VERSION 5.8 ;
BUSBITCHARS "[]" ;
DIVIDERCHAR "/" ;
UNITS
    DATABASE MICRONS 1000 ;
END UNITS

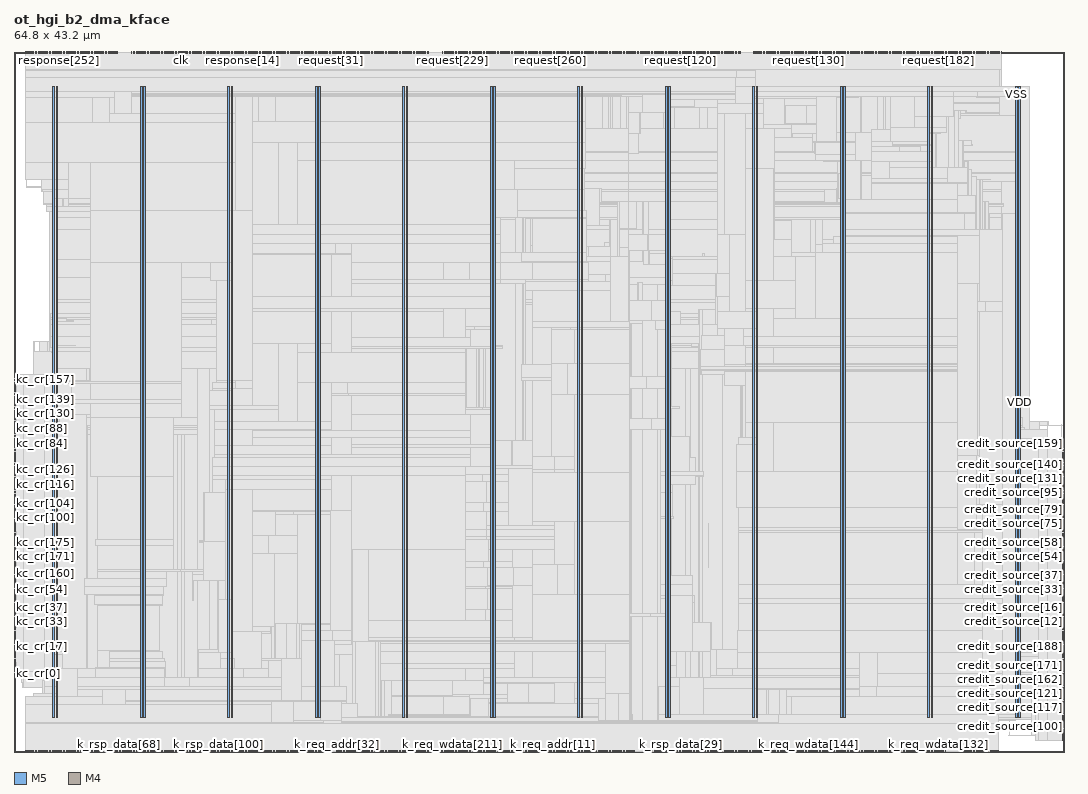
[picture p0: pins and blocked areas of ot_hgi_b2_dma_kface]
MACRO ot_hgi_b2_dma_kface
  FOREIGN ot_hgi_b2_dma_kface 0 0 ;
  CLASS BLOCK ;
  SIZE 64.8 BY 43.2 ;
  PIN clk
    DIRECTION INPUT ;
    USE SIGNAL ;
    PORT
      LAYER M5 ;
        RECT  10.32 43.116 10.344 43.2 ;
    END
  END clk
  PIN credit_source[0]
    DIRECTION INPUT ;
    USE SIGNAL ;
    PORT
      LAYER M4 ;
        RECT  64.716 6.864 64.8 6.888 ;
    END
  END credit_source[0]
  PIN credit_source[100]
    DIRECTION INPUT ;
    USE SIGNAL ;
    PORT
      LAYER M4 ;
        RECT  64.716 1.104 64.8 1.128 ;
    END
  END credit_source[100]
  PIN credit_source[101]
    DIRECTION INPUT ;
    USE SIGNAL ;
    PORT
      LAYER M4 ;
        RECT  64.716 1.2 64.8 1.224 ;
    END
  END credit_source[101]
  PIN credit_source[102]
    DIRECTION INPUT ;
    USE SIGNAL ;
    PORT
      LAYER M4 ;
        RECT  64.716 1.296 64.8 1.32 ;
    END
  END credit_source[102]
  PIN credit_source[103]
    DIRECTION INPUT ;
    USE SIGNAL ;
    PORT
      LAYER M4 ;
        RECT  64.716 1.392 64.8 1.416 ;
    END
  END credit_source[103]
  PIN credit_source[104]
    DIRECTION INPUT ;
    USE SIGNAL ;
    PORT
      LAYER M4 ;
        RECT  64.716 1.488 64.8 1.512 ;
    END
  END credit_source[104]
  PIN credit_source[105]
    DIRECTION INPUT ;
    USE SIGNAL ;
    PORT
      LAYER M4 ;
        RECT  64.716 1.584 64.8 1.608 ;
    END
  END credit_source[105]
  PIN credit_source[106]
    DIRECTION INPUT ;
    USE SIGNAL ;
    PORT
      LAYER M4 ;
        RECT  64.716 1.68 64.8 1.704 ;
    END
  END credit_source[106]
  PIN credit_source[107]
    DIRECTION INPUT ;
    USE SIGNAL ;
    PORT
      LAYER M4 ;
        RECT  64.716 1.776 64.8 1.8 ;
    END
  END credit_source[107]
  PIN credit_source[108]
    DIRECTION INPUT ;
    USE SIGNAL ;
    PORT
      LAYER M4 ;
        RECT  64.716 1.872 64.8 1.896 ;
    END
  END credit_source[108]
  PIN credit_source[109]
    DIRECTION INPUT ;
    USE SIGNAL ;
    PORT
      LAYER M4 ;
        RECT  64.716 1.968 64.8 1.992 ;
    END
  END credit_source[109]
  PIN credit_source[10]
    DIRECTION INPUT ;
    USE SIGNAL ;
    PORT
      LAYER M4 ;
        RECT  64.716 7.824 64.8 7.848 ;
    END
  END credit_source[10]
  PIN credit_source[110]
    DIRECTION INPUT ;
    USE SIGNAL ;
    PORT
      LAYER M4 ;
        RECT  64.716 2.064 64.8 2.088 ;
    END
  END credit_source[110]
  PIN credit_source[111]
    DIRECTION INPUT ;
    USE SIGNAL ;
    PORT
      LAYER M4 ;
        RECT  64.716 2.16 64.8 2.184 ;
    END
  END credit_source[111]
  PIN credit_source[112]
    DIRECTION INPUT ;
    USE SIGNAL ;
    PORT
      LAYER M4 ;
        RECT  64.716 2.256 64.8 2.28 ;
    END
  END credit_source[112]
  PIN credit_source[113]
    DIRECTION INPUT ;
    USE SIGNAL ;
    PORT
      LAYER M4 ;
        RECT  64.716 2.352 64.8 2.376 ;
    END
  END credit_source[113]
  PIN credit_source[114]
    DIRECTION INPUT ;
    USE SIGNAL ;
    PORT
      LAYER M4 ;
        RECT  64.716 2.448 64.8 2.472 ;
    END
  END credit_source[114]
  PIN credit_source[115]
    DIRECTION INPUT ;
    USE SIGNAL ;
    PORT
      LAYER M4 ;
        RECT  64.716 2.544 64.8 2.568 ;
    END
  END credit_source[115]
  PIN credit_source[116]
    DIRECTION INPUT ;
    USE SIGNAL ;
    PORT
      LAYER M4 ;
        RECT  64.716 2.64 64.8 2.664 ;
    END
  END credit_source[116]
  PIN credit_source[117]
    DIRECTION INPUT ;
    USE SIGNAL ;
    PORT
      LAYER M4 ;
        RECT  64.716 2.736 64.8 2.76 ;
    END
  END credit_source[117]
  PIN credit_source[118]
    DIRECTION INPUT ;
    USE SIGNAL ;
    PORT
      LAYER M4 ;
        RECT  64.716 2.832 64.8 2.856 ;
    END
  END credit_source[118]
  PIN credit_source[119]
    DIRECTION INPUT ;
    USE SIGNAL ;
    PORT
      LAYER M4 ;
        RECT  64.716 2.928 64.8 2.952 ;
    END
  END credit_source[119]
  PIN credit_source[11]
    DIRECTION INPUT ;
    USE SIGNAL ;
    PORT
      LAYER M4 ;
        RECT  64.716 7.92 64.8 7.944 ;
    END
  END credit_source[11]
  PIN credit_source[120]
    DIRECTION INPUT ;
    USE SIGNAL ;
    PORT
      LAYER M4 ;
        RECT  64.716 3.024 64.8 3.048 ;
    END
  END credit_source[120]
  PIN credit_source[121]
    DIRECTION INPUT ;
    USE SIGNAL ;
    PORT
      LAYER M4 ;
        RECT  64.716 3.12 64.8 3.144 ;
    END
  END credit_source[121]
  PIN credit_source[122]
    DIRECTION INPUT ;
    USE SIGNAL ;
    PORT
      LAYER M4 ;
        RECT  64.716 3.216 64.8 3.24 ;
    END
  END credit_source[122]
  PIN credit_source[123]
    DIRECTION INPUT ;
    USE SIGNAL ;
    PORT
      LAYER M4 ;
        RECT  64.716 3.312 64.8 3.336 ;
    END
  END credit_source[123]
  PIN credit_source[124]
    DIRECTION INPUT ;
    USE SIGNAL ;
    PORT
      LAYER M4 ;
        RECT  64.716 3.408 64.8 3.432 ;
    END
  END credit_source[124]
  PIN credit_source[125]
    DIRECTION INPUT ;
    USE SIGNAL ;
    PORT
      LAYER M4 ;
        RECT  64.716 3.504 64.8 3.528 ;
    END
  END credit_source[125]
  PIN credit_source[126]
    DIRECTION INPUT ;
    USE SIGNAL ;
    PORT
      LAYER M4 ;
        RECT  64.716 3.6 64.8 3.624 ;
    END
  END credit_source[126]
  PIN credit_source[127]
    DIRECTION INPUT ;
    USE SIGNAL ;
    PORT
      LAYER M4 ;
        RECT  64.716 3.696 64.8 3.72 ;
    END
  END credit_source[127]
  PIN credit_source[128]
    DIRECTION INPUT ;
    USE SIGNAL ;
    PORT
      LAYER M4 ;
        RECT  64.716 16.08 64.8 16.104 ;
    END
  END credit_source[128]
  PIN credit_source[129]
    DIRECTION INPUT ;
    USE SIGNAL ;
    PORT
      LAYER M4 ;
        RECT  64.716 16.176 64.8 16.2 ;
    END
  END credit_source[129]
  PIN credit_source[12]
    DIRECTION INPUT ;
    USE SIGNAL ;
    PORT
      LAYER M4 ;
        RECT  64.716 8.016 64.8 8.04 ;
    END
  END credit_source[12]
  PIN credit_source[130]
    DIRECTION INPUT ;
    USE SIGNAL ;
    PORT
      LAYER M4 ;
        RECT  64.716 16.272 64.8 16.296 ;
    END
  END credit_source[130]
  PIN credit_source[131]
    DIRECTION INPUT ;
    USE SIGNAL ;
    PORT
      LAYER M4 ;
        RECT  64.716 16.368 64.8 16.392 ;
    END
  END credit_source[131]
  PIN credit_source[132]
    DIRECTION INPUT ;
    USE SIGNAL ;
    PORT
      LAYER M4 ;
        RECT  64.716 16.464 64.8 16.488 ;
    END
  END credit_source[132]
  PIN credit_source[133]
    DIRECTION INPUT ;
    USE SIGNAL ;
    PORT
      LAYER M4 ;
        RECT  64.716 16.56 64.8 16.584 ;
    END
  END credit_source[133]
  PIN credit_source[134]
    DIRECTION INPUT ;
    USE SIGNAL ;
    PORT
      LAYER M4 ;
        RECT  64.716 16.656 64.8 16.68 ;
    END
  END credit_source[134]
  PIN credit_source[135]
    DIRECTION INPUT ;
    USE SIGNAL ;
    PORT
      LAYER M4 ;
        RECT  64.716 16.752 64.8 16.776 ;
    END
  END credit_source[135]
  PIN credit_source[136]
    DIRECTION INPUT ;
    USE SIGNAL ;
    PORT
      LAYER M4 ;
        RECT  64.716 16.848 64.8 16.872 ;
    END
  END credit_source[136]
  PIN credit_source[137]
    DIRECTION INPUT ;
    USE SIGNAL ;
    PORT
      LAYER M4 ;
        RECT  64.716 16.944 64.8 16.968 ;
    END
  END credit_source[137]
  PIN credit_source[138]
    DIRECTION INPUT ;
    USE SIGNAL ;
    PORT
      LAYER M4 ;
        RECT  64.716 17.04 64.8 17.064 ;
    END
  END credit_source[138]
  PIN credit_source[139]
    DIRECTION INPUT ;
    USE SIGNAL ;
    PORT
      LAYER M4 ;
        RECT  64.716 17.136 64.8 17.16 ;
    END
  END credit_source[139]
  PIN credit_source[13]
    DIRECTION INPUT ;
    USE SIGNAL ;
    PORT
      LAYER M4 ;
        RECT  64.716 8.112 64.8 8.136 ;
    END
  END credit_source[13]
  PIN credit_source[140]
    DIRECTION INPUT ;
    USE SIGNAL ;
    PORT
      LAYER M4 ;
        RECT  64.716 17.232 64.8 17.256 ;
    END
  END credit_source[140]
  PIN credit_source[141]
    DIRECTION INPUT ;
    USE SIGNAL ;
    PORT
      LAYER M4 ;
        RECT  64.716 17.328 64.8 17.352 ;
    END
  END credit_source[141]
  PIN credit_source[142]
    DIRECTION INPUT ;
    USE SIGNAL ;
    PORT
      LAYER M4 ;
        RECT  64.716 17.424 64.8 17.448 ;
    END
  END credit_source[142]
  PIN credit_source[143]
    DIRECTION INPUT ;
    USE SIGNAL ;
    PORT
      LAYER M4 ;
        RECT  64.716 17.52 64.8 17.544 ;
    END
  END credit_source[143]
  PIN credit_source[144]
    DIRECTION INPUT ;
    USE SIGNAL ;
    PORT
      LAYER M4 ;
        RECT  64.716 17.616 64.8 17.64 ;
    END
  END credit_source[144]
  PIN credit_source[145]
    DIRECTION INPUT ;
    USE SIGNAL ;
    PORT
      LAYER M4 ;
        RECT  64.716 17.712 64.8 17.736 ;
    END
  END credit_source[145]
  PIN credit_source[146]
    DIRECTION INPUT ;
    USE SIGNAL ;
    PORT
      LAYER M4 ;
        RECT  64.716 17.808 64.8 17.832 ;
    END
  END credit_source[146]
  PIN credit_source[147]
    DIRECTION INPUT ;
    USE SIGNAL ;
    PORT
      LAYER M4 ;
        RECT  64.716 17.904 64.8 17.928 ;
    END
  END credit_source[147]
  PIN credit_source[148]
    DIRECTION INPUT ;
    USE SIGNAL ;
    PORT
      LAYER M4 ;
        RECT  64.716 18 64.8 18.024 ;
    END
  END credit_source[148]
  PIN credit_source[149]
    DIRECTION INPUT ;
    USE SIGNAL ;
    PORT
      LAYER M4 ;
        RECT  64.716 18.096 64.8 18.12 ;
    END
  END credit_source[149]
  PIN credit_source[14]
    DIRECTION INPUT ;
    USE SIGNAL ;
    PORT
      LAYER M4 ;
        RECT  64.716 8.208 64.8 8.232 ;
    END
  END credit_source[14]
  PIN credit_source[150]
    DIRECTION INPUT ;
    USE SIGNAL ;
    PORT
      LAYER M4 ;
        RECT  64.716 18.192 64.8 18.216 ;
    END
  END credit_source[150]
  PIN credit_source[151]
    DIRECTION INPUT ;
    USE SIGNAL ;
    PORT
      LAYER M4 ;
        RECT  64.716 18.288 64.8 18.312 ;
    END
  END credit_source[151]
  PIN credit_source[152]
    DIRECTION INPUT ;
    USE SIGNAL ;
    PORT
      LAYER M4 ;
        RECT  64.716 18.384 64.8 18.408 ;
    END
  END credit_source[152]
  PIN credit_source[153]
    DIRECTION INPUT ;
    USE SIGNAL ;
    PORT
      LAYER M4 ;
        RECT  64.716 18.48 64.8 18.504 ;
    END
  END credit_source[153]
  PIN credit_source[154]
    DIRECTION INPUT ;
    USE SIGNAL ;
    PORT
      LAYER M4 ;
        RECT  64.716 18.576 64.8 18.6 ;
    END
  END credit_source[154]
  PIN credit_source[155]
    DIRECTION INPUT ;
    USE SIGNAL ;
    PORT
      LAYER M4 ;
        RECT  64.716 18.672 64.8 18.696 ;
    END
  END credit_source[155]
  PIN credit_source[156]
    DIRECTION INPUT ;
    USE SIGNAL ;
    PORT
      LAYER M4 ;
        RECT  64.716 18.768 64.8 18.792 ;
    END
  END credit_source[156]
  PIN credit_source[157]
    DIRECTION INPUT ;
    USE SIGNAL ;
    PORT
      LAYER M4 ;
        RECT  64.716 18.864 64.8 18.888 ;
    END
  END credit_source[157]
  PIN credit_source[158]
    DIRECTION INPUT ;
    USE SIGNAL ;
    PORT
      LAYER M4 ;
        RECT  64.716 18.96 64.8 18.984 ;
    END
  END credit_source[158]
  PIN credit_source[159]
    DIRECTION INPUT ;
    USE SIGNAL ;
    PORT
      LAYER M4 ;
        RECT  64.716 19.056 64.8 19.08 ;
    END
  END credit_source[159]
  PIN credit_source[15]
    DIRECTION INPUT ;
    USE SIGNAL ;
    PORT
      LAYER M4 ;
        RECT  64.716 8.304 64.8 8.328 ;
    END
  END credit_source[15]
  PIN credit_source[160]
    DIRECTION INPUT ;
    USE SIGNAL ;
    PORT
      LAYER M4 ;
        RECT  64.716 3.792 64.8 3.816 ;
    END
  END credit_source[160]
  PIN credit_source[161]
    DIRECTION INPUT ;
    USE SIGNAL ;
    PORT
      LAYER M4 ;
        RECT  64.716 3.888 64.8 3.912 ;
    END
  END credit_source[161]
  PIN credit_source[162]
    DIRECTION INPUT ;
    USE SIGNAL ;
    PORT
      LAYER M4 ;
        RECT  64.716 3.984 64.8 4.008 ;
    END
  END credit_source[162]
  PIN credit_source[163]
    DIRECTION INPUT ;
    USE SIGNAL ;
    PORT
      LAYER M4 ;
        RECT  64.716 4.08 64.8 4.104 ;
    END
  END credit_source[163]
  PIN credit_source[164]
    DIRECTION INPUT ;
    USE SIGNAL ;
    PORT
      LAYER M4 ;
        RECT  64.716 4.176 64.8 4.2 ;
    END
  END credit_source[164]
  PIN credit_source[165]
    DIRECTION INPUT ;
    USE SIGNAL ;
    PORT
      LAYER M4 ;
        RECT  64.716 4.272 64.8 4.296 ;
    END
  END credit_source[165]
  PIN credit_source[166]
    DIRECTION INPUT ;
    USE SIGNAL ;
    PORT
      LAYER M4 ;
        RECT  64.716 4.368 64.8 4.392 ;
    END
  END credit_source[166]
  PIN credit_source[167]
    DIRECTION INPUT ;
    USE SIGNAL ;
    PORT
      LAYER M4 ;
        RECT  64.716 4.464 64.8 4.488 ;
    END
  END credit_source[167]
  PIN credit_source[168]
    DIRECTION INPUT ;
    USE SIGNAL ;
    PORT
      LAYER M4 ;
        RECT  64.716 4.56 64.8 4.584 ;
    END
  END credit_source[168]
  PIN credit_source[169]
    DIRECTION INPUT ;
    USE SIGNAL ;
    PORT
      LAYER M4 ;
        RECT  64.716 4.656 64.8 4.68 ;
    END
  END credit_source[169]
  PIN credit_source[16]
    DIRECTION INPUT ;
    USE SIGNAL ;
    PORT
      LAYER M4 ;
        RECT  64.716 8.4 64.8 8.424 ;
    END
  END credit_source[16]
  PIN credit_source[170]
    DIRECTION INPUT ;
    USE SIGNAL ;
    PORT
      LAYER M4 ;
        RECT  64.716 4.752 64.8 4.776 ;
    END
  END credit_source[170]
  PIN credit_source[171]
    DIRECTION INPUT ;
    USE SIGNAL ;
    PORT
      LAYER M4 ;
        RECT  64.716 4.848 64.8 4.872 ;
    END
  END credit_source[171]
  PIN credit_source[172]
    DIRECTION INPUT ;
    USE SIGNAL ;
    PORT
      LAYER M4 ;
        RECT  64.716 4.944 64.8 4.968 ;
    END
  END credit_source[172]
  PIN credit_source[173]
    DIRECTION INPUT ;
    USE SIGNAL ;
    PORT
      LAYER M4 ;
        RECT  64.716 5.04 64.8 5.064 ;
    END
  END credit_source[173]
  PIN credit_source[174]
    DIRECTION INPUT ;
    USE SIGNAL ;
    PORT
      LAYER M4 ;
        RECT  64.716 5.136 64.8 5.16 ;
    END
  END credit_source[174]
  PIN credit_source[175]
    DIRECTION INPUT ;
    USE SIGNAL ;
    PORT
      LAYER M4 ;
        RECT  64.716 5.232 64.8 5.256 ;
    END
  END credit_source[175]
  PIN credit_source[176]
    DIRECTION INPUT ;
    USE SIGNAL ;
    PORT
      LAYER M4 ;
        RECT  64.716 5.328 64.8 5.352 ;
    END
  END credit_source[176]
  PIN credit_source[177]
    DIRECTION INPUT ;
    USE SIGNAL ;
    PORT
      LAYER M4 ;
        RECT  64.716 5.424 64.8 5.448 ;
    END
  END credit_source[177]
  PIN credit_source[178]
    DIRECTION INPUT ;
    USE SIGNAL ;
    PORT
      LAYER M4 ;
        RECT  64.716 5.52 64.8 5.544 ;
    END
  END credit_source[178]
  PIN credit_source[179]
    DIRECTION INPUT ;
    USE SIGNAL ;
    PORT
      LAYER M4 ;
        RECT  64.716 5.616 64.8 5.64 ;
    END
  END credit_source[179]
  PIN credit_source[17]
    DIRECTION INPUT ;
    USE SIGNAL ;
    PORT
      LAYER M4 ;
        RECT  64.716 8.496 64.8 8.52 ;
    END
  END credit_source[17]
  PIN credit_source[180]
    DIRECTION INPUT ;
    USE SIGNAL ;
    PORT
      LAYER M4 ;
        RECT  64.716 5.712 64.8 5.736 ;
    END
  END credit_source[180]
  PIN credit_source[181]
    DIRECTION INPUT ;
    USE SIGNAL ;
    PORT
      LAYER M4 ;
        RECT  64.716 5.808 64.8 5.832 ;
    END
  END credit_source[181]
  PIN credit_source[182]
    DIRECTION INPUT ;
    USE SIGNAL ;
    PORT
      LAYER M4 ;
        RECT  64.716 5.904 64.8 5.928 ;
    END
  END credit_source[182]
  PIN credit_source[183]
    DIRECTION INPUT ;
    USE SIGNAL ;
    PORT
      LAYER M4 ;
        RECT  64.716 6 64.8 6.024 ;
    END
  END credit_source[183]
  PIN credit_source[184]
    DIRECTION INPUT ;
    USE SIGNAL ;
    PORT
      LAYER M4 ;
        RECT  64.716 6.096 64.8 6.12 ;
    END
  END credit_source[184]
  PIN credit_source[185]
    DIRECTION INPUT ;
    USE SIGNAL ;
    PORT
      LAYER M4 ;
        RECT  64.716 6.192 64.8 6.216 ;
    END
  END credit_source[185]
  PIN credit_source[186]
    DIRECTION INPUT ;
    USE SIGNAL ;
    PORT
      LAYER M4 ;
        RECT  64.716 6.288 64.8 6.312 ;
    END
  END credit_source[186]
  PIN credit_source[187]
    DIRECTION INPUT ;
    USE SIGNAL ;
    PORT
      LAYER M4 ;
        RECT  64.716 6.384 64.8 6.408 ;
    END
  END credit_source[187]
  PIN credit_source[188]
    DIRECTION INPUT ;
    USE SIGNAL ;
    PORT
      LAYER M4 ;
        RECT  64.716 6.48 64.8 6.504 ;
    END
  END credit_source[188]
  PIN credit_source[189]
    DIRECTION INPUT ;
    USE SIGNAL ;
    PORT
      LAYER M4 ;
        RECT  64.716 6.576 64.8 6.6 ;
    END
  END credit_source[189]
  PIN credit_source[18]
    DIRECTION INPUT ;
    USE SIGNAL ;
    PORT
      LAYER M4 ;
        RECT  64.716 8.592 64.8 8.616 ;
    END
  END credit_source[18]
  PIN credit_source[190]
    DIRECTION INPUT ;
    USE SIGNAL ;
    PORT
      LAYER M4 ;
        RECT  64.716 6.672 64.8 6.696 ;
    END
  END credit_source[190]
  PIN credit_source[191]
    DIRECTION INPUT ;
    USE SIGNAL ;
    PORT
      LAYER M4 ;
        RECT  64.716 6.768 64.8 6.792 ;
    END
  END credit_source[191]
  PIN credit_source[19]
    DIRECTION INPUT ;
    USE SIGNAL ;
    PORT
      LAYER M4 ;
        RECT  64.716 8.688 64.8 8.712 ;
    END
  END credit_source[19]
  PIN credit_source[1]
    DIRECTION INPUT ;
    USE SIGNAL ;
    PORT
      LAYER M4 ;
        RECT  64.716 6.96 64.8 6.984 ;
    END
  END credit_source[1]
  PIN credit_source[20]
    DIRECTION INPUT ;
    USE SIGNAL ;
    PORT
      LAYER M4 ;
        RECT  64.716 8.784 64.8 8.808 ;
    END
  END credit_source[20]
  PIN credit_source[21]
    DIRECTION INPUT ;
    USE SIGNAL ;
    PORT
      LAYER M4 ;
        RECT  64.716 8.88 64.8 8.904 ;
    END
  END credit_source[21]
  PIN credit_source[22]
    DIRECTION INPUT ;
    USE SIGNAL ;
    PORT
      LAYER M4 ;
        RECT  64.716 8.976 64.8 9 ;
    END
  END credit_source[22]
  PIN credit_source[23]
    DIRECTION INPUT ;
    USE SIGNAL ;
    PORT
      LAYER M4 ;
        RECT  64.716 9.072 64.8 9.096 ;
    END
  END credit_source[23]
  PIN credit_source[24]
    DIRECTION INPUT ;
    USE SIGNAL ;
    PORT
      LAYER M4 ;
        RECT  64.716 9.168 64.8 9.192 ;
    END
  END credit_source[24]
  PIN credit_source[25]
    DIRECTION INPUT ;
    USE SIGNAL ;
    PORT
      LAYER M4 ;
        RECT  64.716 9.264 64.8 9.288 ;
    END
  END credit_source[25]
  PIN credit_source[26]
    DIRECTION INPUT ;
    USE SIGNAL ;
    PORT
      LAYER M4 ;
        RECT  64.716 9.36 64.8 9.384 ;
    END
  END credit_source[26]
  PIN credit_source[27]
    DIRECTION INPUT ;
    USE SIGNAL ;
    PORT
      LAYER M4 ;
        RECT  64.716 9.456 64.8 9.48 ;
    END
  END credit_source[27]
  PIN credit_source[28]
    DIRECTION INPUT ;
    USE SIGNAL ;
    PORT
      LAYER M4 ;
        RECT  64.716 9.552 64.8 9.576 ;
    END
  END credit_source[28]
  PIN credit_source[29]
    DIRECTION INPUT ;
    USE SIGNAL ;
    PORT
      LAYER M4 ;
        RECT  64.716 9.648 64.8 9.672 ;
    END
  END credit_source[29]
  PIN credit_source[2]
    DIRECTION INPUT ;
    USE SIGNAL ;
    PORT
      LAYER M4 ;
        RECT  64.716 7.056 64.8 7.08 ;
    END
  END credit_source[2]
  PIN credit_source[30]
    DIRECTION INPUT ;
    USE SIGNAL ;
    PORT
      LAYER M4 ;
        RECT  64.716 9.744 64.8 9.768 ;
    END
  END credit_source[30]
  PIN credit_source[31]
    DIRECTION INPUT ;
    USE SIGNAL ;
    PORT
      LAYER M4 ;
        RECT  64.716 9.84 64.8 9.864 ;
    END
  END credit_source[31]
  PIN credit_source[32]
    DIRECTION INPUT ;
    USE SIGNAL ;
    PORT
      LAYER M4 ;
        RECT  64.716 9.936 64.8 9.96 ;
    END
  END credit_source[32]
  PIN credit_source[33]
    DIRECTION INPUT ;
    USE SIGNAL ;
    PORT
      LAYER M4 ;
        RECT  64.716 10.032 64.8 10.056 ;
    END
  END credit_source[33]
  PIN credit_source[34]
    DIRECTION INPUT ;
    USE SIGNAL ;
    PORT
      LAYER M4 ;
        RECT  64.716 10.128 64.8 10.152 ;
    END
  END credit_source[34]
  PIN credit_source[35]
    DIRECTION INPUT ;
    USE SIGNAL ;
    PORT
      LAYER M4 ;
        RECT  64.716 10.224 64.8 10.248 ;
    END
  END credit_source[35]
  PIN credit_source[36]
    DIRECTION INPUT ;
    USE SIGNAL ;
    PORT
      LAYER M4 ;
        RECT  64.716 10.32 64.8 10.344 ;
    END
  END credit_source[36]
  PIN credit_source[37]
    DIRECTION INPUT ;
    USE SIGNAL ;
    PORT
      LAYER M4 ;
        RECT  64.716 10.416 64.8 10.44 ;
    END
  END credit_source[37]
  PIN credit_source[38]
    DIRECTION INPUT ;
    USE SIGNAL ;
    PORT
      LAYER M4 ;
        RECT  64.716 10.512 64.8 10.536 ;
    END
  END credit_source[38]
  PIN credit_source[39]
    DIRECTION INPUT ;
    USE SIGNAL ;
    PORT
      LAYER M4 ;
        RECT  64.716 10.608 64.8 10.632 ;
    END
  END credit_source[39]
  PIN credit_source[3]
    DIRECTION INPUT ;
    USE SIGNAL ;
    PORT
      LAYER M4 ;
        RECT  64.716 7.152 64.8 7.176 ;
    END
  END credit_source[3]
  PIN credit_source[40]
    DIRECTION INPUT ;
    USE SIGNAL ;
    PORT
      LAYER M4 ;
        RECT  64.716 10.704 64.8 10.728 ;
    END
  END credit_source[40]
  PIN credit_source[41]
    DIRECTION INPUT ;
    USE SIGNAL ;
    PORT
      LAYER M4 ;
        RECT  64.716 10.8 64.8 10.824 ;
    END
  END credit_source[41]
  PIN credit_source[42]
    DIRECTION INPUT ;
    USE SIGNAL ;
    PORT
      LAYER M4 ;
        RECT  64.716 10.896 64.8 10.92 ;
    END
  END credit_source[42]
  PIN credit_source[43]
    DIRECTION INPUT ;
    USE SIGNAL ;
    PORT
      LAYER M4 ;
        RECT  64.716 10.992 64.8 11.016 ;
    END
  END credit_source[43]
  PIN credit_source[44]
    DIRECTION INPUT ;
    USE SIGNAL ;
    PORT
      LAYER M4 ;
        RECT  64.716 11.088 64.8 11.112 ;
    END
  END credit_source[44]
  PIN credit_source[45]
    DIRECTION INPUT ;
    USE SIGNAL ;
    PORT
      LAYER M4 ;
        RECT  64.716 11.184 64.8 11.208 ;
    END
  END credit_source[45]
  PIN credit_source[46]
    DIRECTION INPUT ;
    USE SIGNAL ;
    PORT
      LAYER M4 ;
        RECT  64.716 11.28 64.8 11.304 ;
    END
  END credit_source[46]
  PIN credit_source[47]
    DIRECTION INPUT ;
    USE SIGNAL ;
    PORT
      LAYER M4 ;
        RECT  64.716 11.376 64.8 11.4 ;
    END
  END credit_source[47]
  PIN credit_source[48]
    DIRECTION INPUT ;
    USE SIGNAL ;
    PORT
      LAYER M4 ;
        RECT  64.716 11.472 64.8 11.496 ;
    END
  END credit_source[48]
  PIN credit_source[49]
    DIRECTION INPUT ;
    USE SIGNAL ;
    PORT
      LAYER M4 ;
        RECT  64.716 11.568 64.8 11.592 ;
    END
  END credit_source[49]
  PIN credit_source[4]
    DIRECTION INPUT ;
    USE SIGNAL ;
    PORT
      LAYER M4 ;
        RECT  64.716 7.248 64.8 7.272 ;
    END
  END credit_source[4]
  PIN credit_source[50]
    DIRECTION INPUT ;
    USE SIGNAL ;
    PORT
      LAYER M4 ;
        RECT  64.716 11.664 64.8 11.688 ;
    END
  END credit_source[50]
  PIN credit_source[51]
    DIRECTION INPUT ;
    USE SIGNAL ;
    PORT
      LAYER M4 ;
        RECT  64.716 11.76 64.8 11.784 ;
    END
  END credit_source[51]
  PIN credit_source[52]
    DIRECTION INPUT ;
    USE SIGNAL ;
    PORT
      LAYER M4 ;
        RECT  64.716 11.856 64.8 11.88 ;
    END
  END credit_source[52]
  PIN credit_source[53]
    DIRECTION INPUT ;
    USE SIGNAL ;
    PORT
      LAYER M4 ;
        RECT  64.716 11.952 64.8 11.976 ;
    END
  END credit_source[53]
  PIN credit_source[54]
    DIRECTION INPUT ;
    USE SIGNAL ;
    PORT
      LAYER M4 ;
        RECT  64.716 12.048 64.8 12.072 ;
    END
  END credit_source[54]
  PIN credit_source[55]
    DIRECTION INPUT ;
    USE SIGNAL ;
    PORT
      LAYER M4 ;
        RECT  64.716 12.144 64.8 12.168 ;
    END
  END credit_source[55]
  PIN credit_source[56]
    DIRECTION INPUT ;
    USE SIGNAL ;
    PORT
      LAYER M4 ;
        RECT  64.716 12.24 64.8 12.264 ;
    END
  END credit_source[56]
  PIN credit_source[57]
    DIRECTION INPUT ;
    USE SIGNAL ;
    PORT
      LAYER M4 ;
        RECT  64.716 12.336 64.8 12.36 ;
    END
  END credit_source[57]
  PIN credit_source[58]
    DIRECTION INPUT ;
    USE SIGNAL ;
    PORT
      LAYER M4 ;
        RECT  64.716 12.432 64.8 12.456 ;
    END
  END credit_source[58]
  PIN credit_source[59]
    DIRECTION INPUT ;
    USE SIGNAL ;
    PORT
      LAYER M4 ;
        RECT  64.716 12.528 64.8 12.552 ;
    END
  END credit_source[59]
  PIN credit_source[5]
    DIRECTION INPUT ;
    USE SIGNAL ;
    PORT
      LAYER M4 ;
        RECT  64.716 7.344 64.8 7.368 ;
    END
  END credit_source[5]
  PIN credit_source[60]
    DIRECTION INPUT ;
    USE SIGNAL ;
    PORT
      LAYER M4 ;
        RECT  64.716 12.624 64.8 12.648 ;
    END
  END credit_source[60]
  PIN credit_source[61]
    DIRECTION INPUT ;
    USE SIGNAL ;
    PORT
      LAYER M4 ;
        RECT  64.716 12.72 64.8 12.744 ;
    END
  END credit_source[61]
  PIN credit_source[62]
    DIRECTION INPUT ;
    USE SIGNAL ;
    PORT
      LAYER M4 ;
        RECT  64.716 12.816 64.8 12.84 ;
    END
  END credit_source[62]
  PIN credit_source[63]
    DIRECTION INPUT ;
    USE SIGNAL ;
    PORT
      LAYER M4 ;
        RECT  64.716 12.912 64.8 12.936 ;
    END
  END credit_source[63]
  PIN credit_source[64]
    DIRECTION INPUT ;
    USE SIGNAL ;
    PORT
      LAYER M4 ;
        RECT  64.716 13.008 64.8 13.032 ;
    END
  END credit_source[64]
  PIN credit_source[65]
    DIRECTION INPUT ;
    USE SIGNAL ;
    PORT
      LAYER M4 ;
        RECT  64.716 13.104 64.8 13.128 ;
    END
  END credit_source[65]
  PIN credit_source[66]
    DIRECTION INPUT ;
    USE SIGNAL ;
    PORT
      LAYER M4 ;
        RECT  64.716 13.2 64.8 13.224 ;
    END
  END credit_source[66]
  PIN credit_source[67]
    DIRECTION INPUT ;
    USE SIGNAL ;
    PORT
      LAYER M4 ;
        RECT  64.716 13.296 64.8 13.32 ;
    END
  END credit_source[67]
  PIN credit_source[68]
    DIRECTION INPUT ;
    USE SIGNAL ;
    PORT
      LAYER M4 ;
        RECT  64.716 13.392 64.8 13.416 ;
    END
  END credit_source[68]
  PIN credit_source[69]
    DIRECTION INPUT ;
    USE SIGNAL ;
    PORT
      LAYER M4 ;
        RECT  64.716 13.488 64.8 13.512 ;
    END
  END credit_source[69]
  PIN credit_source[6]
    DIRECTION INPUT ;
    USE SIGNAL ;
    PORT
      LAYER M4 ;
        RECT  64.716 7.44 64.8 7.464 ;
    END
  END credit_source[6]
  PIN credit_source[70]
    DIRECTION INPUT ;
    USE SIGNAL ;
    PORT
      LAYER M4 ;
        RECT  64.716 13.584 64.8 13.608 ;
    END
  END credit_source[70]
  PIN credit_source[71]
    DIRECTION INPUT ;
    USE SIGNAL ;
    PORT
      LAYER M4 ;
        RECT  64.716 13.68 64.8 13.704 ;
    END
  END credit_source[71]
  PIN credit_source[72]
    DIRECTION INPUT ;
    USE SIGNAL ;
    PORT
      LAYER M4 ;
        RECT  64.716 13.776 64.8 13.8 ;
    END
  END credit_source[72]
  PIN credit_source[73]
    DIRECTION INPUT ;
    USE SIGNAL ;
    PORT
      LAYER M4 ;
        RECT  64.716 13.872 64.8 13.896 ;
    END
  END credit_source[73]
  PIN credit_source[74]
    DIRECTION INPUT ;
    USE SIGNAL ;
    PORT
      LAYER M4 ;
        RECT  64.716 13.968 64.8 13.992 ;
    END
  END credit_source[74]
  PIN credit_source[75]
    DIRECTION INPUT ;
    USE SIGNAL ;
    PORT
      LAYER M4 ;
        RECT  64.716 14.064 64.8 14.088 ;
    END
  END credit_source[75]
  PIN credit_source[76]
    DIRECTION INPUT ;
    USE SIGNAL ;
    PORT
      LAYER M4 ;
        RECT  64.716 14.16 64.8 14.184 ;
    END
  END credit_source[76]
  PIN credit_source[77]
    DIRECTION INPUT ;
    USE SIGNAL ;
    PORT
      LAYER M4 ;
        RECT  64.716 14.256 64.8 14.28 ;
    END
  END credit_source[77]
  PIN credit_source[78]
    DIRECTION INPUT ;
    USE SIGNAL ;
    PORT
      LAYER M4 ;
        RECT  64.716 14.352 64.8 14.376 ;
    END
  END credit_source[78]
  PIN credit_source[79]
    DIRECTION INPUT ;
    USE SIGNAL ;
    PORT
      LAYER M4 ;
        RECT  64.716 14.448 64.8 14.472 ;
    END
  END credit_source[79]
  PIN credit_source[7]
    DIRECTION INPUT ;
    USE SIGNAL ;
    PORT
      LAYER M4 ;
        RECT  64.716 7.536 64.8 7.56 ;
    END
  END credit_source[7]
  PIN credit_source[80]
    DIRECTION INPUT ;
    USE SIGNAL ;
    PORT
      LAYER M4 ;
        RECT  64.716 14.544 64.8 14.568 ;
    END
  END credit_source[80]
  PIN credit_source[81]
    DIRECTION INPUT ;
    USE SIGNAL ;
    PORT
      LAYER M4 ;
        RECT  64.716 14.64 64.8 14.664 ;
    END
  END credit_source[81]
  PIN credit_source[82]
    DIRECTION INPUT ;
    USE SIGNAL ;
    PORT
      LAYER M4 ;
        RECT  64.716 14.736 64.8 14.76 ;
    END
  END credit_source[82]
  PIN credit_source[83]
    DIRECTION INPUT ;
    USE SIGNAL ;
    PORT
      LAYER M4 ;
        RECT  64.716 14.832 64.8 14.856 ;
    END
  END credit_source[83]
  PIN credit_source[84]
    DIRECTION INPUT ;
    USE SIGNAL ;
    PORT
      LAYER M4 ;
        RECT  64.716 14.928 64.8 14.952 ;
    END
  END credit_source[84]
  PIN credit_source[85]
    DIRECTION INPUT ;
    USE SIGNAL ;
    PORT
      LAYER M4 ;
        RECT  64.716 15.024 64.8 15.048 ;
    END
  END credit_source[85]
  PIN credit_source[86]
    DIRECTION INPUT ;
    USE SIGNAL ;
    PORT
      LAYER M4 ;
        RECT  64.716 15.12 64.8 15.144 ;
    END
  END credit_source[86]
  PIN credit_source[87]
    DIRECTION INPUT ;
    USE SIGNAL ;
    PORT
      LAYER M4 ;
        RECT  64.716 15.216 64.8 15.24 ;
    END
  END credit_source[87]
  PIN credit_source[88]
    DIRECTION INPUT ;
    USE SIGNAL ;
    PORT
      LAYER M4 ;
        RECT  64.716 15.312 64.8 15.336 ;
    END
  END credit_source[88]
  PIN credit_source[89]
    DIRECTION INPUT ;
    USE SIGNAL ;
    PORT
      LAYER M4 ;
        RECT  64.716 15.408 64.8 15.432 ;
    END
  END credit_source[89]
  PIN credit_source[8]
    DIRECTION INPUT ;
    USE SIGNAL ;
    PORT
      LAYER M4 ;
        RECT  64.716 7.632 64.8 7.656 ;
    END
  END credit_source[8]
  PIN credit_source[90]
    DIRECTION INPUT ;
    USE SIGNAL ;
    PORT
      LAYER M4 ;
        RECT  64.716 15.504 64.8 15.528 ;
    END
  END credit_source[90]
  PIN credit_source[91]
    DIRECTION INPUT ;
    USE SIGNAL ;
    PORT
      LAYER M4 ;
        RECT  64.716 15.6 64.8 15.624 ;
    END
  END credit_source[91]
  PIN credit_source[92]
    DIRECTION INPUT ;
    USE SIGNAL ;
    PORT
      LAYER M4 ;
        RECT  64.716 15.696 64.8 15.72 ;
    END
  END credit_source[92]
  PIN credit_source[93]
    DIRECTION INPUT ;
    USE SIGNAL ;
    PORT
      LAYER M4 ;
        RECT  64.716 15.792 64.8 15.816 ;
    END
  END credit_source[93]
  PIN credit_source[94]
    DIRECTION INPUT ;
    USE SIGNAL ;
    PORT
      LAYER M4 ;
        RECT  64.716 15.888 64.8 15.912 ;
    END
  END credit_source[94]
  PIN credit_source[95]
    DIRECTION INPUT ;
    USE SIGNAL ;
    PORT
      LAYER M4 ;
        RECT  64.716 15.984 64.8 16.008 ;
    END
  END credit_source[95]
  PIN credit_source[96]
    DIRECTION INPUT ;
    USE SIGNAL ;
    PORT
      LAYER M4 ;
        RECT  64.716 0.72 64.8 0.744 ;
    END
  END credit_source[96]
  PIN credit_source[97]
    DIRECTION INPUT ;
    USE SIGNAL ;
    PORT
      LAYER M4 ;
        RECT  64.716 0.816 64.8 0.84 ;
    END
  END credit_source[97]
  PIN credit_source[98]
    DIRECTION INPUT ;
    USE SIGNAL ;
    PORT
      LAYER M4 ;
        RECT  64.716 0.912 64.8 0.936 ;
    END
  END credit_source[98]
  PIN credit_source[99]
    DIRECTION INPUT ;
    USE SIGNAL ;
    PORT
      LAYER M4 ;
        RECT  64.716 1.008 64.8 1.032 ;
    END
  END credit_source[99]
  PIN credit_source[9]
    DIRECTION INPUT ;
    USE SIGNAL ;
    PORT
      LAYER M4 ;
        RECT  64.716 7.728 64.8 7.752 ;
    END
  END credit_source[9]
  PIN k_req_addr[0]
    DIRECTION OUTPUT ;
    USE SIGNAL ;
    PORT
      LAYER M5 ;
        RECT  32.208 0 32.232 0.084 ;
    END
  END k_req_addr[0]
  PIN k_req_addr[10]
    DIRECTION OUTPUT ;
    USE SIGNAL ;
    PORT
      LAYER M5 ;
        RECT  33.168 0 33.192 0.084 ;
    END
  END k_req_addr[10]
  PIN k_req_addr[11]
    DIRECTION OUTPUT ;
    USE SIGNAL ;
    PORT
      LAYER M5 ;
        RECT  33.264 0 33.288 0.084 ;
    END
  END k_req_addr[11]
  PIN k_req_addr[12]
    DIRECTION OUTPUT ;
    USE SIGNAL ;
    PORT
      LAYER M5 ;
        RECT  33.36 0 33.384 0.084 ;
    END
  END k_req_addr[12]
  PIN k_req_addr[13]
    DIRECTION OUTPUT ;
    USE SIGNAL ;
    PORT
      LAYER M5 ;
        RECT  33.456 0 33.48 0.084 ;
    END
  END k_req_addr[13]
  PIN k_req_addr[14]
    DIRECTION OUTPUT ;
    USE SIGNAL ;
    PORT
      LAYER M5 ;
        RECT  33.552 0 33.576 0.084 ;
    END
  END k_req_addr[14]
  PIN k_req_addr[15]
    DIRECTION OUTPUT ;
    USE SIGNAL ;
    PORT
      LAYER M5 ;
        RECT  33.648 0 33.672 0.084 ;
    END
  END k_req_addr[15]
  PIN k_req_addr[16]
    DIRECTION OUTPUT ;
    USE SIGNAL ;
    PORT
      LAYER M5 ;
        RECT  33.744 0 33.768 0.084 ;
    END
  END k_req_addr[16]
  PIN k_req_addr[17]
    DIRECTION OUTPUT ;
    USE SIGNAL ;
    PORT
      LAYER M5 ;
        RECT  33.84 0 33.864 0.084 ;
    END
  END k_req_addr[17]
  PIN k_req_addr[18]
    DIRECTION OUTPUT ;
    USE SIGNAL ;
    PORT
      LAYER M5 ;
        RECT  33.936 0 33.96 0.084 ;
    END
  END k_req_addr[18]
  PIN k_req_addr[19]
    DIRECTION OUTPUT ;
    USE SIGNAL ;
    PORT
      LAYER M5 ;
        RECT  34.032 0 34.056 0.084 ;
    END
  END k_req_addr[19]
  PIN k_req_addr[1]
    DIRECTION OUTPUT ;
    USE SIGNAL ;
    PORT
      LAYER M5 ;
        RECT  32.304 0 32.328 0.084 ;
    END
  END k_req_addr[1]
  PIN k_req_addr[20]
    DIRECTION OUTPUT ;
    USE SIGNAL ;
    PORT
      LAYER M5 ;
        RECT  34.128 0 34.152 0.084 ;
    END
  END k_req_addr[20]
  PIN k_req_addr[21]
    DIRECTION OUTPUT ;
    USE SIGNAL ;
    PORT
      LAYER M5 ;
        RECT  34.224 0 34.248 0.084 ;
    END
  END k_req_addr[21]
  PIN k_req_addr[22]
    DIRECTION OUTPUT ;
    USE SIGNAL ;
    PORT
      LAYER M5 ;
        RECT  34.32 0 34.344 0.084 ;
    END
  END k_req_addr[22]
  PIN k_req_addr[23]
    DIRECTION OUTPUT ;
    USE SIGNAL ;
    PORT
      LAYER M5 ;
        RECT  34.416 0 34.44 0.084 ;
    END
  END k_req_addr[23]
  PIN k_req_addr[24]
    DIRECTION OUTPUT ;
    USE SIGNAL ;
    PORT
      LAYER M5 ;
        RECT  34.512 0 34.536 0.084 ;
    END
  END k_req_addr[24]
  PIN k_req_addr[25]
    DIRECTION OUTPUT ;
    USE SIGNAL ;
    PORT
      LAYER M5 ;
        RECT  34.608 0 34.632 0.084 ;
    END
  END k_req_addr[25]
  PIN k_req_addr[26]
    DIRECTION OUTPUT ;
    USE SIGNAL ;
    PORT
      LAYER M5 ;
        RECT  34.704 0 34.728 0.084 ;
    END
  END k_req_addr[26]
  PIN k_req_addr[27]
    DIRECTION OUTPUT ;
    USE SIGNAL ;
    PORT
      LAYER M5 ;
        RECT  34.8 0 34.824 0.084 ;
    END
  END k_req_addr[27]
  PIN k_req_addr[28]
    DIRECTION OUTPUT ;
    USE SIGNAL ;
    PORT
      LAYER M5 ;
        RECT  34.896 0 34.92 0.084 ;
    END
  END k_req_addr[28]
  PIN k_req_addr[29]
    DIRECTION OUTPUT ;
    USE SIGNAL ;
    PORT
      LAYER M5 ;
        RECT  34.992 0 35.016 0.084 ;
    END
  END k_req_addr[29]
  PIN k_req_addr[2]
    DIRECTION OUTPUT ;
    USE SIGNAL ;
    PORT
      LAYER M5 ;
        RECT  32.4 0 32.424 0.084 ;
    END
  END k_req_addr[2]
  PIN k_req_addr[30]
    DIRECTION OUTPUT ;
    USE SIGNAL ;
    PORT
      LAYER M5 ;
        RECT  35.088 0 35.112 0.084 ;
    END
  END k_req_addr[30]
  PIN k_req_addr[31]
    DIRECTION OUTPUT ;
    USE SIGNAL ;
    PORT
      LAYER M5 ;
        RECT  35.184 0 35.208 0.084 ;
    END
  END k_req_addr[31]
  PIN k_req_addr[32]
    DIRECTION OUTPUT ;
    USE SIGNAL ;
    PORT
      LAYER M5 ;
        RECT  19.92 0 19.944 0.084 ;
    END
  END k_req_addr[32]
  PIN k_req_addr[33]
    DIRECTION OUTPUT ;
    USE SIGNAL ;
    PORT
      LAYER M5 ;
        RECT  20.016 0 20.04 0.084 ;
    END
  END k_req_addr[33]
  PIN k_req_addr[34]
    DIRECTION OUTPUT ;
    USE SIGNAL ;
    PORT
      LAYER M5 ;
        RECT  20.112 0 20.136 0.084 ;
    END
  END k_req_addr[34]
  PIN k_req_addr[35]
    DIRECTION OUTPUT ;
    USE SIGNAL ;
    PORT
      LAYER M5 ;
        RECT  20.208 0 20.232 0.084 ;
    END
  END k_req_addr[35]
  PIN k_req_addr[36]
    DIRECTION OUTPUT ;
    USE SIGNAL ;
    PORT
      LAYER M5 ;
        RECT  20.304 0 20.328 0.084 ;
    END
  END k_req_addr[36]
  PIN k_req_addr[3]
    DIRECTION OUTPUT ;
    USE SIGNAL ;
    PORT
      LAYER M5 ;
        RECT  32.496 0 32.52 0.084 ;
    END
  END k_req_addr[3]
  PIN k_req_addr[4]
    DIRECTION OUTPUT ;
    USE SIGNAL ;
    PORT
      LAYER M5 ;
        RECT  32.592 0 32.616 0.084 ;
    END
  END k_req_addr[4]
  PIN k_req_addr[5]
    DIRECTION OUTPUT ;
    USE SIGNAL ;
    PORT
      LAYER M5 ;
        RECT  32.688 0 32.712 0.084 ;
    END
  END k_req_addr[5]
  PIN k_req_addr[6]
    DIRECTION OUTPUT ;
    USE SIGNAL ;
    PORT
      LAYER M5 ;
        RECT  32.784 0 32.808 0.084 ;
    END
  END k_req_addr[6]
  PIN k_req_addr[7]
    DIRECTION OUTPUT ;
    USE SIGNAL ;
    PORT
      LAYER M5 ;
        RECT  32.88 0 32.904 0.084 ;
    END
  END k_req_addr[7]
  PIN k_req_addr[8]
    DIRECTION OUTPUT ;
    USE SIGNAL ;
    PORT
      LAYER M5 ;
        RECT  32.976 0 33 0.084 ;
    END
  END k_req_addr[8]
  PIN k_req_addr[9]
    DIRECTION OUTPUT ;
    USE SIGNAL ;
    PORT
      LAYER M5 ;
        RECT  33.072 0 33.096 0.084 ;
    END
  END k_req_addr[9]
  PIN k_req_rdy
    DIRECTION INPUT ;
    USE SIGNAL ;
    PORT
      LAYER M5 ;
        RECT  20.4 0 20.424 0.084 ;
    END
  END k_req_rdy
  PIN k_req_tag[0]
    DIRECTION OUTPUT ;
    USE SIGNAL ;
    PORT
      LAYER M5 ;
        RECT  20.496 0 20.52 0.084 ;
    END
  END k_req_tag[0]
  PIN k_req_tag[10]
    DIRECTION OUTPUT ;
    USE SIGNAL ;
    PORT
      LAYER M5 ;
        RECT  21.456 0 21.48 0.084 ;
    END
  END k_req_tag[10]
  PIN k_req_tag[11]
    DIRECTION OUTPUT ;
    USE SIGNAL ;
    PORT
      LAYER M5 ;
        RECT  21.552 0 21.576 0.084 ;
    END
  END k_req_tag[11]
  PIN k_req_tag[12]
    DIRECTION OUTPUT ;
    USE SIGNAL ;
    PORT
      LAYER M5 ;
        RECT  21.648 0 21.672 0.084 ;
    END
  END k_req_tag[12]
  PIN k_req_tag[13]
    DIRECTION OUTPUT ;
    USE SIGNAL ;
    PORT
      LAYER M5 ;
        RECT  21.744 0 21.768 0.084 ;
    END
  END k_req_tag[13]
  PIN k_req_tag[14]
    DIRECTION OUTPUT ;
    USE SIGNAL ;
    PORT
      LAYER M5 ;
        RECT  21.84 0 21.864 0.084 ;
    END
  END k_req_tag[14]
  PIN k_req_tag[15]
    DIRECTION OUTPUT ;
    USE SIGNAL ;
    PORT
      LAYER M5 ;
        RECT  21.936 0 21.96 0.084 ;
    END
  END k_req_tag[15]
  PIN k_req_tag[1]
    DIRECTION OUTPUT ;
    USE SIGNAL ;
    PORT
      LAYER M5 ;
        RECT  20.592 0 20.616 0.084 ;
    END
  END k_req_tag[1]
  PIN k_req_tag[2]
    DIRECTION OUTPUT ;
    USE SIGNAL ;
    PORT
      LAYER M5 ;
        RECT  20.688 0 20.712 0.084 ;
    END
  END k_req_tag[2]
  PIN k_req_tag[3]
    DIRECTION OUTPUT ;
    USE SIGNAL ;
    PORT
      LAYER M5 ;
        RECT  20.784 0 20.808 0.084 ;
    END
  END k_req_tag[3]
  PIN k_req_tag[4]
    DIRECTION OUTPUT ;
    USE SIGNAL ;
    PORT
      LAYER M5 ;
        RECT  20.88 0 20.904 0.084 ;
    END
  END k_req_tag[4]
  PIN k_req_tag[5]
    DIRECTION OUTPUT ;
    USE SIGNAL ;
    PORT
      LAYER M5 ;
        RECT  20.976 0 21 0.084 ;
    END
  END k_req_tag[5]
  PIN k_req_tag[6]
    DIRECTION OUTPUT ;
    USE SIGNAL ;
    PORT
      LAYER M5 ;
        RECT  21.072 0 21.096 0.084 ;
    END
  END k_req_tag[6]
  PIN k_req_tag[7]
    DIRECTION OUTPUT ;
    USE SIGNAL ;
    PORT
      LAYER M5 ;
        RECT  21.168 0 21.192 0.084 ;
    END
  END k_req_tag[7]
  PIN k_req_tag[8]
    DIRECTION OUTPUT ;
    USE SIGNAL ;
    PORT
      LAYER M5 ;
        RECT  21.264 0 21.288 0.084 ;
    END
  END k_req_tag[8]
  PIN k_req_tag[9]
    DIRECTION OUTPUT ;
    USE SIGNAL ;
    PORT
      LAYER M5 ;
        RECT  21.36 0 21.384 0.084 ;
    END
  END k_req_tag[9]
  PIN k_req_v
    DIRECTION OUTPUT ;
    USE SIGNAL ;
    PORT
      LAYER M5 ;
        RECT  22.032 0 22.056 0.084 ;
    END
  END k_req_v
  PIN k_req_wdata[0]
    DIRECTION OUTPUT ;
    USE SIGNAL ;
    PORT
      LAYER M5 ;
        RECT  22.128 0 22.152 0.084 ;
    END
  END k_req_wdata[0]
  PIN k_req_wdata[100]
    DIRECTION OUTPUT ;
    USE SIGNAL ;
    PORT
      LAYER M5 ;
        RECT  54 0 54.024 0.084 ;
    END
  END k_req_wdata[100]
  PIN k_req_wdata[101]
    DIRECTION OUTPUT ;
    USE SIGNAL ;
    PORT
      LAYER M5 ;
        RECT  54.096 0 54.12 0.084 ;
    END
  END k_req_wdata[101]
  PIN k_req_wdata[102]
    DIRECTION OUTPUT ;
    USE SIGNAL ;
    PORT
      LAYER M5 ;
        RECT  54.192 0 54.216 0.084 ;
    END
  END k_req_wdata[102]
  PIN k_req_wdata[103]
    DIRECTION OUTPUT ;
    USE SIGNAL ;
    PORT
      LAYER M5 ;
        RECT  54.288 0 54.312 0.084 ;
    END
  END k_req_wdata[103]
  PIN k_req_wdata[104]
    DIRECTION OUTPUT ;
    USE SIGNAL ;
    PORT
      LAYER M5 ;
        RECT  54.384 0 54.408 0.084 ;
    END
  END k_req_wdata[104]
  PIN k_req_wdata[105]
    DIRECTION OUTPUT ;
    USE SIGNAL ;
    PORT
      LAYER M5 ;
        RECT  54.48 0 54.504 0.084 ;
    END
  END k_req_wdata[105]
  PIN k_req_wdata[106]
    DIRECTION OUTPUT ;
    USE SIGNAL ;
    PORT
      LAYER M5 ;
        RECT  54.576 0 54.6 0.084 ;
    END
  END k_req_wdata[106]
  PIN k_req_wdata[107]
    DIRECTION OUTPUT ;
    USE SIGNAL ;
    PORT
      LAYER M5 ;
        RECT  54.672 0 54.696 0.084 ;
    END
  END k_req_wdata[107]
  PIN k_req_wdata[108]
    DIRECTION OUTPUT ;
    USE SIGNAL ;
    PORT
      LAYER M5 ;
        RECT  54.768 0 54.792 0.084 ;
    END
  END k_req_wdata[108]
  PIN k_req_wdata[109]
    DIRECTION OUTPUT ;
    USE SIGNAL ;
    PORT
      LAYER M5 ;
        RECT  54.864 0 54.888 0.084 ;
    END
  END k_req_wdata[109]
  PIN k_req_wdata[10]
    DIRECTION OUTPUT ;
    USE SIGNAL ;
    PORT
      LAYER M5 ;
        RECT  23.088 0 23.112 0.084 ;
    END
  END k_req_wdata[10]
  PIN k_req_wdata[110]
    DIRECTION OUTPUT ;
    USE SIGNAL ;
    PORT
      LAYER M5 ;
        RECT  54.96 0 54.984 0.084 ;
    END
  END k_req_wdata[110]
  PIN k_req_wdata[111]
    DIRECTION OUTPUT ;
    USE SIGNAL ;
    PORT
      LAYER M5 ;
        RECT  55.056 0 55.08 0.084 ;
    END
  END k_req_wdata[111]
  PIN k_req_wdata[112]
    DIRECTION OUTPUT ;
    USE SIGNAL ;
    PORT
      LAYER M5 ;
        RECT  55.152 0 55.176 0.084 ;
    END
  END k_req_wdata[112]
  PIN k_req_wdata[113]
    DIRECTION OUTPUT ;
    USE SIGNAL ;
    PORT
      LAYER M5 ;
        RECT  55.248 0 55.272 0.084 ;
    END
  END k_req_wdata[113]
  PIN k_req_wdata[114]
    DIRECTION OUTPUT ;
    USE SIGNAL ;
    PORT
      LAYER M5 ;
        RECT  55.344 0 55.368 0.084 ;
    END
  END k_req_wdata[114]
  PIN k_req_wdata[115]
    DIRECTION OUTPUT ;
    USE SIGNAL ;
    PORT
      LAYER M5 ;
        RECT  55.44 0 55.464 0.084 ;
    END
  END k_req_wdata[115]
  PIN k_req_wdata[116]
    DIRECTION OUTPUT ;
    USE SIGNAL ;
    PORT
      LAYER M5 ;
        RECT  55.536 0 55.56 0.084 ;
    END
  END k_req_wdata[116]
  PIN k_req_wdata[117]
    DIRECTION OUTPUT ;
    USE SIGNAL ;
    PORT
      LAYER M5 ;
        RECT  55.632 0 55.656 0.084 ;
    END
  END k_req_wdata[117]
  PIN k_req_wdata[118]
    DIRECTION OUTPUT ;
    USE SIGNAL ;
    PORT
      LAYER M5 ;
        RECT  55.728 0 55.752 0.084 ;
    END
  END k_req_wdata[118]
  PIN k_req_wdata[119]
    DIRECTION OUTPUT ;
    USE SIGNAL ;
    PORT
      LAYER M5 ;
        RECT  55.824 0 55.848 0.084 ;
    END
  END k_req_wdata[119]
  PIN k_req_wdata[11]
    DIRECTION OUTPUT ;
    USE SIGNAL ;
    PORT
      LAYER M5 ;
        RECT  23.184 0 23.208 0.084 ;
    END
  END k_req_wdata[11]
  PIN k_req_wdata[120]
    DIRECTION OUTPUT ;
    USE SIGNAL ;
    PORT
      LAYER M5 ;
        RECT  55.92 0 55.944 0.084 ;
    END
  END k_req_wdata[120]
  PIN k_req_wdata[121]
    DIRECTION OUTPUT ;
    USE SIGNAL ;
    PORT
      LAYER M5 ;
        RECT  56.016 0 56.04 0.084 ;
    END
  END k_req_wdata[121]
  PIN k_req_wdata[122]
    DIRECTION OUTPUT ;
    USE SIGNAL ;
    PORT
      LAYER M5 ;
        RECT  56.112 0 56.136 0.084 ;
    END
  END k_req_wdata[122]
  PIN k_req_wdata[123]
    DIRECTION OUTPUT ;
    USE SIGNAL ;
    PORT
      LAYER M5 ;
        RECT  56.208 0 56.232 0.084 ;
    END
  END k_req_wdata[123]
  PIN k_req_wdata[124]
    DIRECTION OUTPUT ;
    USE SIGNAL ;
    PORT
      LAYER M5 ;
        RECT  56.304 0 56.328 0.084 ;
    END
  END k_req_wdata[124]
  PIN k_req_wdata[125]
    DIRECTION OUTPUT ;
    USE SIGNAL ;
    PORT
      LAYER M5 ;
        RECT  56.4 0 56.424 0.084 ;
    END
  END k_req_wdata[125]
  PIN k_req_wdata[126]
    DIRECTION OUTPUT ;
    USE SIGNAL ;
    PORT
      LAYER M5 ;
        RECT  56.496 0 56.52 0.084 ;
    END
  END k_req_wdata[126]
  PIN k_req_wdata[127]
    DIRECTION OUTPUT ;
    USE SIGNAL ;
    PORT
      LAYER M5 ;
        RECT  56.592 0 56.616 0.084 ;
    END
  END k_req_wdata[127]
  PIN k_req_wdata[128]
    DIRECTION OUTPUT ;
    USE SIGNAL ;
    PORT
      LAYER M5 ;
        RECT  56.688 0 56.712 0.084 ;
    END
  END k_req_wdata[128]
  PIN k_req_wdata[129]
    DIRECTION OUTPUT ;
    USE SIGNAL ;
    PORT
      LAYER M5 ;
        RECT  56.784 0 56.808 0.084 ;
    END
  END k_req_wdata[129]
  PIN k_req_wdata[12]
    DIRECTION OUTPUT ;
    USE SIGNAL ;
    PORT
      LAYER M5 ;
        RECT  23.28 0 23.304 0.084 ;
    END
  END k_req_wdata[12]
  PIN k_req_wdata[130]
    DIRECTION OUTPUT ;
    USE SIGNAL ;
    PORT
      LAYER M5 ;
        RECT  56.88 0 56.904 0.084 ;
    END
  END k_req_wdata[130]
  PIN k_req_wdata[131]
    DIRECTION OUTPUT ;
    USE SIGNAL ;
    PORT
      LAYER M5 ;
        RECT  56.976 0 57 0.084 ;
    END
  END k_req_wdata[131]
  PIN k_req_wdata[132]
    DIRECTION OUTPUT ;
    USE SIGNAL ;
    PORT
      LAYER M5 ;
        RECT  57.072 0 57.096 0.084 ;
    END
  END k_req_wdata[132]
  PIN k_req_wdata[133]
    DIRECTION OUTPUT ;
    USE SIGNAL ;
    PORT
      LAYER M5 ;
        RECT  57.168 0 57.192 0.084 ;
    END
  END k_req_wdata[133]
  PIN k_req_wdata[134]
    DIRECTION OUTPUT ;
    USE SIGNAL ;
    PORT
      LAYER M5 ;
        RECT  57.264 0 57.288 0.084 ;
    END
  END k_req_wdata[134]
  PIN k_req_wdata[135]
    DIRECTION OUTPUT ;
    USE SIGNAL ;
    PORT
      LAYER M5 ;
        RECT  57.36 0 57.384 0.084 ;
    END
  END k_req_wdata[135]
  PIN k_req_wdata[136]
    DIRECTION OUTPUT ;
    USE SIGNAL ;
    PORT
      LAYER M5 ;
        RECT  57.456 0 57.48 0.084 ;
    END
  END k_req_wdata[136]
  PIN k_req_wdata[137]
    DIRECTION OUTPUT ;
    USE SIGNAL ;
    PORT
      LAYER M5 ;
        RECT  48.336 0 48.36 0.084 ;
    END
  END k_req_wdata[137]
  PIN k_req_wdata[138]
    DIRECTION OUTPUT ;
    USE SIGNAL ;
    PORT
      LAYER M5 ;
        RECT  48.432 0 48.456 0.084 ;
    END
  END k_req_wdata[138]
  PIN k_req_wdata[139]
    DIRECTION OUTPUT ;
    USE SIGNAL ;
    PORT
      LAYER M5 ;
        RECT  48.528 0 48.552 0.084 ;
    END
  END k_req_wdata[139]
  PIN k_req_wdata[13]
    DIRECTION OUTPUT ;
    USE SIGNAL ;
    PORT
      LAYER M5 ;
        RECT  23.376 0 23.4 0.084 ;
    END
  END k_req_wdata[13]
  PIN k_req_wdata[140]
    DIRECTION OUTPUT ;
    USE SIGNAL ;
    PORT
      LAYER M5 ;
        RECT  48.624 0 48.648 0.084 ;
    END
  END k_req_wdata[140]
  PIN k_req_wdata[141]
    DIRECTION OUTPUT ;
    USE SIGNAL ;
    PORT
      LAYER M5 ;
        RECT  48.72 0 48.744 0.084 ;
    END
  END k_req_wdata[141]
  PIN k_req_wdata[142]
    DIRECTION OUTPUT ;
    USE SIGNAL ;
    PORT
      LAYER M5 ;
        RECT  48.816 0 48.84 0.084 ;
    END
  END k_req_wdata[142]
  PIN k_req_wdata[143]
    DIRECTION OUTPUT ;
    USE SIGNAL ;
    PORT
      LAYER M5 ;
        RECT  48.912 0 48.936 0.084 ;
    END
  END k_req_wdata[143]
  PIN k_req_wdata[144]
    DIRECTION OUTPUT ;
    USE SIGNAL ;
    PORT
      LAYER M5 ;
        RECT  49.008 0 49.032 0.084 ;
    END
  END k_req_wdata[144]
  PIN k_req_wdata[145]
    DIRECTION OUTPUT ;
    USE SIGNAL ;
    PORT
      LAYER M5 ;
        RECT  49.104 0 49.128 0.084 ;
    END
  END k_req_wdata[145]
  PIN k_req_wdata[146]
    DIRECTION OUTPUT ;
    USE SIGNAL ;
    PORT
      LAYER M5 ;
        RECT  49.2 0 49.224 0.084 ;
    END
  END k_req_wdata[146]
  PIN k_req_wdata[147]
    DIRECTION OUTPUT ;
    USE SIGNAL ;
    PORT
      LAYER M5 ;
        RECT  49.296 0 49.32 0.084 ;
    END
  END k_req_wdata[147]
  PIN k_req_wdata[148]
    DIRECTION OUTPUT ;
    USE SIGNAL ;
    PORT
      LAYER M5 ;
        RECT  49.392 0 49.416 0.084 ;
    END
  END k_req_wdata[148]
  PIN k_req_wdata[149]
    DIRECTION OUTPUT ;
    USE SIGNAL ;
    PORT
      LAYER M5 ;
        RECT  49.488 0 49.512 0.084 ;
    END
  END k_req_wdata[149]
  PIN k_req_wdata[14]
    DIRECTION OUTPUT ;
    USE SIGNAL ;
    PORT
      LAYER M5 ;
        RECT  23.472 0 23.496 0.084 ;
    END
  END k_req_wdata[14]
  PIN k_req_wdata[150]
    DIRECTION OUTPUT ;
    USE SIGNAL ;
    PORT
      LAYER M5 ;
        RECT  49.584 0 49.608 0.084 ;
    END
  END k_req_wdata[150]
  PIN k_req_wdata[151]
    DIRECTION OUTPUT ;
    USE SIGNAL ;
    PORT
      LAYER M5 ;
        RECT  49.68 0 49.704 0.084 ;
    END
  END k_req_wdata[151]
  PIN k_req_wdata[152]
    DIRECTION OUTPUT ;
    USE SIGNAL ;
    PORT
      LAYER M5 ;
        RECT  49.776 0 49.8 0.084 ;
    END
  END k_req_wdata[152]
  PIN k_req_wdata[153]
    DIRECTION OUTPUT ;
    USE SIGNAL ;
    PORT
      LAYER M5 ;
        RECT  49.872 0 49.896 0.084 ;
    END
  END k_req_wdata[153]
  PIN k_req_wdata[154]
    DIRECTION OUTPUT ;
    USE SIGNAL ;
    PORT
      LAYER M5 ;
        RECT  49.968 0 49.992 0.084 ;
    END
  END k_req_wdata[154]
  PIN k_req_wdata[155]
    DIRECTION OUTPUT ;
    USE SIGNAL ;
    PORT
      LAYER M5 ;
        RECT  50.064 0 50.088 0.084 ;
    END
  END k_req_wdata[155]
  PIN k_req_wdata[156]
    DIRECTION OUTPUT ;
    USE SIGNAL ;
    PORT
      LAYER M5 ;
        RECT  50.16 0 50.184 0.084 ;
    END
  END k_req_wdata[156]
  PIN k_req_wdata[157]
    DIRECTION OUTPUT ;
    USE SIGNAL ;
    PORT
      LAYER M5 ;
        RECT  50.256 0 50.28 0.084 ;
    END
  END k_req_wdata[157]
  PIN k_req_wdata[158]
    DIRECTION OUTPUT ;
    USE SIGNAL ;
    PORT
      LAYER M5 ;
        RECT  50.352 0 50.376 0.084 ;
    END
  END k_req_wdata[158]
  PIN k_req_wdata[159]
    DIRECTION OUTPUT ;
    USE SIGNAL ;
    PORT
      LAYER M5 ;
        RECT  50.448 0 50.472 0.084 ;
    END
  END k_req_wdata[159]
  PIN k_req_wdata[15]
    DIRECTION OUTPUT ;
    USE SIGNAL ;
    PORT
      LAYER M5 ;
        RECT  23.568 0 23.592 0.084 ;
    END
  END k_req_wdata[15]
  PIN k_req_wdata[160]
    DIRECTION OUTPUT ;
    USE SIGNAL ;
    PORT
      LAYER M5 ;
        RECT  50.544 0 50.568 0.084 ;
    END
  END k_req_wdata[160]
  PIN k_req_wdata[161]
    DIRECTION OUTPUT ;
    USE SIGNAL ;
    PORT
      LAYER M5 ;
        RECT  50.64 0 50.664 0.084 ;
    END
  END k_req_wdata[161]
  PIN k_req_wdata[162]
    DIRECTION OUTPUT ;
    USE SIGNAL ;
    PORT
      LAYER M5 ;
        RECT  50.736 0 50.76 0.084 ;
    END
  END k_req_wdata[162]
  PIN k_req_wdata[163]
    DIRECTION OUTPUT ;
    USE SIGNAL ;
    PORT
      LAYER M5 ;
        RECT  50.832 0 50.856 0.084 ;
    END
  END k_req_wdata[163]
  PIN k_req_wdata[164]
    DIRECTION OUTPUT ;
    USE SIGNAL ;
    PORT
      LAYER M5 ;
        RECT  50.928 0 50.952 0.084 ;
    END
  END k_req_wdata[164]
  PIN k_req_wdata[165]
    DIRECTION OUTPUT ;
    USE SIGNAL ;
    PORT
      LAYER M5 ;
        RECT  51.024 0 51.048 0.084 ;
    END
  END k_req_wdata[165]
  PIN k_req_wdata[166]
    DIRECTION OUTPUT ;
    USE SIGNAL ;
    PORT
      LAYER M5 ;
        RECT  51.12 0 51.144 0.084 ;
    END
  END k_req_wdata[166]
  PIN k_req_wdata[167]
    DIRECTION OUTPUT ;
    USE SIGNAL ;
    PORT
      LAYER M5 ;
        RECT  51.216 0 51.24 0.084 ;
    END
  END k_req_wdata[167]
  PIN k_req_wdata[168]
    DIRECTION OUTPUT ;
    USE SIGNAL ;
    PORT
      LAYER M5 ;
        RECT  51.312 0 51.336 0.084 ;
    END
  END k_req_wdata[168]
  PIN k_req_wdata[169]
    DIRECTION OUTPUT ;
    USE SIGNAL ;
    PORT
      LAYER M5 ;
        RECT  29.136 0 29.16 0.084 ;
    END
  END k_req_wdata[169]
  PIN k_req_wdata[16]
    DIRECTION OUTPUT ;
    USE SIGNAL ;
    PORT
      LAYER M5 ;
        RECT  23.664 0 23.688 0.084 ;
    END
  END k_req_wdata[16]
  PIN k_req_wdata[170]
    DIRECTION OUTPUT ;
    USE SIGNAL ;
    PORT
      LAYER M5 ;
        RECT  29.232 0 29.256 0.084 ;
    END
  END k_req_wdata[170]
  PIN k_req_wdata[171]
    DIRECTION OUTPUT ;
    USE SIGNAL ;
    PORT
      LAYER M5 ;
        RECT  29.328 0 29.352 0.084 ;
    END
  END k_req_wdata[171]
  PIN k_req_wdata[172]
    DIRECTION OUTPUT ;
    USE SIGNAL ;
    PORT
      LAYER M5 ;
        RECT  29.424 0 29.448 0.084 ;
    END
  END k_req_wdata[172]
  PIN k_req_wdata[173]
    DIRECTION OUTPUT ;
    USE SIGNAL ;
    PORT
      LAYER M5 ;
        RECT  29.52 0 29.544 0.084 ;
    END
  END k_req_wdata[173]
  PIN k_req_wdata[174]
    DIRECTION OUTPUT ;
    USE SIGNAL ;
    PORT
      LAYER M5 ;
        RECT  29.616 0 29.64 0.084 ;
    END
  END k_req_wdata[174]
  PIN k_req_wdata[175]
    DIRECTION OUTPUT ;
    USE SIGNAL ;
    PORT
      LAYER M5 ;
        RECT  29.712 0 29.736 0.084 ;
    END
  END k_req_wdata[175]
  PIN k_req_wdata[176]
    DIRECTION OUTPUT ;
    USE SIGNAL ;
    PORT
      LAYER M5 ;
        RECT  29.808 0 29.832 0.084 ;
    END
  END k_req_wdata[176]
  PIN k_req_wdata[177]
    DIRECTION OUTPUT ;
    USE SIGNAL ;
    PORT
      LAYER M5 ;
        RECT  29.904 0 29.928 0.084 ;
    END
  END k_req_wdata[177]
  PIN k_req_wdata[178]
    DIRECTION OUTPUT ;
    USE SIGNAL ;
    PORT
      LAYER M5 ;
        RECT  30 0 30.024 0.084 ;
    END
  END k_req_wdata[178]
  PIN k_req_wdata[179]
    DIRECTION OUTPUT ;
    USE SIGNAL ;
    PORT
      LAYER M5 ;
        RECT  30.096 0 30.12 0.084 ;
    END
  END k_req_wdata[179]
  PIN k_req_wdata[17]
    DIRECTION OUTPUT ;
    USE SIGNAL ;
    PORT
      LAYER M5 ;
        RECT  23.76 0 23.784 0.084 ;
    END
  END k_req_wdata[17]
  PIN k_req_wdata[180]
    DIRECTION OUTPUT ;
    USE SIGNAL ;
    PORT
      LAYER M5 ;
        RECT  30.192 0 30.216 0.084 ;
    END
  END k_req_wdata[180]
  PIN k_req_wdata[181]
    DIRECTION OUTPUT ;
    USE SIGNAL ;
    PORT
      LAYER M5 ;
        RECT  30.288 0 30.312 0.084 ;
    END
  END k_req_wdata[181]
  PIN k_req_wdata[182]
    DIRECTION OUTPUT ;
    USE SIGNAL ;
    PORT
      LAYER M5 ;
        RECT  30.384 0 30.408 0.084 ;
    END
  END k_req_wdata[182]
  PIN k_req_wdata[183]
    DIRECTION OUTPUT ;
    USE SIGNAL ;
    PORT
      LAYER M5 ;
        RECT  30.48 0 30.504 0.084 ;
    END
  END k_req_wdata[183]
  PIN k_req_wdata[184]
    DIRECTION OUTPUT ;
    USE SIGNAL ;
    PORT
      LAYER M5 ;
        RECT  30.576 0 30.6 0.084 ;
    END
  END k_req_wdata[184]
  PIN k_req_wdata[185]
    DIRECTION OUTPUT ;
    USE SIGNAL ;
    PORT
      LAYER M5 ;
        RECT  30.672 0 30.696 0.084 ;
    END
  END k_req_wdata[185]
  PIN k_req_wdata[186]
    DIRECTION OUTPUT ;
    USE SIGNAL ;
    PORT
      LAYER M5 ;
        RECT  30.768 0 30.792 0.084 ;
    END
  END k_req_wdata[186]
  PIN k_req_wdata[187]
    DIRECTION OUTPUT ;
    USE SIGNAL ;
    PORT
      LAYER M5 ;
        RECT  30.864 0 30.888 0.084 ;
    END
  END k_req_wdata[187]
  PIN k_req_wdata[188]
    DIRECTION OUTPUT ;
    USE SIGNAL ;
    PORT
      LAYER M5 ;
        RECT  30.96 0 30.984 0.084 ;
    END
  END k_req_wdata[188]
  PIN k_req_wdata[189]
    DIRECTION OUTPUT ;
    USE SIGNAL ;
    PORT
      LAYER M5 ;
        RECT  31.056 0 31.08 0.084 ;
    END
  END k_req_wdata[189]
  PIN k_req_wdata[18]
    DIRECTION OUTPUT ;
    USE SIGNAL ;
    PORT
      LAYER M5 ;
        RECT  23.856 0 23.88 0.084 ;
    END
  END k_req_wdata[18]
  PIN k_req_wdata[190]
    DIRECTION OUTPUT ;
    USE SIGNAL ;
    PORT
      LAYER M5 ;
        RECT  31.152 0 31.176 0.084 ;
    END
  END k_req_wdata[190]
  PIN k_req_wdata[191]
    DIRECTION OUTPUT ;
    USE SIGNAL ;
    PORT
      LAYER M5 ;
        RECT  31.248 0 31.272 0.084 ;
    END
  END k_req_wdata[191]
  PIN k_req_wdata[192]
    DIRECTION OUTPUT ;
    USE SIGNAL ;
    PORT
      LAYER M5 ;
        RECT  31.344 0 31.368 0.084 ;
    END
  END k_req_wdata[192]
  PIN k_req_wdata[193]
    DIRECTION OUTPUT ;
    USE SIGNAL ;
    PORT
      LAYER M5 ;
        RECT  31.44 0 31.464 0.084 ;
    END
  END k_req_wdata[193]
  PIN k_req_wdata[194]
    DIRECTION OUTPUT ;
    USE SIGNAL ;
    PORT
      LAYER M5 ;
        RECT  31.536 0 31.56 0.084 ;
    END
  END k_req_wdata[194]
  PIN k_req_wdata[195]
    DIRECTION OUTPUT ;
    USE SIGNAL ;
    PORT
      LAYER M5 ;
        RECT  31.632 0 31.656 0.084 ;
    END
  END k_req_wdata[195]
  PIN k_req_wdata[196]
    DIRECTION OUTPUT ;
    USE SIGNAL ;
    PORT
      LAYER M5 ;
        RECT  31.728 0 31.752 0.084 ;
    END
  END k_req_wdata[196]
  PIN k_req_wdata[197]
    DIRECTION OUTPUT ;
    USE SIGNAL ;
    PORT
      LAYER M5 ;
        RECT  31.824 0 31.848 0.084 ;
    END
  END k_req_wdata[197]
  PIN k_req_wdata[198]
    DIRECTION OUTPUT ;
    USE SIGNAL ;
    PORT
      LAYER M5 ;
        RECT  31.92 0 31.944 0.084 ;
    END
  END k_req_wdata[198]
  PIN k_req_wdata[199]
    DIRECTION OUTPUT ;
    USE SIGNAL ;
    PORT
      LAYER M5 ;
        RECT  32.016 0 32.04 0.084 ;
    END
  END k_req_wdata[199]
  PIN k_req_wdata[19]
    DIRECTION OUTPUT ;
    USE SIGNAL ;
    PORT
      LAYER M5 ;
        RECT  23.952 0 23.976 0.084 ;
    END
  END k_req_wdata[19]
  PIN k_req_wdata[1]
    DIRECTION OUTPUT ;
    USE SIGNAL ;
    PORT
      LAYER M5 ;
        RECT  22.224 0 22.248 0.084 ;
    END
  END k_req_wdata[1]
  PIN k_req_wdata[200]
    DIRECTION OUTPUT ;
    USE SIGNAL ;
    PORT
      LAYER M5 ;
        RECT  32.112 0 32.136 0.084 ;
    END
  END k_req_wdata[200]
  PIN k_req_wdata[201]
    DIRECTION OUTPUT ;
    USE SIGNAL ;
    PORT
      LAYER M5 ;
        RECT  26.064 0 26.088 0.084 ;
    END
  END k_req_wdata[201]
  PIN k_req_wdata[202]
    DIRECTION OUTPUT ;
    USE SIGNAL ;
    PORT
      LAYER M5 ;
        RECT  26.16 0 26.184 0.084 ;
    END
  END k_req_wdata[202]
  PIN k_req_wdata[203]
    DIRECTION OUTPUT ;
    USE SIGNAL ;
    PORT
      LAYER M5 ;
        RECT  26.256 0 26.28 0.084 ;
    END
  END k_req_wdata[203]
  PIN k_req_wdata[204]
    DIRECTION OUTPUT ;
    USE SIGNAL ;
    PORT
      LAYER M5 ;
        RECT  26.352 0 26.376 0.084 ;
    END
  END k_req_wdata[204]
  PIN k_req_wdata[205]
    DIRECTION OUTPUT ;
    USE SIGNAL ;
    PORT
      LAYER M5 ;
        RECT  26.448 0 26.472 0.084 ;
    END
  END k_req_wdata[205]
  PIN k_req_wdata[206]
    DIRECTION OUTPUT ;
    USE SIGNAL ;
    PORT
      LAYER M5 ;
        RECT  26.544 0 26.568 0.084 ;
    END
  END k_req_wdata[206]
  PIN k_req_wdata[207]
    DIRECTION OUTPUT ;
    USE SIGNAL ;
    PORT
      LAYER M5 ;
        RECT  26.64 0 26.664 0.084 ;
    END
  END k_req_wdata[207]
  PIN k_req_wdata[208]
    DIRECTION OUTPUT ;
    USE SIGNAL ;
    PORT
      LAYER M5 ;
        RECT  26.736 0 26.76 0.084 ;
    END
  END k_req_wdata[208]
  PIN k_req_wdata[209]
    DIRECTION OUTPUT ;
    USE SIGNAL ;
    PORT
      LAYER M5 ;
        RECT  26.832 0 26.856 0.084 ;
    END
  END k_req_wdata[209]
  PIN k_req_wdata[20]
    DIRECTION OUTPUT ;
    USE SIGNAL ;
    PORT
      LAYER M5 ;
        RECT  24.048 0 24.072 0.084 ;
    END
  END k_req_wdata[20]
  PIN k_req_wdata[210]
    DIRECTION OUTPUT ;
    USE SIGNAL ;
    PORT
      LAYER M5 ;
        RECT  26.928 0 26.952 0.084 ;
    END
  END k_req_wdata[210]
  PIN k_req_wdata[211]
    DIRECTION OUTPUT ;
    USE SIGNAL ;
    PORT
      LAYER M5 ;
        RECT  27.024 0 27.048 0.084 ;
    END
  END k_req_wdata[211]
  PIN k_req_wdata[212]
    DIRECTION OUTPUT ;
    USE SIGNAL ;
    PORT
      LAYER M5 ;
        RECT  27.12 0 27.144 0.084 ;
    END
  END k_req_wdata[212]
  PIN k_req_wdata[213]
    DIRECTION OUTPUT ;
    USE SIGNAL ;
    PORT
      LAYER M5 ;
        RECT  27.216 0 27.24 0.084 ;
    END
  END k_req_wdata[213]
  PIN k_req_wdata[214]
    DIRECTION OUTPUT ;
    USE SIGNAL ;
    PORT
      LAYER M5 ;
        RECT  27.312 0 27.336 0.084 ;
    END
  END k_req_wdata[214]
  PIN k_req_wdata[215]
    DIRECTION OUTPUT ;
    USE SIGNAL ;
    PORT
      LAYER M5 ;
        RECT  27.408 0 27.432 0.084 ;
    END
  END k_req_wdata[215]
  PIN k_req_wdata[216]
    DIRECTION OUTPUT ;
    USE SIGNAL ;
    PORT
      LAYER M5 ;
        RECT  27.504 0 27.528 0.084 ;
    END
  END k_req_wdata[216]
  PIN k_req_wdata[217]
    DIRECTION OUTPUT ;
    USE SIGNAL ;
    PORT
      LAYER M5 ;
        RECT  27.6 0 27.624 0.084 ;
    END
  END k_req_wdata[217]
  PIN k_req_wdata[218]
    DIRECTION OUTPUT ;
    USE SIGNAL ;
    PORT
      LAYER M5 ;
        RECT  27.696 0 27.72 0.084 ;
    END
  END k_req_wdata[218]
  PIN k_req_wdata[219]
    DIRECTION OUTPUT ;
    USE SIGNAL ;
    PORT
      LAYER M5 ;
        RECT  27.792 0 27.816 0.084 ;
    END
  END k_req_wdata[219]
  PIN k_req_wdata[21]
    DIRECTION OUTPUT ;
    USE SIGNAL ;
    PORT
      LAYER M5 ;
        RECT  24.144 0 24.168 0.084 ;
    END
  END k_req_wdata[21]
  PIN k_req_wdata[220]
    DIRECTION OUTPUT ;
    USE SIGNAL ;
    PORT
      LAYER M5 ;
        RECT  27.888 0 27.912 0.084 ;
    END
  END k_req_wdata[220]
  PIN k_req_wdata[221]
    DIRECTION OUTPUT ;
    USE SIGNAL ;
    PORT
      LAYER M5 ;
        RECT  27.984 0 28.008 0.084 ;
    END
  END k_req_wdata[221]
  PIN k_req_wdata[222]
    DIRECTION OUTPUT ;
    USE SIGNAL ;
    PORT
      LAYER M5 ;
        RECT  28.08 0 28.104 0.084 ;
    END
  END k_req_wdata[222]
  PIN k_req_wdata[223]
    DIRECTION OUTPUT ;
    USE SIGNAL ;
    PORT
      LAYER M5 ;
        RECT  28.176 0 28.2 0.084 ;
    END
  END k_req_wdata[223]
  PIN k_req_wdata[224]
    DIRECTION OUTPUT ;
    USE SIGNAL ;
    PORT
      LAYER M5 ;
        RECT  28.272 0 28.296 0.084 ;
    END
  END k_req_wdata[224]
  PIN k_req_wdata[225]
    DIRECTION OUTPUT ;
    USE SIGNAL ;
    PORT
      LAYER M5 ;
        RECT  28.368 0 28.392 0.084 ;
    END
  END k_req_wdata[225]
  PIN k_req_wdata[226]
    DIRECTION OUTPUT ;
    USE SIGNAL ;
    PORT
      LAYER M5 ;
        RECT  28.464 0 28.488 0.084 ;
    END
  END k_req_wdata[226]
  PIN k_req_wdata[227]
    DIRECTION OUTPUT ;
    USE SIGNAL ;
    PORT
      LAYER M5 ;
        RECT  28.56 0 28.584 0.084 ;
    END
  END k_req_wdata[227]
  PIN k_req_wdata[228]
    DIRECTION OUTPUT ;
    USE SIGNAL ;
    PORT
      LAYER M5 ;
        RECT  28.656 0 28.68 0.084 ;
    END
  END k_req_wdata[228]
  PIN k_req_wdata[229]
    DIRECTION OUTPUT ;
    USE SIGNAL ;
    PORT
      LAYER M5 ;
        RECT  28.752 0 28.776 0.084 ;
    END
  END k_req_wdata[229]
  PIN k_req_wdata[22]
    DIRECTION OUTPUT ;
    USE SIGNAL ;
    PORT
      LAYER M5 ;
        RECT  24.24 0 24.264 0.084 ;
    END
  END k_req_wdata[22]
  PIN k_req_wdata[230]
    DIRECTION OUTPUT ;
    USE SIGNAL ;
    PORT
      LAYER M5 ;
        RECT  28.848 0 28.872 0.084 ;
    END
  END k_req_wdata[230]
  PIN k_req_wdata[231]
    DIRECTION OUTPUT ;
    USE SIGNAL ;
    PORT
      LAYER M5 ;
        RECT  28.944 0 28.968 0.084 ;
    END
  END k_req_wdata[231]
  PIN k_req_wdata[232]
    DIRECTION OUTPUT ;
    USE SIGNAL ;
    PORT
      LAYER M5 ;
        RECT  29.04 0 29.064 0.084 ;
    END
  END k_req_wdata[232]
  PIN k_req_wdata[233]
    DIRECTION OUTPUT ;
    USE SIGNAL ;
    PORT
      LAYER M5 ;
        RECT  35.28 0 35.304 0.084 ;
    END
  END k_req_wdata[233]
  PIN k_req_wdata[234]
    DIRECTION OUTPUT ;
    USE SIGNAL ;
    PORT
      LAYER M5 ;
        RECT  35.376 0 35.4 0.084 ;
    END
  END k_req_wdata[234]
  PIN k_req_wdata[235]
    DIRECTION OUTPUT ;
    USE SIGNAL ;
    PORT
      LAYER M5 ;
        RECT  35.472 0 35.496 0.084 ;
    END
  END k_req_wdata[235]
  PIN k_req_wdata[236]
    DIRECTION OUTPUT ;
    USE SIGNAL ;
    PORT
      LAYER M5 ;
        RECT  35.568 0 35.592 0.084 ;
    END
  END k_req_wdata[236]
  PIN k_req_wdata[237]
    DIRECTION OUTPUT ;
    USE SIGNAL ;
    PORT
      LAYER M5 ;
        RECT  35.664 0 35.688 0.084 ;
    END
  END k_req_wdata[237]
  PIN k_req_wdata[238]
    DIRECTION OUTPUT ;
    USE SIGNAL ;
    PORT
      LAYER M5 ;
        RECT  35.76 0 35.784 0.084 ;
    END
  END k_req_wdata[238]
  PIN k_req_wdata[239]
    DIRECTION OUTPUT ;
    USE SIGNAL ;
    PORT
      LAYER M5 ;
        RECT  35.856 0 35.88 0.084 ;
    END
  END k_req_wdata[239]
  PIN k_req_wdata[23]
    DIRECTION OUTPUT ;
    USE SIGNAL ;
    PORT
      LAYER M5 ;
        RECT  24.336 0 24.36 0.084 ;
    END
  END k_req_wdata[23]
  PIN k_req_wdata[240]
    DIRECTION OUTPUT ;
    USE SIGNAL ;
    PORT
      LAYER M5 ;
        RECT  35.952 0 35.976 0.084 ;
    END
  END k_req_wdata[240]
  PIN k_req_wdata[241]
    DIRECTION OUTPUT ;
    USE SIGNAL ;
    PORT
      LAYER M5 ;
        RECT  36.048 0 36.072 0.084 ;
    END
  END k_req_wdata[241]
  PIN k_req_wdata[242]
    DIRECTION OUTPUT ;
    USE SIGNAL ;
    PORT
      LAYER M5 ;
        RECT  36.144 0 36.168 0.084 ;
    END
  END k_req_wdata[242]
  PIN k_req_wdata[243]
    DIRECTION OUTPUT ;
    USE SIGNAL ;
    PORT
      LAYER M5 ;
        RECT  36.24 0 36.264 0.084 ;
    END
  END k_req_wdata[243]
  PIN k_req_wdata[244]
    DIRECTION OUTPUT ;
    USE SIGNAL ;
    PORT
      LAYER M5 ;
        RECT  36.336 0 36.36 0.084 ;
    END
  END k_req_wdata[244]
  PIN k_req_wdata[245]
    DIRECTION OUTPUT ;
    USE SIGNAL ;
    PORT
      LAYER M5 ;
        RECT  36.432 0 36.456 0.084 ;
    END
  END k_req_wdata[245]
  PIN k_req_wdata[246]
    DIRECTION OUTPUT ;
    USE SIGNAL ;
    PORT
      LAYER M5 ;
        RECT  36.528 0 36.552 0.084 ;
    END
  END k_req_wdata[246]
  PIN k_req_wdata[247]
    DIRECTION OUTPUT ;
    USE SIGNAL ;
    PORT
      LAYER M5 ;
        RECT  36.624 0 36.648 0.084 ;
    END
  END k_req_wdata[247]
  PIN k_req_wdata[248]
    DIRECTION OUTPUT ;
    USE SIGNAL ;
    PORT
      LAYER M5 ;
        RECT  36.72 0 36.744 0.084 ;
    END
  END k_req_wdata[248]
  PIN k_req_wdata[249]
    DIRECTION OUTPUT ;
    USE SIGNAL ;
    PORT
      LAYER M5 ;
        RECT  36.816 0 36.84 0.084 ;
    END
  END k_req_wdata[249]
  PIN k_req_wdata[24]
    DIRECTION OUTPUT ;
    USE SIGNAL ;
    PORT
      LAYER M5 ;
        RECT  24.432 0 24.456 0.084 ;
    END
  END k_req_wdata[24]
  PIN k_req_wdata[250]
    DIRECTION OUTPUT ;
    USE SIGNAL ;
    PORT
      LAYER M5 ;
        RECT  36.912 0 36.936 0.084 ;
    END
  END k_req_wdata[250]
  PIN k_req_wdata[251]
    DIRECTION OUTPUT ;
    USE SIGNAL ;
    PORT
      LAYER M5 ;
        RECT  37.008 0 37.032 0.084 ;
    END
  END k_req_wdata[251]
  PIN k_req_wdata[252]
    DIRECTION OUTPUT ;
    USE SIGNAL ;
    PORT
      LAYER M5 ;
        RECT  37.104 0 37.128 0.084 ;
    END
  END k_req_wdata[252]
  PIN k_req_wdata[253]
    DIRECTION OUTPUT ;
    USE SIGNAL ;
    PORT
      LAYER M5 ;
        RECT  37.2 0 37.224 0.084 ;
    END
  END k_req_wdata[253]
  PIN k_req_wdata[254]
    DIRECTION OUTPUT ;
    USE SIGNAL ;
    PORT
      LAYER M5 ;
        RECT  37.296 0 37.32 0.084 ;
    END
  END k_req_wdata[254]
  PIN k_req_wdata[255]
    DIRECTION OUTPUT ;
    USE SIGNAL ;
    PORT
      LAYER M5 ;
        RECT  37.392 0 37.416 0.084 ;
    END
  END k_req_wdata[255]
  PIN k_req_wdata[25]
    DIRECTION OUTPUT ;
    USE SIGNAL ;
    PORT
      LAYER M5 ;
        RECT  24.528 0 24.552 0.084 ;
    END
  END k_req_wdata[25]
  PIN k_req_wdata[26]
    DIRECTION OUTPUT ;
    USE SIGNAL ;
    PORT
      LAYER M5 ;
        RECT  24.624 0 24.648 0.084 ;
    END
  END k_req_wdata[26]
  PIN k_req_wdata[27]
    DIRECTION OUTPUT ;
    USE SIGNAL ;
    PORT
      LAYER M5 ;
        RECT  24.72 0 24.744 0.084 ;
    END
  END k_req_wdata[27]
  PIN k_req_wdata[28]
    DIRECTION OUTPUT ;
    USE SIGNAL ;
    PORT
      LAYER M5 ;
        RECT  24.816 0 24.84 0.084 ;
    END
  END k_req_wdata[28]
  PIN k_req_wdata[29]
    DIRECTION OUTPUT ;
    USE SIGNAL ;
    PORT
      LAYER M5 ;
        RECT  24.912 0 24.936 0.084 ;
    END
  END k_req_wdata[29]
  PIN k_req_wdata[2]
    DIRECTION OUTPUT ;
    USE SIGNAL ;
    PORT
      LAYER M5 ;
        RECT  22.32 0 22.344 0.084 ;
    END
  END k_req_wdata[2]
  PIN k_req_wdata[30]
    DIRECTION OUTPUT ;
    USE SIGNAL ;
    PORT
      LAYER M5 ;
        RECT  25.008 0 25.032 0.084 ;
    END
  END k_req_wdata[30]
  PIN k_req_wdata[31]
    DIRECTION OUTPUT ;
    USE SIGNAL ;
    PORT
      LAYER M5 ;
        RECT  25.104 0 25.128 0.084 ;
    END
  END k_req_wdata[31]
  PIN k_req_wdata[32]
    DIRECTION OUTPUT ;
    USE SIGNAL ;
    PORT
      LAYER M5 ;
        RECT  25.2 0 25.224 0.084 ;
    END
  END k_req_wdata[32]
  PIN k_req_wdata[33]
    DIRECTION OUTPUT ;
    USE SIGNAL ;
    PORT
      LAYER M5 ;
        RECT  25.296 0 25.32 0.084 ;
    END
  END k_req_wdata[33]
  PIN k_req_wdata[34]
    DIRECTION OUTPUT ;
    USE SIGNAL ;
    PORT
      LAYER M5 ;
        RECT  25.392 0 25.416 0.084 ;
    END
  END k_req_wdata[34]
  PIN k_req_wdata[35]
    DIRECTION OUTPUT ;
    USE SIGNAL ;
    PORT
      LAYER M5 ;
        RECT  25.488 0 25.512 0.084 ;
    END
  END k_req_wdata[35]
  PIN k_req_wdata[36]
    DIRECTION OUTPUT ;
    USE SIGNAL ;
    PORT
      LAYER M5 ;
        RECT  25.584 0 25.608 0.084 ;
    END
  END k_req_wdata[36]
  PIN k_req_wdata[37]
    DIRECTION OUTPUT ;
    USE SIGNAL ;
    PORT
      LAYER M5 ;
        RECT  25.68 0 25.704 0.084 ;
    END
  END k_req_wdata[37]
  PIN k_req_wdata[38]
    DIRECTION OUTPUT ;
    USE SIGNAL ;
    PORT
      LAYER M5 ;
        RECT  25.776 0 25.8 0.084 ;
    END
  END k_req_wdata[38]
  PIN k_req_wdata[39]
    DIRECTION OUTPUT ;
    USE SIGNAL ;
    PORT
      LAYER M5 ;
        RECT  25.872 0 25.896 0.084 ;
    END
  END k_req_wdata[39]
  PIN k_req_wdata[3]
    DIRECTION OUTPUT ;
    USE SIGNAL ;
    PORT
      LAYER M5 ;
        RECT  22.416 0 22.44 0.084 ;
    END
  END k_req_wdata[3]
  PIN k_req_wdata[40]
    DIRECTION OUTPUT ;
    USE SIGNAL ;
    PORT
      LAYER M5 ;
        RECT  25.968 0 25.992 0.084 ;
    END
  END k_req_wdata[40]
  PIN k_req_wdata[41]
    DIRECTION OUTPUT ;
    USE SIGNAL ;
    PORT
      LAYER M5 ;
        RECT  45.264 0 45.288 0.084 ;
    END
  END k_req_wdata[41]
  PIN k_req_wdata[42]
    DIRECTION OUTPUT ;
    USE SIGNAL ;
    PORT
      LAYER M5 ;
        RECT  45.36 0 45.384 0.084 ;
    END
  END k_req_wdata[42]
  PIN k_req_wdata[43]
    DIRECTION OUTPUT ;
    USE SIGNAL ;
    PORT
      LAYER M5 ;
        RECT  45.456 0 45.48 0.084 ;
    END
  END k_req_wdata[43]
  PIN k_req_wdata[44]
    DIRECTION OUTPUT ;
    USE SIGNAL ;
    PORT
      LAYER M5 ;
        RECT  45.552 0 45.576 0.084 ;
    END
  END k_req_wdata[44]
  PIN k_req_wdata[45]
    DIRECTION OUTPUT ;
    USE SIGNAL ;
    PORT
      LAYER M5 ;
        RECT  45.648 0 45.672 0.084 ;
    END
  END k_req_wdata[45]
  PIN k_req_wdata[46]
    DIRECTION OUTPUT ;
    USE SIGNAL ;
    PORT
      LAYER M5 ;
        RECT  45.744 0 45.768 0.084 ;
    END
  END k_req_wdata[46]
  PIN k_req_wdata[47]
    DIRECTION OUTPUT ;
    USE SIGNAL ;
    PORT
      LAYER M5 ;
        RECT  45.84 0 45.864 0.084 ;
    END
  END k_req_wdata[47]
  PIN k_req_wdata[48]
    DIRECTION OUTPUT ;
    USE SIGNAL ;
    PORT
      LAYER M5 ;
        RECT  45.936 0 45.96 0.084 ;
    END
  END k_req_wdata[48]
  PIN k_req_wdata[49]
    DIRECTION OUTPUT ;
    USE SIGNAL ;
    PORT
      LAYER M5 ;
        RECT  46.032 0 46.056 0.084 ;
    END
  END k_req_wdata[49]
  PIN k_req_wdata[4]
    DIRECTION OUTPUT ;
    USE SIGNAL ;
    PORT
      LAYER M5 ;
        RECT  22.512 0 22.536 0.084 ;
    END
  END k_req_wdata[4]
  PIN k_req_wdata[50]
    DIRECTION OUTPUT ;
    USE SIGNAL ;
    PORT
      LAYER M5 ;
        RECT  46.128 0 46.152 0.084 ;
    END
  END k_req_wdata[50]
  PIN k_req_wdata[51]
    DIRECTION OUTPUT ;
    USE SIGNAL ;
    PORT
      LAYER M5 ;
        RECT  46.224 0 46.248 0.084 ;
    END
  END k_req_wdata[51]
  PIN k_req_wdata[52]
    DIRECTION OUTPUT ;
    USE SIGNAL ;
    PORT
      LAYER M5 ;
        RECT  46.32 0 46.344 0.084 ;
    END
  END k_req_wdata[52]
  PIN k_req_wdata[53]
    DIRECTION OUTPUT ;
    USE SIGNAL ;
    PORT
      LAYER M5 ;
        RECT  46.416 0 46.44 0.084 ;
    END
  END k_req_wdata[53]
  PIN k_req_wdata[54]
    DIRECTION OUTPUT ;
    USE SIGNAL ;
    PORT
      LAYER M5 ;
        RECT  46.512 0 46.536 0.084 ;
    END
  END k_req_wdata[54]
  PIN k_req_wdata[55]
    DIRECTION OUTPUT ;
    USE SIGNAL ;
    PORT
      LAYER M5 ;
        RECT  46.608 0 46.632 0.084 ;
    END
  END k_req_wdata[55]
  PIN k_req_wdata[56]
    DIRECTION OUTPUT ;
    USE SIGNAL ;
    PORT
      LAYER M5 ;
        RECT  46.704 0 46.728 0.084 ;
    END
  END k_req_wdata[56]
  PIN k_req_wdata[57]
    DIRECTION OUTPUT ;
    USE SIGNAL ;
    PORT
      LAYER M5 ;
        RECT  46.8 0 46.824 0.084 ;
    END
  END k_req_wdata[57]
  PIN k_req_wdata[58]
    DIRECTION OUTPUT ;
    USE SIGNAL ;
    PORT
      LAYER M5 ;
        RECT  46.896 0 46.92 0.084 ;
    END
  END k_req_wdata[58]
  PIN k_req_wdata[59]
    DIRECTION OUTPUT ;
    USE SIGNAL ;
    PORT
      LAYER M5 ;
        RECT  46.992 0 47.016 0.084 ;
    END
  END k_req_wdata[59]
  PIN k_req_wdata[5]
    DIRECTION OUTPUT ;
    USE SIGNAL ;
    PORT
      LAYER M5 ;
        RECT  22.608 0 22.632 0.084 ;
    END
  END k_req_wdata[5]
  PIN k_req_wdata[60]
    DIRECTION OUTPUT ;
    USE SIGNAL ;
    PORT
      LAYER M5 ;
        RECT  47.088 0 47.112 0.084 ;
    END
  END k_req_wdata[60]
  PIN k_req_wdata[61]
    DIRECTION OUTPUT ;
    USE SIGNAL ;
    PORT
      LAYER M5 ;
        RECT  47.184 0 47.208 0.084 ;
    END
  END k_req_wdata[61]
  PIN k_req_wdata[62]
    DIRECTION OUTPUT ;
    USE SIGNAL ;
    PORT
      LAYER M5 ;
        RECT  47.28 0 47.304 0.084 ;
    END
  END k_req_wdata[62]
  PIN k_req_wdata[63]
    DIRECTION OUTPUT ;
    USE SIGNAL ;
    PORT
      LAYER M5 ;
        RECT  47.376 0 47.4 0.084 ;
    END
  END k_req_wdata[63]
  PIN k_req_wdata[64]
    DIRECTION OUTPUT ;
    USE SIGNAL ;
    PORT
      LAYER M5 ;
        RECT  47.472 0 47.496 0.084 ;
    END
  END k_req_wdata[64]
  PIN k_req_wdata[65]
    DIRECTION OUTPUT ;
    USE SIGNAL ;
    PORT
      LAYER M5 ;
        RECT  47.568 0 47.592 0.084 ;
    END
  END k_req_wdata[65]
  PIN k_req_wdata[66]
    DIRECTION OUTPUT ;
    USE SIGNAL ;
    PORT
      LAYER M5 ;
        RECT  47.664 0 47.688 0.084 ;
    END
  END k_req_wdata[66]
  PIN k_req_wdata[67]
    DIRECTION OUTPUT ;
    USE SIGNAL ;
    PORT
      LAYER M5 ;
        RECT  47.76 0 47.784 0.084 ;
    END
  END k_req_wdata[67]
  PIN k_req_wdata[68]
    DIRECTION OUTPUT ;
    USE SIGNAL ;
    PORT
      LAYER M5 ;
        RECT  47.856 0 47.88 0.084 ;
    END
  END k_req_wdata[68]
  PIN k_req_wdata[69]
    DIRECTION OUTPUT ;
    USE SIGNAL ;
    PORT
      LAYER M5 ;
        RECT  47.952 0 47.976 0.084 ;
    END
  END k_req_wdata[69]
  PIN k_req_wdata[6]
    DIRECTION OUTPUT ;
    USE SIGNAL ;
    PORT
      LAYER M5 ;
        RECT  22.704 0 22.728 0.084 ;
    END
  END k_req_wdata[6]
  PIN k_req_wdata[70]
    DIRECTION OUTPUT ;
    USE SIGNAL ;
    PORT
      LAYER M5 ;
        RECT  48.048 0 48.072 0.084 ;
    END
  END k_req_wdata[70]
  PIN k_req_wdata[71]
    DIRECTION OUTPUT ;
    USE SIGNAL ;
    PORT
      LAYER M5 ;
        RECT  48.144 0 48.168 0.084 ;
    END
  END k_req_wdata[71]
  PIN k_req_wdata[72]
    DIRECTION OUTPUT ;
    USE SIGNAL ;
    PORT
      LAYER M5 ;
        RECT  48.24 0 48.264 0.084 ;
    END
  END k_req_wdata[72]
  PIN k_req_wdata[73]
    DIRECTION OUTPUT ;
    USE SIGNAL ;
    PORT
      LAYER M5 ;
        RECT  51.408 0 51.432 0.084 ;
    END
  END k_req_wdata[73]
  PIN k_req_wdata[74]
    DIRECTION OUTPUT ;
    USE SIGNAL ;
    PORT
      LAYER M5 ;
        RECT  51.504 0 51.528 0.084 ;
    END
  END k_req_wdata[74]
  PIN k_req_wdata[75]
    DIRECTION OUTPUT ;
    USE SIGNAL ;
    PORT
      LAYER M5 ;
        RECT  51.6 0 51.624 0.084 ;
    END
  END k_req_wdata[75]
  PIN k_req_wdata[76]
    DIRECTION OUTPUT ;
    USE SIGNAL ;
    PORT
      LAYER M5 ;
        RECT  51.696 0 51.72 0.084 ;
    END
  END k_req_wdata[76]
  PIN k_req_wdata[77]
    DIRECTION OUTPUT ;
    USE SIGNAL ;
    PORT
      LAYER M5 ;
        RECT  51.792 0 51.816 0.084 ;
    END
  END k_req_wdata[77]
  PIN k_req_wdata[78]
    DIRECTION OUTPUT ;
    USE SIGNAL ;
    PORT
      LAYER M5 ;
        RECT  51.888 0 51.912 0.084 ;
    END
  END k_req_wdata[78]
  PIN k_req_wdata[79]
    DIRECTION OUTPUT ;
    USE SIGNAL ;
    PORT
      LAYER M5 ;
        RECT  51.984 0 52.008 0.084 ;
    END
  END k_req_wdata[79]
  PIN k_req_wdata[7]
    DIRECTION OUTPUT ;
    USE SIGNAL ;
    PORT
      LAYER M5 ;
        RECT  22.8 0 22.824 0.084 ;
    END
  END k_req_wdata[7]
  PIN k_req_wdata[80]
    DIRECTION OUTPUT ;
    USE SIGNAL ;
    PORT
      LAYER M5 ;
        RECT  52.08 0 52.104 0.084 ;
    END
  END k_req_wdata[80]
  PIN k_req_wdata[81]
    DIRECTION OUTPUT ;
    USE SIGNAL ;
    PORT
      LAYER M5 ;
        RECT  52.176 0 52.2 0.084 ;
    END
  END k_req_wdata[81]
  PIN k_req_wdata[82]
    DIRECTION OUTPUT ;
    USE SIGNAL ;
    PORT
      LAYER M5 ;
        RECT  52.272 0 52.296 0.084 ;
    END
  END k_req_wdata[82]
  PIN k_req_wdata[83]
    DIRECTION OUTPUT ;
    USE SIGNAL ;
    PORT
      LAYER M5 ;
        RECT  52.368 0 52.392 0.084 ;
    END
  END k_req_wdata[83]
  PIN k_req_wdata[84]
    DIRECTION OUTPUT ;
    USE SIGNAL ;
    PORT
      LAYER M5 ;
        RECT  52.464 0 52.488 0.084 ;
    END
  END k_req_wdata[84]
  PIN k_req_wdata[85]
    DIRECTION OUTPUT ;
    USE SIGNAL ;
    PORT
      LAYER M5 ;
        RECT  52.56 0 52.584 0.084 ;
    END
  END k_req_wdata[85]
  PIN k_req_wdata[86]
    DIRECTION OUTPUT ;
    USE SIGNAL ;
    PORT
      LAYER M5 ;
        RECT  52.656 0 52.68 0.084 ;
    END
  END k_req_wdata[86]
  PIN k_req_wdata[87]
    DIRECTION OUTPUT ;
    USE SIGNAL ;
    PORT
      LAYER M5 ;
        RECT  52.752 0 52.776 0.084 ;
    END
  END k_req_wdata[87]
  PIN k_req_wdata[88]
    DIRECTION OUTPUT ;
    USE SIGNAL ;
    PORT
      LAYER M5 ;
        RECT  52.848 0 52.872 0.084 ;
    END
  END k_req_wdata[88]
  PIN k_req_wdata[89]
    DIRECTION OUTPUT ;
    USE SIGNAL ;
    PORT
      LAYER M5 ;
        RECT  52.944 0 52.968 0.084 ;
    END
  END k_req_wdata[89]
  PIN k_req_wdata[8]
    DIRECTION OUTPUT ;
    USE SIGNAL ;
    PORT
      LAYER M5 ;
        RECT  22.896 0 22.92 0.084 ;
    END
  END k_req_wdata[8]
  PIN k_req_wdata[90]
    DIRECTION OUTPUT ;
    USE SIGNAL ;
    PORT
      LAYER M5 ;
        RECT  53.04 0 53.064 0.084 ;
    END
  END k_req_wdata[90]
  PIN k_req_wdata[91]
    DIRECTION OUTPUT ;
    USE SIGNAL ;
    PORT
      LAYER M5 ;
        RECT  53.136 0 53.16 0.084 ;
    END
  END k_req_wdata[91]
  PIN k_req_wdata[92]
    DIRECTION OUTPUT ;
    USE SIGNAL ;
    PORT
      LAYER M5 ;
        RECT  53.232 0 53.256 0.084 ;
    END
  END k_req_wdata[92]
  PIN k_req_wdata[93]
    DIRECTION OUTPUT ;
    USE SIGNAL ;
    PORT
      LAYER M5 ;
        RECT  53.328 0 53.352 0.084 ;
    END
  END k_req_wdata[93]
  PIN k_req_wdata[94]
    DIRECTION OUTPUT ;
    USE SIGNAL ;
    PORT
      LAYER M5 ;
        RECT  53.424 0 53.448 0.084 ;
    END
  END k_req_wdata[94]
  PIN k_req_wdata[95]
    DIRECTION OUTPUT ;
    USE SIGNAL ;
    PORT
      LAYER M5 ;
        RECT  53.52 0 53.544 0.084 ;
    END
  END k_req_wdata[95]
  PIN k_req_wdata[96]
    DIRECTION OUTPUT ;
    USE SIGNAL ;
    PORT
      LAYER M5 ;
        RECT  53.616 0 53.64 0.084 ;
    END
  END k_req_wdata[96]
  PIN k_req_wdata[97]
    DIRECTION OUTPUT ;
    USE SIGNAL ;
    PORT
      LAYER M5 ;
        RECT  53.712 0 53.736 0.084 ;
    END
  END k_req_wdata[97]
  PIN k_req_wdata[98]
    DIRECTION OUTPUT ;
    USE SIGNAL ;
    PORT
      LAYER M5 ;
        RECT  53.808 0 53.832 0.084 ;
    END
  END k_req_wdata[98]
  PIN k_req_wdata[99]
    DIRECTION OUTPUT ;
    USE SIGNAL ;
    PORT
      LAYER M5 ;
        RECT  53.904 0 53.928 0.084 ;
    END
  END k_req_wdata[99]
  PIN k_req_wdata[9]
    DIRECTION OUTPUT ;
    USE SIGNAL ;
    PORT
      LAYER M5 ;
        RECT  22.992 0 23.016 0.084 ;
    END
  END k_req_wdata[9]
  PIN k_req_we
    DIRECTION OUTPUT ;
    USE SIGNAL ;
    PORT
      LAYER M5 ;
        RECT  37.488 0 37.512 0.084 ;
    END
  END k_req_we
  PIN k_req_wstrb[0]
    DIRECTION OUTPUT ;
    USE SIGNAL ;
    PORT
      LAYER M5 ;
        RECT  37.584 0 37.608 0.084 ;
    END
  END k_req_wstrb[0]
  PIN k_req_wstrb[10]
    DIRECTION OUTPUT ;
    USE SIGNAL ;
    PORT
      LAYER M5 ;
        RECT  16.272 0 16.296 0.084 ;
    END
  END k_req_wstrb[10]
  PIN k_req_wstrb[11]
    DIRECTION OUTPUT ;
    USE SIGNAL ;
    PORT
      LAYER M5 ;
        RECT  16.368 0 16.392 0.084 ;
    END
  END k_req_wstrb[11]
  PIN k_req_wstrb[12]
    DIRECTION OUTPUT ;
    USE SIGNAL ;
    PORT
      LAYER M5 ;
        RECT  16.464 0 16.488 0.084 ;
    END
  END k_req_wstrb[12]
  PIN k_req_wstrb[13]
    DIRECTION OUTPUT ;
    USE SIGNAL ;
    PORT
      LAYER M5 ;
        RECT  16.56 0 16.584 0.084 ;
    END
  END k_req_wstrb[13]
  PIN k_req_wstrb[14]
    DIRECTION OUTPUT ;
    USE SIGNAL ;
    PORT
      LAYER M5 ;
        RECT  16.656 0 16.68 0.084 ;
    END
  END k_req_wstrb[14]
  PIN k_req_wstrb[15]
    DIRECTION OUTPUT ;
    USE SIGNAL ;
    PORT
      LAYER M5 ;
        RECT  16.752 0 16.776 0.084 ;
    END
  END k_req_wstrb[15]
  PIN k_req_wstrb[16]
    DIRECTION OUTPUT ;
    USE SIGNAL ;
    PORT
      LAYER M5 ;
        RECT  16.848 0 16.872 0.084 ;
    END
  END k_req_wstrb[16]
  PIN k_req_wstrb[17]
    DIRECTION OUTPUT ;
    USE SIGNAL ;
    PORT
      LAYER M5 ;
        RECT  16.944 0 16.968 0.084 ;
    END
  END k_req_wstrb[17]
  PIN k_req_wstrb[18]
    DIRECTION OUTPUT ;
    USE SIGNAL ;
    PORT
      LAYER M5 ;
        RECT  17.04 0 17.064 0.084 ;
    END
  END k_req_wstrb[18]
  PIN k_req_wstrb[19]
    DIRECTION OUTPUT ;
    USE SIGNAL ;
    PORT
      LAYER M5 ;
        RECT  17.136 0 17.16 0.084 ;
    END
  END k_req_wstrb[19]
  PIN k_req_wstrb[1]
    DIRECTION OUTPUT ;
    USE SIGNAL ;
    PORT
      LAYER M5 ;
        RECT  37.68 0 37.704 0.084 ;
    END
  END k_req_wstrb[1]
  PIN k_req_wstrb[20]
    DIRECTION OUTPUT ;
    USE SIGNAL ;
    PORT
      LAYER M5 ;
        RECT  17.232 0 17.256 0.084 ;
    END
  END k_req_wstrb[20]
  PIN k_req_wstrb[21]
    DIRECTION OUTPUT ;
    USE SIGNAL ;
    PORT
      LAYER M5 ;
        RECT  17.328 0 17.352 0.084 ;
    END
  END k_req_wstrb[21]
  PIN k_req_wstrb[22]
    DIRECTION OUTPUT ;
    USE SIGNAL ;
    PORT
      LAYER M5 ;
        RECT  17.424 0 17.448 0.084 ;
    END
  END k_req_wstrb[22]
  PIN k_req_wstrb[23]
    DIRECTION OUTPUT ;
    USE SIGNAL ;
    PORT
      LAYER M5 ;
        RECT  17.52 0 17.544 0.084 ;
    END
  END k_req_wstrb[23]
  PIN k_req_wstrb[24]
    DIRECTION OUTPUT ;
    USE SIGNAL ;
    PORT
      LAYER M5 ;
        RECT  17.616 0 17.64 0.084 ;
    END
  END k_req_wstrb[24]
  PIN k_req_wstrb[25]
    DIRECTION OUTPUT ;
    USE SIGNAL ;
    PORT
      LAYER M5 ;
        RECT  17.712 0 17.736 0.084 ;
    END
  END k_req_wstrb[25]
  PIN k_req_wstrb[26]
    DIRECTION OUTPUT ;
    USE SIGNAL ;
    PORT
      LAYER M5 ;
        RECT  17.808 0 17.832 0.084 ;
    END
  END k_req_wstrb[26]
  PIN k_req_wstrb[27]
    DIRECTION OUTPUT ;
    USE SIGNAL ;
    PORT
      LAYER M5 ;
        RECT  17.904 0 17.928 0.084 ;
    END
  END k_req_wstrb[27]
  PIN k_req_wstrb[28]
    DIRECTION OUTPUT ;
    USE SIGNAL ;
    PORT
      LAYER M5 ;
        RECT  18 0 18.024 0.084 ;
    END
  END k_req_wstrb[28]
  PIN k_req_wstrb[29]
    DIRECTION OUTPUT ;
    USE SIGNAL ;
    PORT
      LAYER M5 ;
        RECT  18.096 0 18.12 0.084 ;
    END
  END k_req_wstrb[29]
  PIN k_req_wstrb[2]
    DIRECTION OUTPUT ;
    USE SIGNAL ;
    PORT
      LAYER M5 ;
        RECT  37.776 0 37.8 0.084 ;
    END
  END k_req_wstrb[2]
  PIN k_req_wstrb[30]
    DIRECTION OUTPUT ;
    USE SIGNAL ;
    PORT
      LAYER M5 ;
        RECT  18.192 0 18.216 0.084 ;
    END
  END k_req_wstrb[30]
  PIN k_req_wstrb[31]
    DIRECTION OUTPUT ;
    USE SIGNAL ;
    PORT
      LAYER M5 ;
        RECT  18.288 0 18.312 0.084 ;
    END
  END k_req_wstrb[31]
  PIN k_req_wstrb[3]
    DIRECTION OUTPUT ;
    USE SIGNAL ;
    PORT
      LAYER M5 ;
        RECT  37.872 0 37.896 0.084 ;
    END
  END k_req_wstrb[3]
  PIN k_req_wstrb[4]
    DIRECTION OUTPUT ;
    USE SIGNAL ;
    PORT
      LAYER M5 ;
        RECT  37.968 0 37.992 0.084 ;
    END
  END k_req_wstrb[4]
  PIN k_req_wstrb[5]
    DIRECTION OUTPUT ;
    USE SIGNAL ;
    PORT
      LAYER M5 ;
        RECT  38.064 0 38.088 0.084 ;
    END
  END k_req_wstrb[5]
  PIN k_req_wstrb[6]
    DIRECTION OUTPUT ;
    USE SIGNAL ;
    PORT
      LAYER M5 ;
        RECT  38.16 0 38.184 0.084 ;
    END
  END k_req_wstrb[6]
  PIN k_req_wstrb[7]
    DIRECTION OUTPUT ;
    USE SIGNAL ;
    PORT
      LAYER M5 ;
        RECT  38.256 0 38.28 0.084 ;
    END
  END k_req_wstrb[7]
  PIN k_req_wstrb[8]
    DIRECTION OUTPUT ;
    USE SIGNAL ;
    PORT
      LAYER M5 ;
        RECT  16.08 0 16.104 0.084 ;
    END
  END k_req_wstrb[8]
  PIN k_req_wstrb[9]
    DIRECTION OUTPUT ;
    USE SIGNAL ;
    PORT
      LAYER M5 ;
        RECT  16.176 0 16.2 0.084 ;
    END
  END k_req_wstrb[9]
  PIN k_rsp_data[0]
    DIRECTION INPUT ;
    USE SIGNAL ;
    PORT
      LAYER M5 ;
        RECT  18.384 0 18.408 0.084 ;
    END
  END k_rsp_data[0]
  PIN k_rsp_data[100]
    DIRECTION INPUT ;
    USE SIGNAL ;
    PORT
      LAYER M5 ;
        RECT  12.624 0 12.648 0.084 ;
    END
  END k_rsp_data[100]
  PIN k_rsp_data[101]
    DIRECTION INPUT ;
    USE SIGNAL ;
    PORT
      LAYER M5 ;
        RECT  12.72 0 12.744 0.084 ;
    END
  END k_rsp_data[101]
  PIN k_rsp_data[102]
    DIRECTION INPUT ;
    USE SIGNAL ;
    PORT
      LAYER M5 ;
        RECT  12.816 0 12.84 0.084 ;
    END
  END k_rsp_data[102]
  PIN k_rsp_data[103]
    DIRECTION INPUT ;
    USE SIGNAL ;
    PORT
      LAYER M5 ;
        RECT  12.912 0 12.936 0.084 ;
    END
  END k_rsp_data[103]
  PIN k_rsp_data[104]
    DIRECTION INPUT ;
    USE SIGNAL ;
    PORT
      LAYER M5 ;
        RECT  0.72 0 0.744 0.084 ;
    END
  END k_rsp_data[104]
  PIN k_rsp_data[105]
    DIRECTION INPUT ;
    USE SIGNAL ;
    PORT
      LAYER M5 ;
        RECT  0.816 0 0.84 0.084 ;
    END
  END k_rsp_data[105]
  PIN k_rsp_data[106]
    DIRECTION INPUT ;
    USE SIGNAL ;
    PORT
      LAYER M5 ;
        RECT  0.912 0 0.936 0.084 ;
    END
  END k_rsp_data[106]
  PIN k_rsp_data[107]
    DIRECTION INPUT ;
    USE SIGNAL ;
    PORT
      LAYER M5 ;
        RECT  1.008 0 1.032 0.084 ;
    END
  END k_rsp_data[107]
  PIN k_rsp_data[108]
    DIRECTION INPUT ;
    USE SIGNAL ;
    PORT
      LAYER M5 ;
        RECT  1.104 0 1.128 0.084 ;
    END
  END k_rsp_data[108]
  PIN k_rsp_data[109]
    DIRECTION INPUT ;
    USE SIGNAL ;
    PORT
      LAYER M5 ;
        RECT  1.2 0 1.224 0.084 ;
    END
  END k_rsp_data[109]
  PIN k_rsp_data[10]
    DIRECTION INPUT ;
    USE SIGNAL ;
    PORT
      LAYER M5 ;
        RECT  39.312 0 39.336 0.084 ;
    END
  END k_rsp_data[10]
  PIN k_rsp_data[110]
    DIRECTION INPUT ;
    USE SIGNAL ;
    PORT
      LAYER M5 ;
        RECT  1.296 0 1.32 0.084 ;
    END
  END k_rsp_data[110]
  PIN k_rsp_data[111]
    DIRECTION INPUT ;
    USE SIGNAL ;
    PORT
      LAYER M5 ;
        RECT  1.392 0 1.416 0.084 ;
    END
  END k_rsp_data[111]
  PIN k_rsp_data[112]
    DIRECTION INPUT ;
    USE SIGNAL ;
    PORT
      LAYER M5 ;
        RECT  1.488 0 1.512 0.084 ;
    END
  END k_rsp_data[112]
  PIN k_rsp_data[113]
    DIRECTION INPUT ;
    USE SIGNAL ;
    PORT
      LAYER M5 ;
        RECT  1.584 0 1.608 0.084 ;
    END
  END k_rsp_data[113]
  PIN k_rsp_data[114]
    DIRECTION INPUT ;
    USE SIGNAL ;
    PORT
      LAYER M5 ;
        RECT  1.68 0 1.704 0.084 ;
    END
  END k_rsp_data[114]
  PIN k_rsp_data[115]
    DIRECTION INPUT ;
    USE SIGNAL ;
    PORT
      LAYER M5 ;
        RECT  1.776 0 1.8 0.084 ;
    END
  END k_rsp_data[115]
  PIN k_rsp_data[116]
    DIRECTION INPUT ;
    USE SIGNAL ;
    PORT
      LAYER M5 ;
        RECT  1.872 0 1.896 0.084 ;
    END
  END k_rsp_data[116]
  PIN k_rsp_data[117]
    DIRECTION INPUT ;
    USE SIGNAL ;
    PORT
      LAYER M5 ;
        RECT  1.968 0 1.992 0.084 ;
    END
  END k_rsp_data[117]
  PIN k_rsp_data[118]
    DIRECTION INPUT ;
    USE SIGNAL ;
    PORT
      LAYER M5 ;
        RECT  2.064 0 2.088 0.084 ;
    END
  END k_rsp_data[118]
  PIN k_rsp_data[119]
    DIRECTION INPUT ;
    USE SIGNAL ;
    PORT
      LAYER M5 ;
        RECT  2.16 0 2.184 0.084 ;
    END
  END k_rsp_data[119]
  PIN k_rsp_data[11]
    DIRECTION INPUT ;
    USE SIGNAL ;
    PORT
      LAYER M5 ;
        RECT  39.408 0 39.432 0.084 ;
    END
  END k_rsp_data[11]
  PIN k_rsp_data[120]
    DIRECTION INPUT ;
    USE SIGNAL ;
    PORT
      LAYER M5 ;
        RECT  2.256 0 2.28 0.084 ;
    END
  END k_rsp_data[120]
  PIN k_rsp_data[121]
    DIRECTION INPUT ;
    USE SIGNAL ;
    PORT
      LAYER M5 ;
        RECT  2.352 0 2.376 0.084 ;
    END
  END k_rsp_data[121]
  PIN k_rsp_data[122]
    DIRECTION INPUT ;
    USE SIGNAL ;
    PORT
      LAYER M5 ;
        RECT  2.448 0 2.472 0.084 ;
    END
  END k_rsp_data[122]
  PIN k_rsp_data[123]
    DIRECTION INPUT ;
    USE SIGNAL ;
    PORT
      LAYER M5 ;
        RECT  2.544 0 2.568 0.084 ;
    END
  END k_rsp_data[123]
  PIN k_rsp_data[124]
    DIRECTION INPUT ;
    USE SIGNAL ;
    PORT
      LAYER M5 ;
        RECT  2.64 0 2.664 0.084 ;
    END
  END k_rsp_data[124]
  PIN k_rsp_data[125]
    DIRECTION INPUT ;
    USE SIGNAL ;
    PORT
      LAYER M5 ;
        RECT  2.736 0 2.76 0.084 ;
    END
  END k_rsp_data[125]
  PIN k_rsp_data[126]
    DIRECTION INPUT ;
    USE SIGNAL ;
    PORT
      LAYER M5 ;
        RECT  2.832 0 2.856 0.084 ;
    END
  END k_rsp_data[126]
  PIN k_rsp_data[127]
    DIRECTION INPUT ;
    USE SIGNAL ;
    PORT
      LAYER M5 ;
        RECT  2.928 0 2.952 0.084 ;
    END
  END k_rsp_data[127]
  PIN k_rsp_data[128]
    DIRECTION INPUT ;
    USE SIGNAL ;
    PORT
      LAYER M5 ;
        RECT  3.024 0 3.048 0.084 ;
    END
  END k_rsp_data[128]
  PIN k_rsp_data[129]
    DIRECTION INPUT ;
    USE SIGNAL ;
    PORT
      LAYER M5 ;
        RECT  3.12 0 3.144 0.084 ;
    END
  END k_rsp_data[129]
  PIN k_rsp_data[12]
    DIRECTION INPUT ;
    USE SIGNAL ;
    PORT
      LAYER M5 ;
        RECT  39.504 0 39.528 0.084 ;
    END
  END k_rsp_data[12]
  PIN k_rsp_data[130]
    DIRECTION INPUT ;
    USE SIGNAL ;
    PORT
      LAYER M5 ;
        RECT  3.216 0 3.24 0.084 ;
    END
  END k_rsp_data[130]
  PIN k_rsp_data[131]
    DIRECTION INPUT ;
    USE SIGNAL ;
    PORT
      LAYER M5 ;
        RECT  3.312 0 3.336 0.084 ;
    END
  END k_rsp_data[131]
  PIN k_rsp_data[132]
    DIRECTION INPUT ;
    USE SIGNAL ;
    PORT
      LAYER M5 ;
        RECT  3.408 0 3.432 0.084 ;
    END
  END k_rsp_data[132]
  PIN k_rsp_data[133]
    DIRECTION INPUT ;
    USE SIGNAL ;
    PORT
      LAYER M5 ;
        RECT  3.504 0 3.528 0.084 ;
    END
  END k_rsp_data[133]
  PIN k_rsp_data[134]
    DIRECTION INPUT ;
    USE SIGNAL ;
    PORT
      LAYER M5 ;
        RECT  3.6 0 3.624 0.084 ;
    END
  END k_rsp_data[134]
  PIN k_rsp_data[135]
    DIRECTION INPUT ;
    USE SIGNAL ;
    PORT
      LAYER M5 ;
        RECT  3.696 0 3.72 0.084 ;
    END
  END k_rsp_data[135]
  PIN k_rsp_data[136]
    DIRECTION INPUT ;
    USE SIGNAL ;
    PORT
      LAYER M5 ;
        RECT  13.008 0 13.032 0.084 ;
    END
  END k_rsp_data[136]
  PIN k_rsp_data[137]
    DIRECTION INPUT ;
    USE SIGNAL ;
    PORT
      LAYER M5 ;
        RECT  13.104 0 13.128 0.084 ;
    END
  END k_rsp_data[137]
  PIN k_rsp_data[138]
    DIRECTION INPUT ;
    USE SIGNAL ;
    PORT
      LAYER M5 ;
        RECT  13.2 0 13.224 0.084 ;
    END
  END k_rsp_data[138]
  PIN k_rsp_data[139]
    DIRECTION INPUT ;
    USE SIGNAL ;
    PORT
      LAYER M5 ;
        RECT  13.296 0 13.32 0.084 ;
    END
  END k_rsp_data[139]
  PIN k_rsp_data[13]
    DIRECTION INPUT ;
    USE SIGNAL ;
    PORT
      LAYER M5 ;
        RECT  39.6 0 39.624 0.084 ;
    END
  END k_rsp_data[13]
  PIN k_rsp_data[140]
    DIRECTION INPUT ;
    USE SIGNAL ;
    PORT
      LAYER M5 ;
        RECT  13.392 0 13.416 0.084 ;
    END
  END k_rsp_data[140]
  PIN k_rsp_data[141]
    DIRECTION INPUT ;
    USE SIGNAL ;
    PORT
      LAYER M5 ;
        RECT  13.488 0 13.512 0.084 ;
    END
  END k_rsp_data[141]
  PIN k_rsp_data[142]
    DIRECTION INPUT ;
    USE SIGNAL ;
    PORT
      LAYER M5 ;
        RECT  13.584 0 13.608 0.084 ;
    END
  END k_rsp_data[142]
  PIN k_rsp_data[143]
    DIRECTION INPUT ;
    USE SIGNAL ;
    PORT
      LAYER M5 ;
        RECT  13.68 0 13.704 0.084 ;
    END
  END k_rsp_data[143]
  PIN k_rsp_data[144]
    DIRECTION INPUT ;
    USE SIGNAL ;
    PORT
      LAYER M5 ;
        RECT  13.776 0 13.8 0.084 ;
    END
  END k_rsp_data[144]
  PIN k_rsp_data[145]
    DIRECTION INPUT ;
    USE SIGNAL ;
    PORT
      LAYER M5 ;
        RECT  13.872 0 13.896 0.084 ;
    END
  END k_rsp_data[145]
  PIN k_rsp_data[146]
    DIRECTION INPUT ;
    USE SIGNAL ;
    PORT
      LAYER M5 ;
        RECT  13.968 0 13.992 0.084 ;
    END
  END k_rsp_data[146]
  PIN k_rsp_data[147]
    DIRECTION INPUT ;
    USE SIGNAL ;
    PORT
      LAYER M5 ;
        RECT  14.064 0 14.088 0.084 ;
    END
  END k_rsp_data[147]
  PIN k_rsp_data[148]
    DIRECTION INPUT ;
    USE SIGNAL ;
    PORT
      LAYER M5 ;
        RECT  14.16 0 14.184 0.084 ;
    END
  END k_rsp_data[148]
  PIN k_rsp_data[149]
    DIRECTION INPUT ;
    USE SIGNAL ;
    PORT
      LAYER M5 ;
        RECT  14.256 0 14.28 0.084 ;
    END
  END k_rsp_data[149]
  PIN k_rsp_data[14]
    DIRECTION INPUT ;
    USE SIGNAL ;
    PORT
      LAYER M5 ;
        RECT  39.696 0 39.72 0.084 ;
    END
  END k_rsp_data[14]
  PIN k_rsp_data[150]
    DIRECTION INPUT ;
    USE SIGNAL ;
    PORT
      LAYER M5 ;
        RECT  14.352 0 14.376 0.084 ;
    END
  END k_rsp_data[150]
  PIN k_rsp_data[151]
    DIRECTION INPUT ;
    USE SIGNAL ;
    PORT
      LAYER M5 ;
        RECT  14.448 0 14.472 0.084 ;
    END
  END k_rsp_data[151]
  PIN k_rsp_data[152]
    DIRECTION INPUT ;
    USE SIGNAL ;
    PORT
      LAYER M5 ;
        RECT  14.544 0 14.568 0.084 ;
    END
  END k_rsp_data[152]
  PIN k_rsp_data[153]
    DIRECTION INPUT ;
    USE SIGNAL ;
    PORT
      LAYER M5 ;
        RECT  14.64 0 14.664 0.084 ;
    END
  END k_rsp_data[153]
  PIN k_rsp_data[154]
    DIRECTION INPUT ;
    USE SIGNAL ;
    PORT
      LAYER M5 ;
        RECT  14.736 0 14.76 0.084 ;
    END
  END k_rsp_data[154]
  PIN k_rsp_data[155]
    DIRECTION INPUT ;
    USE SIGNAL ;
    PORT
      LAYER M5 ;
        RECT  14.832 0 14.856 0.084 ;
    END
  END k_rsp_data[155]
  PIN k_rsp_data[156]
    DIRECTION INPUT ;
    USE SIGNAL ;
    PORT
      LAYER M5 ;
        RECT  14.928 0 14.952 0.084 ;
    END
  END k_rsp_data[156]
  PIN k_rsp_data[157]
    DIRECTION INPUT ;
    USE SIGNAL ;
    PORT
      LAYER M5 ;
        RECT  15.024 0 15.048 0.084 ;
    END
  END k_rsp_data[157]
  PIN k_rsp_data[158]
    DIRECTION INPUT ;
    USE SIGNAL ;
    PORT
      LAYER M5 ;
        RECT  15.12 0 15.144 0.084 ;
    END
  END k_rsp_data[158]
  PIN k_rsp_data[159]
    DIRECTION INPUT ;
    USE SIGNAL ;
    PORT
      LAYER M5 ;
        RECT  15.216 0 15.24 0.084 ;
    END
  END k_rsp_data[159]
  PIN k_rsp_data[15]
    DIRECTION INPUT ;
    USE SIGNAL ;
    PORT
      LAYER M5 ;
        RECT  39.792 0 39.816 0.084 ;
    END
  END k_rsp_data[15]
  PIN k_rsp_data[160]
    DIRECTION INPUT ;
    USE SIGNAL ;
    PORT
      LAYER M5 ;
        RECT  15.312 0 15.336 0.084 ;
    END
  END k_rsp_data[160]
  PIN k_rsp_data[161]
    DIRECTION INPUT ;
    USE SIGNAL ;
    PORT
      LAYER M5 ;
        RECT  15.408 0 15.432 0.084 ;
    END
  END k_rsp_data[161]
  PIN k_rsp_data[162]
    DIRECTION INPUT ;
    USE SIGNAL ;
    PORT
      LAYER M5 ;
        RECT  15.504 0 15.528 0.084 ;
    END
  END k_rsp_data[162]
  PIN k_rsp_data[163]
    DIRECTION INPUT ;
    USE SIGNAL ;
    PORT
      LAYER M5 ;
        RECT  15.6 0 15.624 0.084 ;
    END
  END k_rsp_data[163]
  PIN k_rsp_data[164]
    DIRECTION INPUT ;
    USE SIGNAL ;
    PORT
      LAYER M5 ;
        RECT  15.696 0 15.72 0.084 ;
    END
  END k_rsp_data[164]
  PIN k_rsp_data[165]
    DIRECTION INPUT ;
    USE SIGNAL ;
    PORT
      LAYER M5 ;
        RECT  15.792 0 15.816 0.084 ;
    END
  END k_rsp_data[165]
  PIN k_rsp_data[166]
    DIRECTION INPUT ;
    USE SIGNAL ;
    PORT
      LAYER M5 ;
        RECT  15.888 0 15.912 0.084 ;
    END
  END k_rsp_data[166]
  PIN k_rsp_data[167]
    DIRECTION INPUT ;
    USE SIGNAL ;
    PORT
      LAYER M5 ;
        RECT  15.984 0 16.008 0.084 ;
    END
  END k_rsp_data[167]
  PIN k_rsp_data[168]
    DIRECTION INPUT ;
    USE SIGNAL ;
    PORT
      LAYER M5 ;
        RECT  42.192 0 42.216 0.084 ;
    END
  END k_rsp_data[168]
  PIN k_rsp_data[169]
    DIRECTION INPUT ;
    USE SIGNAL ;
    PORT
      LAYER M5 ;
        RECT  42.288 0 42.312 0.084 ;
    END
  END k_rsp_data[169]
  PIN k_rsp_data[16]
    DIRECTION INPUT ;
    USE SIGNAL ;
    PORT
      LAYER M5 ;
        RECT  39.888 0 39.912 0.084 ;
    END
  END k_rsp_data[16]
  PIN k_rsp_data[170]
    DIRECTION INPUT ;
    USE SIGNAL ;
    PORT
      LAYER M5 ;
        RECT  42.384 0 42.408 0.084 ;
    END
  END k_rsp_data[170]
  PIN k_rsp_data[171]
    DIRECTION INPUT ;
    USE SIGNAL ;
    PORT
      LAYER M5 ;
        RECT  42.48 0 42.504 0.084 ;
    END
  END k_rsp_data[171]
  PIN k_rsp_data[172]
    DIRECTION INPUT ;
    USE SIGNAL ;
    PORT
      LAYER M5 ;
        RECT  42.576 0 42.6 0.084 ;
    END
  END k_rsp_data[172]
  PIN k_rsp_data[173]
    DIRECTION INPUT ;
    USE SIGNAL ;
    PORT
      LAYER M5 ;
        RECT  42.672 0 42.696 0.084 ;
    END
  END k_rsp_data[173]
  PIN k_rsp_data[174]
    DIRECTION INPUT ;
    USE SIGNAL ;
    PORT
      LAYER M5 ;
        RECT  42.768 0 42.792 0.084 ;
    END
  END k_rsp_data[174]
  PIN k_rsp_data[175]
    DIRECTION INPUT ;
    USE SIGNAL ;
    PORT
      LAYER M5 ;
        RECT  42.864 0 42.888 0.084 ;
    END
  END k_rsp_data[175]
  PIN k_rsp_data[176]
    DIRECTION INPUT ;
    USE SIGNAL ;
    PORT
      LAYER M5 ;
        RECT  42.96 0 42.984 0.084 ;
    END
  END k_rsp_data[176]
  PIN k_rsp_data[177]
    DIRECTION INPUT ;
    USE SIGNAL ;
    PORT
      LAYER M5 ;
        RECT  43.056 0 43.08 0.084 ;
    END
  END k_rsp_data[177]
  PIN k_rsp_data[178]
    DIRECTION INPUT ;
    USE SIGNAL ;
    PORT
      LAYER M5 ;
        RECT  43.152 0 43.176 0.084 ;
    END
  END k_rsp_data[178]
  PIN k_rsp_data[179]
    DIRECTION INPUT ;
    USE SIGNAL ;
    PORT
      LAYER M5 ;
        RECT  43.248 0 43.272 0.084 ;
    END
  END k_rsp_data[179]
  PIN k_rsp_data[17]
    DIRECTION INPUT ;
    USE SIGNAL ;
    PORT
      LAYER M5 ;
        RECT  39.984 0 40.008 0.084 ;
    END
  END k_rsp_data[17]
  PIN k_rsp_data[180]
    DIRECTION INPUT ;
    USE SIGNAL ;
    PORT
      LAYER M5 ;
        RECT  43.344 0 43.368 0.084 ;
    END
  END k_rsp_data[180]
  PIN k_rsp_data[181]
    DIRECTION INPUT ;
    USE SIGNAL ;
    PORT
      LAYER M5 ;
        RECT  43.44 0 43.464 0.084 ;
    END
  END k_rsp_data[181]
  PIN k_rsp_data[182]
    DIRECTION INPUT ;
    USE SIGNAL ;
    PORT
      LAYER M5 ;
        RECT  43.536 0 43.56 0.084 ;
    END
  END k_rsp_data[182]
  PIN k_rsp_data[183]
    DIRECTION INPUT ;
    USE SIGNAL ;
    PORT
      LAYER M5 ;
        RECT  43.632 0 43.656 0.084 ;
    END
  END k_rsp_data[183]
  PIN k_rsp_data[184]
    DIRECTION INPUT ;
    USE SIGNAL ;
    PORT
      LAYER M5 ;
        RECT  43.728 0 43.752 0.084 ;
    END
  END k_rsp_data[184]
  PIN k_rsp_data[185]
    DIRECTION INPUT ;
    USE SIGNAL ;
    PORT
      LAYER M5 ;
        RECT  43.824 0 43.848 0.084 ;
    END
  END k_rsp_data[185]
  PIN k_rsp_data[186]
    DIRECTION INPUT ;
    USE SIGNAL ;
    PORT
      LAYER M5 ;
        RECT  43.92 0 43.944 0.084 ;
    END
  END k_rsp_data[186]
  PIN k_rsp_data[187]
    DIRECTION INPUT ;
    USE SIGNAL ;
    PORT
      LAYER M5 ;
        RECT  44.016 0 44.04 0.084 ;
    END
  END k_rsp_data[187]
  PIN k_rsp_data[188]
    DIRECTION INPUT ;
    USE SIGNAL ;
    PORT
      LAYER M5 ;
        RECT  44.112 0 44.136 0.084 ;
    END
  END k_rsp_data[188]
  PIN k_rsp_data[189]
    DIRECTION INPUT ;
    USE SIGNAL ;
    PORT
      LAYER M5 ;
        RECT  44.208 0 44.232 0.084 ;
    END
  END k_rsp_data[189]
  PIN k_rsp_data[18]
    DIRECTION INPUT ;
    USE SIGNAL ;
    PORT
      LAYER M5 ;
        RECT  40.08 0 40.104 0.084 ;
    END
  END k_rsp_data[18]
  PIN k_rsp_data[190]
    DIRECTION INPUT ;
    USE SIGNAL ;
    PORT
      LAYER M5 ;
        RECT  44.304 0 44.328 0.084 ;
    END
  END k_rsp_data[190]
  PIN k_rsp_data[191]
    DIRECTION INPUT ;
    USE SIGNAL ;
    PORT
      LAYER M5 ;
        RECT  44.4 0 44.424 0.084 ;
    END
  END k_rsp_data[191]
  PIN k_rsp_data[192]
    DIRECTION INPUT ;
    USE SIGNAL ;
    PORT
      LAYER M5 ;
        RECT  44.496 0 44.52 0.084 ;
    END
  END k_rsp_data[192]
  PIN k_rsp_data[193]
    DIRECTION INPUT ;
    USE SIGNAL ;
    PORT
      LAYER M5 ;
        RECT  44.592 0 44.616 0.084 ;
    END
  END k_rsp_data[193]
  PIN k_rsp_data[194]
    DIRECTION INPUT ;
    USE SIGNAL ;
    PORT
      LAYER M5 ;
        RECT  44.688 0 44.712 0.084 ;
    END
  END k_rsp_data[194]
  PIN k_rsp_data[195]
    DIRECTION INPUT ;
    USE SIGNAL ;
    PORT
      LAYER M5 ;
        RECT  44.784 0 44.808 0.084 ;
    END
  END k_rsp_data[195]
  PIN k_rsp_data[196]
    DIRECTION INPUT ;
    USE SIGNAL ;
    PORT
      LAYER M5 ;
        RECT  44.88 0 44.904 0.084 ;
    END
  END k_rsp_data[196]
  PIN k_rsp_data[197]
    DIRECTION INPUT ;
    USE SIGNAL ;
    PORT
      LAYER M5 ;
        RECT  44.976 0 45 0.084 ;
    END
  END k_rsp_data[197]
  PIN k_rsp_data[198]
    DIRECTION INPUT ;
    USE SIGNAL ;
    PORT
      LAYER M5 ;
        RECT  45.072 0 45.096 0.084 ;
    END
  END k_rsp_data[198]
  PIN k_rsp_data[199]
    DIRECTION INPUT ;
    USE SIGNAL ;
    PORT
      LAYER M5 ;
        RECT  45.168 0 45.192 0.084 ;
    END
  END k_rsp_data[199]
  PIN k_rsp_data[19]
    DIRECTION INPUT ;
    USE SIGNAL ;
    PORT
      LAYER M5 ;
        RECT  40.176 0 40.2 0.084 ;
    END
  END k_rsp_data[19]
  PIN k_rsp_data[1]
    DIRECTION INPUT ;
    USE SIGNAL ;
    PORT
      LAYER M5 ;
        RECT  18.48 0 18.504 0.084 ;
    END
  END k_rsp_data[1]
  PIN k_rsp_data[200]
    DIRECTION INPUT ;
    USE SIGNAL ;
    PORT
      LAYER M5 ;
        RECT  6.864 0 6.888 0.084 ;
    END
  END k_rsp_data[200]
  PIN k_rsp_data[201]
    DIRECTION INPUT ;
    USE SIGNAL ;
    PORT
      LAYER M5 ;
        RECT  6.96 0 6.984 0.084 ;
    END
  END k_rsp_data[201]
  PIN k_rsp_data[202]
    DIRECTION INPUT ;
    USE SIGNAL ;
    PORT
      LAYER M5 ;
        RECT  7.056 0 7.08 0.084 ;
    END
  END k_rsp_data[202]
  PIN k_rsp_data[203]
    DIRECTION INPUT ;
    USE SIGNAL ;
    PORT
      LAYER M5 ;
        RECT  7.152 0 7.176 0.084 ;
    END
  END k_rsp_data[203]
  PIN k_rsp_data[204]
    DIRECTION INPUT ;
    USE SIGNAL ;
    PORT
      LAYER M5 ;
        RECT  7.248 0 7.272 0.084 ;
    END
  END k_rsp_data[204]
  PIN k_rsp_data[205]
    DIRECTION INPUT ;
    USE SIGNAL ;
    PORT
      LAYER M5 ;
        RECT  7.344 0 7.368 0.084 ;
    END
  END k_rsp_data[205]
  PIN k_rsp_data[206]
    DIRECTION INPUT ;
    USE SIGNAL ;
    PORT
      LAYER M5 ;
        RECT  7.44 0 7.464 0.084 ;
    END
  END k_rsp_data[206]
  PIN k_rsp_data[207]
    DIRECTION INPUT ;
    USE SIGNAL ;
    PORT
      LAYER M5 ;
        RECT  7.536 0 7.56 0.084 ;
    END
  END k_rsp_data[207]
  PIN k_rsp_data[208]
    DIRECTION INPUT ;
    USE SIGNAL ;
    PORT
      LAYER M5 ;
        RECT  7.632 0 7.656 0.084 ;
    END
  END k_rsp_data[208]
  PIN k_rsp_data[209]
    DIRECTION INPUT ;
    USE SIGNAL ;
    PORT
      LAYER M5 ;
        RECT  7.728 0 7.752 0.084 ;
    END
  END k_rsp_data[209]
  PIN k_rsp_data[20]
    DIRECTION INPUT ;
    USE SIGNAL ;
    PORT
      LAYER M5 ;
        RECT  40.272 0 40.296 0.084 ;
    END
  END k_rsp_data[20]
  PIN k_rsp_data[210]
    DIRECTION INPUT ;
    USE SIGNAL ;
    PORT
      LAYER M5 ;
        RECT  7.824 0 7.848 0.084 ;
    END
  END k_rsp_data[210]
  PIN k_rsp_data[211]
    DIRECTION INPUT ;
    USE SIGNAL ;
    PORT
      LAYER M5 ;
        RECT  7.92 0 7.944 0.084 ;
    END
  END k_rsp_data[211]
  PIN k_rsp_data[212]
    DIRECTION INPUT ;
    USE SIGNAL ;
    PORT
      LAYER M5 ;
        RECT  8.016 0 8.04 0.084 ;
    END
  END k_rsp_data[212]
  PIN k_rsp_data[213]
    DIRECTION INPUT ;
    USE SIGNAL ;
    PORT
      LAYER M5 ;
        RECT  8.112 0 8.136 0.084 ;
    END
  END k_rsp_data[213]
  PIN k_rsp_data[214]
    DIRECTION INPUT ;
    USE SIGNAL ;
    PORT
      LAYER M5 ;
        RECT  8.208 0 8.232 0.084 ;
    END
  END k_rsp_data[214]
  PIN k_rsp_data[215]
    DIRECTION INPUT ;
    USE SIGNAL ;
    PORT
      LAYER M5 ;
        RECT  8.304 0 8.328 0.084 ;
    END
  END k_rsp_data[215]
  PIN k_rsp_data[216]
    DIRECTION INPUT ;
    USE SIGNAL ;
    PORT
      LAYER M5 ;
        RECT  8.4 0 8.424 0.084 ;
    END
  END k_rsp_data[216]
  PIN k_rsp_data[217]
    DIRECTION INPUT ;
    USE SIGNAL ;
    PORT
      LAYER M5 ;
        RECT  8.496 0 8.52 0.084 ;
    END
  END k_rsp_data[217]
  PIN k_rsp_data[218]
    DIRECTION INPUT ;
    USE SIGNAL ;
    PORT
      LAYER M5 ;
        RECT  8.592 0 8.616 0.084 ;
    END
  END k_rsp_data[218]
  PIN k_rsp_data[219]
    DIRECTION INPUT ;
    USE SIGNAL ;
    PORT
      LAYER M5 ;
        RECT  8.688 0 8.712 0.084 ;
    END
  END k_rsp_data[219]
  PIN k_rsp_data[21]
    DIRECTION INPUT ;
    USE SIGNAL ;
    PORT
      LAYER M5 ;
        RECT  40.368 0 40.392 0.084 ;
    END
  END k_rsp_data[21]
  PIN k_rsp_data[220]
    DIRECTION INPUT ;
    USE SIGNAL ;
    PORT
      LAYER M5 ;
        RECT  8.784 0 8.808 0.084 ;
    END
  END k_rsp_data[220]
  PIN k_rsp_data[221]
    DIRECTION INPUT ;
    USE SIGNAL ;
    PORT
      LAYER M5 ;
        RECT  8.88 0 8.904 0.084 ;
    END
  END k_rsp_data[221]
  PIN k_rsp_data[222]
    DIRECTION INPUT ;
    USE SIGNAL ;
    PORT
      LAYER M5 ;
        RECT  8.976 0 9 0.084 ;
    END
  END k_rsp_data[222]
  PIN k_rsp_data[223]
    DIRECTION INPUT ;
    USE SIGNAL ;
    PORT
      LAYER M5 ;
        RECT  9.072 0 9.096 0.084 ;
    END
  END k_rsp_data[223]
  PIN k_rsp_data[224]
    DIRECTION INPUT ;
    USE SIGNAL ;
    PORT
      LAYER M5 ;
        RECT  9.168 0 9.192 0.084 ;
    END
  END k_rsp_data[224]
  PIN k_rsp_data[225]
    DIRECTION INPUT ;
    USE SIGNAL ;
    PORT
      LAYER M5 ;
        RECT  9.264 0 9.288 0.084 ;
    END
  END k_rsp_data[225]
  PIN k_rsp_data[226]
    DIRECTION INPUT ;
    USE SIGNAL ;
    PORT
      LAYER M5 ;
        RECT  9.36 0 9.384 0.084 ;
    END
  END k_rsp_data[226]
  PIN k_rsp_data[227]
    DIRECTION INPUT ;
    USE SIGNAL ;
    PORT
      LAYER M5 ;
        RECT  9.456 0 9.48 0.084 ;
    END
  END k_rsp_data[227]
  PIN k_rsp_data[228]
    DIRECTION INPUT ;
    USE SIGNAL ;
    PORT
      LAYER M5 ;
        RECT  9.552 0 9.576 0.084 ;
    END
  END k_rsp_data[228]
  PIN k_rsp_data[229]
    DIRECTION INPUT ;
    USE SIGNAL ;
    PORT
      LAYER M5 ;
        RECT  9.648 0 9.672 0.084 ;
    END
  END k_rsp_data[229]
  PIN k_rsp_data[22]
    DIRECTION INPUT ;
    USE SIGNAL ;
    PORT
      LAYER M5 ;
        RECT  40.464 0 40.488 0.084 ;
    END
  END k_rsp_data[22]
  PIN k_rsp_data[230]
    DIRECTION INPUT ;
    USE SIGNAL ;
    PORT
      LAYER M5 ;
        RECT  9.744 0 9.768 0.084 ;
    END
  END k_rsp_data[230]
  PIN k_rsp_data[231]
    DIRECTION INPUT ;
    USE SIGNAL ;
    PORT
      LAYER M5 ;
        RECT  9.84 0 9.864 0.084 ;
    END
  END k_rsp_data[231]
  PIN k_rsp_data[232]
    DIRECTION INPUT ;
    USE SIGNAL ;
    PORT
      LAYER M5 ;
        RECT  58.32 0 58.344 0.084 ;
    END
  END k_rsp_data[232]
  PIN k_rsp_data[233]
    DIRECTION INPUT ;
    USE SIGNAL ;
    PORT
      LAYER M5 ;
        RECT  58.416 0 58.44 0.084 ;
    END
  END k_rsp_data[233]
  PIN k_rsp_data[234]
    DIRECTION INPUT ;
    USE SIGNAL ;
    PORT
      LAYER M5 ;
        RECT  58.512 0 58.536 0.084 ;
    END
  END k_rsp_data[234]
  PIN k_rsp_data[235]
    DIRECTION INPUT ;
    USE SIGNAL ;
    PORT
      LAYER M5 ;
        RECT  58.608 0 58.632 0.084 ;
    END
  END k_rsp_data[235]
  PIN k_rsp_data[236]
    DIRECTION INPUT ;
    USE SIGNAL ;
    PORT
      LAYER M5 ;
        RECT  58.704 0 58.728 0.084 ;
    END
  END k_rsp_data[236]
  PIN k_rsp_data[237]
    DIRECTION INPUT ;
    USE SIGNAL ;
    PORT
      LAYER M5 ;
        RECT  58.8 0 58.824 0.084 ;
    END
  END k_rsp_data[237]
  PIN k_rsp_data[238]
    DIRECTION INPUT ;
    USE SIGNAL ;
    PORT
      LAYER M5 ;
        RECT  58.896 0 58.92 0.084 ;
    END
  END k_rsp_data[238]
  PIN k_rsp_data[239]
    DIRECTION INPUT ;
    USE SIGNAL ;
    PORT
      LAYER M5 ;
        RECT  58.992 0 59.016 0.084 ;
    END
  END k_rsp_data[239]
  PIN k_rsp_data[23]
    DIRECTION INPUT ;
    USE SIGNAL ;
    PORT
      LAYER M5 ;
        RECT  40.56 0 40.584 0.084 ;
    END
  END k_rsp_data[23]
  PIN k_rsp_data[240]
    DIRECTION INPUT ;
    USE SIGNAL ;
    PORT
      LAYER M5 ;
        RECT  59.088 0 59.112 0.084 ;
    END
  END k_rsp_data[240]
  PIN k_rsp_data[241]
    DIRECTION INPUT ;
    USE SIGNAL ;
    PORT
      LAYER M5 ;
        RECT  59.184 0 59.208 0.084 ;
    END
  END k_rsp_data[241]
  PIN k_rsp_data[242]
    DIRECTION INPUT ;
    USE SIGNAL ;
    PORT
      LAYER M5 ;
        RECT  59.28 0 59.304 0.084 ;
    END
  END k_rsp_data[242]
  PIN k_rsp_data[243]
    DIRECTION INPUT ;
    USE SIGNAL ;
    PORT
      LAYER M5 ;
        RECT  59.376 0 59.4 0.084 ;
    END
  END k_rsp_data[243]
  PIN k_rsp_data[244]
    DIRECTION INPUT ;
    USE SIGNAL ;
    PORT
      LAYER M5 ;
        RECT  59.472 0 59.496 0.084 ;
    END
  END k_rsp_data[244]
  PIN k_rsp_data[245]
    DIRECTION INPUT ;
    USE SIGNAL ;
    PORT
      LAYER M5 ;
        RECT  59.568 0 59.592 0.084 ;
    END
  END k_rsp_data[245]
  PIN k_rsp_data[246]
    DIRECTION INPUT ;
    USE SIGNAL ;
    PORT
      LAYER M5 ;
        RECT  59.664 0 59.688 0.084 ;
    END
  END k_rsp_data[246]
  PIN k_rsp_data[247]
    DIRECTION INPUT ;
    USE SIGNAL ;
    PORT
      LAYER M5 ;
        RECT  59.76 0 59.784 0.084 ;
    END
  END k_rsp_data[247]
  PIN k_rsp_data[248]
    DIRECTION INPUT ;
    USE SIGNAL ;
    PORT
      LAYER M5 ;
        RECT  59.856 0 59.88 0.084 ;
    END
  END k_rsp_data[248]
  PIN k_rsp_data[249]
    DIRECTION INPUT ;
    USE SIGNAL ;
    PORT
      LAYER M5 ;
        RECT  59.952 0 59.976 0.084 ;
    END
  END k_rsp_data[249]
  PIN k_rsp_data[24]
    DIRECTION INPUT ;
    USE SIGNAL ;
    PORT
      LAYER M5 ;
        RECT  40.656 0 40.68 0.084 ;
    END
  END k_rsp_data[24]
  PIN k_rsp_data[250]
    DIRECTION INPUT ;
    USE SIGNAL ;
    PORT
      LAYER M5 ;
        RECT  60.048 0 60.072 0.084 ;
    END
  END k_rsp_data[250]
  PIN k_rsp_data[251]
    DIRECTION INPUT ;
    USE SIGNAL ;
    PORT
      LAYER M5 ;
        RECT  60.144 0 60.168 0.084 ;
    END
  END k_rsp_data[251]
  PIN k_rsp_data[252]
    DIRECTION INPUT ;
    USE SIGNAL ;
    PORT
      LAYER M5 ;
        RECT  60.24 0 60.264 0.084 ;
    END
  END k_rsp_data[252]
  PIN k_rsp_data[253]
    DIRECTION INPUT ;
    USE SIGNAL ;
    PORT
      LAYER M5 ;
        RECT  60.336 0 60.36 0.084 ;
    END
  END k_rsp_data[253]
  PIN k_rsp_data[254]
    DIRECTION INPUT ;
    USE SIGNAL ;
    PORT
      LAYER M5 ;
        RECT  60.432 0 60.456 0.084 ;
    END
  END k_rsp_data[254]
  PIN k_rsp_data[255]
    DIRECTION INPUT ;
    USE SIGNAL ;
    PORT
      LAYER M5 ;
        RECT  60.528 0 60.552 0.084 ;
    END
  END k_rsp_data[255]
  PIN k_rsp_data[25]
    DIRECTION INPUT ;
    USE SIGNAL ;
    PORT
      LAYER M5 ;
        RECT  40.752 0 40.776 0.084 ;
    END
  END k_rsp_data[25]
  PIN k_rsp_data[26]
    DIRECTION INPUT ;
    USE SIGNAL ;
    PORT
      LAYER M5 ;
        RECT  40.848 0 40.872 0.084 ;
    END
  END k_rsp_data[26]
  PIN k_rsp_data[27]
    DIRECTION INPUT ;
    USE SIGNAL ;
    PORT
      LAYER M5 ;
        RECT  40.944 0 40.968 0.084 ;
    END
  END k_rsp_data[27]
  PIN k_rsp_data[28]
    DIRECTION INPUT ;
    USE SIGNAL ;
    PORT
      LAYER M5 ;
        RECT  41.04 0 41.064 0.084 ;
    END
  END k_rsp_data[28]
  PIN k_rsp_data[29]
    DIRECTION INPUT ;
    USE SIGNAL ;
    PORT
      LAYER M5 ;
        RECT  41.136 0 41.16 0.084 ;
    END
  END k_rsp_data[29]
  PIN k_rsp_data[2]
    DIRECTION INPUT ;
    USE SIGNAL ;
    PORT
      LAYER M5 ;
        RECT  18.576 0 18.6 0.084 ;
    END
  END k_rsp_data[2]
  PIN k_rsp_data[30]
    DIRECTION INPUT ;
    USE SIGNAL ;
    PORT
      LAYER M5 ;
        RECT  41.232 0 41.256 0.084 ;
    END
  END k_rsp_data[30]
  PIN k_rsp_data[31]
    DIRECTION INPUT ;
    USE SIGNAL ;
    PORT
      LAYER M5 ;
        RECT  41.328 0 41.352 0.084 ;
    END
  END k_rsp_data[31]
  PIN k_rsp_data[32]
    DIRECTION INPUT ;
    USE SIGNAL ;
    PORT
      LAYER M5 ;
        RECT  41.424 0 41.448 0.084 ;
    END
  END k_rsp_data[32]
  PIN k_rsp_data[33]
    DIRECTION INPUT ;
    USE SIGNAL ;
    PORT
      LAYER M5 ;
        RECT  41.52 0 41.544 0.084 ;
    END
  END k_rsp_data[33]
  PIN k_rsp_data[34]
    DIRECTION INPUT ;
    USE SIGNAL ;
    PORT
      LAYER M5 ;
        RECT  41.616 0 41.64 0.084 ;
    END
  END k_rsp_data[34]
  PIN k_rsp_data[35]
    DIRECTION INPUT ;
    USE SIGNAL ;
    PORT
      LAYER M5 ;
        RECT  41.712 0 41.736 0.084 ;
    END
  END k_rsp_data[35]
  PIN k_rsp_data[36]
    DIRECTION INPUT ;
    USE SIGNAL ;
    PORT
      LAYER M5 ;
        RECT  41.808 0 41.832 0.084 ;
    END
  END k_rsp_data[36]
  PIN k_rsp_data[37]
    DIRECTION INPUT ;
    USE SIGNAL ;
    PORT
      LAYER M5 ;
        RECT  41.904 0 41.928 0.084 ;
    END
  END k_rsp_data[37]
  PIN k_rsp_data[38]
    DIRECTION INPUT ;
    USE SIGNAL ;
    PORT
      LAYER M5 ;
        RECT  42 0 42.024 0.084 ;
    END
  END k_rsp_data[38]
  PIN k_rsp_data[39]
    DIRECTION INPUT ;
    USE SIGNAL ;
    PORT
      LAYER M5 ;
        RECT  42.096 0 42.12 0.084 ;
    END
  END k_rsp_data[39]
  PIN k_rsp_data[3]
    DIRECTION INPUT ;
    USE SIGNAL ;
    PORT
      LAYER M5 ;
        RECT  18.672 0 18.696 0.084 ;
    END
  END k_rsp_data[3]
  PIN k_rsp_data[40]
    DIRECTION INPUT ;
    USE SIGNAL ;
    PORT
      LAYER M5 ;
        RECT  3.792 0 3.816 0.084 ;
    END
  END k_rsp_data[40]
  PIN k_rsp_data[41]
    DIRECTION INPUT ;
    USE SIGNAL ;
    PORT
      LAYER M5 ;
        RECT  3.888 0 3.912 0.084 ;
    END
  END k_rsp_data[41]
  PIN k_rsp_data[42]
    DIRECTION INPUT ;
    USE SIGNAL ;
    PORT
      LAYER M5 ;
        RECT  3.984 0 4.008 0.084 ;
    END
  END k_rsp_data[42]
  PIN k_rsp_data[43]
    DIRECTION INPUT ;
    USE SIGNAL ;
    PORT
      LAYER M5 ;
        RECT  4.08 0 4.104 0.084 ;
    END
  END k_rsp_data[43]
  PIN k_rsp_data[44]
    DIRECTION INPUT ;
    USE SIGNAL ;
    PORT
      LAYER M5 ;
        RECT  4.176 0 4.2 0.084 ;
    END
  END k_rsp_data[44]
  PIN k_rsp_data[45]
    DIRECTION INPUT ;
    USE SIGNAL ;
    PORT
      LAYER M5 ;
        RECT  4.272 0 4.296 0.084 ;
    END
  END k_rsp_data[45]
  PIN k_rsp_data[46]
    DIRECTION INPUT ;
    USE SIGNAL ;
    PORT
      LAYER M5 ;
        RECT  4.368 0 4.392 0.084 ;
    END
  END k_rsp_data[46]
  PIN k_rsp_data[47]
    DIRECTION INPUT ;
    USE SIGNAL ;
    PORT
      LAYER M5 ;
        RECT  4.464 0 4.488 0.084 ;
    END
  END k_rsp_data[47]
  PIN k_rsp_data[48]
    DIRECTION INPUT ;
    USE SIGNAL ;
    PORT
      LAYER M5 ;
        RECT  4.56 0 4.584 0.084 ;
    END
  END k_rsp_data[48]
  PIN k_rsp_data[49]
    DIRECTION INPUT ;
    USE SIGNAL ;
    PORT
      LAYER M5 ;
        RECT  4.656 0 4.68 0.084 ;
    END
  END k_rsp_data[49]
  PIN k_rsp_data[4]
    DIRECTION INPUT ;
    USE SIGNAL ;
    PORT
      LAYER M5 ;
        RECT  18.768 0 18.792 0.084 ;
    END
  END k_rsp_data[4]
  PIN k_rsp_data[50]
    DIRECTION INPUT ;
    USE SIGNAL ;
    PORT
      LAYER M5 ;
        RECT  4.752 0 4.776 0.084 ;
    END
  END k_rsp_data[50]
  PIN k_rsp_data[51]
    DIRECTION INPUT ;
    USE SIGNAL ;
    PORT
      LAYER M5 ;
        RECT  4.848 0 4.872 0.084 ;
    END
  END k_rsp_data[51]
  PIN k_rsp_data[52]
    DIRECTION INPUT ;
    USE SIGNAL ;
    PORT
      LAYER M5 ;
        RECT  4.944 0 4.968 0.084 ;
    END
  END k_rsp_data[52]
  PIN k_rsp_data[53]
    DIRECTION INPUT ;
    USE SIGNAL ;
    PORT
      LAYER M5 ;
        RECT  5.04 0 5.064 0.084 ;
    END
  END k_rsp_data[53]
  PIN k_rsp_data[54]
    DIRECTION INPUT ;
    USE SIGNAL ;
    PORT
      LAYER M5 ;
        RECT  5.136 0 5.16 0.084 ;
    END
  END k_rsp_data[54]
  PIN k_rsp_data[55]
    DIRECTION INPUT ;
    USE SIGNAL ;
    PORT
      LAYER M5 ;
        RECT  5.232 0 5.256 0.084 ;
    END
  END k_rsp_data[55]
  PIN k_rsp_data[56]
    DIRECTION INPUT ;
    USE SIGNAL ;
    PORT
      LAYER M5 ;
        RECT  5.328 0 5.352 0.084 ;
    END
  END k_rsp_data[56]
  PIN k_rsp_data[57]
    DIRECTION INPUT ;
    USE SIGNAL ;
    PORT
      LAYER M5 ;
        RECT  5.424 0 5.448 0.084 ;
    END
  END k_rsp_data[57]
  PIN k_rsp_data[58]
    DIRECTION INPUT ;
    USE SIGNAL ;
    PORT
      LAYER M5 ;
        RECT  5.52 0 5.544 0.084 ;
    END
  END k_rsp_data[58]
  PIN k_rsp_data[59]
    DIRECTION INPUT ;
    USE SIGNAL ;
    PORT
      LAYER M5 ;
        RECT  5.616 0 5.64 0.084 ;
    END
  END k_rsp_data[59]
  PIN k_rsp_data[5]
    DIRECTION INPUT ;
    USE SIGNAL ;
    PORT
      LAYER M5 ;
        RECT  18.864 0 18.888 0.084 ;
    END
  END k_rsp_data[5]
  PIN k_rsp_data[60]
    DIRECTION INPUT ;
    USE SIGNAL ;
    PORT
      LAYER M5 ;
        RECT  5.712 0 5.736 0.084 ;
    END
  END k_rsp_data[60]
  PIN k_rsp_data[61]
    DIRECTION INPUT ;
    USE SIGNAL ;
    PORT
      LAYER M5 ;
        RECT  5.808 0 5.832 0.084 ;
    END
  END k_rsp_data[61]
  PIN k_rsp_data[62]
    DIRECTION INPUT ;
    USE SIGNAL ;
    PORT
      LAYER M5 ;
        RECT  5.904 0 5.928 0.084 ;
    END
  END k_rsp_data[62]
  PIN k_rsp_data[63]
    DIRECTION INPUT ;
    USE SIGNAL ;
    PORT
      LAYER M5 ;
        RECT  6 0 6.024 0.084 ;
    END
  END k_rsp_data[63]
  PIN k_rsp_data[64]
    DIRECTION INPUT ;
    USE SIGNAL ;
    PORT
      LAYER M5 ;
        RECT  6.096 0 6.12 0.084 ;
    END
  END k_rsp_data[64]
  PIN k_rsp_data[65]
    DIRECTION INPUT ;
    USE SIGNAL ;
    PORT
      LAYER M5 ;
        RECT  6.192 0 6.216 0.084 ;
    END
  END k_rsp_data[65]
  PIN k_rsp_data[66]
    DIRECTION INPUT ;
    USE SIGNAL ;
    PORT
      LAYER M5 ;
        RECT  6.288 0 6.312 0.084 ;
    END
  END k_rsp_data[66]
  PIN k_rsp_data[67]
    DIRECTION INPUT ;
    USE SIGNAL ;
    PORT
      LAYER M5 ;
        RECT  6.384 0 6.408 0.084 ;
    END
  END k_rsp_data[67]
  PIN k_rsp_data[68]
    DIRECTION INPUT ;
    USE SIGNAL ;
    PORT
      LAYER M5 ;
        RECT  6.48 0 6.504 0.084 ;
    END
  END k_rsp_data[68]
  PIN k_rsp_data[69]
    DIRECTION INPUT ;
    USE SIGNAL ;
    PORT
      LAYER M5 ;
        RECT  6.576 0 6.6 0.084 ;
    END
  END k_rsp_data[69]
  PIN k_rsp_data[6]
    DIRECTION INPUT ;
    USE SIGNAL ;
    PORT
      LAYER M5 ;
        RECT  18.96 0 18.984 0.084 ;
    END
  END k_rsp_data[6]
  PIN k_rsp_data[70]
    DIRECTION INPUT ;
    USE SIGNAL ;
    PORT
      LAYER M5 ;
        RECT  6.672 0 6.696 0.084 ;
    END
  END k_rsp_data[70]
  PIN k_rsp_data[71]
    DIRECTION INPUT ;
    USE SIGNAL ;
    PORT
      LAYER M5 ;
        RECT  6.768 0 6.792 0.084 ;
    END
  END k_rsp_data[71]
  PIN k_rsp_data[72]
    DIRECTION INPUT ;
    USE SIGNAL ;
    PORT
      LAYER M5 ;
        RECT  9.936 0 9.96 0.084 ;
    END
  END k_rsp_data[72]
  PIN k_rsp_data[73]
    DIRECTION INPUT ;
    USE SIGNAL ;
    PORT
      LAYER M5 ;
        RECT  10.032 0 10.056 0.084 ;
    END
  END k_rsp_data[73]
  PIN k_rsp_data[74]
    DIRECTION INPUT ;
    USE SIGNAL ;
    PORT
      LAYER M5 ;
        RECT  10.128 0 10.152 0.084 ;
    END
  END k_rsp_data[74]
  PIN k_rsp_data[75]
    DIRECTION INPUT ;
    USE SIGNAL ;
    PORT
      LAYER M5 ;
        RECT  10.224 0 10.248 0.084 ;
    END
  END k_rsp_data[75]
  PIN k_rsp_data[76]
    DIRECTION INPUT ;
    USE SIGNAL ;
    PORT
      LAYER M5 ;
        RECT  10.32 0 10.344 0.084 ;
    END
  END k_rsp_data[76]
  PIN k_rsp_data[77]
    DIRECTION INPUT ;
    USE SIGNAL ;
    PORT
      LAYER M5 ;
        RECT  10.416 0 10.44 0.084 ;
    END
  END k_rsp_data[77]
  PIN k_rsp_data[78]
    DIRECTION INPUT ;
    USE SIGNAL ;
    PORT
      LAYER M5 ;
        RECT  10.512 0 10.536 0.084 ;
    END
  END k_rsp_data[78]
  PIN k_rsp_data[79]
    DIRECTION INPUT ;
    USE SIGNAL ;
    PORT
      LAYER M5 ;
        RECT  10.608 0 10.632 0.084 ;
    END
  END k_rsp_data[79]
  PIN k_rsp_data[7]
    DIRECTION INPUT ;
    USE SIGNAL ;
    PORT
      LAYER M5 ;
        RECT  19.056 0 19.08 0.084 ;
    END
  END k_rsp_data[7]
  PIN k_rsp_data[80]
    DIRECTION INPUT ;
    USE SIGNAL ;
    PORT
      LAYER M5 ;
        RECT  10.704 0 10.728 0.084 ;
    END
  END k_rsp_data[80]
  PIN k_rsp_data[81]
    DIRECTION INPUT ;
    USE SIGNAL ;
    PORT
      LAYER M5 ;
        RECT  10.8 0 10.824 0.084 ;
    END
  END k_rsp_data[81]
  PIN k_rsp_data[82]
    DIRECTION INPUT ;
    USE SIGNAL ;
    PORT
      LAYER M5 ;
        RECT  10.896 0 10.92 0.084 ;
    END
  END k_rsp_data[82]
  PIN k_rsp_data[83]
    DIRECTION INPUT ;
    USE SIGNAL ;
    PORT
      LAYER M5 ;
        RECT  10.992 0 11.016 0.084 ;
    END
  END k_rsp_data[83]
  PIN k_rsp_data[84]
    DIRECTION INPUT ;
    USE SIGNAL ;
    PORT
      LAYER M5 ;
        RECT  11.088 0 11.112 0.084 ;
    END
  END k_rsp_data[84]
  PIN k_rsp_data[85]
    DIRECTION INPUT ;
    USE SIGNAL ;
    PORT
      LAYER M5 ;
        RECT  11.184 0 11.208 0.084 ;
    END
  END k_rsp_data[85]
  PIN k_rsp_data[86]
    DIRECTION INPUT ;
    USE SIGNAL ;
    PORT
      LAYER M5 ;
        RECT  11.28 0 11.304 0.084 ;
    END
  END k_rsp_data[86]
  PIN k_rsp_data[87]
    DIRECTION INPUT ;
    USE SIGNAL ;
    PORT
      LAYER M5 ;
        RECT  11.376 0 11.4 0.084 ;
    END
  END k_rsp_data[87]
  PIN k_rsp_data[88]
    DIRECTION INPUT ;
    USE SIGNAL ;
    PORT
      LAYER M5 ;
        RECT  11.472 0 11.496 0.084 ;
    END
  END k_rsp_data[88]
  PIN k_rsp_data[89]
    DIRECTION INPUT ;
    USE SIGNAL ;
    PORT
      LAYER M5 ;
        RECT  11.568 0 11.592 0.084 ;
    END
  END k_rsp_data[89]
  PIN k_rsp_data[8]
    DIRECTION INPUT ;
    USE SIGNAL ;
    PORT
      LAYER M5 ;
        RECT  39.12 0 39.144 0.084 ;
    END
  END k_rsp_data[8]
  PIN k_rsp_data[90]
    DIRECTION INPUT ;
    USE SIGNAL ;
    PORT
      LAYER M5 ;
        RECT  11.664 0 11.688 0.084 ;
    END
  END k_rsp_data[90]
  PIN k_rsp_data[91]
    DIRECTION INPUT ;
    USE SIGNAL ;
    PORT
      LAYER M5 ;
        RECT  11.76 0 11.784 0.084 ;
    END
  END k_rsp_data[91]
  PIN k_rsp_data[92]
    DIRECTION INPUT ;
    USE SIGNAL ;
    PORT
      LAYER M5 ;
        RECT  11.856 0 11.88 0.084 ;
    END
  END k_rsp_data[92]
  PIN k_rsp_data[93]
    DIRECTION INPUT ;
    USE SIGNAL ;
    PORT
      LAYER M5 ;
        RECT  11.952 0 11.976 0.084 ;
    END
  END k_rsp_data[93]
  PIN k_rsp_data[94]
    DIRECTION INPUT ;
    USE SIGNAL ;
    PORT
      LAYER M5 ;
        RECT  12.048 0 12.072 0.084 ;
    END
  END k_rsp_data[94]
  PIN k_rsp_data[95]
    DIRECTION INPUT ;
    USE SIGNAL ;
    PORT
      LAYER M5 ;
        RECT  12.144 0 12.168 0.084 ;
    END
  END k_rsp_data[95]
  PIN k_rsp_data[96]
    DIRECTION INPUT ;
    USE SIGNAL ;
    PORT
      LAYER M5 ;
        RECT  12.24 0 12.264 0.084 ;
    END
  END k_rsp_data[96]
  PIN k_rsp_data[97]
    DIRECTION INPUT ;
    USE SIGNAL ;
    PORT
      LAYER M5 ;
        RECT  12.336 0 12.36 0.084 ;
    END
  END k_rsp_data[97]
  PIN k_rsp_data[98]
    DIRECTION INPUT ;
    USE SIGNAL ;
    PORT
      LAYER M5 ;
        RECT  12.432 0 12.456 0.084 ;
    END
  END k_rsp_data[98]
  PIN k_rsp_data[99]
    DIRECTION INPUT ;
    USE SIGNAL ;
    PORT
      LAYER M5 ;
        RECT  12.528 0 12.552 0.084 ;
    END
  END k_rsp_data[99]
  PIN k_rsp_data[9]
    DIRECTION INPUT ;
    USE SIGNAL ;
    PORT
      LAYER M5 ;
        RECT  39.216 0 39.24 0.084 ;
    END
  END k_rsp_data[9]
  PIN k_rsp_v
    DIRECTION INPUT ;
    USE SIGNAL ;
    PORT
      LAYER M5 ;
        RECT  60.624 0 60.648 0.084 ;
    END
  END k_rsp_v
  PIN k_rsp_we
    DIRECTION INPUT ;
    USE SIGNAL ;
    PORT
      LAYER M5 ;
        RECT  60.72 0 60.744 0.084 ;
    END
  END k_rsp_we
  PIN kc_cr[0]
    DIRECTION OUTPUT ;
    USE SIGNAL ;
    PORT
      LAYER M4 ;
        RECT  0 4.848 0.084 4.872 ;
    END
  END kc_cr[0]
  PIN kc_cr[100]
    DIRECTION OUTPUT ;
    USE SIGNAL ;
    PORT
      LAYER M4 ;
        RECT  0 14.448 0.084 14.472 ;
    END
  END kc_cr[100]
  PIN kc_cr[101]
    DIRECTION OUTPUT ;
    USE SIGNAL ;
    PORT
      LAYER M4 ;
        RECT  0 14.544 0.084 14.568 ;
    END
  END kc_cr[101]
  PIN kc_cr[102]
    DIRECTION OUTPUT ;
    USE SIGNAL ;
    PORT
      LAYER M4 ;
        RECT  0 14.64 0.084 14.664 ;
    END
  END kc_cr[102]
  PIN kc_cr[103]
    DIRECTION OUTPUT ;
    USE SIGNAL ;
    PORT
      LAYER M4 ;
        RECT  0 14.736 0.084 14.76 ;
    END
  END kc_cr[103]
  PIN kc_cr[104]
    DIRECTION OUTPUT ;
    USE SIGNAL ;
    PORT
      LAYER M4 ;
        RECT  0 14.832 0.084 14.856 ;
    END
  END kc_cr[104]
  PIN kc_cr[105]
    DIRECTION OUTPUT ;
    USE SIGNAL ;
    PORT
      LAYER M4 ;
        RECT  0 14.928 0.084 14.952 ;
    END
  END kc_cr[105]
  PIN kc_cr[106]
    DIRECTION OUTPUT ;
    USE SIGNAL ;
    PORT
      LAYER M4 ;
        RECT  0 15.024 0.084 15.048 ;
    END
  END kc_cr[106]
  PIN kc_cr[107]
    DIRECTION OUTPUT ;
    USE SIGNAL ;
    PORT
      LAYER M4 ;
        RECT  0 15.12 0.084 15.144 ;
    END
  END kc_cr[107]
  PIN kc_cr[108]
    DIRECTION OUTPUT ;
    USE SIGNAL ;
    PORT
      LAYER M4 ;
        RECT  0 15.216 0.084 15.24 ;
    END
  END kc_cr[108]
  PIN kc_cr[109]
    DIRECTION OUTPUT ;
    USE SIGNAL ;
    PORT
      LAYER M4 ;
        RECT  0 15.312 0.084 15.336 ;
    END
  END kc_cr[109]
  PIN kc_cr[10]
    DIRECTION OUTPUT ;
    USE SIGNAL ;
    PORT
      LAYER M4 ;
        RECT  0 5.808 0.084 5.832 ;
    END
  END kc_cr[10]
  PIN kc_cr[110]
    DIRECTION OUTPUT ;
    USE SIGNAL ;
    PORT
      LAYER M4 ;
        RECT  0 15.408 0.084 15.432 ;
    END
  END kc_cr[110]
  PIN kc_cr[111]
    DIRECTION OUTPUT ;
    USE SIGNAL ;
    PORT
      LAYER M4 ;
        RECT  0 15.504 0.084 15.528 ;
    END
  END kc_cr[111]
  PIN kc_cr[112]
    DIRECTION OUTPUT ;
    USE SIGNAL ;
    PORT
      LAYER M4 ;
        RECT  0 15.6 0.084 15.624 ;
    END
  END kc_cr[112]
  PIN kc_cr[113]
    DIRECTION OUTPUT ;
    USE SIGNAL ;
    PORT
      LAYER M4 ;
        RECT  0 15.696 0.084 15.72 ;
    END
  END kc_cr[113]
  PIN kc_cr[114]
    DIRECTION OUTPUT ;
    USE SIGNAL ;
    PORT
      LAYER M4 ;
        RECT  0 15.792 0.084 15.816 ;
    END
  END kc_cr[114]
  PIN kc_cr[115]
    DIRECTION OUTPUT ;
    USE SIGNAL ;
    PORT
      LAYER M4 ;
        RECT  0 15.888 0.084 15.912 ;
    END
  END kc_cr[115]
  PIN kc_cr[116]
    DIRECTION OUTPUT ;
    USE SIGNAL ;
    PORT
      LAYER M4 ;
        RECT  0 15.984 0.084 16.008 ;
    END
  END kc_cr[116]
  PIN kc_cr[117]
    DIRECTION OUTPUT ;
    USE SIGNAL ;
    PORT
      LAYER M4 ;
        RECT  0 16.08 0.084 16.104 ;
    END
  END kc_cr[117]
  PIN kc_cr[118]
    DIRECTION OUTPUT ;
    USE SIGNAL ;
    PORT
      LAYER M4 ;
        RECT  0 16.176 0.084 16.2 ;
    END
  END kc_cr[118]
  PIN kc_cr[119]
    DIRECTION OUTPUT ;
    USE SIGNAL ;
    PORT
      LAYER M4 ;
        RECT  0 16.272 0.084 16.296 ;
    END
  END kc_cr[119]
  PIN kc_cr[11]
    DIRECTION OUTPUT ;
    USE SIGNAL ;
    PORT
      LAYER M4 ;
        RECT  0 5.904 0.084 5.928 ;
    END
  END kc_cr[11]
  PIN kc_cr[120]
    DIRECTION OUTPUT ;
    USE SIGNAL ;
    PORT
      LAYER M4 ;
        RECT  0 16.368 0.084 16.392 ;
    END
  END kc_cr[120]
  PIN kc_cr[121]
    DIRECTION OUTPUT ;
    USE SIGNAL ;
    PORT
      LAYER M4 ;
        RECT  0 16.464 0.084 16.488 ;
    END
  END kc_cr[121]
  PIN kc_cr[122]
    DIRECTION OUTPUT ;
    USE SIGNAL ;
    PORT
      LAYER M4 ;
        RECT  0 16.56 0.084 16.584 ;
    END
  END kc_cr[122]
  PIN kc_cr[123]
    DIRECTION OUTPUT ;
    USE SIGNAL ;
    PORT
      LAYER M4 ;
        RECT  0 16.656 0.084 16.68 ;
    END
  END kc_cr[123]
  PIN kc_cr[124]
    DIRECTION OUTPUT ;
    USE SIGNAL ;
    PORT
      LAYER M4 ;
        RECT  0 16.752 0.084 16.776 ;
    END
  END kc_cr[124]
  PIN kc_cr[125]
    DIRECTION OUTPUT ;
    USE SIGNAL ;
    PORT
      LAYER M4 ;
        RECT  0 16.848 0.084 16.872 ;
    END
  END kc_cr[125]
  PIN kc_cr[126]
    DIRECTION OUTPUT ;
    USE SIGNAL ;
    PORT
      LAYER M4 ;
        RECT  0 16.944 0.084 16.968 ;
    END
  END kc_cr[126]
  PIN kc_cr[127]
    DIRECTION OUTPUT ;
    USE SIGNAL ;
    PORT
      LAYER M4 ;
        RECT  0 17.04 0.084 17.064 ;
    END
  END kc_cr[127]
  PIN kc_cr[128]
    DIRECTION OUTPUT ;
    USE SIGNAL ;
    PORT
      LAYER M4 ;
        RECT  0 20.208 0.084 20.232 ;
    END
  END kc_cr[128]
  PIN kc_cr[129]
    DIRECTION OUTPUT ;
    USE SIGNAL ;
    PORT
      LAYER M4 ;
        RECT  0 20.304 0.084 20.328 ;
    END
  END kc_cr[129]
  PIN kc_cr[12]
    DIRECTION OUTPUT ;
    USE SIGNAL ;
    PORT
      LAYER M4 ;
        RECT  0 6 0.084 6.024 ;
    END
  END kc_cr[12]
  PIN kc_cr[130]
    DIRECTION OUTPUT ;
    USE SIGNAL ;
    PORT
      LAYER M4 ;
        RECT  0 20.4 0.084 20.424 ;
    END
  END kc_cr[130]
  PIN kc_cr[131]
    DIRECTION OUTPUT ;
    USE SIGNAL ;
    PORT
      LAYER M4 ;
        RECT  0 20.496 0.084 20.52 ;
    END
  END kc_cr[131]
  PIN kc_cr[132]
    DIRECTION OUTPUT ;
    USE SIGNAL ;
    PORT
      LAYER M4 ;
        RECT  0 20.592 0.084 20.616 ;
    END
  END kc_cr[132]
  PIN kc_cr[133]
    DIRECTION OUTPUT ;
    USE SIGNAL ;
    PORT
      LAYER M4 ;
        RECT  0 20.688 0.084 20.712 ;
    END
  END kc_cr[133]
  PIN kc_cr[134]
    DIRECTION OUTPUT ;
    USE SIGNAL ;
    PORT
      LAYER M4 ;
        RECT  0 20.784 0.084 20.808 ;
    END
  END kc_cr[134]
  PIN kc_cr[135]
    DIRECTION OUTPUT ;
    USE SIGNAL ;
    PORT
      LAYER M4 ;
        RECT  0 20.88 0.084 20.904 ;
    END
  END kc_cr[135]
  PIN kc_cr[136]
    DIRECTION OUTPUT ;
    USE SIGNAL ;
    PORT
      LAYER M4 ;
        RECT  0 20.976 0.084 21 ;
    END
  END kc_cr[136]
  PIN kc_cr[137]
    DIRECTION OUTPUT ;
    USE SIGNAL ;
    PORT
      LAYER M4 ;
        RECT  0 21.072 0.084 21.096 ;
    END
  END kc_cr[137]
  PIN kc_cr[138]
    DIRECTION OUTPUT ;
    USE SIGNAL ;
    PORT
      LAYER M4 ;
        RECT  0 21.168 0.084 21.192 ;
    END
  END kc_cr[138]
  PIN kc_cr[139]
    DIRECTION OUTPUT ;
    USE SIGNAL ;
    PORT
      LAYER M4 ;
        RECT  0 21.264 0.084 21.288 ;
    END
  END kc_cr[139]
  PIN kc_cr[13]
    DIRECTION OUTPUT ;
    USE SIGNAL ;
    PORT
      LAYER M4 ;
        RECT  0 6.096 0.084 6.12 ;
    END
  END kc_cr[13]
  PIN kc_cr[140]
    DIRECTION OUTPUT ;
    USE SIGNAL ;
    PORT
      LAYER M4 ;
        RECT  0 21.36 0.084 21.384 ;
    END
  END kc_cr[140]
  PIN kc_cr[141]
    DIRECTION OUTPUT ;
    USE SIGNAL ;
    PORT
      LAYER M4 ;
        RECT  0 21.456 0.084 21.48 ;
    END
  END kc_cr[141]
  PIN kc_cr[142]
    DIRECTION OUTPUT ;
    USE SIGNAL ;
    PORT
      LAYER M4 ;
        RECT  0 21.552 0.084 21.576 ;
    END
  END kc_cr[142]
  PIN kc_cr[143]
    DIRECTION OUTPUT ;
    USE SIGNAL ;
    PORT
      LAYER M4 ;
        RECT  0 21.648 0.084 21.672 ;
    END
  END kc_cr[143]
  PIN kc_cr[144]
    DIRECTION OUTPUT ;
    USE SIGNAL ;
    PORT
      LAYER M4 ;
        RECT  0 21.744 0.084 21.768 ;
    END
  END kc_cr[144]
  PIN kc_cr[145]
    DIRECTION OUTPUT ;
    USE SIGNAL ;
    PORT
      LAYER M4 ;
        RECT  0 21.84 0.084 21.864 ;
    END
  END kc_cr[145]
  PIN kc_cr[146]
    DIRECTION OUTPUT ;
    USE SIGNAL ;
    PORT
      LAYER M4 ;
        RECT  0 21.936 0.084 21.96 ;
    END
  END kc_cr[146]
  PIN kc_cr[147]
    DIRECTION OUTPUT ;
    USE SIGNAL ;
    PORT
      LAYER M4 ;
        RECT  0 22.032 0.084 22.056 ;
    END
  END kc_cr[147]
  PIN kc_cr[148]
    DIRECTION OUTPUT ;
    USE SIGNAL ;
    PORT
      LAYER M4 ;
        RECT  0 22.128 0.084 22.152 ;
    END
  END kc_cr[148]
  PIN kc_cr[149]
    DIRECTION OUTPUT ;
    USE SIGNAL ;
    PORT
      LAYER M4 ;
        RECT  0 22.224 0.084 22.248 ;
    END
  END kc_cr[149]
  PIN kc_cr[14]
    DIRECTION OUTPUT ;
    USE SIGNAL ;
    PORT
      LAYER M4 ;
        RECT  0 6.192 0.084 6.216 ;
    END
  END kc_cr[14]
  PIN kc_cr[150]
    DIRECTION OUTPUT ;
    USE SIGNAL ;
    PORT
      LAYER M4 ;
        RECT  0 22.32 0.084 22.344 ;
    END
  END kc_cr[150]
  PIN kc_cr[151]
    DIRECTION OUTPUT ;
    USE SIGNAL ;
    PORT
      LAYER M4 ;
        RECT  0 22.416 0.084 22.44 ;
    END
  END kc_cr[151]
  PIN kc_cr[152]
    DIRECTION OUTPUT ;
    USE SIGNAL ;
    PORT
      LAYER M4 ;
        RECT  0 22.512 0.084 22.536 ;
    END
  END kc_cr[152]
  PIN kc_cr[153]
    DIRECTION OUTPUT ;
    USE SIGNAL ;
    PORT
      LAYER M4 ;
        RECT  0 22.608 0.084 22.632 ;
    END
  END kc_cr[153]
  PIN kc_cr[154]
    DIRECTION OUTPUT ;
    USE SIGNAL ;
    PORT
      LAYER M4 ;
        RECT  0 22.704 0.084 22.728 ;
    END
  END kc_cr[154]
  PIN kc_cr[155]
    DIRECTION OUTPUT ;
    USE SIGNAL ;
    PORT
      LAYER M4 ;
        RECT  0 22.8 0.084 22.824 ;
    END
  END kc_cr[155]
  PIN kc_cr[156]
    DIRECTION OUTPUT ;
    USE SIGNAL ;
    PORT
      LAYER M4 ;
        RECT  0 22.896 0.084 22.92 ;
    END
  END kc_cr[156]
  PIN kc_cr[157]
    DIRECTION OUTPUT ;
    USE SIGNAL ;
    PORT
      LAYER M4 ;
        RECT  0 22.992 0.084 23.016 ;
    END
  END kc_cr[157]
  PIN kc_cr[158]
    DIRECTION OUTPUT ;
    USE SIGNAL ;
    PORT
      LAYER M4 ;
        RECT  0 23.088 0.084 23.112 ;
    END
  END kc_cr[158]
  PIN kc_cr[159]
    DIRECTION OUTPUT ;
    USE SIGNAL ;
    PORT
      LAYER M4 ;
        RECT  0 23.184 0.084 23.208 ;
    END
  END kc_cr[159]
  PIN kc_cr[15]
    DIRECTION OUTPUT ;
    USE SIGNAL ;
    PORT
      LAYER M4 ;
        RECT  0 6.288 0.084 6.312 ;
    END
  END kc_cr[15]
  PIN kc_cr[160]
    DIRECTION OUTPUT ;
    USE SIGNAL ;
    PORT
      LAYER M4 ;
        RECT  0 10.992 0.084 11.016 ;
    END
  END kc_cr[160]
  PIN kc_cr[161]
    DIRECTION OUTPUT ;
    USE SIGNAL ;
    PORT
      LAYER M4 ;
        RECT  0 11.088 0.084 11.112 ;
    END
  END kc_cr[161]
  PIN kc_cr[162]
    DIRECTION OUTPUT ;
    USE SIGNAL ;
    PORT
      LAYER M4 ;
        RECT  0 11.184 0.084 11.208 ;
    END
  END kc_cr[162]
  PIN kc_cr[163]
    DIRECTION OUTPUT ;
    USE SIGNAL ;
    PORT
      LAYER M4 ;
        RECT  0 11.28 0.084 11.304 ;
    END
  END kc_cr[163]
  PIN kc_cr[164]
    DIRECTION OUTPUT ;
    USE SIGNAL ;
    PORT
      LAYER M4 ;
        RECT  0 11.376 0.084 11.4 ;
    END
  END kc_cr[164]
  PIN kc_cr[165]
    DIRECTION OUTPUT ;
    USE SIGNAL ;
    PORT
      LAYER M4 ;
        RECT  0 11.472 0.084 11.496 ;
    END
  END kc_cr[165]
  PIN kc_cr[166]
    DIRECTION OUTPUT ;
    USE SIGNAL ;
    PORT
      LAYER M4 ;
        RECT  0 11.568 0.084 11.592 ;
    END
  END kc_cr[166]
  PIN kc_cr[167]
    DIRECTION OUTPUT ;
    USE SIGNAL ;
    PORT
      LAYER M4 ;
        RECT  0 11.664 0.084 11.688 ;
    END
  END kc_cr[167]
  PIN kc_cr[168]
    DIRECTION OUTPUT ;
    USE SIGNAL ;
    PORT
      LAYER M4 ;
        RECT  0 11.76 0.084 11.784 ;
    END
  END kc_cr[168]
  PIN kc_cr[169]
    DIRECTION OUTPUT ;
    USE SIGNAL ;
    PORT
      LAYER M4 ;
        RECT  0 11.856 0.084 11.88 ;
    END
  END kc_cr[169]
  PIN kc_cr[16]
    DIRECTION OUTPUT ;
    USE SIGNAL ;
    PORT
      LAYER M4 ;
        RECT  0 6.384 0.084 6.408 ;
    END
  END kc_cr[16]
  PIN kc_cr[170]
    DIRECTION OUTPUT ;
    USE SIGNAL ;
    PORT
      LAYER M4 ;
        RECT  0 11.952 0.084 11.976 ;
    END
  END kc_cr[170]
  PIN kc_cr[171]
    DIRECTION OUTPUT ;
    USE SIGNAL ;
    PORT
      LAYER M4 ;
        RECT  0 12.048 0.084 12.072 ;
    END
  END kc_cr[171]
  PIN kc_cr[172]
    DIRECTION OUTPUT ;
    USE SIGNAL ;
    PORT
      LAYER M4 ;
        RECT  0 12.144 0.084 12.168 ;
    END
  END kc_cr[172]
  PIN kc_cr[173]
    DIRECTION OUTPUT ;
    USE SIGNAL ;
    PORT
      LAYER M4 ;
        RECT  0 12.24 0.084 12.264 ;
    END
  END kc_cr[173]
  PIN kc_cr[174]
    DIRECTION OUTPUT ;
    USE SIGNAL ;
    PORT
      LAYER M4 ;
        RECT  0 12.336 0.084 12.36 ;
    END
  END kc_cr[174]
  PIN kc_cr[175]
    DIRECTION OUTPUT ;
    USE SIGNAL ;
    PORT
      LAYER M4 ;
        RECT  0 12.432 0.084 12.456 ;
    END
  END kc_cr[175]
  PIN kc_cr[176]
    DIRECTION OUTPUT ;
    USE SIGNAL ;
    PORT
      LAYER M4 ;
        RECT  0 12.528 0.084 12.552 ;
    END
  END kc_cr[176]
  PIN kc_cr[177]
    DIRECTION OUTPUT ;
    USE SIGNAL ;
    PORT
      LAYER M4 ;
        RECT  0 12.624 0.084 12.648 ;
    END
  END kc_cr[177]
  PIN kc_cr[178]
    DIRECTION OUTPUT ;
    USE SIGNAL ;
    PORT
      LAYER M4 ;
        RECT  0 12.72 0.084 12.744 ;
    END
  END kc_cr[178]
  PIN kc_cr[179]
    DIRECTION OUTPUT ;
    USE SIGNAL ;
    PORT
      LAYER M4 ;
        RECT  0 12.816 0.084 12.84 ;
    END
  END kc_cr[179]
  PIN kc_cr[17]
    DIRECTION OUTPUT ;
    USE SIGNAL ;
    PORT
      LAYER M4 ;
        RECT  0 6.48 0.084 6.504 ;
    END
  END kc_cr[17]
  PIN kc_cr[180]
    DIRECTION OUTPUT ;
    USE SIGNAL ;
    PORT
      LAYER M4 ;
        RECT  0 12.912 0.084 12.936 ;
    END
  END kc_cr[180]
  PIN kc_cr[181]
    DIRECTION OUTPUT ;
    USE SIGNAL ;
    PORT
      LAYER M4 ;
        RECT  0 13.008 0.084 13.032 ;
    END
  END kc_cr[181]
  PIN kc_cr[182]
    DIRECTION OUTPUT ;
    USE SIGNAL ;
    PORT
      LAYER M4 ;
        RECT  0 13.104 0.084 13.128 ;
    END
  END kc_cr[182]
  PIN kc_cr[183]
    DIRECTION OUTPUT ;
    USE SIGNAL ;
    PORT
      LAYER M4 ;
        RECT  0 13.2 0.084 13.224 ;
    END
  END kc_cr[183]
  PIN kc_cr[184]
    DIRECTION OUTPUT ;
    USE SIGNAL ;
    PORT
      LAYER M4 ;
        RECT  0 13.296 0.084 13.32 ;
    END
  END kc_cr[184]
  PIN kc_cr[185]
    DIRECTION OUTPUT ;
    USE SIGNAL ;
    PORT
      LAYER M4 ;
        RECT  0 13.392 0.084 13.416 ;
    END
  END kc_cr[185]
  PIN kc_cr[186]
    DIRECTION OUTPUT ;
    USE SIGNAL ;
    PORT
      LAYER M4 ;
        RECT  0 13.488 0.084 13.512 ;
    END
  END kc_cr[186]
  PIN kc_cr[187]
    DIRECTION OUTPUT ;
    USE SIGNAL ;
    PORT
      LAYER M4 ;
        RECT  0 13.584 0.084 13.608 ;
    END
  END kc_cr[187]
  PIN kc_cr[188]
    DIRECTION OUTPUT ;
    USE SIGNAL ;
    PORT
      LAYER M4 ;
        RECT  0 13.68 0.084 13.704 ;
    END
  END kc_cr[188]
  PIN kc_cr[189]
    DIRECTION OUTPUT ;
    USE SIGNAL ;
    PORT
      LAYER M4 ;
        RECT  0 13.776 0.084 13.8 ;
    END
  END kc_cr[189]
  PIN kc_cr[18]
    DIRECTION OUTPUT ;
    USE SIGNAL ;
    PORT
      LAYER M4 ;
        RECT  0 6.576 0.084 6.6 ;
    END
  END kc_cr[18]
  PIN kc_cr[190]
    DIRECTION OUTPUT ;
    USE SIGNAL ;
    PORT
      LAYER M4 ;
        RECT  0 13.872 0.084 13.896 ;
    END
  END kc_cr[190]
  PIN kc_cr[191]
    DIRECTION OUTPUT ;
    USE SIGNAL ;
    PORT
      LAYER M4 ;
        RECT  0 13.968 0.084 13.992 ;
    END
  END kc_cr[191]
  PIN kc_cr[19]
    DIRECTION OUTPUT ;
    USE SIGNAL ;
    PORT
      LAYER M4 ;
        RECT  0 6.672 0.084 6.696 ;
    END
  END kc_cr[19]
  PIN kc_cr[1]
    DIRECTION OUTPUT ;
    USE SIGNAL ;
    PORT
      LAYER M4 ;
        RECT  0 4.944 0.084 4.968 ;
    END
  END kc_cr[1]
  PIN kc_cr[20]
    DIRECTION OUTPUT ;
    USE SIGNAL ;
    PORT
      LAYER M4 ;
        RECT  0 6.768 0.084 6.792 ;
    END
  END kc_cr[20]
  PIN kc_cr[21]
    DIRECTION OUTPUT ;
    USE SIGNAL ;
    PORT
      LAYER M4 ;
        RECT  0 6.864 0.084 6.888 ;
    END
  END kc_cr[21]
  PIN kc_cr[22]
    DIRECTION OUTPUT ;
    USE SIGNAL ;
    PORT
      LAYER M4 ;
        RECT  0 6.96 0.084 6.984 ;
    END
  END kc_cr[22]
  PIN kc_cr[23]
    DIRECTION OUTPUT ;
    USE SIGNAL ;
    PORT
      LAYER M4 ;
        RECT  0 7.056 0.084 7.08 ;
    END
  END kc_cr[23]
  PIN kc_cr[24]
    DIRECTION OUTPUT ;
    USE SIGNAL ;
    PORT
      LAYER M4 ;
        RECT  0 7.152 0.084 7.176 ;
    END
  END kc_cr[24]
  PIN kc_cr[25]
    DIRECTION OUTPUT ;
    USE SIGNAL ;
    PORT
      LAYER M4 ;
        RECT  0 7.248 0.084 7.272 ;
    END
  END kc_cr[25]
  PIN kc_cr[26]
    DIRECTION OUTPUT ;
    USE SIGNAL ;
    PORT
      LAYER M4 ;
        RECT  0 7.344 0.084 7.368 ;
    END
  END kc_cr[26]
  PIN kc_cr[27]
    DIRECTION OUTPUT ;
    USE SIGNAL ;
    PORT
      LAYER M4 ;
        RECT  0 7.44 0.084 7.464 ;
    END
  END kc_cr[27]
  PIN kc_cr[28]
    DIRECTION OUTPUT ;
    USE SIGNAL ;
    PORT
      LAYER M4 ;
        RECT  0 7.536 0.084 7.56 ;
    END
  END kc_cr[28]
  PIN kc_cr[29]
    DIRECTION OUTPUT ;
    USE SIGNAL ;
    PORT
      LAYER M4 ;
        RECT  0 7.632 0.084 7.656 ;
    END
  END kc_cr[29]
  PIN kc_cr[2]
    DIRECTION OUTPUT ;
    USE SIGNAL ;
    PORT
      LAYER M4 ;
        RECT  0 5.04 0.084 5.064 ;
    END
  END kc_cr[2]
  PIN kc_cr[30]
    DIRECTION OUTPUT ;
    USE SIGNAL ;
    PORT
      LAYER M4 ;
        RECT  0 7.728 0.084 7.752 ;
    END
  END kc_cr[30]
  PIN kc_cr[31]
    DIRECTION OUTPUT ;
    USE SIGNAL ;
    PORT
      LAYER M4 ;
        RECT  0 7.824 0.084 7.848 ;
    END
  END kc_cr[31]
  PIN kc_cr[32]
    DIRECTION OUTPUT ;
    USE SIGNAL ;
    PORT
      LAYER M4 ;
        RECT  0 7.92 0.084 7.944 ;
    END
  END kc_cr[32]
  PIN kc_cr[33]
    DIRECTION OUTPUT ;
    USE SIGNAL ;
    PORT
      LAYER M4 ;
        RECT  0 8.016 0.084 8.04 ;
    END
  END kc_cr[33]
  PIN kc_cr[34]
    DIRECTION OUTPUT ;
    USE SIGNAL ;
    PORT
      LAYER M4 ;
        RECT  0 8.112 0.084 8.136 ;
    END
  END kc_cr[34]
  PIN kc_cr[35]
    DIRECTION OUTPUT ;
    USE SIGNAL ;
    PORT
      LAYER M4 ;
        RECT  0 8.208 0.084 8.232 ;
    END
  END kc_cr[35]
  PIN kc_cr[36]
    DIRECTION OUTPUT ;
    USE SIGNAL ;
    PORT
      LAYER M4 ;
        RECT  0 8.304 0.084 8.328 ;
    END
  END kc_cr[36]
  PIN kc_cr[37]
    DIRECTION OUTPUT ;
    USE SIGNAL ;
    PORT
      LAYER M4 ;
        RECT  0 8.4 0.084 8.424 ;
    END
  END kc_cr[37]
  PIN kc_cr[38]
    DIRECTION OUTPUT ;
    USE SIGNAL ;
    PORT
      LAYER M4 ;
        RECT  0 8.496 0.084 8.52 ;
    END
  END kc_cr[38]
  PIN kc_cr[39]
    DIRECTION OUTPUT ;
    USE SIGNAL ;
    PORT
      LAYER M4 ;
        RECT  0 8.592 0.084 8.616 ;
    END
  END kc_cr[39]
  PIN kc_cr[3]
    DIRECTION OUTPUT ;
    USE SIGNAL ;
    PORT
      LAYER M4 ;
        RECT  0 5.136 0.084 5.16 ;
    END
  END kc_cr[3]
  PIN kc_cr[40]
    DIRECTION OUTPUT ;
    USE SIGNAL ;
    PORT
      LAYER M4 ;
        RECT  0 8.688 0.084 8.712 ;
    END
  END kc_cr[40]
  PIN kc_cr[41]
    DIRECTION OUTPUT ;
    USE SIGNAL ;
    PORT
      LAYER M4 ;
        RECT  0 8.784 0.084 8.808 ;
    END
  END kc_cr[41]
  PIN kc_cr[42]
    DIRECTION OUTPUT ;
    USE SIGNAL ;
    PORT
      LAYER M4 ;
        RECT  0 8.88 0.084 8.904 ;
    END
  END kc_cr[42]
  PIN kc_cr[43]
    DIRECTION OUTPUT ;
    USE SIGNAL ;
    PORT
      LAYER M4 ;
        RECT  0 8.976 0.084 9 ;
    END
  END kc_cr[43]
  PIN kc_cr[44]
    DIRECTION OUTPUT ;
    USE SIGNAL ;
    PORT
      LAYER M4 ;
        RECT  0 9.072 0.084 9.096 ;
    END
  END kc_cr[44]
  PIN kc_cr[45]
    DIRECTION OUTPUT ;
    USE SIGNAL ;
    PORT
      LAYER M4 ;
        RECT  0 9.168 0.084 9.192 ;
    END
  END kc_cr[45]
  PIN kc_cr[46]
    DIRECTION OUTPUT ;
    USE SIGNAL ;
    PORT
      LAYER M4 ;
        RECT  0 9.264 0.084 9.288 ;
    END
  END kc_cr[46]
  PIN kc_cr[47]
    DIRECTION OUTPUT ;
    USE SIGNAL ;
    PORT
      LAYER M4 ;
        RECT  0 9.36 0.084 9.384 ;
    END
  END kc_cr[47]
  PIN kc_cr[48]
    DIRECTION OUTPUT ;
    USE SIGNAL ;
    PORT
      LAYER M4 ;
        RECT  0 9.456 0.084 9.48 ;
    END
  END kc_cr[48]
  PIN kc_cr[49]
    DIRECTION OUTPUT ;
    USE SIGNAL ;
    PORT
      LAYER M4 ;
        RECT  0 9.552 0.084 9.576 ;
    END
  END kc_cr[49]
  PIN kc_cr[4]
    DIRECTION OUTPUT ;
    USE SIGNAL ;
    PORT
      LAYER M4 ;
        RECT  0 5.232 0.084 5.256 ;
    END
  END kc_cr[4]
  PIN kc_cr[50]
    DIRECTION OUTPUT ;
    USE SIGNAL ;
    PORT
      LAYER M4 ;
        RECT  0 9.648 0.084 9.672 ;
    END
  END kc_cr[50]
  PIN kc_cr[51]
    DIRECTION OUTPUT ;
    USE SIGNAL ;
    PORT
      LAYER M4 ;
        RECT  0 9.744 0.084 9.768 ;
    END
  END kc_cr[51]
  PIN kc_cr[52]
    DIRECTION OUTPUT ;
    USE SIGNAL ;
    PORT
      LAYER M4 ;
        RECT  0 9.84 0.084 9.864 ;
    END
  END kc_cr[52]
  PIN kc_cr[53]
    DIRECTION OUTPUT ;
    USE SIGNAL ;
    PORT
      LAYER M4 ;
        RECT  0 9.936 0.084 9.96 ;
    END
  END kc_cr[53]
  PIN kc_cr[54]
    DIRECTION OUTPUT ;
    USE SIGNAL ;
    PORT
      LAYER M4 ;
        RECT  0 10.032 0.084 10.056 ;
    END
  END kc_cr[54]
  PIN kc_cr[55]
    DIRECTION OUTPUT ;
    USE SIGNAL ;
    PORT
      LAYER M4 ;
        RECT  0 10.128 0.084 10.152 ;
    END
  END kc_cr[55]
  PIN kc_cr[56]
    DIRECTION OUTPUT ;
    USE SIGNAL ;
    PORT
      LAYER M4 ;
        RECT  0 10.224 0.084 10.248 ;
    END
  END kc_cr[56]
  PIN kc_cr[57]
    DIRECTION OUTPUT ;
    USE SIGNAL ;
    PORT
      LAYER M4 ;
        RECT  0 10.32 0.084 10.344 ;
    END
  END kc_cr[57]
  PIN kc_cr[58]
    DIRECTION OUTPUT ;
    USE SIGNAL ;
    PORT
      LAYER M4 ;
        RECT  0 10.416 0.084 10.44 ;
    END
  END kc_cr[58]
  PIN kc_cr[59]
    DIRECTION OUTPUT ;
    USE SIGNAL ;
    PORT
      LAYER M4 ;
        RECT  0 10.512 0.084 10.536 ;
    END
  END kc_cr[59]
  PIN kc_cr[5]
    DIRECTION OUTPUT ;
    USE SIGNAL ;
    PORT
      LAYER M4 ;
        RECT  0 5.328 0.084 5.352 ;
    END
  END kc_cr[5]
  PIN kc_cr[60]
    DIRECTION OUTPUT ;
    USE SIGNAL ;
    PORT
      LAYER M4 ;
        RECT  0 10.608 0.084 10.632 ;
    END
  END kc_cr[60]
  PIN kc_cr[61]
    DIRECTION OUTPUT ;
    USE SIGNAL ;
    PORT
      LAYER M4 ;
        RECT  0 10.704 0.084 10.728 ;
    END
  END kc_cr[61]
  PIN kc_cr[62]
    DIRECTION OUTPUT ;
    USE SIGNAL ;
    PORT
      LAYER M4 ;
        RECT  0 10.8 0.084 10.824 ;
    END
  END kc_cr[62]
  PIN kc_cr[63]
    DIRECTION OUTPUT ;
    USE SIGNAL ;
    PORT
      LAYER M4 ;
        RECT  0 10.896 0.084 10.92 ;
    END
  END kc_cr[63]
  PIN kc_cr[64]
    DIRECTION OUTPUT ;
    USE SIGNAL ;
    PORT
      LAYER M4 ;
        RECT  0 17.136 0.084 17.16 ;
    END
  END kc_cr[64]
  PIN kc_cr[65]
    DIRECTION OUTPUT ;
    USE SIGNAL ;
    PORT
      LAYER M4 ;
        RECT  0 17.232 0.084 17.256 ;
    END
  END kc_cr[65]
  PIN kc_cr[66]
    DIRECTION OUTPUT ;
    USE SIGNAL ;
    PORT
      LAYER M4 ;
        RECT  0 17.328 0.084 17.352 ;
    END
  END kc_cr[66]
  PIN kc_cr[67]
    DIRECTION OUTPUT ;
    USE SIGNAL ;
    PORT
      LAYER M4 ;
        RECT  0 17.424 0.084 17.448 ;
    END
  END kc_cr[67]
  PIN kc_cr[68]
    DIRECTION OUTPUT ;
    USE SIGNAL ;
    PORT
      LAYER M4 ;
        RECT  0 17.52 0.084 17.544 ;
    END
  END kc_cr[68]
  PIN kc_cr[69]
    DIRECTION OUTPUT ;
    USE SIGNAL ;
    PORT
      LAYER M4 ;
        RECT  0 17.616 0.084 17.64 ;
    END
  END kc_cr[69]
  PIN kc_cr[6]
    DIRECTION OUTPUT ;
    USE SIGNAL ;
    PORT
      LAYER M4 ;
        RECT  0 5.424 0.084 5.448 ;
    END
  END kc_cr[6]
  PIN kc_cr[70]
    DIRECTION OUTPUT ;
    USE SIGNAL ;
    PORT
      LAYER M4 ;
        RECT  0 17.712 0.084 17.736 ;
    END
  END kc_cr[70]
  PIN kc_cr[71]
    DIRECTION OUTPUT ;
    USE SIGNAL ;
    PORT
      LAYER M4 ;
        RECT  0 17.808 0.084 17.832 ;
    END
  END kc_cr[71]
  PIN kc_cr[72]
    DIRECTION OUTPUT ;
    USE SIGNAL ;
    PORT
      LAYER M4 ;
        RECT  0 17.904 0.084 17.928 ;
    END
  END kc_cr[72]
  PIN kc_cr[73]
    DIRECTION OUTPUT ;
    USE SIGNAL ;
    PORT
      LAYER M4 ;
        RECT  0 18 0.084 18.024 ;
    END
  END kc_cr[73]
  PIN kc_cr[74]
    DIRECTION OUTPUT ;
    USE SIGNAL ;
    PORT
      LAYER M4 ;
        RECT  0 18.096 0.084 18.12 ;
    END
  END kc_cr[74]
  PIN kc_cr[75]
    DIRECTION OUTPUT ;
    USE SIGNAL ;
    PORT
      LAYER M4 ;
        RECT  0 18.192 0.084 18.216 ;
    END
  END kc_cr[75]
  PIN kc_cr[76]
    DIRECTION OUTPUT ;
    USE SIGNAL ;
    PORT
      LAYER M4 ;
        RECT  0 18.288 0.084 18.312 ;
    END
  END kc_cr[76]
  PIN kc_cr[77]
    DIRECTION OUTPUT ;
    USE SIGNAL ;
    PORT
      LAYER M4 ;
        RECT  0 18.384 0.084 18.408 ;
    END
  END kc_cr[77]
  PIN kc_cr[78]
    DIRECTION OUTPUT ;
    USE SIGNAL ;
    PORT
      LAYER M4 ;
        RECT  0 18.48 0.084 18.504 ;
    END
  END kc_cr[78]
  PIN kc_cr[79]
    DIRECTION OUTPUT ;
    USE SIGNAL ;
    PORT
      LAYER M4 ;
        RECT  0 18.576 0.084 18.6 ;
    END
  END kc_cr[79]
  PIN kc_cr[7]
    DIRECTION OUTPUT ;
    USE SIGNAL ;
    PORT
      LAYER M4 ;
        RECT  0 5.52 0.084 5.544 ;
    END
  END kc_cr[7]
  PIN kc_cr[80]
    DIRECTION OUTPUT ;
    USE SIGNAL ;
    PORT
      LAYER M4 ;
        RECT  0 18.672 0.084 18.696 ;
    END
  END kc_cr[80]
  PIN kc_cr[81]
    DIRECTION OUTPUT ;
    USE SIGNAL ;
    PORT
      LAYER M4 ;
        RECT  0 18.768 0.084 18.792 ;
    END
  END kc_cr[81]
  PIN kc_cr[82]
    DIRECTION OUTPUT ;
    USE SIGNAL ;
    PORT
      LAYER M4 ;
        RECT  0 18.864 0.084 18.888 ;
    END
  END kc_cr[82]
  PIN kc_cr[83]
    DIRECTION OUTPUT ;
    USE SIGNAL ;
    PORT
      LAYER M4 ;
        RECT  0 18.96 0.084 18.984 ;
    END
  END kc_cr[83]
  PIN kc_cr[84]
    DIRECTION OUTPUT ;
    USE SIGNAL ;
    PORT
      LAYER M4 ;
        RECT  0 19.056 0.084 19.08 ;
    END
  END kc_cr[84]
  PIN kc_cr[85]
    DIRECTION OUTPUT ;
    USE SIGNAL ;
    PORT
      LAYER M4 ;
        RECT  0 19.152 0.084 19.176 ;
    END
  END kc_cr[85]
  PIN kc_cr[86]
    DIRECTION OUTPUT ;
    USE SIGNAL ;
    PORT
      LAYER M4 ;
        RECT  0 19.248 0.084 19.272 ;
    END
  END kc_cr[86]
  PIN kc_cr[87]
    DIRECTION OUTPUT ;
    USE SIGNAL ;
    PORT
      LAYER M4 ;
        RECT  0 19.344 0.084 19.368 ;
    END
  END kc_cr[87]
  PIN kc_cr[88]
    DIRECTION OUTPUT ;
    USE SIGNAL ;
    PORT
      LAYER M4 ;
        RECT  0 19.44 0.084 19.464 ;
    END
  END kc_cr[88]
  PIN kc_cr[89]
    DIRECTION OUTPUT ;
    USE SIGNAL ;
    PORT
      LAYER M4 ;
        RECT  0 19.536 0.084 19.56 ;
    END
  END kc_cr[89]
  PIN kc_cr[8]
    DIRECTION OUTPUT ;
    USE SIGNAL ;
    PORT
      LAYER M4 ;
        RECT  0 5.616 0.084 5.64 ;
    END
  END kc_cr[8]
  PIN kc_cr[90]
    DIRECTION OUTPUT ;
    USE SIGNAL ;
    PORT
      LAYER M4 ;
        RECT  0 19.632 0.084 19.656 ;
    END
  END kc_cr[90]
  PIN kc_cr[91]
    DIRECTION OUTPUT ;
    USE SIGNAL ;
    PORT
      LAYER M4 ;
        RECT  0 19.728 0.084 19.752 ;
    END
  END kc_cr[91]
  PIN kc_cr[92]
    DIRECTION OUTPUT ;
    USE SIGNAL ;
    PORT
      LAYER M4 ;
        RECT  0 19.824 0.084 19.848 ;
    END
  END kc_cr[92]
  PIN kc_cr[93]
    DIRECTION OUTPUT ;
    USE SIGNAL ;
    PORT
      LAYER M4 ;
        RECT  0 19.92 0.084 19.944 ;
    END
  END kc_cr[93]
  PIN kc_cr[94]
    DIRECTION OUTPUT ;
    USE SIGNAL ;
    PORT
      LAYER M4 ;
        RECT  0 20.016 0.084 20.04 ;
    END
  END kc_cr[94]
  PIN kc_cr[95]
    DIRECTION OUTPUT ;
    USE SIGNAL ;
    PORT
      LAYER M4 ;
        RECT  0 20.112 0.084 20.136 ;
    END
  END kc_cr[95]
  PIN kc_cr[96]
    DIRECTION OUTPUT ;
    USE SIGNAL ;
    PORT
      LAYER M4 ;
        RECT  0 14.064 0.084 14.088 ;
    END
  END kc_cr[96]
  PIN kc_cr[97]
    DIRECTION OUTPUT ;
    USE SIGNAL ;
    PORT
      LAYER M4 ;
        RECT  0 14.16 0.084 14.184 ;
    END
  END kc_cr[97]
  PIN kc_cr[98]
    DIRECTION OUTPUT ;
    USE SIGNAL ;
    PORT
      LAYER M4 ;
        RECT  0 14.256 0.084 14.28 ;
    END
  END kc_cr[98]
  PIN kc_cr[99]
    DIRECTION OUTPUT ;
    USE SIGNAL ;
    PORT
      LAYER M4 ;
        RECT  0 14.352 0.084 14.376 ;
    END
  END kc_cr[99]
  PIN kc_cr[9]
    DIRECTION OUTPUT ;
    USE SIGNAL ;
    PORT
      LAYER M4 ;
        RECT  0 5.712 0.084 5.736 ;
    END
  END kc_cr[9]
  PIN request[0]
    DIRECTION INPUT ;
    USE SIGNAL ;
    PORT
      LAYER M5 ;
        RECT  10.416 43.116 10.44 43.2 ;
    END
  END request[0]
  PIN request[100]
    DIRECTION INPUT ;
    USE SIGNAL ;
    PORT
      LAYER M5 ;
        RECT  39.216 43.116 39.24 43.2 ;
    END
  END request[100]
  PIN request[101]
    DIRECTION INPUT ;
    USE SIGNAL ;
    PORT
      LAYER M5 ;
        RECT  39.312 43.116 39.336 43.2 ;
    END
  END request[101]
  PIN request[102]
    DIRECTION INPUT ;
    USE SIGNAL ;
    PORT
      LAYER M5 ;
        RECT  39.408 43.116 39.432 43.2 ;
    END
  END request[102]
  PIN request[103]
    DIRECTION INPUT ;
    USE SIGNAL ;
    PORT
      LAYER M5 ;
        RECT  39.504 43.116 39.528 43.2 ;
    END
  END request[103]
  PIN request[104]
    DIRECTION INPUT ;
    USE SIGNAL ;
    PORT
      LAYER M5 ;
        RECT  39.6 43.116 39.624 43.2 ;
    END
  END request[104]
  PIN request[105]
    DIRECTION INPUT ;
    USE SIGNAL ;
    PORT
      LAYER M5 ;
        RECT  39.696 43.116 39.72 43.2 ;
    END
  END request[105]
  PIN request[106]
    DIRECTION INPUT ;
    USE SIGNAL ;
    PORT
      LAYER M5 ;
        RECT  39.792 43.116 39.816 43.2 ;
    END
  END request[106]
  PIN request[107]
    DIRECTION INPUT ;
    USE SIGNAL ;
    PORT
      LAYER M5 ;
        RECT  39.888 43.116 39.912 43.2 ;
    END
  END request[107]
  PIN request[108]
    DIRECTION INPUT ;
    USE SIGNAL ;
    PORT
      LAYER M5 ;
        RECT  39.984 43.116 40.008 43.2 ;
    END
  END request[108]
  PIN request[109]
    DIRECTION INPUT ;
    USE SIGNAL ;
    PORT
      LAYER M5 ;
        RECT  40.08 43.116 40.104 43.2 ;
    END
  END request[109]
  PIN request[10]
    DIRECTION INPUT ;
    USE SIGNAL ;
    PORT
      LAYER M5 ;
        RECT  11.376 43.116 11.4 43.2 ;
    END
  END request[10]
  PIN request[110]
    DIRECTION INPUT ;
    USE SIGNAL ;
    PORT
      LAYER M5 ;
        RECT  40.176 43.116 40.2 43.2 ;
    END
  END request[110]
  PIN request[111]
    DIRECTION INPUT ;
    USE SIGNAL ;
    PORT
      LAYER M5 ;
        RECT  40.272 43.116 40.296 43.2 ;
    END
  END request[111]
  PIN request[112]
    DIRECTION INPUT ;
    USE SIGNAL ;
    PORT
      LAYER M5 ;
        RECT  40.368 43.116 40.392 43.2 ;
    END
  END request[112]
  PIN request[113]
    DIRECTION INPUT ;
    USE SIGNAL ;
    PORT
      LAYER M5 ;
        RECT  40.464 43.116 40.488 43.2 ;
    END
  END request[113]
  PIN request[114]
    DIRECTION INPUT ;
    USE SIGNAL ;
    PORT
      LAYER M5 ;
        RECT  40.56 43.116 40.584 43.2 ;
    END
  END request[114]
  PIN request[115]
    DIRECTION INPUT ;
    USE SIGNAL ;
    PORT
      LAYER M5 ;
        RECT  40.656 43.116 40.68 43.2 ;
    END
  END request[115]
  PIN request[116]
    DIRECTION INPUT ;
    USE SIGNAL ;
    PORT
      LAYER M5 ;
        RECT  40.752 43.116 40.776 43.2 ;
    END
  END request[116]
  PIN request[117]
    DIRECTION INPUT ;
    USE SIGNAL ;
    PORT
      LAYER M5 ;
        RECT  40.848 43.116 40.872 43.2 ;
    END
  END request[117]
  PIN request[118]
    DIRECTION INPUT ;
    USE SIGNAL ;
    PORT
      LAYER M5 ;
        RECT  40.944 43.116 40.968 43.2 ;
    END
  END request[118]
  PIN request[119]
    DIRECTION INPUT ;
    USE SIGNAL ;
    PORT
      LAYER M5 ;
        RECT  41.04 43.116 41.064 43.2 ;
    END
  END request[119]
  PIN request[11]
    DIRECTION INPUT ;
    USE SIGNAL ;
    PORT
      LAYER M5 ;
        RECT  11.472 43.116 11.496 43.2 ;
    END
  END request[11]
  PIN request[120]
    DIRECTION INPUT ;
    USE SIGNAL ;
    PORT
      LAYER M5 ;
        RECT  41.136 43.116 41.16 43.2 ;
    END
  END request[120]
  PIN request[121]
    DIRECTION INPUT ;
    USE SIGNAL ;
    PORT
      LAYER M5 ;
        RECT  41.232 43.116 41.256 43.2 ;
    END
  END request[121]
  PIN request[122]
    DIRECTION INPUT ;
    USE SIGNAL ;
    PORT
      LAYER M5 ;
        RECT  41.328 43.116 41.352 43.2 ;
    END
  END request[122]
  PIN request[123]
    DIRECTION INPUT ;
    USE SIGNAL ;
    PORT
      LAYER M5 ;
        RECT  41.424 43.116 41.448 43.2 ;
    END
  END request[123]
  PIN request[124]
    DIRECTION INPUT ;
    USE SIGNAL ;
    PORT
      LAYER M5 ;
        RECT  41.52 43.116 41.544 43.2 ;
    END
  END request[124]
  PIN request[125]
    DIRECTION INPUT ;
    USE SIGNAL ;
    PORT
      LAYER M5 ;
        RECT  41.616 43.116 41.64 43.2 ;
    END
  END request[125]
  PIN request[126]
    DIRECTION INPUT ;
    USE SIGNAL ;
    PORT
      LAYER M5 ;
        RECT  41.712 43.116 41.736 43.2 ;
    END
  END request[126]
  PIN request[127]
    DIRECTION INPUT ;
    USE SIGNAL ;
    PORT
      LAYER M5 ;
        RECT  48.72 43.116 48.744 43.2 ;
    END
  END request[127]
  PIN request[128]
    DIRECTION INPUT ;
    USE SIGNAL ;
    PORT
      LAYER M5 ;
        RECT  48.816 43.116 48.84 43.2 ;
    END
  END request[128]
  PIN request[129]
    DIRECTION INPUT ;
    USE SIGNAL ;
    PORT
      LAYER M5 ;
        RECT  48.912 43.116 48.936 43.2 ;
    END
  END request[129]
  PIN request[12]
    DIRECTION INPUT ;
    USE SIGNAL ;
    PORT
      LAYER M5 ;
        RECT  11.568 43.116 11.592 43.2 ;
    END
  END request[12]
  PIN request[130]
    DIRECTION INPUT ;
    USE SIGNAL ;
    PORT
      LAYER M5 ;
        RECT  49.008 43.116 49.032 43.2 ;
    END
  END request[130]
  PIN request[131]
    DIRECTION INPUT ;
    USE SIGNAL ;
    PORT
      LAYER M5 ;
        RECT  49.104 43.116 49.128 43.2 ;
    END
  END request[131]
  PIN request[132]
    DIRECTION INPUT ;
    USE SIGNAL ;
    PORT
      LAYER M5 ;
        RECT  49.2 43.116 49.224 43.2 ;
    END
  END request[132]
  PIN request[133]
    DIRECTION INPUT ;
    USE SIGNAL ;
    PORT
      LAYER M5 ;
        RECT  49.296 43.116 49.32 43.2 ;
    END
  END request[133]
  PIN request[134]
    DIRECTION INPUT ;
    USE SIGNAL ;
    PORT
      LAYER M5 ;
        RECT  49.392 43.116 49.416 43.2 ;
    END
  END request[134]
  PIN request[135]
    DIRECTION INPUT ;
    USE SIGNAL ;
    PORT
      LAYER M5 ;
        RECT  49.488 43.116 49.512 43.2 ;
    END
  END request[135]
  PIN request[136]
    DIRECTION INPUT ;
    USE SIGNAL ;
    PORT
      LAYER M5 ;
        RECT  49.584 43.116 49.608 43.2 ;
    END
  END request[136]
  PIN request[137]
    DIRECTION INPUT ;
    USE SIGNAL ;
    PORT
      LAYER M5 ;
        RECT  49.68 43.116 49.704 43.2 ;
    END
  END request[137]
  PIN request[138]
    DIRECTION INPUT ;
    USE SIGNAL ;
    PORT
      LAYER M5 ;
        RECT  49.776 43.116 49.8 43.2 ;
    END
  END request[138]
  PIN request[139]
    DIRECTION INPUT ;
    USE SIGNAL ;
    PORT
      LAYER M5 ;
        RECT  49.872 43.116 49.896 43.2 ;
    END
  END request[139]
  PIN request[13]
    DIRECTION INPUT ;
    USE SIGNAL ;
    PORT
      LAYER M5 ;
        RECT  11.664 43.116 11.688 43.2 ;
    END
  END request[13]
  PIN request[140]
    DIRECTION INPUT ;
    USE SIGNAL ;
    PORT
      LAYER M5 ;
        RECT  49.968 43.116 49.992 43.2 ;
    END
  END request[140]
  PIN request[141]
    DIRECTION INPUT ;
    USE SIGNAL ;
    PORT
      LAYER M5 ;
        RECT  50.064 43.116 50.088 43.2 ;
    END
  END request[141]
  PIN request[142]
    DIRECTION INPUT ;
    USE SIGNAL ;
    PORT
      LAYER M5 ;
        RECT  50.16 43.116 50.184 43.2 ;
    END
  END request[142]
  PIN request[143]
    DIRECTION INPUT ;
    USE SIGNAL ;
    PORT
      LAYER M5 ;
        RECT  50.256 43.116 50.28 43.2 ;
    END
  END request[143]
  PIN request[144]
    DIRECTION INPUT ;
    USE SIGNAL ;
    PORT
      LAYER M5 ;
        RECT  50.352 43.116 50.376 43.2 ;
    END
  END request[144]
  PIN request[145]
    DIRECTION INPUT ;
    USE SIGNAL ;
    PORT
      LAYER M5 ;
        RECT  50.448 43.116 50.472 43.2 ;
    END
  END request[145]
  PIN request[146]
    DIRECTION INPUT ;
    USE SIGNAL ;
    PORT
      LAYER M5 ;
        RECT  50.544 43.116 50.568 43.2 ;
    END
  END request[146]
  PIN request[147]
    DIRECTION INPUT ;
    USE SIGNAL ;
    PORT
      LAYER M5 ;
        RECT  50.64 43.116 50.664 43.2 ;
    END
  END request[147]
  PIN request[148]
    DIRECTION INPUT ;
    USE SIGNAL ;
    PORT
      LAYER M5 ;
        RECT  50.736 43.116 50.76 43.2 ;
    END
  END request[148]
  PIN request[149]
    DIRECTION INPUT ;
    USE SIGNAL ;
    PORT
      LAYER M5 ;
        RECT  50.832 43.116 50.856 43.2 ;
    END
  END request[149]
  PIN request[14]
    DIRECTION INPUT ;
    USE SIGNAL ;
    PORT
      LAYER M5 ;
        RECT  11.76 43.116 11.784 43.2 ;
    END
  END request[14]
  PIN request[150]
    DIRECTION INPUT ;
    USE SIGNAL ;
    PORT
      LAYER M5 ;
        RECT  50.928 43.116 50.952 43.2 ;
    END
  END request[150]
  PIN request[151]
    DIRECTION INPUT ;
    USE SIGNAL ;
    PORT
      LAYER M5 ;
        RECT  51.024 43.116 51.048 43.2 ;
    END
  END request[151]
  PIN request[152]
    DIRECTION INPUT ;
    USE SIGNAL ;
    PORT
      LAYER M5 ;
        RECT  51.12 43.116 51.144 43.2 ;
    END
  END request[152]
  PIN request[153]
    DIRECTION INPUT ;
    USE SIGNAL ;
    PORT
      LAYER M5 ;
        RECT  51.216 43.116 51.24 43.2 ;
    END
  END request[153]
  PIN request[154]
    DIRECTION INPUT ;
    USE SIGNAL ;
    PORT
      LAYER M5 ;
        RECT  51.312 43.116 51.336 43.2 ;
    END
  END request[154]
  PIN request[155]
    DIRECTION INPUT ;
    USE SIGNAL ;
    PORT
      LAYER M5 ;
        RECT  51.408 43.116 51.432 43.2 ;
    END
  END request[155]
  PIN request[156]
    DIRECTION INPUT ;
    USE SIGNAL ;
    PORT
      LAYER M5 ;
        RECT  51.504 43.116 51.528 43.2 ;
    END
  END request[156]
  PIN request[157]
    DIRECTION INPUT ;
    USE SIGNAL ;
    PORT
      LAYER M5 ;
        RECT  51.6 43.116 51.624 43.2 ;
    END
  END request[157]
  PIN request[158]
    DIRECTION INPUT ;
    USE SIGNAL ;
    PORT
      LAYER M5 ;
        RECT  51.696 43.116 51.72 43.2 ;
    END
  END request[158]
  PIN request[159]
    DIRECTION INPUT ;
    USE SIGNAL ;
    PORT
      LAYER M5 ;
        RECT  54.864 43.116 54.888 43.2 ;
    END
  END request[159]
  PIN request[15]
    DIRECTION INPUT ;
    USE SIGNAL ;
    PORT
      LAYER M5 ;
        RECT  11.856 43.116 11.88 43.2 ;
    END
  END request[15]
  PIN request[160]
    DIRECTION INPUT ;
    USE SIGNAL ;
    PORT
      LAYER M5 ;
        RECT  54.96 43.116 54.984 43.2 ;
    END
  END request[160]
  PIN request[161]
    DIRECTION INPUT ;
    USE SIGNAL ;
    PORT
      LAYER M5 ;
        RECT  55.056 43.116 55.08 43.2 ;
    END
  END request[161]
  PIN request[162]
    DIRECTION INPUT ;
    USE SIGNAL ;
    PORT
      LAYER M5 ;
        RECT  55.152 43.116 55.176 43.2 ;
    END
  END request[162]
  PIN request[163]
    DIRECTION INPUT ;
    USE SIGNAL ;
    PORT
      LAYER M5 ;
        RECT  55.248 43.116 55.272 43.2 ;
    END
  END request[163]
  PIN request[164]
    DIRECTION INPUT ;
    USE SIGNAL ;
    PORT
      LAYER M5 ;
        RECT  55.344 43.116 55.368 43.2 ;
    END
  END request[164]
  PIN request[165]
    DIRECTION INPUT ;
    USE SIGNAL ;
    PORT
      LAYER M5 ;
        RECT  55.44 43.116 55.464 43.2 ;
    END
  END request[165]
  PIN request[166]
    DIRECTION INPUT ;
    USE SIGNAL ;
    PORT
      LAYER M5 ;
        RECT  55.536 43.116 55.56 43.2 ;
    END
  END request[166]
  PIN request[167]
    DIRECTION INPUT ;
    USE SIGNAL ;
    PORT
      LAYER M5 ;
        RECT  55.632 43.116 55.656 43.2 ;
    END
  END request[167]
  PIN request[168]
    DIRECTION INPUT ;
    USE SIGNAL ;
    PORT
      LAYER M5 ;
        RECT  55.728 43.116 55.752 43.2 ;
    END
  END request[168]
  PIN request[169]
    DIRECTION INPUT ;
    USE SIGNAL ;
    PORT
      LAYER M5 ;
        RECT  55.824 43.116 55.848 43.2 ;
    END
  END request[169]
  PIN request[16]
    DIRECTION INPUT ;
    USE SIGNAL ;
    PORT
      LAYER M5 ;
        RECT  11.952 43.116 11.976 43.2 ;
    END
  END request[16]
  PIN request[170]
    DIRECTION INPUT ;
    USE SIGNAL ;
    PORT
      LAYER M5 ;
        RECT  55.92 43.116 55.944 43.2 ;
    END
  END request[170]
  PIN request[171]
    DIRECTION INPUT ;
    USE SIGNAL ;
    PORT
      LAYER M5 ;
        RECT  56.016 43.116 56.04 43.2 ;
    END
  END request[171]
  PIN request[172]
    DIRECTION INPUT ;
    USE SIGNAL ;
    PORT
      LAYER M5 ;
        RECT  56.112 43.116 56.136 43.2 ;
    END
  END request[172]
  PIN request[173]
    DIRECTION INPUT ;
    USE SIGNAL ;
    PORT
      LAYER M5 ;
        RECT  56.208 43.116 56.232 43.2 ;
    END
  END request[173]
  PIN request[174]
    DIRECTION INPUT ;
    USE SIGNAL ;
    PORT
      LAYER M5 ;
        RECT  56.304 43.116 56.328 43.2 ;
    END
  END request[174]
  PIN request[175]
    DIRECTION INPUT ;
    USE SIGNAL ;
    PORT
      LAYER M5 ;
        RECT  56.4 43.116 56.424 43.2 ;
    END
  END request[175]
  PIN request[176]
    DIRECTION INPUT ;
    USE SIGNAL ;
    PORT
      LAYER M5 ;
        RECT  56.496 43.116 56.52 43.2 ;
    END
  END request[176]
  PIN request[177]
    DIRECTION INPUT ;
    USE SIGNAL ;
    PORT
      LAYER M5 ;
        RECT  56.592 43.116 56.616 43.2 ;
    END
  END request[177]
  PIN request[178]
    DIRECTION INPUT ;
    USE SIGNAL ;
    PORT
      LAYER M5 ;
        RECT  56.688 43.116 56.712 43.2 ;
    END
  END request[178]
  PIN request[179]
    DIRECTION INPUT ;
    USE SIGNAL ;
    PORT
      LAYER M5 ;
        RECT  56.784 43.116 56.808 43.2 ;
    END
  END request[179]
  PIN request[17]
    DIRECTION INPUT ;
    USE SIGNAL ;
    PORT
      LAYER M5 ;
        RECT  12.048 43.116 12.072 43.2 ;
    END
  END request[17]
  PIN request[180]
    DIRECTION INPUT ;
    USE SIGNAL ;
    PORT
      LAYER M5 ;
        RECT  56.88 43.116 56.904 43.2 ;
    END
  END request[180]
  PIN request[181]
    DIRECTION INPUT ;
    USE SIGNAL ;
    PORT
      LAYER M5 ;
        RECT  56.976 43.116 57 43.2 ;
    END
  END request[181]
  PIN request[182]
    DIRECTION INPUT ;
    USE SIGNAL ;
    PORT
      LAYER M5 ;
        RECT  57.072 43.116 57.096 43.2 ;
    END
  END request[182]
  PIN request[183]
    DIRECTION INPUT ;
    USE SIGNAL ;
    PORT
      LAYER M5 ;
        RECT  57.168 43.116 57.192 43.2 ;
    END
  END request[183]
  PIN request[184]
    DIRECTION INPUT ;
    USE SIGNAL ;
    PORT
      LAYER M5 ;
        RECT  57.264 43.116 57.288 43.2 ;
    END
  END request[184]
  PIN request[185]
    DIRECTION INPUT ;
    USE SIGNAL ;
    PORT
      LAYER M5 ;
        RECT  57.36 43.116 57.384 43.2 ;
    END
  END request[185]
  PIN request[186]
    DIRECTION INPUT ;
    USE SIGNAL ;
    PORT
      LAYER M5 ;
        RECT  57.456 43.116 57.48 43.2 ;
    END
  END request[186]
  PIN request[187]
    DIRECTION INPUT ;
    USE SIGNAL ;
    PORT
      LAYER M5 ;
        RECT  57.552 43.116 57.576 43.2 ;
    END
  END request[187]
  PIN request[188]
    DIRECTION INPUT ;
    USE SIGNAL ;
    PORT
      LAYER M5 ;
        RECT  57.648 43.116 57.672 43.2 ;
    END
  END request[188]
  PIN request[189]
    DIRECTION INPUT ;
    USE SIGNAL ;
    PORT
      LAYER M5 ;
        RECT  57.744 43.116 57.768 43.2 ;
    END
  END request[189]
  PIN request[18]
    DIRECTION INPUT ;
    USE SIGNAL ;
    PORT
      LAYER M5 ;
        RECT  12.144 43.116 12.168 43.2 ;
    END
  END request[18]
  PIN request[190]
    DIRECTION INPUT ;
    USE SIGNAL ;
    PORT
      LAYER M5 ;
        RECT  57.84 43.116 57.864 43.2 ;
    END
  END request[190]
  PIN request[191]
    DIRECTION INPUT ;
    USE SIGNAL ;
    PORT
      LAYER M5 ;
        RECT  41.808 43.116 41.832 43.2 ;
    END
  END request[191]
  PIN request[192]
    DIRECTION INPUT ;
    USE SIGNAL ;
    PORT
      LAYER M5 ;
        RECT  41.904 43.116 41.928 43.2 ;
    END
  END request[192]
  PIN request[193]
    DIRECTION INPUT ;
    USE SIGNAL ;
    PORT
      LAYER M5 ;
        RECT  42 43.116 42.024 43.2 ;
    END
  END request[193]
  PIN request[194]
    DIRECTION INPUT ;
    USE SIGNAL ;
    PORT
      LAYER M5 ;
        RECT  42.096 43.116 42.12 43.2 ;
    END
  END request[194]
  PIN request[195]
    DIRECTION INPUT ;
    USE SIGNAL ;
    PORT
      LAYER M5 ;
        RECT  42.192 43.116 42.216 43.2 ;
    END
  END request[195]
  PIN request[196]
    DIRECTION INPUT ;
    USE SIGNAL ;
    PORT
      LAYER M5 ;
        RECT  42.288 43.116 42.312 43.2 ;
    END
  END request[196]
  PIN request[197]
    DIRECTION INPUT ;
    USE SIGNAL ;
    PORT
      LAYER M5 ;
        RECT  42.384 43.116 42.408 43.2 ;
    END
  END request[197]
  PIN request[198]
    DIRECTION INPUT ;
    USE SIGNAL ;
    PORT
      LAYER M5 ;
        RECT  42.48 43.116 42.504 43.2 ;
    END
  END request[198]
  PIN request[199]
    DIRECTION INPUT ;
    USE SIGNAL ;
    PORT
      LAYER M5 ;
        RECT  42.576 43.116 42.6 43.2 ;
    END
  END request[199]
  PIN request[19]
    DIRECTION INPUT ;
    USE SIGNAL ;
    PORT
      LAYER M5 ;
        RECT  12.24 43.116 12.264 43.2 ;
    END
  END request[19]
  PIN request[1]
    DIRECTION INPUT ;
    USE SIGNAL ;
    PORT
      LAYER M5 ;
        RECT  10.512 43.116 10.536 43.2 ;
    END
  END request[1]
  PIN request[200]
    DIRECTION INPUT ;
    USE SIGNAL ;
    PORT
      LAYER M5 ;
        RECT  42.672 43.116 42.696 43.2 ;
    END
  END request[200]
  PIN request[201]
    DIRECTION INPUT ;
    USE SIGNAL ;
    PORT
      LAYER M5 ;
        RECT  42.768 43.116 42.792 43.2 ;
    END
  END request[201]
  PIN request[202]
    DIRECTION INPUT ;
    USE SIGNAL ;
    PORT
      LAYER M5 ;
        RECT  42.864 43.116 42.888 43.2 ;
    END
  END request[202]
  PIN request[203]
    DIRECTION INPUT ;
    USE SIGNAL ;
    PORT
      LAYER M5 ;
        RECT  42.96 43.116 42.984 43.2 ;
    END
  END request[203]
  PIN request[204]
    DIRECTION INPUT ;
    USE SIGNAL ;
    PORT
      LAYER M5 ;
        RECT  43.056 43.116 43.08 43.2 ;
    END
  END request[204]
  PIN request[205]
    DIRECTION INPUT ;
    USE SIGNAL ;
    PORT
      LAYER M5 ;
        RECT  43.152 43.116 43.176 43.2 ;
    END
  END request[205]
  PIN request[206]
    DIRECTION INPUT ;
    USE SIGNAL ;
    PORT
      LAYER M5 ;
        RECT  43.248 43.116 43.272 43.2 ;
    END
  END request[206]
  PIN request[207]
    DIRECTION INPUT ;
    USE SIGNAL ;
    PORT
      LAYER M5 ;
        RECT  43.344 43.116 43.368 43.2 ;
    END
  END request[207]
  PIN request[208]
    DIRECTION INPUT ;
    USE SIGNAL ;
    PORT
      LAYER M5 ;
        RECT  43.44 43.116 43.464 43.2 ;
    END
  END request[208]
  PIN request[209]
    DIRECTION INPUT ;
    USE SIGNAL ;
    PORT
      LAYER M5 ;
        RECT  43.536 43.116 43.56 43.2 ;
    END
  END request[209]
  PIN request[20]
    DIRECTION INPUT ;
    USE SIGNAL ;
    PORT
      LAYER M5 ;
        RECT  12.336 43.116 12.36 43.2 ;
    END
  END request[20]
  PIN request[210]
    DIRECTION INPUT ;
    USE SIGNAL ;
    PORT
      LAYER M5 ;
        RECT  43.632 43.116 43.656 43.2 ;
    END
  END request[210]
  PIN request[211]
    DIRECTION INPUT ;
    USE SIGNAL ;
    PORT
      LAYER M5 ;
        RECT  43.728 43.116 43.752 43.2 ;
    END
  END request[211]
  PIN request[212]
    DIRECTION INPUT ;
    USE SIGNAL ;
    PORT
      LAYER M5 ;
        RECT  43.824 43.116 43.848 43.2 ;
    END
  END request[212]
  PIN request[213]
    DIRECTION INPUT ;
    USE SIGNAL ;
    PORT
      LAYER M5 ;
        RECT  43.92 43.116 43.944 43.2 ;
    END
  END request[213]
  PIN request[214]
    DIRECTION INPUT ;
    USE SIGNAL ;
    PORT
      LAYER M5 ;
        RECT  44.016 43.116 44.04 43.2 ;
    END
  END request[214]
  PIN request[215]
    DIRECTION INPUT ;
    USE SIGNAL ;
    PORT
      LAYER M5 ;
        RECT  44.112 43.116 44.136 43.2 ;
    END
  END request[215]
  PIN request[216]
    DIRECTION INPUT ;
    USE SIGNAL ;
    PORT
      LAYER M5 ;
        RECT  44.208 43.116 44.232 43.2 ;
    END
  END request[216]
  PIN request[217]
    DIRECTION INPUT ;
    USE SIGNAL ;
    PORT
      LAYER M5 ;
        RECT  44.304 43.116 44.328 43.2 ;
    END
  END request[217]
  PIN request[218]
    DIRECTION INPUT ;
    USE SIGNAL ;
    PORT
      LAYER M5 ;
        RECT  44.4 43.116 44.424 43.2 ;
    END
  END request[218]
  PIN request[219]
    DIRECTION INPUT ;
    USE SIGNAL ;
    PORT
      LAYER M5 ;
        RECT  44.496 43.116 44.52 43.2 ;
    END
  END request[219]
  PIN request[21]
    DIRECTION INPUT ;
    USE SIGNAL ;
    PORT
      LAYER M5 ;
        RECT  12.432 43.116 12.456 43.2 ;
    END
  END request[21]
  PIN request[220]
    DIRECTION INPUT ;
    USE SIGNAL ;
    PORT
      LAYER M5 ;
        RECT  44.592 43.116 44.616 43.2 ;
    END
  END request[220]
  PIN request[221]
    DIRECTION INPUT ;
    USE SIGNAL ;
    PORT
      LAYER M5 ;
        RECT  44.688 43.116 44.712 43.2 ;
    END
  END request[221]
  PIN request[222]
    DIRECTION INPUT ;
    USE SIGNAL ;
    PORT
      LAYER M5 ;
        RECT  44.784 43.116 44.808 43.2 ;
    END
  END request[222]
  PIN request[223]
    DIRECTION INPUT ;
    USE SIGNAL ;
    PORT
      LAYER M5 ;
        RECT  26.448 43.116 26.472 43.2 ;
    END
  END request[223]
  PIN request[224]
    DIRECTION INPUT ;
    USE SIGNAL ;
    PORT
      LAYER M5 ;
        RECT  26.544 43.116 26.568 43.2 ;
    END
  END request[224]
  PIN request[225]
    DIRECTION INPUT ;
    USE SIGNAL ;
    PORT
      LAYER M5 ;
        RECT  26.64 43.116 26.664 43.2 ;
    END
  END request[225]
  PIN request[226]
    DIRECTION INPUT ;
    USE SIGNAL ;
    PORT
      LAYER M5 ;
        RECT  26.736 43.116 26.76 43.2 ;
    END
  END request[226]
  PIN request[227]
    DIRECTION INPUT ;
    USE SIGNAL ;
    PORT
      LAYER M5 ;
        RECT  26.832 43.116 26.856 43.2 ;
    END
  END request[227]
  PIN request[228]
    DIRECTION INPUT ;
    USE SIGNAL ;
    PORT
      LAYER M5 ;
        RECT  26.928 43.116 26.952 43.2 ;
    END
  END request[228]
  PIN request[229]
    DIRECTION INPUT ;
    USE SIGNAL ;
    PORT
      LAYER M5 ;
        RECT  27.024 43.116 27.048 43.2 ;
    END
  END request[229]
  PIN request[22]
    DIRECTION INPUT ;
    USE SIGNAL ;
    PORT
      LAYER M5 ;
        RECT  12.528 43.116 12.552 43.2 ;
    END
  END request[22]
  PIN request[230]
    DIRECTION INPUT ;
    USE SIGNAL ;
    PORT
      LAYER M5 ;
        RECT  27.12 43.116 27.144 43.2 ;
    END
  END request[230]
  PIN request[231]
    DIRECTION INPUT ;
    USE SIGNAL ;
    PORT
      LAYER M5 ;
        RECT  27.216 43.116 27.24 43.2 ;
    END
  END request[231]
  PIN request[232]
    DIRECTION INPUT ;
    USE SIGNAL ;
    PORT
      LAYER M5 ;
        RECT  27.312 43.116 27.336 43.2 ;
    END
  END request[232]
  PIN request[233]
    DIRECTION INPUT ;
    USE SIGNAL ;
    PORT
      LAYER M5 ;
        RECT  27.408 43.116 27.432 43.2 ;
    END
  END request[233]
  PIN request[234]
    DIRECTION INPUT ;
    USE SIGNAL ;
    PORT
      LAYER M5 ;
        RECT  27.504 43.116 27.528 43.2 ;
    END
  END request[234]
  PIN request[235]
    DIRECTION INPUT ;
    USE SIGNAL ;
    PORT
      LAYER M5 ;
        RECT  27.6 43.116 27.624 43.2 ;
    END
  END request[235]
  PIN request[236]
    DIRECTION INPUT ;
    USE SIGNAL ;
    PORT
      LAYER M5 ;
        RECT  27.696 43.116 27.72 43.2 ;
    END
  END request[236]
  PIN request[237]
    DIRECTION INPUT ;
    USE SIGNAL ;
    PORT
      LAYER M5 ;
        RECT  27.792 43.116 27.816 43.2 ;
    END
  END request[237]
  PIN request[238]
    DIRECTION INPUT ;
    USE SIGNAL ;
    PORT
      LAYER M5 ;
        RECT  27.888 43.116 27.912 43.2 ;
    END
  END request[238]
  PIN request[239]
    DIRECTION INPUT ;
    USE SIGNAL ;
    PORT
      LAYER M5 ;
        RECT  27.984 43.116 28.008 43.2 ;
    END
  END request[239]
  PIN request[23]
    DIRECTION INPUT ;
    USE SIGNAL ;
    PORT
      LAYER M5 ;
        RECT  12.624 43.116 12.648 43.2 ;
    END
  END request[23]
  PIN request[240]
    DIRECTION INPUT ;
    USE SIGNAL ;
    PORT
      LAYER M5 ;
        RECT  28.08 43.116 28.104 43.2 ;
    END
  END request[240]
  PIN request[241]
    DIRECTION INPUT ;
    USE SIGNAL ;
    PORT
      LAYER M5 ;
        RECT  28.176 43.116 28.2 43.2 ;
    END
  END request[241]
  PIN request[242]
    DIRECTION INPUT ;
    USE SIGNAL ;
    PORT
      LAYER M5 ;
        RECT  28.272 43.116 28.296 43.2 ;
    END
  END request[242]
  PIN request[243]
    DIRECTION INPUT ;
    USE SIGNAL ;
    PORT
      LAYER M5 ;
        RECT  28.368 43.116 28.392 43.2 ;
    END
  END request[243]
  PIN request[244]
    DIRECTION INPUT ;
    USE SIGNAL ;
    PORT
      LAYER M5 ;
        RECT  28.464 43.116 28.488 43.2 ;
    END
  END request[244]
  PIN request[245]
    DIRECTION INPUT ;
    USE SIGNAL ;
    PORT
      LAYER M5 ;
        RECT  28.56 43.116 28.584 43.2 ;
    END
  END request[245]
  PIN request[246]
    DIRECTION INPUT ;
    USE SIGNAL ;
    PORT
      LAYER M5 ;
        RECT  28.656 43.116 28.68 43.2 ;
    END
  END request[246]
  PIN request[247]
    DIRECTION INPUT ;
    USE SIGNAL ;
    PORT
      LAYER M5 ;
        RECT  28.752 43.116 28.776 43.2 ;
    END
  END request[247]
  PIN request[248]
    DIRECTION INPUT ;
    USE SIGNAL ;
    PORT
      LAYER M5 ;
        RECT  28.848 43.116 28.872 43.2 ;
    END
  END request[248]
  PIN request[249]
    DIRECTION INPUT ;
    USE SIGNAL ;
    PORT
      LAYER M5 ;
        RECT  28.944 43.116 28.968 43.2 ;
    END
  END request[249]
  PIN request[24]
    DIRECTION INPUT ;
    USE SIGNAL ;
    PORT
      LAYER M5 ;
        RECT  12.72 43.116 12.744 43.2 ;
    END
  END request[24]
  PIN request[250]
    DIRECTION INPUT ;
    USE SIGNAL ;
    PORT
      LAYER M5 ;
        RECT  29.04 43.116 29.064 43.2 ;
    END
  END request[250]
  PIN request[251]
    DIRECTION INPUT ;
    USE SIGNAL ;
    PORT
      LAYER M5 ;
        RECT  29.136 43.116 29.16 43.2 ;
    END
  END request[251]
  PIN request[252]
    DIRECTION INPUT ;
    USE SIGNAL ;
    PORT
      LAYER M5 ;
        RECT  29.232 43.116 29.256 43.2 ;
    END
  END request[252]
  PIN request[253]
    DIRECTION INPUT ;
    USE SIGNAL ;
    PORT
      LAYER M5 ;
        RECT  29.328 43.116 29.352 43.2 ;
    END
  END request[253]
  PIN request[254]
    DIRECTION INPUT ;
    USE SIGNAL ;
    PORT
      LAYER M5 ;
        RECT  29.424 43.116 29.448 43.2 ;
    END
  END request[254]
  PIN request[255]
    DIRECTION INPUT ;
    USE SIGNAL ;
    PORT
      LAYER M5 ;
        RECT  32.592 43.116 32.616 43.2 ;
    END
  END request[255]
  PIN request[256]
    DIRECTION INPUT ;
    USE SIGNAL ;
    PORT
      LAYER M5 ;
        RECT  32.688 43.116 32.712 43.2 ;
    END
  END request[256]
  PIN request[257]
    DIRECTION INPUT ;
    USE SIGNAL ;
    PORT
      LAYER M5 ;
        RECT  32.784 43.116 32.808 43.2 ;
    END
  END request[257]
  PIN request[258]
    DIRECTION INPUT ;
    USE SIGNAL ;
    PORT
      LAYER M5 ;
        RECT  32.88 43.116 32.904 43.2 ;
    END
  END request[258]
  PIN request[259]
    DIRECTION INPUT ;
    USE SIGNAL ;
    PORT
      LAYER M5 ;
        RECT  32.976 43.116 33 43.2 ;
    END
  END request[259]
  PIN request[25]
    DIRECTION INPUT ;
    USE SIGNAL ;
    PORT
      LAYER M5 ;
        RECT  12.816 43.116 12.84 43.2 ;
    END
  END request[25]
  PIN request[260]
    DIRECTION INPUT ;
    USE SIGNAL ;
    PORT
      LAYER M5 ;
        RECT  33.072 43.116 33.096 43.2 ;
    END
  END request[260]
  PIN request[261]
    DIRECTION INPUT ;
    USE SIGNAL ;
    PORT
      LAYER M5 ;
        RECT  33.168 43.116 33.192 43.2 ;
    END
  END request[261]
  PIN request[262]
    DIRECTION INPUT ;
    USE SIGNAL ;
    PORT
      LAYER M5 ;
        RECT  33.264 43.116 33.288 43.2 ;
    END
  END request[262]
  PIN request[263]
    DIRECTION INPUT ;
    USE SIGNAL ;
    PORT
      LAYER M5 ;
        RECT  33.36 43.116 33.384 43.2 ;
    END
  END request[263]
  PIN request[264]
    DIRECTION INPUT ;
    USE SIGNAL ;
    PORT
      LAYER M5 ;
        RECT  33.456 43.116 33.48 43.2 ;
    END
  END request[264]
  PIN request[265]
    DIRECTION INPUT ;
    USE SIGNAL ;
    PORT
      LAYER M5 ;
        RECT  33.552 43.116 33.576 43.2 ;
    END
  END request[265]
  PIN request[266]
    DIRECTION INPUT ;
    USE SIGNAL ;
    PORT
      LAYER M5 ;
        RECT  33.648 43.116 33.672 43.2 ;
    END
  END request[266]
  PIN request[267]
    DIRECTION INPUT ;
    USE SIGNAL ;
    PORT
      LAYER M5 ;
        RECT  33.744 43.116 33.768 43.2 ;
    END
  END request[267]
  PIN request[268]
    DIRECTION INPUT ;
    USE SIGNAL ;
    PORT
      LAYER M5 ;
        RECT  33.84 43.116 33.864 43.2 ;
    END
  END request[268]
  PIN request[269]
    DIRECTION INPUT ;
    USE SIGNAL ;
    PORT
      LAYER M5 ;
        RECT  33.936 43.116 33.96 43.2 ;
    END
  END request[269]
  PIN request[26]
    DIRECTION INPUT ;
    USE SIGNAL ;
    PORT
      LAYER M5 ;
        RECT  12.912 43.116 12.936 43.2 ;
    END
  END request[26]
  PIN request[270]
    DIRECTION INPUT ;
    USE SIGNAL ;
    PORT
      LAYER M5 ;
        RECT  34.032 43.116 34.056 43.2 ;
    END
  END request[270]
  PIN request[271]
    DIRECTION INPUT ;
    USE SIGNAL ;
    PORT
      LAYER M5 ;
        RECT  34.128 43.116 34.152 43.2 ;
    END
  END request[271]
  PIN request[272]
    DIRECTION INPUT ;
    USE SIGNAL ;
    PORT
      LAYER M5 ;
        RECT  34.224 43.116 34.248 43.2 ;
    END
  END request[272]
  PIN request[273]
    DIRECTION INPUT ;
    USE SIGNAL ;
    PORT
      LAYER M5 ;
        RECT  34.32 43.116 34.344 43.2 ;
    END
  END request[273]
  PIN request[274]
    DIRECTION INPUT ;
    USE SIGNAL ;
    PORT
      LAYER M5 ;
        RECT  34.416 43.116 34.44 43.2 ;
    END
  END request[274]
  PIN request[275]
    DIRECTION INPUT ;
    USE SIGNAL ;
    PORT
      LAYER M5 ;
        RECT  34.512 43.116 34.536 43.2 ;
    END
  END request[275]
  PIN request[276]
    DIRECTION INPUT ;
    USE SIGNAL ;
    PORT
      LAYER M5 ;
        RECT  34.608 43.116 34.632 43.2 ;
    END
  END request[276]
  PIN request[277]
    DIRECTION INPUT ;
    USE SIGNAL ;
    PORT
      LAYER M5 ;
        RECT  34.704 43.116 34.728 43.2 ;
    END
  END request[277]
  PIN request[278]
    DIRECTION INPUT ;
    USE SIGNAL ;
    PORT
      LAYER M5 ;
        RECT  34.8 43.116 34.824 43.2 ;
    END
  END request[278]
  PIN request[279]
    DIRECTION INPUT ;
    USE SIGNAL ;
    PORT
      LAYER M5 ;
        RECT  34.896 43.116 34.92 43.2 ;
    END
  END request[279]
  PIN request[27]
    DIRECTION INPUT ;
    USE SIGNAL ;
    PORT
      LAYER M5 ;
        RECT  13.008 43.116 13.032 43.2 ;
    END
  END request[27]
  PIN request[280]
    DIRECTION INPUT ;
    USE SIGNAL ;
    PORT
      LAYER M5 ;
        RECT  34.992 43.116 35.016 43.2 ;
    END
  END request[280]
  PIN request[281]
    DIRECTION INPUT ;
    USE SIGNAL ;
    PORT
      LAYER M5 ;
        RECT  35.088 43.116 35.112 43.2 ;
    END
  END request[281]
  PIN request[282]
    DIRECTION INPUT ;
    USE SIGNAL ;
    PORT
      LAYER M5 ;
        RECT  35.184 43.116 35.208 43.2 ;
    END
  END request[282]
  PIN request[283]
    DIRECTION INPUT ;
    USE SIGNAL ;
    PORT
      LAYER M5 ;
        RECT  35.28 43.116 35.304 43.2 ;
    END
  END request[283]
  PIN request[284]
    DIRECTION INPUT ;
    USE SIGNAL ;
    PORT
      LAYER M5 ;
        RECT  35.376 43.116 35.4 43.2 ;
    END
  END request[284]
  PIN request[285]
    DIRECTION INPUT ;
    USE SIGNAL ;
    PORT
      LAYER M5 ;
        RECT  35.472 43.116 35.496 43.2 ;
    END
  END request[285]
  PIN request[286]
    DIRECTION INPUT ;
    USE SIGNAL ;
    PORT
      LAYER M5 ;
        RECT  35.568 43.116 35.592 43.2 ;
    END
  END request[286]
  PIN request[287]
    DIRECTION INPUT ;
    USE SIGNAL ;
    PORT
      LAYER M5 ;
        RECT  35.664 43.116 35.688 43.2 ;
    END
  END request[287]
  PIN request[288]
    DIRECTION INPUT ;
    USE SIGNAL ;
    PORT
      LAYER M5 ;
        RECT  35.76 43.116 35.784 43.2 ;
    END
  END request[288]
  PIN request[289]
    DIRECTION INPUT ;
    USE SIGNAL ;
    PORT
      LAYER M5 ;
        RECT  35.856 43.116 35.88 43.2 ;
    END
  END request[289]
  PIN request[28]
    DIRECTION INPUT ;
    USE SIGNAL ;
    PORT
      LAYER M5 ;
        RECT  13.104 43.116 13.128 43.2 ;
    END
  END request[28]
  PIN request[290]
    DIRECTION INPUT ;
    USE SIGNAL ;
    PORT
      LAYER M5 ;
        RECT  35.952 43.116 35.976 43.2 ;
    END
  END request[290]
  PIN request[291]
    DIRECTION INPUT ;
    USE SIGNAL ;
    PORT
      LAYER M5 ;
        RECT  36.048 43.116 36.072 43.2 ;
    END
  END request[291]
  PIN request[292]
    DIRECTION INPUT ;
    USE SIGNAL ;
    PORT
      LAYER M5 ;
        RECT  36.144 43.116 36.168 43.2 ;
    END
  END request[292]
  PIN request[293]
    DIRECTION INPUT ;
    USE SIGNAL ;
    PORT
      LAYER M5 ;
        RECT  36.24 43.116 36.264 43.2 ;
    END
  END request[293]
  PIN request[294]
    DIRECTION INPUT ;
    USE SIGNAL ;
    PORT
      LAYER M5 ;
        RECT  36.336 43.116 36.36 43.2 ;
    END
  END request[294]
  PIN request[295]
    DIRECTION INPUT ;
    USE SIGNAL ;
    PORT
      LAYER M5 ;
        RECT  36.432 43.116 36.456 43.2 ;
    END
  END request[295]
  PIN request[296]
    DIRECTION INPUT ;
    USE SIGNAL ;
    PORT
      LAYER M5 ;
        RECT  36.528 43.116 36.552 43.2 ;
    END
  END request[296]
  PIN request[297]
    DIRECTION INPUT ;
    USE SIGNAL ;
    PORT
      LAYER M5 ;
        RECT  36.624 43.116 36.648 43.2 ;
    END
  END request[297]
  PIN request[298]
    DIRECTION INPUT ;
    USE SIGNAL ;
    PORT
      LAYER M5 ;
        RECT  36.72 43.116 36.744 43.2 ;
    END
  END request[298]
  PIN request[299]
    DIRECTION INPUT ;
    USE SIGNAL ;
    PORT
      LAYER M5 ;
        RECT  36.816 43.116 36.84 43.2 ;
    END
  END request[299]
  PIN request[29]
    DIRECTION INPUT ;
    USE SIGNAL ;
    PORT
      LAYER M5 ;
        RECT  13.2 43.116 13.224 43.2 ;
    END
  END request[29]
  PIN request[2]
    DIRECTION INPUT ;
    USE SIGNAL ;
    PORT
      LAYER M5 ;
        RECT  10.608 43.116 10.632 43.2 ;
    END
  END request[2]
  PIN request[300]
    DIRECTION INPUT ;
    USE SIGNAL ;
    PORT
      LAYER M5 ;
        RECT  36.912 43.116 36.936 43.2 ;
    END
  END request[300]
  PIN request[301]
    DIRECTION INPUT ;
    USE SIGNAL ;
    PORT
      LAYER M5 ;
        RECT  37.008 43.116 37.032 43.2 ;
    END
  END request[301]
  PIN request[302]
    DIRECTION INPUT ;
    USE SIGNAL ;
    PORT
      LAYER M5 ;
        RECT  37.104 43.116 37.128 43.2 ;
    END
  END request[302]
  PIN request[303]
    DIRECTION INPUT ;
    USE SIGNAL ;
    PORT
      LAYER M5 ;
        RECT  37.2 43.116 37.224 43.2 ;
    END
  END request[303]
  PIN request[304]
    DIRECTION INPUT ;
    USE SIGNAL ;
    PORT
      LAYER M5 ;
        RECT  37.296 43.116 37.32 43.2 ;
    END
  END request[304]
  PIN request[305]
    DIRECTION INPUT ;
    USE SIGNAL ;
    PORT
      LAYER M5 ;
        RECT  37.392 43.116 37.416 43.2 ;
    END
  END request[305]
  PIN request[306]
    DIRECTION INPUT ;
    USE SIGNAL ;
    PORT
      LAYER M5 ;
        RECT  37.488 43.116 37.512 43.2 ;
    END
  END request[306]
  PIN request[307]
    DIRECTION INPUT ;
    USE SIGNAL ;
    PORT
      LAYER M5 ;
        RECT  37.584 43.116 37.608 43.2 ;
    END
  END request[307]
  PIN request[308]
    DIRECTION INPUT ;
    USE SIGNAL ;
    PORT
      LAYER M5 ;
        RECT  37.68 43.116 37.704 43.2 ;
    END
  END request[308]
  PIN request[309]
    DIRECTION INPUT ;
    USE SIGNAL ;
    PORT
      LAYER M5 ;
        RECT  37.776 43.116 37.8 43.2 ;
    END
  END request[309]
  PIN request[30]
    DIRECTION INPUT ;
    USE SIGNAL ;
    PORT
      LAYER M5 ;
        RECT  13.296 43.116 13.32 43.2 ;
    END
  END request[30]
  PIN request[310]
    DIRECTION INPUT ;
    USE SIGNAL ;
    PORT
      LAYER M5 ;
        RECT  37.872 43.116 37.896 43.2 ;
    END
  END request[310]
  PIN request[311]
    DIRECTION INPUT ;
    USE SIGNAL ;
    PORT
      LAYER M5 ;
        RECT  37.968 43.116 37.992 43.2 ;
    END
  END request[311]
  PIN request[312]
    DIRECTION INPUT ;
    USE SIGNAL ;
    PORT
      LAYER M5 ;
        RECT  38.064 43.116 38.088 43.2 ;
    END
  END request[312]
  PIN request[313]
    DIRECTION INPUT ;
    USE SIGNAL ;
    PORT
      LAYER M5 ;
        RECT  38.16 43.116 38.184 43.2 ;
    END
  END request[313]
  PIN request[314]
    DIRECTION INPUT ;
    USE SIGNAL ;
    PORT
      LAYER M5 ;
        RECT  38.256 43.116 38.28 43.2 ;
    END
  END request[314]
  PIN request[315]
    DIRECTION INPUT ;
    USE SIGNAL ;
    PORT
      LAYER M5 ;
        RECT  38.352 43.116 38.376 43.2 ;
    END
  END request[315]
  PIN request[316]
    DIRECTION INPUT ;
    USE SIGNAL ;
    PORT
      LAYER M5 ;
        RECT  38.448 43.116 38.472 43.2 ;
    END
  END request[316]
  PIN request[317]
    DIRECTION INPUT ;
    USE SIGNAL ;
    PORT
      LAYER M5 ;
        RECT  38.544 43.116 38.568 43.2 ;
    END
  END request[317]
  PIN request[318]
    DIRECTION INPUT ;
    USE SIGNAL ;
    PORT
      LAYER M5 ;
        RECT  38.64 43.116 38.664 43.2 ;
    END
  END request[318]
  PIN request[319]
    DIRECTION INPUT ;
    USE SIGNAL ;
    PORT
      LAYER M5 ;
        RECT  22.608 43.116 22.632 43.2 ;
    END
  END request[319]
  PIN request[31]
    DIRECTION INPUT ;
    USE SIGNAL ;
    PORT
      LAYER M5 ;
        RECT  19.536 43.116 19.56 43.2 ;
    END
  END request[31]
  PIN request[320]
    DIRECTION INPUT ;
    USE SIGNAL ;
    PORT
      LAYER M5 ;
        RECT  22.704 43.116 22.728 43.2 ;
    END
  END request[320]
  PIN request[321]
    DIRECTION INPUT ;
    USE SIGNAL ;
    PORT
      LAYER M5 ;
        RECT  22.8 43.116 22.824 43.2 ;
    END
  END request[321]
  PIN request[322]
    DIRECTION INPUT ;
    USE SIGNAL ;
    PORT
      LAYER M5 ;
        RECT  22.896 43.116 22.92 43.2 ;
    END
  END request[322]
  PIN request[323]
    DIRECTION INPUT ;
    USE SIGNAL ;
    PORT
      LAYER M5 ;
        RECT  22.992 43.116 23.016 43.2 ;
    END
  END request[323]
  PIN request[324]
    DIRECTION INPUT ;
    USE SIGNAL ;
    PORT
      LAYER M5 ;
        RECT  23.088 43.116 23.112 43.2 ;
    END
  END request[324]
  PIN request[325]
    DIRECTION INPUT ;
    USE SIGNAL ;
    PORT
      LAYER M5 ;
        RECT  23.184 43.116 23.208 43.2 ;
    END
  END request[325]
  PIN request[326]
    DIRECTION INPUT ;
    USE SIGNAL ;
    PORT
      LAYER M5 ;
        RECT  23.28 43.116 23.304 43.2 ;
    END
  END request[326]
  PIN request[327]
    DIRECTION INPUT ;
    USE SIGNAL ;
    PORT
      LAYER M5 ;
        RECT  23.376 43.116 23.4 43.2 ;
    END
  END request[327]
  PIN request[328]
    DIRECTION INPUT ;
    USE SIGNAL ;
    PORT
      LAYER M5 ;
        RECT  23.472 43.116 23.496 43.2 ;
    END
  END request[328]
  PIN request[329]
    DIRECTION INPUT ;
    USE SIGNAL ;
    PORT
      LAYER M5 ;
        RECT  23.568 43.116 23.592 43.2 ;
    END
  END request[329]
  PIN request[32]
    DIRECTION INPUT ;
    USE SIGNAL ;
    PORT
      LAYER M5 ;
        RECT  19.632 43.116 19.656 43.2 ;
    END
  END request[32]
  PIN request[330]
    DIRECTION INPUT ;
    USE SIGNAL ;
    PORT
      LAYER M5 ;
        RECT  23.664 43.116 23.688 43.2 ;
    END
  END request[330]
  PIN request[331]
    DIRECTION INPUT ;
    USE SIGNAL ;
    PORT
      LAYER M5 ;
        RECT  23.76 43.116 23.784 43.2 ;
    END
  END request[331]
  PIN request[332]
    DIRECTION INPUT ;
    USE SIGNAL ;
    PORT
      LAYER M5 ;
        RECT  23.856 43.116 23.88 43.2 ;
    END
  END request[332]
  PIN request[333]
    DIRECTION INPUT ;
    USE SIGNAL ;
    PORT
      LAYER M5 ;
        RECT  23.952 43.116 23.976 43.2 ;
    END
  END request[333]
  PIN request[334]
    DIRECTION INPUT ;
    USE SIGNAL ;
    PORT
      LAYER M5 ;
        RECT  24.048 43.116 24.072 43.2 ;
    END
  END request[334]
  PIN request[335]
    DIRECTION INPUT ;
    USE SIGNAL ;
    PORT
      LAYER M5 ;
        RECT  24.144 43.116 24.168 43.2 ;
    END
  END request[335]
  PIN request[336]
    DIRECTION INPUT ;
    USE SIGNAL ;
    PORT
      LAYER M5 ;
        RECT  24.24 43.116 24.264 43.2 ;
    END
  END request[336]
  PIN request[337]
    DIRECTION INPUT ;
    USE SIGNAL ;
    PORT
      LAYER M5 ;
        RECT  24.336 43.116 24.36 43.2 ;
    END
  END request[337]
  PIN request[338]
    DIRECTION INPUT ;
    USE SIGNAL ;
    PORT
      LAYER M5 ;
        RECT  24.432 43.116 24.456 43.2 ;
    END
  END request[338]
  PIN request[339]
    DIRECTION INPUT ;
    USE SIGNAL ;
    PORT
      LAYER M5 ;
        RECT  24.528 43.116 24.552 43.2 ;
    END
  END request[339]
  PIN request[33]
    DIRECTION INPUT ;
    USE SIGNAL ;
    PORT
      LAYER M5 ;
        RECT  19.728 43.116 19.752 43.2 ;
    END
  END request[33]
  PIN request[340]
    DIRECTION INPUT ;
    USE SIGNAL ;
    PORT
      LAYER M5 ;
        RECT  24.624 43.116 24.648 43.2 ;
    END
  END request[340]
  PIN request[341]
    DIRECTION INPUT ;
    USE SIGNAL ;
    PORT
      LAYER M5 ;
        RECT  24.72 43.116 24.744 43.2 ;
    END
  END request[341]
  PIN request[342]
    DIRECTION INPUT ;
    USE SIGNAL ;
    PORT
      LAYER M5 ;
        RECT  24.816 43.116 24.84 43.2 ;
    END
  END request[342]
  PIN request[34]
    DIRECTION INPUT ;
    USE SIGNAL ;
    PORT
      LAYER M5 ;
        RECT  19.824 43.116 19.848 43.2 ;
    END
  END request[34]
  PIN request[35]
    DIRECTION INPUT ;
    USE SIGNAL ;
    PORT
      LAYER M5 ;
        RECT  19.92 43.116 19.944 43.2 ;
    END
  END request[35]
  PIN request[36]
    DIRECTION INPUT ;
    USE SIGNAL ;
    PORT
      LAYER M5 ;
        RECT  20.016 43.116 20.04 43.2 ;
    END
  END request[36]
  PIN request[37]
    DIRECTION INPUT ;
    USE SIGNAL ;
    PORT
      LAYER M5 ;
        RECT  20.112 43.116 20.136 43.2 ;
    END
  END request[37]
  PIN request[38]
    DIRECTION INPUT ;
    USE SIGNAL ;
    PORT
      LAYER M5 ;
        RECT  20.208 43.116 20.232 43.2 ;
    END
  END request[38]
  PIN request[39]
    DIRECTION INPUT ;
    USE SIGNAL ;
    PORT
      LAYER M5 ;
        RECT  20.304 43.116 20.328 43.2 ;
    END
  END request[39]
  PIN request[3]
    DIRECTION INPUT ;
    USE SIGNAL ;
    PORT
      LAYER M5 ;
        RECT  10.704 43.116 10.728 43.2 ;
    END
  END request[3]
  PIN request[40]
    DIRECTION INPUT ;
    USE SIGNAL ;
    PORT
      LAYER M5 ;
        RECT  20.4 43.116 20.424 43.2 ;
    END
  END request[40]
  PIN request[41]
    DIRECTION INPUT ;
    USE SIGNAL ;
    PORT
      LAYER M5 ;
        RECT  20.496 43.116 20.52 43.2 ;
    END
  END request[41]
  PIN request[42]
    DIRECTION INPUT ;
    USE SIGNAL ;
    PORT
      LAYER M5 ;
        RECT  20.592 43.116 20.616 43.2 ;
    END
  END request[42]
  PIN request[43]
    DIRECTION INPUT ;
    USE SIGNAL ;
    PORT
      LAYER M5 ;
        RECT  20.688 43.116 20.712 43.2 ;
    END
  END request[43]
  PIN request[44]
    DIRECTION INPUT ;
    USE SIGNAL ;
    PORT
      LAYER M5 ;
        RECT  20.784 43.116 20.808 43.2 ;
    END
  END request[44]
  PIN request[45]
    DIRECTION INPUT ;
    USE SIGNAL ;
    PORT
      LAYER M5 ;
        RECT  20.88 43.116 20.904 43.2 ;
    END
  END request[45]
  PIN request[46]
    DIRECTION INPUT ;
    USE SIGNAL ;
    PORT
      LAYER M5 ;
        RECT  20.976 43.116 21 43.2 ;
    END
  END request[46]
  PIN request[47]
    DIRECTION INPUT ;
    USE SIGNAL ;
    PORT
      LAYER M5 ;
        RECT  21.072 43.116 21.096 43.2 ;
    END
  END request[47]
  PIN request[48]
    DIRECTION INPUT ;
    USE SIGNAL ;
    PORT
      LAYER M5 ;
        RECT  21.168 43.116 21.192 43.2 ;
    END
  END request[48]
  PIN request[49]
    DIRECTION INPUT ;
    USE SIGNAL ;
    PORT
      LAYER M5 ;
        RECT  21.264 43.116 21.288 43.2 ;
    END
  END request[49]
  PIN request[4]
    DIRECTION INPUT ;
    USE SIGNAL ;
    PORT
      LAYER M5 ;
        RECT  10.8 43.116 10.824 43.2 ;
    END
  END request[4]
  PIN request[50]
    DIRECTION INPUT ;
    USE SIGNAL ;
    PORT
      LAYER M5 ;
        RECT  21.36 43.116 21.384 43.2 ;
    END
  END request[50]
  PIN request[51]
    DIRECTION INPUT ;
    USE SIGNAL ;
    PORT
      LAYER M5 ;
        RECT  21.456 43.116 21.48 43.2 ;
    END
  END request[51]
  PIN request[52]
    DIRECTION INPUT ;
    USE SIGNAL ;
    PORT
      LAYER M5 ;
        RECT  21.552 43.116 21.576 43.2 ;
    END
  END request[52]
  PIN request[53]
    DIRECTION INPUT ;
    USE SIGNAL ;
    PORT
      LAYER M5 ;
        RECT  21.648 43.116 21.672 43.2 ;
    END
  END request[53]
  PIN request[54]
    DIRECTION INPUT ;
    USE SIGNAL ;
    PORT
      LAYER M5 ;
        RECT  21.744 43.116 21.768 43.2 ;
    END
  END request[54]
  PIN request[55]
    DIRECTION INPUT ;
    USE SIGNAL ;
    PORT
      LAYER M5 ;
        RECT  21.84 43.116 21.864 43.2 ;
    END
  END request[55]
  PIN request[56]
    DIRECTION INPUT ;
    USE SIGNAL ;
    PORT
      LAYER M5 ;
        RECT  21.936 43.116 21.96 43.2 ;
    END
  END request[56]
  PIN request[57]
    DIRECTION INPUT ;
    USE SIGNAL ;
    PORT
      LAYER M5 ;
        RECT  22.032 43.116 22.056 43.2 ;
    END
  END request[57]
  PIN request[58]
    DIRECTION INPUT ;
    USE SIGNAL ;
    PORT
      LAYER M5 ;
        RECT  22.128 43.116 22.152 43.2 ;
    END
  END request[58]
  PIN request[59]
    DIRECTION INPUT ;
    USE SIGNAL ;
    PORT
      LAYER M5 ;
        RECT  22.224 43.116 22.248 43.2 ;
    END
  END request[59]
  PIN request[5]
    DIRECTION INPUT ;
    USE SIGNAL ;
    PORT
      LAYER M5 ;
        RECT  10.896 43.116 10.92 43.2 ;
    END
  END request[5]
  PIN request[60]
    DIRECTION INPUT ;
    USE SIGNAL ;
    PORT
      LAYER M5 ;
        RECT  22.32 43.116 22.344 43.2 ;
    END
  END request[60]
  PIN request[61]
    DIRECTION INPUT ;
    USE SIGNAL ;
    PORT
      LAYER M5 ;
        RECT  22.416 43.116 22.44 43.2 ;
    END
  END request[61]
  PIN request[62]
    DIRECTION INPUT ;
    USE SIGNAL ;
    PORT
      LAYER M5 ;
        RECT  22.512 43.116 22.536 43.2 ;
    END
  END request[62]
  PIN request[63]
    DIRECTION INPUT ;
    USE SIGNAL ;
    PORT
      LAYER M5 ;
        RECT  29.52 43.116 29.544 43.2 ;
    END
  END request[63]
  PIN request[64]
    DIRECTION INPUT ;
    USE SIGNAL ;
    PORT
      LAYER M5 ;
        RECT  29.616 43.116 29.64 43.2 ;
    END
  END request[64]
  PIN request[65]
    DIRECTION INPUT ;
    USE SIGNAL ;
    PORT
      LAYER M5 ;
        RECT  29.712 43.116 29.736 43.2 ;
    END
  END request[65]
  PIN request[66]
    DIRECTION INPUT ;
    USE SIGNAL ;
    PORT
      LAYER M5 ;
        RECT  29.808 43.116 29.832 43.2 ;
    END
  END request[66]
  PIN request[67]
    DIRECTION INPUT ;
    USE SIGNAL ;
    PORT
      LAYER M5 ;
        RECT  29.904 43.116 29.928 43.2 ;
    END
  END request[67]
  PIN request[68]
    DIRECTION INPUT ;
    USE SIGNAL ;
    PORT
      LAYER M5 ;
        RECT  30 43.116 30.024 43.2 ;
    END
  END request[68]
  PIN request[69]
    DIRECTION INPUT ;
    USE SIGNAL ;
    PORT
      LAYER M5 ;
        RECT  30.096 43.116 30.12 43.2 ;
    END
  END request[69]
  PIN request[6]
    DIRECTION INPUT ;
    USE SIGNAL ;
    PORT
      LAYER M5 ;
        RECT  10.992 43.116 11.016 43.2 ;
    END
  END request[6]
  PIN request[70]
    DIRECTION INPUT ;
    USE SIGNAL ;
    PORT
      LAYER M5 ;
        RECT  30.192 43.116 30.216 43.2 ;
    END
  END request[70]
  PIN request[71]
    DIRECTION INPUT ;
    USE SIGNAL ;
    PORT
      LAYER M5 ;
        RECT  30.288 43.116 30.312 43.2 ;
    END
  END request[71]
  PIN request[72]
    DIRECTION INPUT ;
    USE SIGNAL ;
    PORT
      LAYER M5 ;
        RECT  30.384 43.116 30.408 43.2 ;
    END
  END request[72]
  PIN request[73]
    DIRECTION INPUT ;
    USE SIGNAL ;
    PORT
      LAYER M5 ;
        RECT  30.48 43.116 30.504 43.2 ;
    END
  END request[73]
  PIN request[74]
    DIRECTION INPUT ;
    USE SIGNAL ;
    PORT
      LAYER M5 ;
        RECT  30.576 43.116 30.6 43.2 ;
    END
  END request[74]
  PIN request[75]
    DIRECTION INPUT ;
    USE SIGNAL ;
    PORT
      LAYER M5 ;
        RECT  30.672 43.116 30.696 43.2 ;
    END
  END request[75]
  PIN request[76]
    DIRECTION INPUT ;
    USE SIGNAL ;
    PORT
      LAYER M5 ;
        RECT  30.768 43.116 30.792 43.2 ;
    END
  END request[76]
  PIN request[77]
    DIRECTION INPUT ;
    USE SIGNAL ;
    PORT
      LAYER M5 ;
        RECT  30.864 43.116 30.888 43.2 ;
    END
  END request[77]
  PIN request[78]
    DIRECTION INPUT ;
    USE SIGNAL ;
    PORT
      LAYER M5 ;
        RECT  30.96 43.116 30.984 43.2 ;
    END
  END request[78]
  PIN request[79]
    DIRECTION INPUT ;
    USE SIGNAL ;
    PORT
      LAYER M5 ;
        RECT  31.056 43.116 31.08 43.2 ;
    END
  END request[79]
  PIN request[7]
    DIRECTION INPUT ;
    USE SIGNAL ;
    PORT
      LAYER M5 ;
        RECT  11.088 43.116 11.112 43.2 ;
    END
  END request[7]
  PIN request[80]
    DIRECTION INPUT ;
    USE SIGNAL ;
    PORT
      LAYER M5 ;
        RECT  31.152 43.116 31.176 43.2 ;
    END
  END request[80]
  PIN request[81]
    DIRECTION INPUT ;
    USE SIGNAL ;
    PORT
      LAYER M5 ;
        RECT  31.248 43.116 31.272 43.2 ;
    END
  END request[81]
  PIN request[82]
    DIRECTION INPUT ;
    USE SIGNAL ;
    PORT
      LAYER M5 ;
        RECT  31.344 43.116 31.368 43.2 ;
    END
  END request[82]
  PIN request[83]
    DIRECTION INPUT ;
    USE SIGNAL ;
    PORT
      LAYER M5 ;
        RECT  31.44 43.116 31.464 43.2 ;
    END
  END request[83]
  PIN request[84]
    DIRECTION INPUT ;
    USE SIGNAL ;
    PORT
      LAYER M5 ;
        RECT  31.536 43.116 31.56 43.2 ;
    END
  END request[84]
  PIN request[85]
    DIRECTION INPUT ;
    USE SIGNAL ;
    PORT
      LAYER M5 ;
        RECT  31.632 43.116 31.656 43.2 ;
    END
  END request[85]
  PIN request[86]
    DIRECTION INPUT ;
    USE SIGNAL ;
    PORT
      LAYER M5 ;
        RECT  31.728 43.116 31.752 43.2 ;
    END
  END request[86]
  PIN request[87]
    DIRECTION INPUT ;
    USE SIGNAL ;
    PORT
      LAYER M5 ;
        RECT  31.824 43.116 31.848 43.2 ;
    END
  END request[87]
  PIN request[88]
    DIRECTION INPUT ;
    USE SIGNAL ;
    PORT
      LAYER M5 ;
        RECT  31.92 43.116 31.944 43.2 ;
    END
  END request[88]
  PIN request[89]
    DIRECTION INPUT ;
    USE SIGNAL ;
    PORT
      LAYER M5 ;
        RECT  32.016 43.116 32.04 43.2 ;
    END
  END request[89]
  PIN request[8]
    DIRECTION INPUT ;
    USE SIGNAL ;
    PORT
      LAYER M5 ;
        RECT  11.184 43.116 11.208 43.2 ;
    END
  END request[8]
  PIN request[90]
    DIRECTION INPUT ;
    USE SIGNAL ;
    PORT
      LAYER M5 ;
        RECT  32.112 43.116 32.136 43.2 ;
    END
  END request[90]
  PIN request[91]
    DIRECTION INPUT ;
    USE SIGNAL ;
    PORT
      LAYER M5 ;
        RECT  32.208 43.116 32.232 43.2 ;
    END
  END request[91]
  PIN request[92]
    DIRECTION INPUT ;
    USE SIGNAL ;
    PORT
      LAYER M5 ;
        RECT  32.304 43.116 32.328 43.2 ;
    END
  END request[92]
  PIN request[93]
    DIRECTION INPUT ;
    USE SIGNAL ;
    PORT
      LAYER M5 ;
        RECT  32.4 43.116 32.424 43.2 ;
    END
  END request[93]
  PIN request[94]
    DIRECTION INPUT ;
    USE SIGNAL ;
    PORT
      LAYER M5 ;
        RECT  32.496 43.116 32.52 43.2 ;
    END
  END request[94]
  PIN request[95]
    DIRECTION INPUT ;
    USE SIGNAL ;
    PORT
      LAYER M5 ;
        RECT  38.736 43.116 38.76 43.2 ;
    END
  END request[95]
  PIN request[96]
    DIRECTION INPUT ;
    USE SIGNAL ;
    PORT
      LAYER M5 ;
        RECT  38.832 43.116 38.856 43.2 ;
    END
  END request[96]
  PIN request[97]
    DIRECTION INPUT ;
    USE SIGNAL ;
    PORT
      LAYER M5 ;
        RECT  38.928 43.116 38.952 43.2 ;
    END
  END request[97]
  PIN request[98]
    DIRECTION INPUT ;
    USE SIGNAL ;
    PORT
      LAYER M5 ;
        RECT  39.024 43.116 39.048 43.2 ;
    END
  END request[98]
  PIN request[99]
    DIRECTION INPUT ;
    USE SIGNAL ;
    PORT
      LAYER M5 ;
        RECT  39.12 43.116 39.144 43.2 ;
    END
  END request[99]
  PIN request[9]
    DIRECTION INPUT ;
    USE SIGNAL ;
    PORT
      LAYER M5 ;
        RECT  11.28 43.116 11.304 43.2 ;
    END
  END request[9]
  PIN request_ready
    DIRECTION OUTPUT ;
    USE SIGNAL ;
    PORT
      LAYER M5 ;
        RECT  24.912 43.116 24.936 43.2 ;
    END
  END request_ready
  PIN response[0]
    DIRECTION OUTPUT ;
    USE SIGNAL ;
    PORT
      LAYER M5 ;
        RECT  25.008 43.116 25.032 43.2 ;
    END
  END response[0]
  PIN response[100]
    DIRECTION OUTPUT ;
    USE SIGNAL ;
    PORT
      LAYER M5 ;
        RECT  19.248 43.116 19.272 43.2 ;
    END
  END response[100]
  PIN response[101]
    DIRECTION OUTPUT ;
    USE SIGNAL ;
    PORT
      LAYER M5 ;
        RECT  19.344 43.116 19.368 43.2 ;
    END
  END response[101]
  PIN response[102]
    DIRECTION OUTPUT ;
    USE SIGNAL ;
    PORT
      LAYER M5 ;
        RECT  19.44 43.116 19.464 43.2 ;
    END
  END response[102]
  PIN response[103]
    DIRECTION OUTPUT ;
    USE SIGNAL ;
    PORT
      LAYER M5 ;
        RECT  3.408 43.116 3.432 43.2 ;
    END
  END response[103]
  PIN response[104]
    DIRECTION OUTPUT ;
    USE SIGNAL ;
    PORT
      LAYER M5 ;
        RECT  3.504 43.116 3.528 43.2 ;
    END
  END response[104]
  PIN response[105]
    DIRECTION OUTPUT ;
    USE SIGNAL ;
    PORT
      LAYER M5 ;
        RECT  3.6 43.116 3.624 43.2 ;
    END
  END response[105]
  PIN response[106]
    DIRECTION OUTPUT ;
    USE SIGNAL ;
    PORT
      LAYER M5 ;
        RECT  3.696 43.116 3.72 43.2 ;
    END
  END response[106]
  PIN response[107]
    DIRECTION OUTPUT ;
    USE SIGNAL ;
    PORT
      LAYER M5 ;
        RECT  3.792 43.116 3.816 43.2 ;
    END
  END response[107]
  PIN response[108]
    DIRECTION OUTPUT ;
    USE SIGNAL ;
    PORT
      LAYER M5 ;
        RECT  3.888 43.116 3.912 43.2 ;
    END
  END response[108]
  PIN response[109]
    DIRECTION OUTPUT ;
    USE SIGNAL ;
    PORT
      LAYER M5 ;
        RECT  3.984 43.116 4.008 43.2 ;
    END
  END response[109]
  PIN response[10]
    DIRECTION OUTPUT ;
    USE SIGNAL ;
    PORT
      LAYER M5 ;
        RECT  13.68 43.116 13.704 43.2 ;
    END
  END response[10]
  PIN response[110]
    DIRECTION OUTPUT ;
    USE SIGNAL ;
    PORT
      LAYER M5 ;
        RECT  4.08 43.116 4.104 43.2 ;
    END
  END response[110]
  PIN response[111]
    DIRECTION OUTPUT ;
    USE SIGNAL ;
    PORT
      LAYER M5 ;
        RECT  4.176 43.116 4.2 43.2 ;
    END
  END response[111]
  PIN response[112]
    DIRECTION OUTPUT ;
    USE SIGNAL ;
    PORT
      LAYER M5 ;
        RECT  4.272 43.116 4.296 43.2 ;
    END
  END response[112]
  PIN response[113]
    DIRECTION OUTPUT ;
    USE SIGNAL ;
    PORT
      LAYER M5 ;
        RECT  4.368 43.116 4.392 43.2 ;
    END
  END response[113]
  PIN response[114]
    DIRECTION OUTPUT ;
    USE SIGNAL ;
    PORT
      LAYER M5 ;
        RECT  4.464 43.116 4.488 43.2 ;
    END
  END response[114]
  PIN response[115]
    DIRECTION OUTPUT ;
    USE SIGNAL ;
    PORT
      LAYER M5 ;
        RECT  4.56 43.116 4.584 43.2 ;
    END
  END response[115]
  PIN response[116]
    DIRECTION OUTPUT ;
    USE SIGNAL ;
    PORT
      LAYER M5 ;
        RECT  4.656 43.116 4.68 43.2 ;
    END
  END response[116]
  PIN response[117]
    DIRECTION OUTPUT ;
    USE SIGNAL ;
    PORT
      LAYER M5 ;
        RECT  4.752 43.116 4.776 43.2 ;
    END
  END response[117]
  PIN response[118]
    DIRECTION OUTPUT ;
    USE SIGNAL ;
    PORT
      LAYER M5 ;
        RECT  4.848 43.116 4.872 43.2 ;
    END
  END response[118]
  PIN response[119]
    DIRECTION OUTPUT ;
    USE SIGNAL ;
    PORT
      LAYER M5 ;
        RECT  4.944 43.116 4.968 43.2 ;
    END
  END response[119]
  PIN response[11]
    DIRECTION OUTPUT ;
    USE SIGNAL ;
    PORT
      LAYER M5 ;
        RECT  13.776 43.116 13.8 43.2 ;
    END
  END response[11]
  PIN response[120]
    DIRECTION OUTPUT ;
    USE SIGNAL ;
    PORT
      LAYER M5 ;
        RECT  5.04 43.116 5.064 43.2 ;
    END
  END response[120]
  PIN response[121]
    DIRECTION OUTPUT ;
    USE SIGNAL ;
    PORT
      LAYER M5 ;
        RECT  5.136 43.116 5.16 43.2 ;
    END
  END response[121]
  PIN response[122]
    DIRECTION OUTPUT ;
    USE SIGNAL ;
    PORT
      LAYER M5 ;
        RECT  5.232 43.116 5.256 43.2 ;
    END
  END response[122]
  PIN response[123]
    DIRECTION OUTPUT ;
    USE SIGNAL ;
    PORT
      LAYER M5 ;
        RECT  5.328 43.116 5.352 43.2 ;
    END
  END response[123]
  PIN response[124]
    DIRECTION OUTPUT ;
    USE SIGNAL ;
    PORT
      LAYER M5 ;
        RECT  5.424 43.116 5.448 43.2 ;
    END
  END response[124]
  PIN response[125]
    DIRECTION OUTPUT ;
    USE SIGNAL ;
    PORT
      LAYER M5 ;
        RECT  5.52 43.116 5.544 43.2 ;
    END
  END response[125]
  PIN response[126]
    DIRECTION OUTPUT ;
    USE SIGNAL ;
    PORT
      LAYER M5 ;
        RECT  5.616 43.116 5.64 43.2 ;
    END
  END response[126]
  PIN response[127]
    DIRECTION OUTPUT ;
    USE SIGNAL ;
    PORT
      LAYER M5 ;
        RECT  5.712 43.116 5.736 43.2 ;
    END
  END response[127]
  PIN response[128]
    DIRECTION OUTPUT ;
    USE SIGNAL ;
    PORT
      LAYER M5 ;
        RECT  5.808 43.116 5.832 43.2 ;
    END
  END response[128]
  PIN response[129]
    DIRECTION OUTPUT ;
    USE SIGNAL ;
    PORT
      LAYER M5 ;
        RECT  5.904 43.116 5.928 43.2 ;
    END
  END response[129]
  PIN response[12]
    DIRECTION OUTPUT ;
    USE SIGNAL ;
    PORT
      LAYER M5 ;
        RECT  13.872 43.116 13.896 43.2 ;
    END
  END response[12]
  PIN response[130]
    DIRECTION OUTPUT ;
    USE SIGNAL ;
    PORT
      LAYER M5 ;
        RECT  6 43.116 6.024 43.2 ;
    END
  END response[130]
  PIN response[131]
    DIRECTION OUTPUT ;
    USE SIGNAL ;
    PORT
      LAYER M5 ;
        RECT  6.096 43.116 6.12 43.2 ;
    END
  END response[131]
  PIN response[132]
    DIRECTION OUTPUT ;
    USE SIGNAL ;
    PORT
      LAYER M5 ;
        RECT  6.192 43.116 6.216 43.2 ;
    END
  END response[132]
  PIN response[133]
    DIRECTION OUTPUT ;
    USE SIGNAL ;
    PORT
      LAYER M5 ;
        RECT  6.288 43.116 6.312 43.2 ;
    END
  END response[133]
  PIN response[134]
    DIRECTION OUTPUT ;
    USE SIGNAL ;
    PORT
      LAYER M5 ;
        RECT  6.384 43.116 6.408 43.2 ;
    END
  END response[134]
  PIN response[135]
    DIRECTION OUTPUT ;
    USE SIGNAL ;
    PORT
      LAYER M5 ;
        RECT  57.936 43.116 57.96 43.2 ;
    END
  END response[135]
  PIN response[136]
    DIRECTION OUTPUT ;
    USE SIGNAL ;
    PORT
      LAYER M5 ;
        RECT  58.032 43.116 58.056 43.2 ;
    END
  END response[136]
  PIN response[137]
    DIRECTION OUTPUT ;
    USE SIGNAL ;
    PORT
      LAYER M5 ;
        RECT  58.128 43.116 58.152 43.2 ;
    END
  END response[137]
  PIN response[138]
    DIRECTION OUTPUT ;
    USE SIGNAL ;
    PORT
      LAYER M5 ;
        RECT  58.224 43.116 58.248 43.2 ;
    END
  END response[138]
  PIN response[139]
    DIRECTION OUTPUT ;
    USE SIGNAL ;
    PORT
      LAYER M5 ;
        RECT  58.32 43.116 58.344 43.2 ;
    END
  END response[139]
  PIN response[13]
    DIRECTION OUTPUT ;
    USE SIGNAL ;
    PORT
      LAYER M5 ;
        RECT  13.968 43.116 13.992 43.2 ;
    END
  END response[13]
  PIN response[140]
    DIRECTION OUTPUT ;
    USE SIGNAL ;
    PORT
      LAYER M5 ;
        RECT  58.416 43.116 58.44 43.2 ;
    END
  END response[140]
  PIN response[141]
    DIRECTION OUTPUT ;
    USE SIGNAL ;
    PORT
      LAYER M5 ;
        RECT  58.512 43.116 58.536 43.2 ;
    END
  END response[141]
  PIN response[142]
    DIRECTION OUTPUT ;
    USE SIGNAL ;
    PORT
      LAYER M5 ;
        RECT  58.608 43.116 58.632 43.2 ;
    END
  END response[142]
  PIN response[143]
    DIRECTION OUTPUT ;
    USE SIGNAL ;
    PORT
      LAYER M5 ;
        RECT  58.704 43.116 58.728 43.2 ;
    END
  END response[143]
  PIN response[144]
    DIRECTION OUTPUT ;
    USE SIGNAL ;
    PORT
      LAYER M5 ;
        RECT  58.8 43.116 58.824 43.2 ;
    END
  END response[144]
  PIN response[145]
    DIRECTION OUTPUT ;
    USE SIGNAL ;
    PORT
      LAYER M5 ;
        RECT  58.896 43.116 58.92 43.2 ;
    END
  END response[145]
  PIN response[146]
    DIRECTION OUTPUT ;
    USE SIGNAL ;
    PORT
      LAYER M5 ;
        RECT  58.992 43.116 59.016 43.2 ;
    END
  END response[146]
  PIN response[147]
    DIRECTION OUTPUT ;
    USE SIGNAL ;
    PORT
      LAYER M5 ;
        RECT  59.088 43.116 59.112 43.2 ;
    END
  END response[147]
  PIN response[148]
    DIRECTION OUTPUT ;
    USE SIGNAL ;
    PORT
      LAYER M5 ;
        RECT  59.184 43.116 59.208 43.2 ;
    END
  END response[148]
  PIN response[149]
    DIRECTION OUTPUT ;
    USE SIGNAL ;
    PORT
      LAYER M5 ;
        RECT  59.28 43.116 59.304 43.2 ;
    END
  END response[149]
  PIN response[14]
    DIRECTION OUTPUT ;
    USE SIGNAL ;
    PORT
      LAYER M5 ;
        RECT  14.064 43.116 14.088 43.2 ;
    END
  END response[14]
  PIN response[150]
    DIRECTION OUTPUT ;
    USE SIGNAL ;
    PORT
      LAYER M5 ;
        RECT  59.376 43.116 59.4 43.2 ;
    END
  END response[150]
  PIN response[151]
    DIRECTION OUTPUT ;
    USE SIGNAL ;
    PORT
      LAYER M5 ;
        RECT  59.472 43.116 59.496 43.2 ;
    END
  END response[151]
  PIN response[152]
    DIRECTION OUTPUT ;
    USE SIGNAL ;
    PORT
      LAYER M5 ;
        RECT  59.568 43.116 59.592 43.2 ;
    END
  END response[152]
  PIN response[153]
    DIRECTION OUTPUT ;
    USE SIGNAL ;
    PORT
      LAYER M5 ;
        RECT  59.664 43.116 59.688 43.2 ;
    END
  END response[153]
  PIN response[154]
    DIRECTION OUTPUT ;
    USE SIGNAL ;
    PORT
      LAYER M5 ;
        RECT  59.76 43.116 59.784 43.2 ;
    END
  END response[154]
  PIN response[155]
    DIRECTION OUTPUT ;
    USE SIGNAL ;
    PORT
      LAYER M5 ;
        RECT  59.856 43.116 59.88 43.2 ;
    END
  END response[155]
  PIN response[156]
    DIRECTION OUTPUT ;
    USE SIGNAL ;
    PORT
      LAYER M5 ;
        RECT  59.952 43.116 59.976 43.2 ;
    END
  END response[156]
  PIN response[157]
    DIRECTION OUTPUT ;
    USE SIGNAL ;
    PORT
      LAYER M5 ;
        RECT  60.048 43.116 60.072 43.2 ;
    END
  END response[157]
  PIN response[158]
    DIRECTION OUTPUT ;
    USE SIGNAL ;
    PORT
      LAYER M5 ;
        RECT  60.144 43.116 60.168 43.2 ;
    END
  END response[158]
  PIN response[159]
    DIRECTION OUTPUT ;
    USE SIGNAL ;
    PORT
      LAYER M5 ;
        RECT  60.24 43.116 60.264 43.2 ;
    END
  END response[159]
  PIN response[15]
    DIRECTION OUTPUT ;
    USE SIGNAL ;
    PORT
      LAYER M5 ;
        RECT  14.16 43.116 14.184 43.2 ;
    END
  END response[15]
  PIN response[160]
    DIRECTION OUTPUT ;
    USE SIGNAL ;
    PORT
      LAYER M5 ;
        RECT  60.336 43.116 60.36 43.2 ;
    END
  END response[160]
  PIN response[161]
    DIRECTION OUTPUT ;
    USE SIGNAL ;
    PORT
      LAYER M5 ;
        RECT  60.432 43.116 60.456 43.2 ;
    END
  END response[161]
  PIN response[162]
    DIRECTION OUTPUT ;
    USE SIGNAL ;
    PORT
      LAYER M5 ;
        RECT  60.528 43.116 60.552 43.2 ;
    END
  END response[162]
  PIN response[163]
    DIRECTION OUTPUT ;
    USE SIGNAL ;
    PORT
      LAYER M5 ;
        RECT  60.624 43.116 60.648 43.2 ;
    END
  END response[163]
  PIN response[164]
    DIRECTION OUTPUT ;
    USE SIGNAL ;
    PORT
      LAYER M5 ;
        RECT  60.72 43.116 60.744 43.2 ;
    END
  END response[164]
  PIN response[165]
    DIRECTION OUTPUT ;
    USE SIGNAL ;
    PORT
      LAYER M5 ;
        RECT  60.816 43.116 60.84 43.2 ;
    END
  END response[165]
  PIN response[166]
    DIRECTION OUTPUT ;
    USE SIGNAL ;
    PORT
      LAYER M5 ;
        RECT  60.912 43.116 60.936 43.2 ;
    END
  END response[166]
  PIN response[167]
    DIRECTION OUTPUT ;
    USE SIGNAL ;
    PORT
      LAYER M5 ;
        RECT  51.792 43.116 51.816 43.2 ;
    END
  END response[167]
  PIN response[168]
    DIRECTION OUTPUT ;
    USE SIGNAL ;
    PORT
      LAYER M5 ;
        RECT  51.888 43.116 51.912 43.2 ;
    END
  END response[168]
  PIN response[169]
    DIRECTION OUTPUT ;
    USE SIGNAL ;
    PORT
      LAYER M5 ;
        RECT  51.984 43.116 52.008 43.2 ;
    END
  END response[169]
  PIN response[16]
    DIRECTION OUTPUT ;
    USE SIGNAL ;
    PORT
      LAYER M5 ;
        RECT  14.256 43.116 14.28 43.2 ;
    END
  END response[16]
  PIN response[170]
    DIRECTION OUTPUT ;
    USE SIGNAL ;
    PORT
      LAYER M5 ;
        RECT  52.08 43.116 52.104 43.2 ;
    END
  END response[170]
  PIN response[171]
    DIRECTION OUTPUT ;
    USE SIGNAL ;
    PORT
      LAYER M5 ;
        RECT  52.176 43.116 52.2 43.2 ;
    END
  END response[171]
  PIN response[172]
    DIRECTION OUTPUT ;
    USE SIGNAL ;
    PORT
      LAYER M5 ;
        RECT  52.272 43.116 52.296 43.2 ;
    END
  END response[172]
  PIN response[173]
    DIRECTION OUTPUT ;
    USE SIGNAL ;
    PORT
      LAYER M5 ;
        RECT  52.368 43.116 52.392 43.2 ;
    END
  END response[173]
  PIN response[174]
    DIRECTION OUTPUT ;
    USE SIGNAL ;
    PORT
      LAYER M5 ;
        RECT  52.464 43.116 52.488 43.2 ;
    END
  END response[174]
  PIN response[175]
    DIRECTION OUTPUT ;
    USE SIGNAL ;
    PORT
      LAYER M5 ;
        RECT  52.56 43.116 52.584 43.2 ;
    END
  END response[175]
  PIN response[176]
    DIRECTION OUTPUT ;
    USE SIGNAL ;
    PORT
      LAYER M5 ;
        RECT  52.656 43.116 52.68 43.2 ;
    END
  END response[176]
  PIN response[177]
    DIRECTION OUTPUT ;
    USE SIGNAL ;
    PORT
      LAYER M5 ;
        RECT  52.752 43.116 52.776 43.2 ;
    END
  END response[177]
  PIN response[178]
    DIRECTION OUTPUT ;
    USE SIGNAL ;
    PORT
      LAYER M5 ;
        RECT  52.848 43.116 52.872 43.2 ;
    END
  END response[178]
  PIN response[179]
    DIRECTION OUTPUT ;
    USE SIGNAL ;
    PORT
      LAYER M5 ;
        RECT  52.944 43.116 52.968 43.2 ;
    END
  END response[179]
  PIN response[17]
    DIRECTION OUTPUT ;
    USE SIGNAL ;
    PORT
      LAYER M5 ;
        RECT  14.352 43.116 14.376 43.2 ;
    END
  END response[17]
  PIN response[180]
    DIRECTION OUTPUT ;
    USE SIGNAL ;
    PORT
      LAYER M5 ;
        RECT  53.04 43.116 53.064 43.2 ;
    END
  END response[180]
  PIN response[181]
    DIRECTION OUTPUT ;
    USE SIGNAL ;
    PORT
      LAYER M5 ;
        RECT  53.136 43.116 53.16 43.2 ;
    END
  END response[181]
  PIN response[182]
    DIRECTION OUTPUT ;
    USE SIGNAL ;
    PORT
      LAYER M5 ;
        RECT  53.232 43.116 53.256 43.2 ;
    END
  END response[182]
  PIN response[183]
    DIRECTION OUTPUT ;
    USE SIGNAL ;
    PORT
      LAYER M5 ;
        RECT  53.328 43.116 53.352 43.2 ;
    END
  END response[183]
  PIN response[184]
    DIRECTION OUTPUT ;
    USE SIGNAL ;
    PORT
      LAYER M5 ;
        RECT  53.424 43.116 53.448 43.2 ;
    END
  END response[184]
  PIN response[185]
    DIRECTION OUTPUT ;
    USE SIGNAL ;
    PORT
      LAYER M5 ;
        RECT  53.52 43.116 53.544 43.2 ;
    END
  END response[185]
  PIN response[186]
    DIRECTION OUTPUT ;
    USE SIGNAL ;
    PORT
      LAYER M5 ;
        RECT  53.616 43.116 53.64 43.2 ;
    END
  END response[186]
  PIN response[187]
    DIRECTION OUTPUT ;
    USE SIGNAL ;
    PORT
      LAYER M5 ;
        RECT  53.712 43.116 53.736 43.2 ;
    END
  END response[187]
  PIN response[188]
    DIRECTION OUTPUT ;
    USE SIGNAL ;
    PORT
      LAYER M5 ;
        RECT  53.808 43.116 53.832 43.2 ;
    END
  END response[188]
  PIN response[189]
    DIRECTION OUTPUT ;
    USE SIGNAL ;
    PORT
      LAYER M5 ;
        RECT  53.904 43.116 53.928 43.2 ;
    END
  END response[189]
  PIN response[18]
    DIRECTION OUTPUT ;
    USE SIGNAL ;
    PORT
      LAYER M5 ;
        RECT  14.448 43.116 14.472 43.2 ;
    END
  END response[18]
  PIN response[190]
    DIRECTION OUTPUT ;
    USE SIGNAL ;
    PORT
      LAYER M5 ;
        RECT  54 43.116 54.024 43.2 ;
    END
  END response[190]
  PIN response[191]
    DIRECTION OUTPUT ;
    USE SIGNAL ;
    PORT
      LAYER M5 ;
        RECT  54.096 43.116 54.12 43.2 ;
    END
  END response[191]
  PIN response[192]
    DIRECTION OUTPUT ;
    USE SIGNAL ;
    PORT
      LAYER M5 ;
        RECT  54.192 43.116 54.216 43.2 ;
    END
  END response[192]
  PIN response[193]
    DIRECTION OUTPUT ;
    USE SIGNAL ;
    PORT
      LAYER M5 ;
        RECT  54.288 43.116 54.312 43.2 ;
    END
  END response[193]
  PIN response[194]
    DIRECTION OUTPUT ;
    USE SIGNAL ;
    PORT
      LAYER M5 ;
        RECT  54.384 43.116 54.408 43.2 ;
    END
  END response[194]
  PIN response[195]
    DIRECTION OUTPUT ;
    USE SIGNAL ;
    PORT
      LAYER M5 ;
        RECT  54.48 43.116 54.504 43.2 ;
    END
  END response[195]
  PIN response[196]
    DIRECTION OUTPUT ;
    USE SIGNAL ;
    PORT
      LAYER M5 ;
        RECT  54.576 43.116 54.6 43.2 ;
    END
  END response[196]
  PIN response[197]
    DIRECTION OUTPUT ;
    USE SIGNAL ;
    PORT
      LAYER M5 ;
        RECT  54.672 43.116 54.696 43.2 ;
    END
  END response[197]
  PIN response[198]
    DIRECTION OUTPUT ;
    USE SIGNAL ;
    PORT
      LAYER M5 ;
        RECT  54.768 43.116 54.792 43.2 ;
    END
  END response[198]
  PIN response[199]
    DIRECTION OUTPUT ;
    USE SIGNAL ;
    PORT
      LAYER M5 ;
        RECT  45.648 43.116 45.672 43.2 ;
    END
  END response[199]
  PIN response[19]
    DIRECTION OUTPUT ;
    USE SIGNAL ;
    PORT
      LAYER M5 ;
        RECT  14.544 43.116 14.568 43.2 ;
    END
  END response[19]
  PIN response[1]
    DIRECTION OUTPUT ;
    USE SIGNAL ;
    PORT
      LAYER M5 ;
        RECT  25.104 43.116 25.128 43.2 ;
    END
  END response[1]
  PIN response[200]
    DIRECTION OUTPUT ;
    USE SIGNAL ;
    PORT
      LAYER M5 ;
        RECT  45.744 43.116 45.768 43.2 ;
    END
  END response[200]
  PIN response[201]
    DIRECTION OUTPUT ;
    USE SIGNAL ;
    PORT
      LAYER M5 ;
        RECT  45.84 43.116 45.864 43.2 ;
    END
  END response[201]
  PIN response[202]
    DIRECTION OUTPUT ;
    USE SIGNAL ;
    PORT
      LAYER M5 ;
        RECT  45.936 43.116 45.96 43.2 ;
    END
  END response[202]
  PIN response[203]
    DIRECTION OUTPUT ;
    USE SIGNAL ;
    PORT
      LAYER M5 ;
        RECT  46.032 43.116 46.056 43.2 ;
    END
  END response[203]
  PIN response[204]
    DIRECTION OUTPUT ;
    USE SIGNAL ;
    PORT
      LAYER M5 ;
        RECT  46.128 43.116 46.152 43.2 ;
    END
  END response[204]
  PIN response[205]
    DIRECTION OUTPUT ;
    USE SIGNAL ;
    PORT
      LAYER M5 ;
        RECT  46.224 43.116 46.248 43.2 ;
    END
  END response[205]
  PIN response[206]
    DIRECTION OUTPUT ;
    USE SIGNAL ;
    PORT
      LAYER M5 ;
        RECT  46.32 43.116 46.344 43.2 ;
    END
  END response[206]
  PIN response[207]
    DIRECTION OUTPUT ;
    USE SIGNAL ;
    PORT
      LAYER M5 ;
        RECT  46.416 43.116 46.44 43.2 ;
    END
  END response[207]
  PIN response[208]
    DIRECTION OUTPUT ;
    USE SIGNAL ;
    PORT
      LAYER M5 ;
        RECT  46.512 43.116 46.536 43.2 ;
    END
  END response[208]
  PIN response[209]
    DIRECTION OUTPUT ;
    USE SIGNAL ;
    PORT
      LAYER M5 ;
        RECT  46.608 43.116 46.632 43.2 ;
    END
  END response[209]
  PIN response[20]
    DIRECTION OUTPUT ;
    USE SIGNAL ;
    PORT
      LAYER M5 ;
        RECT  14.64 43.116 14.664 43.2 ;
    END
  END response[20]
  PIN response[210]
    DIRECTION OUTPUT ;
    USE SIGNAL ;
    PORT
      LAYER M5 ;
        RECT  46.704 43.116 46.728 43.2 ;
    END
  END response[210]
  PIN response[211]
    DIRECTION OUTPUT ;
    USE SIGNAL ;
    PORT
      LAYER M5 ;
        RECT  46.8 43.116 46.824 43.2 ;
    END
  END response[211]
  PIN response[212]
    DIRECTION OUTPUT ;
    USE SIGNAL ;
    PORT
      LAYER M5 ;
        RECT  46.896 43.116 46.92 43.2 ;
    END
  END response[212]
  PIN response[213]
    DIRECTION OUTPUT ;
    USE SIGNAL ;
    PORT
      LAYER M5 ;
        RECT  46.992 43.116 47.016 43.2 ;
    END
  END response[213]
  PIN response[214]
    DIRECTION OUTPUT ;
    USE SIGNAL ;
    PORT
      LAYER M5 ;
        RECT  47.088 43.116 47.112 43.2 ;
    END
  END response[214]
  PIN response[215]
    DIRECTION OUTPUT ;
    USE SIGNAL ;
    PORT
      LAYER M5 ;
        RECT  47.184 43.116 47.208 43.2 ;
    END
  END response[215]
  PIN response[216]
    DIRECTION OUTPUT ;
    USE SIGNAL ;
    PORT
      LAYER M5 ;
        RECT  47.28 43.116 47.304 43.2 ;
    END
  END response[216]
  PIN response[217]
    DIRECTION OUTPUT ;
    USE SIGNAL ;
    PORT
      LAYER M5 ;
        RECT  47.376 43.116 47.4 43.2 ;
    END
  END response[217]
  PIN response[218]
    DIRECTION OUTPUT ;
    USE SIGNAL ;
    PORT
      LAYER M5 ;
        RECT  47.472 43.116 47.496 43.2 ;
    END
  END response[218]
  PIN response[219]
    DIRECTION OUTPUT ;
    USE SIGNAL ;
    PORT
      LAYER M5 ;
        RECT  47.568 43.116 47.592 43.2 ;
    END
  END response[219]
  PIN response[21]
    DIRECTION OUTPUT ;
    USE SIGNAL ;
    PORT
      LAYER M5 ;
        RECT  14.736 43.116 14.76 43.2 ;
    END
  END response[21]
  PIN response[220]
    DIRECTION OUTPUT ;
    USE SIGNAL ;
    PORT
      LAYER M5 ;
        RECT  47.664 43.116 47.688 43.2 ;
    END
  END response[220]
  PIN response[221]
    DIRECTION OUTPUT ;
    USE SIGNAL ;
    PORT
      LAYER M5 ;
        RECT  47.76 43.116 47.784 43.2 ;
    END
  END response[221]
  PIN response[222]
    DIRECTION OUTPUT ;
    USE SIGNAL ;
    PORT
      LAYER M5 ;
        RECT  47.856 43.116 47.88 43.2 ;
    END
  END response[222]
  PIN response[223]
    DIRECTION OUTPUT ;
    USE SIGNAL ;
    PORT
      LAYER M5 ;
        RECT  47.952 43.116 47.976 43.2 ;
    END
  END response[223]
  PIN response[224]
    DIRECTION OUTPUT ;
    USE SIGNAL ;
    PORT
      LAYER M5 ;
        RECT  48.048 43.116 48.072 43.2 ;
    END
  END response[224]
  PIN response[225]
    DIRECTION OUTPUT ;
    USE SIGNAL ;
    PORT
      LAYER M5 ;
        RECT  48.144 43.116 48.168 43.2 ;
    END
  END response[225]
  PIN response[226]
    DIRECTION OUTPUT ;
    USE SIGNAL ;
    PORT
      LAYER M5 ;
        RECT  48.24 43.116 48.264 43.2 ;
    END
  END response[226]
  PIN response[227]
    DIRECTION OUTPUT ;
    USE SIGNAL ;
    PORT
      LAYER M5 ;
        RECT  48.336 43.116 48.36 43.2 ;
    END
  END response[227]
  PIN response[228]
    DIRECTION OUTPUT ;
    USE SIGNAL ;
    PORT
      LAYER M5 ;
        RECT  48.432 43.116 48.456 43.2 ;
    END
  END response[228]
  PIN response[229]
    DIRECTION OUTPUT ;
    USE SIGNAL ;
    PORT
      LAYER M5 ;
        RECT  48.528 43.116 48.552 43.2 ;
    END
  END response[229]
  PIN response[22]
    DIRECTION OUTPUT ;
    USE SIGNAL ;
    PORT
      LAYER M5 ;
        RECT  14.832 43.116 14.856 43.2 ;
    END
  END response[22]
  PIN response[230]
    DIRECTION OUTPUT ;
    USE SIGNAL ;
    PORT
      LAYER M5 ;
        RECT  48.624 43.116 48.648 43.2 ;
    END
  END response[230]
  PIN response[231]
    DIRECTION OUTPUT ;
    USE SIGNAL ;
    PORT
      LAYER M5 ;
        RECT  0.72 43.116 0.744 43.2 ;
    END
  END response[231]
  PIN response[232]
    DIRECTION OUTPUT ;
    USE SIGNAL ;
    PORT
      LAYER M5 ;
        RECT  0.816 43.116 0.84 43.2 ;
    END
  END response[232]
  PIN response[233]
    DIRECTION OUTPUT ;
    USE SIGNAL ;
    PORT
      LAYER M5 ;
        RECT  0.912 43.116 0.936 43.2 ;
    END
  END response[233]
  PIN response[234]
    DIRECTION OUTPUT ;
    USE SIGNAL ;
    PORT
      LAYER M5 ;
        RECT  1.008 43.116 1.032 43.2 ;
    END
  END response[234]
  PIN response[235]
    DIRECTION OUTPUT ;
    USE SIGNAL ;
    PORT
      LAYER M5 ;
        RECT  1.104 43.116 1.128 43.2 ;
    END
  END response[235]
  PIN response[236]
    DIRECTION OUTPUT ;
    USE SIGNAL ;
    PORT
      LAYER M5 ;
        RECT  1.2 43.116 1.224 43.2 ;
    END
  END response[236]
  PIN response[237]
    DIRECTION OUTPUT ;
    USE SIGNAL ;
    PORT
      LAYER M5 ;
        RECT  1.296 43.116 1.32 43.2 ;
    END
  END response[237]
  PIN response[238]
    DIRECTION OUTPUT ;
    USE SIGNAL ;
    PORT
      LAYER M5 ;
        RECT  1.392 43.116 1.416 43.2 ;
    END
  END response[238]
  PIN response[239]
    DIRECTION OUTPUT ;
    USE SIGNAL ;
    PORT
      LAYER M5 ;
        RECT  1.488 43.116 1.512 43.2 ;
    END
  END response[239]
  PIN response[23]
    DIRECTION OUTPUT ;
    USE SIGNAL ;
    PORT
      LAYER M5 ;
        RECT  14.928 43.116 14.952 43.2 ;
    END
  END response[23]
  PIN response[240]
    DIRECTION OUTPUT ;
    USE SIGNAL ;
    PORT
      LAYER M5 ;
        RECT  1.584 43.116 1.608 43.2 ;
    END
  END response[240]
  PIN response[241]
    DIRECTION OUTPUT ;
    USE SIGNAL ;
    PORT
      LAYER M5 ;
        RECT  1.68 43.116 1.704 43.2 ;
    END
  END response[241]
  PIN response[242]
    DIRECTION OUTPUT ;
    USE SIGNAL ;
    PORT
      LAYER M5 ;
        RECT  1.776 43.116 1.8 43.2 ;
    END
  END response[242]
  PIN response[243]
    DIRECTION OUTPUT ;
    USE SIGNAL ;
    PORT
      LAYER M5 ;
        RECT  1.872 43.116 1.896 43.2 ;
    END
  END response[243]
  PIN response[244]
    DIRECTION OUTPUT ;
    USE SIGNAL ;
    PORT
      LAYER M5 ;
        RECT  1.968 43.116 1.992 43.2 ;
    END
  END response[244]
  PIN response[245]
    DIRECTION OUTPUT ;
    USE SIGNAL ;
    PORT
      LAYER M5 ;
        RECT  2.064 43.116 2.088 43.2 ;
    END
  END response[245]
  PIN response[246]
    DIRECTION OUTPUT ;
    USE SIGNAL ;
    PORT
      LAYER M5 ;
        RECT  2.16 43.116 2.184 43.2 ;
    END
  END response[246]
  PIN response[247]
    DIRECTION OUTPUT ;
    USE SIGNAL ;
    PORT
      LAYER M5 ;
        RECT  2.256 43.116 2.28 43.2 ;
    END
  END response[247]
  PIN response[248]
    DIRECTION OUTPUT ;
    USE SIGNAL ;
    PORT
      LAYER M5 ;
        RECT  2.352 43.116 2.376 43.2 ;
    END
  END response[248]
  PIN response[249]
    DIRECTION OUTPUT ;
    USE SIGNAL ;
    PORT
      LAYER M5 ;
        RECT  2.448 43.116 2.472 43.2 ;
    END
  END response[249]
  PIN response[24]
    DIRECTION OUTPUT ;
    USE SIGNAL ;
    PORT
      LAYER M5 ;
        RECT  15.024 43.116 15.048 43.2 ;
    END
  END response[24]
  PIN response[250]
    DIRECTION OUTPUT ;
    USE SIGNAL ;
    PORT
      LAYER M5 ;
        RECT  2.544 43.116 2.568 43.2 ;
    END
  END response[250]
  PIN response[251]
    DIRECTION OUTPUT ;
    USE SIGNAL ;
    PORT
      LAYER M5 ;
        RECT  2.64 43.116 2.664 43.2 ;
    END
  END response[251]
  PIN response[252]
    DIRECTION OUTPUT ;
    USE SIGNAL ;
    PORT
      LAYER M5 ;
        RECT  2.736 43.116 2.76 43.2 ;
    END
  END response[252]
  PIN response[253]
    DIRECTION OUTPUT ;
    USE SIGNAL ;
    PORT
      LAYER M5 ;
        RECT  2.832 43.116 2.856 43.2 ;
    END
  END response[253]
  PIN response[254]
    DIRECTION OUTPUT ;
    USE SIGNAL ;
    PORT
      LAYER M5 ;
        RECT  2.928 43.116 2.952 43.2 ;
    END
  END response[254]
  PIN response[255]
    DIRECTION OUTPUT ;
    USE SIGNAL ;
    PORT
      LAYER M5 ;
        RECT  3.024 43.116 3.048 43.2 ;
    END
  END response[255]
  PIN response[256]
    DIRECTION OUTPUT ;
    USE SIGNAL ;
    PORT
      LAYER M5 ;
        RECT  3.12 43.116 3.144 43.2 ;
    END
  END response[256]
  PIN response[257]
    DIRECTION OUTPUT ;
    USE SIGNAL ;
    PORT
      LAYER M5 ;
        RECT  3.216 43.116 3.24 43.2 ;
    END
  END response[257]
  PIN response[25]
    DIRECTION OUTPUT ;
    USE SIGNAL ;
    PORT
      LAYER M5 ;
        RECT  15.12 43.116 15.144 43.2 ;
    END
  END response[25]
  PIN response[26]
    DIRECTION OUTPUT ;
    USE SIGNAL ;
    PORT
      LAYER M5 ;
        RECT  15.216 43.116 15.24 43.2 ;
    END
  END response[26]
  PIN response[27]
    DIRECTION OUTPUT ;
    USE SIGNAL ;
    PORT
      LAYER M5 ;
        RECT  15.312 43.116 15.336 43.2 ;
    END
  END response[27]
  PIN response[28]
    DIRECTION OUTPUT ;
    USE SIGNAL ;
    PORT
      LAYER M5 ;
        RECT  15.408 43.116 15.432 43.2 ;
    END
  END response[28]
  PIN response[29]
    DIRECTION OUTPUT ;
    USE SIGNAL ;
    PORT
      LAYER M5 ;
        RECT  15.504 43.116 15.528 43.2 ;
    END
  END response[29]
  PIN response[2]
    DIRECTION OUTPUT ;
    USE SIGNAL ;
    PORT
      LAYER M5 ;
        RECT  25.2 43.116 25.224 43.2 ;
    END
  END response[2]
  PIN response[30]
    DIRECTION OUTPUT ;
    USE SIGNAL ;
    PORT
      LAYER M5 ;
        RECT  15.6 43.116 15.624 43.2 ;
    END
  END response[30]
  PIN response[31]
    DIRECTION OUTPUT ;
    USE SIGNAL ;
    PORT
      LAYER M5 ;
        RECT  15.696 43.116 15.72 43.2 ;
    END
  END response[31]
  PIN response[32]
    DIRECTION OUTPUT ;
    USE SIGNAL ;
    PORT
      LAYER M5 ;
        RECT  15.792 43.116 15.816 43.2 ;
    END
  END response[32]
  PIN response[33]
    DIRECTION OUTPUT ;
    USE SIGNAL ;
    PORT
      LAYER M5 ;
        RECT  15.888 43.116 15.912 43.2 ;
    END
  END response[33]
  PIN response[34]
    DIRECTION OUTPUT ;
    USE SIGNAL ;
    PORT
      LAYER M5 ;
        RECT  15.984 43.116 16.008 43.2 ;
    END
  END response[34]
  PIN response[35]
    DIRECTION OUTPUT ;
    USE SIGNAL ;
    PORT
      LAYER M5 ;
        RECT  16.08 43.116 16.104 43.2 ;
    END
  END response[35]
  PIN response[36]
    DIRECTION OUTPUT ;
    USE SIGNAL ;
    PORT
      LAYER M5 ;
        RECT  16.176 43.116 16.2 43.2 ;
    END
  END response[36]
  PIN response[37]
    DIRECTION OUTPUT ;
    USE SIGNAL ;
    PORT
      LAYER M5 ;
        RECT  16.272 43.116 16.296 43.2 ;
    END
  END response[37]
  PIN response[38]
    DIRECTION OUTPUT ;
    USE SIGNAL ;
    PORT
      LAYER M5 ;
        RECT  16.368 43.116 16.392 43.2 ;
    END
  END response[38]
  PIN response[39]
    DIRECTION OUTPUT ;
    USE SIGNAL ;
    PORT
      LAYER M5 ;
        RECT  7.248 43.116 7.272 43.2 ;
    END
  END response[39]
  PIN response[3]
    DIRECTION OUTPUT ;
    USE SIGNAL ;
    PORT
      LAYER M5 ;
        RECT  25.296 43.116 25.32 43.2 ;
    END
  END response[3]
  PIN response[40]
    DIRECTION OUTPUT ;
    USE SIGNAL ;
    PORT
      LAYER M5 ;
        RECT  7.344 43.116 7.368 43.2 ;
    END
  END response[40]
  PIN response[41]
    DIRECTION OUTPUT ;
    USE SIGNAL ;
    PORT
      LAYER M5 ;
        RECT  7.44 43.116 7.464 43.2 ;
    END
  END response[41]
  PIN response[42]
    DIRECTION OUTPUT ;
    USE SIGNAL ;
    PORT
      LAYER M5 ;
        RECT  7.536 43.116 7.56 43.2 ;
    END
  END response[42]
  PIN response[43]
    DIRECTION OUTPUT ;
    USE SIGNAL ;
    PORT
      LAYER M5 ;
        RECT  7.632 43.116 7.656 43.2 ;
    END
  END response[43]
  PIN response[44]
    DIRECTION OUTPUT ;
    USE SIGNAL ;
    PORT
      LAYER M5 ;
        RECT  7.728 43.116 7.752 43.2 ;
    END
  END response[44]
  PIN response[45]
    DIRECTION OUTPUT ;
    USE SIGNAL ;
    PORT
      LAYER M5 ;
        RECT  7.824 43.116 7.848 43.2 ;
    END
  END response[45]
  PIN response[46]
    DIRECTION OUTPUT ;
    USE SIGNAL ;
    PORT
      LAYER M5 ;
        RECT  7.92 43.116 7.944 43.2 ;
    END
  END response[46]
  PIN response[47]
    DIRECTION OUTPUT ;
    USE SIGNAL ;
    PORT
      LAYER M5 ;
        RECT  8.016 43.116 8.04 43.2 ;
    END
  END response[47]
  PIN response[48]
    DIRECTION OUTPUT ;
    USE SIGNAL ;
    PORT
      LAYER M5 ;
        RECT  8.112 43.116 8.136 43.2 ;
    END
  END response[48]
  PIN response[49]
    DIRECTION OUTPUT ;
    USE SIGNAL ;
    PORT
      LAYER M5 ;
        RECT  8.208 43.116 8.232 43.2 ;
    END
  END response[49]
  PIN response[4]
    DIRECTION OUTPUT ;
    USE SIGNAL ;
    PORT
      LAYER M5 ;
        RECT  25.392 43.116 25.416 43.2 ;
    END
  END response[4]
  PIN response[50]
    DIRECTION OUTPUT ;
    USE SIGNAL ;
    PORT
      LAYER M5 ;
        RECT  8.304 43.116 8.328 43.2 ;
    END
  END response[50]
  PIN response[51]
    DIRECTION OUTPUT ;
    USE SIGNAL ;
    PORT
      LAYER M5 ;
        RECT  8.4 43.116 8.424 43.2 ;
    END
  END response[51]
  PIN response[52]
    DIRECTION OUTPUT ;
    USE SIGNAL ;
    PORT
      LAYER M5 ;
        RECT  8.496 43.116 8.52 43.2 ;
    END
  END response[52]
  PIN response[53]
    DIRECTION OUTPUT ;
    USE SIGNAL ;
    PORT
      LAYER M5 ;
        RECT  8.592 43.116 8.616 43.2 ;
    END
  END response[53]
  PIN response[54]
    DIRECTION OUTPUT ;
    USE SIGNAL ;
    PORT
      LAYER M5 ;
        RECT  8.688 43.116 8.712 43.2 ;
    END
  END response[54]
  PIN response[55]
    DIRECTION OUTPUT ;
    USE SIGNAL ;
    PORT
      LAYER M5 ;
        RECT  8.784 43.116 8.808 43.2 ;
    END
  END response[55]
  PIN response[56]
    DIRECTION OUTPUT ;
    USE SIGNAL ;
    PORT
      LAYER M5 ;
        RECT  8.88 43.116 8.904 43.2 ;
    END
  END response[56]
  PIN response[57]
    DIRECTION OUTPUT ;
    USE SIGNAL ;
    PORT
      LAYER M5 ;
        RECT  8.976 43.116 9 43.2 ;
    END
  END response[57]
  PIN response[58]
    DIRECTION OUTPUT ;
    USE SIGNAL ;
    PORT
      LAYER M5 ;
        RECT  9.072 43.116 9.096 43.2 ;
    END
  END response[58]
  PIN response[59]
    DIRECTION OUTPUT ;
    USE SIGNAL ;
    PORT
      LAYER M5 ;
        RECT  9.168 43.116 9.192 43.2 ;
    END
  END response[59]
  PIN response[5]
    DIRECTION OUTPUT ;
    USE SIGNAL ;
    PORT
      LAYER M5 ;
        RECT  25.488 43.116 25.512 43.2 ;
    END
  END response[5]
  PIN response[60]
    DIRECTION OUTPUT ;
    USE SIGNAL ;
    PORT
      LAYER M5 ;
        RECT  9.264 43.116 9.288 43.2 ;
    END
  END response[60]
  PIN response[61]
    DIRECTION OUTPUT ;
    USE SIGNAL ;
    PORT
      LAYER M5 ;
        RECT  9.36 43.116 9.384 43.2 ;
    END
  END response[61]
  PIN response[62]
    DIRECTION OUTPUT ;
    USE SIGNAL ;
    PORT
      LAYER M5 ;
        RECT  9.456 43.116 9.48 43.2 ;
    END
  END response[62]
  PIN response[63]
    DIRECTION OUTPUT ;
    USE SIGNAL ;
    PORT
      LAYER M5 ;
        RECT  9.552 43.116 9.576 43.2 ;
    END
  END response[63]
  PIN response[64]
    DIRECTION OUTPUT ;
    USE SIGNAL ;
    PORT
      LAYER M5 ;
        RECT  9.648 43.116 9.672 43.2 ;
    END
  END response[64]
  PIN response[65]
    DIRECTION OUTPUT ;
    USE SIGNAL ;
    PORT
      LAYER M5 ;
        RECT  9.744 43.116 9.768 43.2 ;
    END
  END response[65]
  PIN response[66]
    DIRECTION OUTPUT ;
    USE SIGNAL ;
    PORT
      LAYER M5 ;
        RECT  9.84 43.116 9.864 43.2 ;
    END
  END response[66]
  PIN response[67]
    DIRECTION OUTPUT ;
    USE SIGNAL ;
    PORT
      LAYER M5 ;
        RECT  9.936 43.116 9.96 43.2 ;
    END
  END response[67]
  PIN response[68]
    DIRECTION OUTPUT ;
    USE SIGNAL ;
    PORT
      LAYER M5 ;
        RECT  10.032 43.116 10.056 43.2 ;
    END
  END response[68]
  PIN response[69]
    DIRECTION OUTPUT ;
    USE SIGNAL ;
    PORT
      LAYER M5 ;
        RECT  10.128 43.116 10.152 43.2 ;
    END
  END response[69]
  PIN response[6]
    DIRECTION OUTPUT ;
    USE SIGNAL ;
    PORT
      LAYER M5 ;
        RECT  25.584 43.116 25.608 43.2 ;
    END
  END response[6]
  PIN response[70]
    DIRECTION OUTPUT ;
    USE SIGNAL ;
    PORT
      LAYER M5 ;
        RECT  10.224 43.116 10.248 43.2 ;
    END
  END response[70]
  PIN response[71]
    DIRECTION OUTPUT ;
    USE SIGNAL ;
    PORT
      LAYER M5 ;
        RECT  16.464 43.116 16.488 43.2 ;
    END
  END response[71]
  PIN response[72]
    DIRECTION OUTPUT ;
    USE SIGNAL ;
    PORT
      LAYER M5 ;
        RECT  16.56 43.116 16.584 43.2 ;
    END
  END response[72]
  PIN response[73]
    DIRECTION OUTPUT ;
    USE SIGNAL ;
    PORT
      LAYER M5 ;
        RECT  16.656 43.116 16.68 43.2 ;
    END
  END response[73]
  PIN response[74]
    DIRECTION OUTPUT ;
    USE SIGNAL ;
    PORT
      LAYER M5 ;
        RECT  16.752 43.116 16.776 43.2 ;
    END
  END response[74]
  PIN response[75]
    DIRECTION OUTPUT ;
    USE SIGNAL ;
    PORT
      LAYER M5 ;
        RECT  16.848 43.116 16.872 43.2 ;
    END
  END response[75]
  PIN response[76]
    DIRECTION OUTPUT ;
    USE SIGNAL ;
    PORT
      LAYER M5 ;
        RECT  16.944 43.116 16.968 43.2 ;
    END
  END response[76]
  PIN response[77]
    DIRECTION OUTPUT ;
    USE SIGNAL ;
    PORT
      LAYER M5 ;
        RECT  17.04 43.116 17.064 43.2 ;
    END
  END response[77]
  PIN response[78]
    DIRECTION OUTPUT ;
    USE SIGNAL ;
    PORT
      LAYER M5 ;
        RECT  17.136 43.116 17.16 43.2 ;
    END
  END response[78]
  PIN response[79]
    DIRECTION OUTPUT ;
    USE SIGNAL ;
    PORT
      LAYER M5 ;
        RECT  17.232 43.116 17.256 43.2 ;
    END
  END response[79]
  PIN response[7]
    DIRECTION OUTPUT ;
    USE SIGNAL ;
    PORT
      LAYER M5 ;
        RECT  13.392 43.116 13.416 43.2 ;
    END
  END response[7]
  PIN response[80]
    DIRECTION OUTPUT ;
    USE SIGNAL ;
    PORT
      LAYER M5 ;
        RECT  17.328 43.116 17.352 43.2 ;
    END
  END response[80]
  PIN response[81]
    DIRECTION OUTPUT ;
    USE SIGNAL ;
    PORT
      LAYER M5 ;
        RECT  17.424 43.116 17.448 43.2 ;
    END
  END response[81]
  PIN response[82]
    DIRECTION OUTPUT ;
    USE SIGNAL ;
    PORT
      LAYER M5 ;
        RECT  17.52 43.116 17.544 43.2 ;
    END
  END response[82]
  PIN response[83]
    DIRECTION OUTPUT ;
    USE SIGNAL ;
    PORT
      LAYER M5 ;
        RECT  17.616 43.116 17.64 43.2 ;
    END
  END response[83]
  PIN response[84]
    DIRECTION OUTPUT ;
    USE SIGNAL ;
    PORT
      LAYER M5 ;
        RECT  17.712 43.116 17.736 43.2 ;
    END
  END response[84]
  PIN response[85]
    DIRECTION OUTPUT ;
    USE SIGNAL ;
    PORT
      LAYER M5 ;
        RECT  17.808 43.116 17.832 43.2 ;
    END
  END response[85]
  PIN response[86]
    DIRECTION OUTPUT ;
    USE SIGNAL ;
    PORT
      LAYER M5 ;
        RECT  17.904 43.116 17.928 43.2 ;
    END
  END response[86]
  PIN response[87]
    DIRECTION OUTPUT ;
    USE SIGNAL ;
    PORT
      LAYER M5 ;
        RECT  18 43.116 18.024 43.2 ;
    END
  END response[87]
  PIN response[88]
    DIRECTION OUTPUT ;
    USE SIGNAL ;
    PORT
      LAYER M5 ;
        RECT  18.096 43.116 18.12 43.2 ;
    END
  END response[88]
  PIN response[89]
    DIRECTION OUTPUT ;
    USE SIGNAL ;
    PORT
      LAYER M5 ;
        RECT  18.192 43.116 18.216 43.2 ;
    END
  END response[89]
  PIN response[8]
    DIRECTION OUTPUT ;
    USE SIGNAL ;
    PORT
      LAYER M5 ;
        RECT  13.488 43.116 13.512 43.2 ;
    END
  END response[8]
  PIN response[90]
    DIRECTION OUTPUT ;
    USE SIGNAL ;
    PORT
      LAYER M5 ;
        RECT  18.288 43.116 18.312 43.2 ;
    END
  END response[90]
  PIN response[91]
    DIRECTION OUTPUT ;
    USE SIGNAL ;
    PORT
      LAYER M5 ;
        RECT  18.384 43.116 18.408 43.2 ;
    END
  END response[91]
  PIN response[92]
    DIRECTION OUTPUT ;
    USE SIGNAL ;
    PORT
      LAYER M5 ;
        RECT  18.48 43.116 18.504 43.2 ;
    END
  END response[92]
  PIN response[93]
    DIRECTION OUTPUT ;
    USE SIGNAL ;
    PORT
      LAYER M5 ;
        RECT  18.576 43.116 18.6 43.2 ;
    END
  END response[93]
  PIN response[94]
    DIRECTION OUTPUT ;
    USE SIGNAL ;
    PORT
      LAYER M5 ;
        RECT  18.672 43.116 18.696 43.2 ;
    END
  END response[94]
  PIN response[95]
    DIRECTION OUTPUT ;
    USE SIGNAL ;
    PORT
      LAYER M5 ;
        RECT  18.768 43.116 18.792 43.2 ;
    END
  END response[95]
  PIN response[96]
    DIRECTION OUTPUT ;
    USE SIGNAL ;
    PORT
      LAYER M5 ;
        RECT  18.864 43.116 18.888 43.2 ;
    END
  END response[96]
  PIN response[97]
    DIRECTION OUTPUT ;
    USE SIGNAL ;
    PORT
      LAYER M5 ;
        RECT  18.96 43.116 18.984 43.2 ;
    END
  END response[97]
  PIN response[98]
    DIRECTION OUTPUT ;
    USE SIGNAL ;
    PORT
      LAYER M5 ;
        RECT  19.056 43.116 19.08 43.2 ;
    END
  END response[98]
  PIN response[99]
    DIRECTION OUTPUT ;
    USE SIGNAL ;
    PORT
      LAYER M5 ;
        RECT  19.152 43.116 19.176 43.2 ;
    END
  END response[99]
  PIN response[9]
    DIRECTION OUTPUT ;
    USE SIGNAL ;
    PORT
      LAYER M5 ;
        RECT  13.584 43.116 13.608 43.2 ;
    END
  END response[9]
  PIN rst_n
    DIRECTION INPUT ;
    USE SIGNAL ;
    PORT
      LAYER M5 ;
        RECT  3.312 43.116 3.336 43.2 ;
    END
  END rst_n
  PIN VDD
    DIRECTION INOUT ;
    USE POWER ;
    PORT
      LAYER M5 ;
        RECT  61.992 2.151 62.112 41.049 ;
        RECT  56.592 2.151 56.712 41.049 ;
        RECT  51.192 2.151 51.312 41.049 ;
        RECT  45.792 2.151 45.912 41.049 ;
        RECT  40.392 2.151 40.512 41.049 ;
        RECT  34.992 2.151 35.112 41.049 ;
        RECT  29.592 2.151 29.712 41.049 ;
        RECT  24.192 2.151 24.312 41.049 ;
        RECT  18.792 2.151 18.912 41.049 ;
        RECT  13.392 2.151 13.512 41.049 ;
        RECT  7.992 2.151 8.112 41.049 ;
        RECT  2.592 2.151 2.712 41.049 ;
    END
  END VDD
  PIN VSS
    DIRECTION INOUT ;
    USE GROUND ;
    PORT
      LAYER M5 ;
        RECT  61.8 2.137 61.92 41.063 ;
        RECT  56.4 2.137 56.52 41.063 ;
        RECT  51 2.137 51.12 41.063 ;
        RECT  45.6 2.137 45.72 41.063 ;
        RECT  40.2 2.137 40.32 41.063 ;
        RECT  34.8 2.137 34.92 41.063 ;
        RECT  29.4 2.137 29.52 41.063 ;
        RECT  24 2.137 24.12 41.063 ;
        RECT  18.6 2.137 18.72 41.063 ;
        RECT  13.2 2.137 13.32 41.063 ;
        RECT  7.8 2.137 7.92 41.063 ;
        RECT  2.4 2.137 2.52 41.063 ;
    END
  END VSS
  # OT_OBS_CLOSED layer=M5 d_um=1.536 added=209
  OBS
    LAYER RVTN ;
     RECT  2.16 2.16 62.64 2.295 ;
     RECT  2.16 2.565 62.64 2.835 ;
     RECT  2.16 3.105 62.64 3.375 ;
     RECT  2.16 3.645 62.64 3.915 ;
     RECT  2.16 4.185 62.64 4.455 ;
     RECT  2.16 4.725 62.64 4.995 ;
     RECT  2.16 5.265 62.64 5.535 ;
     RECT  2.16 5.805 62.64 6.075 ;
     RECT  2.16 6.345 62.64 6.615 ;
     RECT  2.16 6.885 62.64 7.155 ;
     RECT  2.16 7.425 62.64 7.695 ;
     RECT  2.16 7.965 62.64 8.235 ;
     RECT  2.16 8.505 62.64 8.775 ;
     RECT  2.16 9.045 62.64 9.315 ;
     RECT  2.16 9.585 62.64 9.855 ;
     RECT  2.16 10.125 62.64 10.395 ;
     RECT  2.16 10.665 62.64 10.935 ;
     RECT  2.16 11.205 62.64 11.475 ;
     RECT  2.16 11.745 62.64 12.015 ;
     RECT  2.16 12.285 62.64 12.555 ;
     RECT  2.16 12.825 62.64 13.095 ;
     RECT  2.16 13.365 62.64 13.635 ;
     RECT  2.16 13.905 62.64 14.175 ;
     RECT  2.16 14.445 62.64 14.715 ;
     RECT  2.16 14.985 62.64 15.255 ;
     RECT  2.16 15.525 62.64 15.795 ;
     RECT  2.16 16.065 62.64 16.335 ;
     RECT  2.16 16.605 62.64 16.875 ;
     RECT  2.16 17.145 62.64 17.415 ;
     RECT  2.16 17.685 62.64 17.955 ;
     RECT  2.16 18.225 62.64 18.495 ;
     RECT  2.16 18.765 62.64 19.035 ;
     RECT  2.16 19.305 62.64 19.575 ;
     RECT  2.16 19.845 62.64 20.115 ;
     RECT  2.16 20.385 62.64 20.655 ;
     RECT  2.16 20.925 62.64 21.195 ;
     RECT  2.16 21.465 62.64 21.735 ;
     RECT  2.16 22.005 62.64 22.275 ;
     RECT  2.16 22.545 62.64 22.815 ;
     RECT  2.16 23.085 62.64 23.355 ;
     RECT  2.16 23.625 62.64 23.895 ;
     RECT  2.16 24.165 62.64 24.435 ;
     RECT  2.16 24.705 62.64 24.975 ;
     RECT  2.16 25.245 62.64 25.515 ;
     RECT  2.16 25.785 62.64 26.055 ;
     RECT  2.16 26.325 62.64 26.595 ;
     RECT  2.16 26.865 62.64 27.135 ;
     RECT  2.16 27.405 62.64 27.675 ;
     RECT  2.16 27.945 62.64 28.215 ;
     RECT  2.16 28.485 62.64 28.755 ;
     RECT  2.16 29.025 62.64 29.295 ;
     RECT  2.16 29.565 62.64 29.835 ;
     RECT  2.16 30.105 62.64 30.375 ;
     RECT  2.16 30.645 62.64 30.915 ;
     RECT  2.16 31.185 62.64 31.455 ;
     RECT  2.16 31.725 62.64 31.995 ;
     RECT  2.16 32.265 62.64 32.535 ;
     RECT  2.16 32.805 62.64 33.075 ;
     RECT  2.16 33.345 62.64 33.615 ;
     RECT  2.16 33.885 62.64 34.155 ;
     RECT  2.16 34.425 62.64 34.695 ;
     RECT  2.16 34.965 62.64 35.235 ;
     RECT  2.16 35.505 62.64 35.775 ;
     RECT  2.16 36.045 62.64 36.315 ;
     RECT  2.16 36.585 62.64 36.855 ;
     RECT  2.16 37.125 62.64 37.395 ;
     RECT  2.16 37.665 62.64 37.935 ;
     RECT  2.16 38.205 62.64 38.475 ;
     RECT  2.16 38.745 62.64 39.015 ;
     RECT  2.16 39.285 62.64 39.555 ;
     RECT  2.16 39.825 62.64 40.095 ;
     RECT  2.16 40.365 62.64 40.635 ;
     RECT  2.16 40.905 62.64 41.04 ;
    LAYER RVTP ;
     RECT  2.16 2.295 62.64 2.565 ;
     RECT  2.16 2.835 62.64 3.105 ;
     RECT  2.16 3.375 62.64 3.645 ;
     RECT  2.16 3.915 62.64 4.185 ;
     RECT  2.16 4.455 62.64 4.725 ;
     RECT  2.16 4.995 62.64 5.265 ;
     RECT  2.16 5.535 62.64 5.805 ;
     RECT  2.16 6.075 62.64 6.345 ;
     RECT  2.16 6.615 62.64 6.885 ;
     RECT  2.16 7.155 62.64 7.425 ;
     RECT  2.16 7.695 62.64 7.965 ;
     RECT  2.16 8.235 62.64 8.505 ;
     RECT  2.16 8.775 62.64 9.045 ;
     RECT  2.16 9.315 62.64 9.585 ;
     RECT  2.16 9.855 62.64 10.125 ;
     RECT  2.16 10.395 62.64 10.665 ;
     RECT  2.16 10.935 62.64 11.205 ;
     RECT  2.16 11.475 62.64 11.745 ;
     RECT  2.16 12.015 62.64 12.285 ;
     RECT  2.16 12.555 62.64 12.825 ;
     RECT  2.16 13.095 62.64 13.365 ;
     RECT  2.16 13.635 62.64 13.905 ;
     RECT  2.16 14.175 62.64 14.445 ;
     RECT  2.16 14.715 62.64 14.985 ;
     RECT  2.16 15.255 62.64 15.525 ;
     RECT  2.16 15.795 62.64 16.065 ;
     RECT  2.16 16.335 62.64 16.605 ;
     RECT  2.16 16.875 62.64 17.145 ;
     RECT  2.16 17.415 62.64 17.685 ;
     RECT  2.16 17.955 62.64 18.225 ;
     RECT  2.16 18.495 62.64 18.765 ;
     RECT  2.16 19.035 62.64 19.305 ;
     RECT  2.16 19.575 62.64 19.845 ;
     RECT  2.16 20.115 62.64 20.385 ;
     RECT  2.16 20.655 62.64 20.925 ;
     RECT  2.16 21.195 62.64 21.465 ;
     RECT  2.16 21.735 62.64 22.005 ;
     RECT  2.16 22.275 62.64 22.545 ;
     RECT  2.16 22.815 62.64 23.085 ;
     RECT  2.16 23.355 62.64 23.625 ;
     RECT  2.16 23.895 62.64 24.165 ;
     RECT  2.16 24.435 62.64 24.705 ;
     RECT  2.16 24.975 62.64 25.245 ;
     RECT  2.16 25.515 62.64 25.785 ;
     RECT  2.16 26.055 62.64 26.325 ;
     RECT  2.16 26.595 62.64 26.865 ;
     RECT  2.16 27.135 62.64 27.405 ;
     RECT  2.16 27.675 62.64 27.945 ;
     RECT  2.16 28.215 62.64 28.485 ;
     RECT  2.16 28.755 62.64 29.025 ;
     RECT  2.16 29.295 62.64 29.565 ;
     RECT  2.16 29.835 62.64 30.105 ;
     RECT  2.16 30.375 62.64 30.645 ;
     RECT  2.16 30.915 62.64 31.185 ;
     RECT  2.16 31.455 62.64 31.725 ;
     RECT  2.16 31.995 62.64 32.265 ;
     RECT  2.16 32.535 62.64 32.805 ;
     RECT  2.16 33.075 62.64 33.345 ;
     RECT  2.16 33.615 62.64 33.885 ;
     RECT  2.16 34.155 62.64 34.425 ;
     RECT  2.16 34.695 62.64 34.965 ;
     RECT  2.16 35.235 62.64 35.505 ;
     RECT  2.16 35.775 62.64 36.045 ;
     RECT  2.16 36.315 62.64 36.585 ;
     RECT  2.16 36.855 62.64 37.125 ;
     RECT  2.16 37.395 62.64 37.665 ;
     RECT  2.16 37.935 62.64 38.205 ;
     RECT  2.16 38.475 62.64 38.745 ;
     RECT  2.16 39.015 62.64 39.285 ;
     RECT  2.16 39.555 62.64 39.825 ;
     RECT  2.16 40.095 62.64 40.365 ;
     RECT  2.16 40.635 62.64 40.905 ;
    LAYER M1 ;
     RECT  2.16 2.151 62.64 41.049 ;
    LAYER M2 ;
     RECT  0.103 5.076 0.139 5.094 ;
     RECT  0.103 5.976 0.139 5.994 ;
     RECT  0.103 9.711 0.203 9.954 ;
     RECT  0.103 12.681 0.203 12.699 ;
     RECT  0.103 16.848 0.203 16.866 ;
     RECT  0.139 8.856 0.239 8.874 ;
     RECT  0.103 20.124 0.239 20.142 ;
     RECT  0.463 4.266 0.499 4.284 ;
     RECT  0.139 5.076 0.499 5.994 ;
     RECT  0.499 4.266 0.535 5.994 ;
     RECT  0.103 6.786 0.535 7.416 ;
     RECT  0.499 16.074 0.535 16.092 ;
     RECT  1.039 37.476 1.327 37.494 ;
     RECT  1.399 23.976 1.471 23.994 ;
     RECT  1.471 23.976 1.579 24.462 ;
     RECT  1.219 25.326 1.579 25.344 ;
     RECT  1.399 2.232 1.615 2.25 ;
     RECT  1.327 37.026 1.687 37.494 ;
     RECT  0.535 22.176 1.723 22.194 ;
     RECT  0.751 34.866 1.723 34.884 ;
     RECT  1.723 22.086 1.759 22.194 ;
     RECT  1.759 21.906 1.795 22.194 ;
     RECT  1.687 36.486 1.975 37.494 ;
     RECT  1.687 19.584 2.011 19.602 ;
     RECT  1.795 21.276 2.011 22.194 ;
     RECT  1.147 23.166 2.011 23.184 ;
     RECT  1.795 33.786 2.011 33.804 ;
     RECT  1.399 39.834 2.011 39.852 ;
     RECT  2.011 19.584 2.047 19.908 ;
     RECT  2.011 21.276 2.047 23.184 ;
     RECT  1.579 23.976 2.047 25.344 ;
     RECT  2.011 33.354 2.047 33.804 ;
     RECT  1.723 34.596 2.047 34.884 ;
     RECT  2.011 39.222 2.047 39.852 ;
     RECT  2.047 38.718 2.083 39.852 ;
     RECT  2.083 38.718 2.119 40.158 ;
     RECT  1.975 40.914 2.119 40.932 ;
     RECT  2.047 33.354 2.155 34.884 ;
     RECT  1.975 35.784 2.155 37.494 ;
     RECT  2.119 38.718 2.155 40.932 ;
     RECT  1.615 2.232 2.16 2.286 ;
     RECT  1.507 3.042 2.16 3.06 ;
     RECT  0.535 3.96 2.16 7.794 ;
     RECT  0.203 9.936 2.16 9.954 ;
     RECT  0.211 12.294 2.16 12.654 ;
     RECT  0.535 16.074 2.16 16.704 ;
     RECT  0.535 17.586 2.16 18.144 ;
     RECT  2.047 19.584 2.16 20.34 ;
     RECT  2.047 21.276 2.16 25.344 ;
     RECT  2.155 33.354 2.16 37.494 ;
     RECT  2.155 38.718 2.16 41.004 ;
     RECT  2.16 2.151 3.415 41.049 ;
     RECT  3.415 2.034 4.099 41.049 ;
     RECT  4.099 1.998 5.711 41.049 ;
     RECT  5.711 2.034 5.855 41.049 ;
     RECT  5.855 2.151 7.771 41.049 ;
     RECT  7.771 2.106 8.411 41.049 ;
     RECT  8.411 2.151 17.203 41.049 ;
     RECT  17.203 2.106 17.951 41.049 ;
     RECT  17.951 2.151 19.651 41.049 ;
     RECT  19.651 2.106 20.039 41.049 ;
     RECT  20.039 2.151 24.655 41.049 ;
     RECT  24.655 2.106 24.971 41.049 ;
     RECT  24.971 2.151 26.491 41.049 ;
     RECT  26.491 2.106 28.463 41.049 ;
     RECT  28.723 1.152 28.823 1.17 ;
     RECT  28.463 2.151 33.943 41.049 ;
     RECT  33.943 2.106 34.619 41.049 ;
     RECT  34.619 2.151 35.347 41.049 ;
     RECT  35.347 2.106 35.771 41.049 ;
     RECT  35.771 2.151 37.003 41.049 ;
     RECT  37.003 2.106 37.435 41.049 ;
     RECT  37.435 2.034 38.759 41.049 ;
     RECT  38.759 2.106 40.091 41.049 ;
     RECT  40.091 2.151 42.835 41.049 ;
     RECT  42.835 2.106 43.555 41.049 ;
     RECT  43.555 1.962 45.067 41.049 ;
     RECT  45.067 1.881 46.939 41.049 ;
     RECT  46.939 1.836 47.767 41.049 ;
     RECT  47.767 1.152 47.867 41.049 ;
     RECT  47.867 1.836 48.119 41.049 ;
     RECT  48.847 1.152 49.027 1.17 ;
     RECT  48.119 2.034 49.027 41.049 ;
     RECT  49.027 1.152 49.199 41.049 ;
     RECT  49.199 1.881 50.459 41.049 ;
     RECT  50.459 1.926 51.539 41.049 ;
     RECT  51.539 1.962 51.611 41.049 ;
     RECT  51.611 2.034 52.655 41.049 ;
     RECT  52.655 2.151 53.671 41.049 ;
     RECT  53.671 2.106 54.715 41.049 ;
     RECT  54.715 1.998 58.819 41.049 ;
     RECT  58.819 1.926 61.799 41.049 ;
     RECT  61.799 1.998 62.64 41.049 ;
     RECT  62.64 1.998 63.311 20.376 ;
     RECT  63.311 1.998 63.743 19.332 ;
     RECT  63.743 3.726 63.815 19.332 ;
     RECT  63.311 20.16 63.815 20.376 ;
     RECT  63.815 3.726 63.851 5.022 ;
     RECT  63.815 5.778 63.851 19.332 ;
     RECT  63.851 3.726 63.887 4.824 ;
     RECT  63.851 5.778 63.887 14.436 ;
     RECT  63.887 8.55 64.571 14.436 ;
     RECT  63.887 3.726 64.643 4.446 ;
     RECT  63.887 5.778 64.643 7.758 ;
     RECT  64.571 9.864 64.643 14.436 ;
     RECT  63.743 2.07 64.679 2.934 ;
     RECT  64.643 3.726 64.679 3.789 ;
     RECT  64.643 5.778 64.679 6.984 ;
     RECT  64.643 7.74 64.679 7.758 ;
     RECT  64.643 9.936 64.679 10.926 ;
     RECT  64.643 11.826 64.679 14.436 ;
     RECT  63.851 15.57 64.679 16.974 ;
     RECT  63.815 20.16 64.679 20.178 ;
     RECT  64.679 2.07 64.715 2.088 ;
     RECT  64.679 2.916 64.715 2.934 ;
     RECT  64.679 5.778 64.715 5.796 ;
     RECT  64.679 6.741 64.715 6.984 ;
     RECT  64.571 8.55 64.715 8.568 ;
     RECT  64.679 9.936 64.715 10.854 ;
     RECT  64.679 11.826 64.715 12.654 ;
     RECT  64.679 13.41 64.715 13.428 ;
     RECT  64.679 14.22 64.715 14.238 ;
     RECT  64.679 15.57 64.715 16.362 ;
     RECT  63.851 18.306 64.715 19.062 ;
     RECT  64.715 10.836 64.751 10.854 ;
     RECT  64.715 15.57 64.751 15.588 ;
     RECT  64.679 3.771 64.787 3.789 ;
     RECT  64.715 9.936 64.787 9.954 ;
    LAYER M3 ;
     RECT  42.192 0.091 42.21 0.139 ;
     RECT  53.604 0.091 53.622 0.139 ;
     RECT  54.396 0.091 55.098 0.139 ;
     RECT  57.744 0.091 57.762 0.139 ;
     RECT  48.348 0.091 48.366 0.187 ;
     RECT  42.192 0.139 42.606 0.427 ;
     RECT  43.668 0.091 43.686 0.427 ;
     RECT  51.336 0.379 51.354 0.475 ;
     RECT  22.14 0.091 23.706 0.523 ;
     RECT  28.728 0.091 28.746 0.523 ;
     RECT  42.192 0.427 43.686 0.523 ;
     RECT  46.584 0.475 46.602 0.523 ;
     RECT  48.348 0.187 48.798 0.523 ;
     RECT  51.336 0.475 51.534 0.523 ;
     RECT  52.38 0.427 52.866 0.523 ;
     RECT  53.604 0.139 55.098 0.523 ;
     RECT  59.94 0.091 60.606 0.523 ;
     RECT  12.708 0.523 12.726 0.571 ;
     RECT  15.048 0.523 15.066 0.571 ;
     RECT  16.056 0.091 17.154 0.571 ;
     RECT  20.232 0.091 20.97 0.571 ;
     RECT  21.78 0.523 23.706 0.571 ;
     RECT  25.488 0.091 25.506 0.571 ;
     RECT  26.244 0.091 27.018 0.571 ;
     RECT  28.728 0.523 29.178 0.571 ;
     RECT  32.832 0.091 35.658 0.571 ;
     RECT  37.8 0.091 37.818 0.571 ;
     RECT  39.384 0.091 39.402 0.571 ;
     RECT  42.084 0.523 43.686 0.571 ;
     RECT  44.712 0.523 44.73 0.571 ;
     RECT  57.744 0.139 58.374 0.571 ;
     RECT  20.016 0.571 24.75 0.619 ;
     RECT  25.488 0.571 27.018 0.619 ;
     RECT  36.9 0.571 38.034 0.619 ;
     RECT  44.496 0.571 45.018 0.667 ;
     RECT  63.036 0.715 63.054 0.907 ;
     RECT  51.336 0.523 51.606 1.003 ;
     RECT  44.46 0.667 45.018 1.051 ;
     RECT  46.584 0.523 48.942 1.051 ;
     RECT  9.684 0.523 9.702 1.099 ;
     RECT  10.476 0.571 10.494 1.099 ;
     RECT  12.204 0.571 13.122 1.099 ;
     RECT  36.828 0.619 38.034 1.099 ;
     RECT  44.46 1.051 45.054 1.099 ;
     RECT  46.584 1.051 49.05 1.099 ;
     RECT  50.22 0.427 50.238 1.099 ;
     RECT  63.036 0.907 63.234 1.099 ;
     RECT  31.104 0.091 31.122 1.147 ;
     RECT  32.112 0.571 35.658 1.147 ;
     RECT  51.156 1.003 51.606 1.147 ;
     RECT  52.38 0.523 55.782 1.147 ;
     RECT  56.772 0.091 56.79 1.147 ;
     RECT  57.744 0.571 58.734 1.147 ;
     RECT  59.508 0.523 60.606 1.147 ;
     RECT  62.964 1.099 63.234 1.195 ;
     RECT  64.656 0.811 64.674 1.483 ;
     RECT  41.616 0.571 43.686 1.627 ;
     RECT  20.016 0.619 27.018 1.675 ;
     RECT  41.472 1.627 43.686 1.675 ;
     RECT  44.46 1.099 45.27 1.675 ;
     RECT  46.008 1.099 50.238 1.675 ;
     RECT  51.156 1.147 55.782 1.675 ;
     RECT  2.304 0.571 2.322 1.723 ;
     RECT  3.096 0.091 3.114 1.723 ;
     RECT  5.724 1.099 5.742 1.723 ;
     RECT  7.956 1.147 7.974 1.723 ;
     RECT  8.748 0.523 8.766 1.723 ;
     RECT  9.684 1.099 10.494 1.723 ;
     RECT  11.232 1.099 13.122 1.723 ;
     RECT  14.832 0.571 15.066 1.723 ;
     RECT  16.02 0.571 17.154 1.723 ;
     RECT  18.18 0.091 18.198 1.723 ;
     RECT  20.016 1.675 27.126 1.723 ;
     RECT  28.368 0.571 29.178 1.723 ;
     RECT  31.104 1.147 35.658 1.723 ;
     RECT  36.828 1.099 38.07 1.723 ;
     RECT  39.384 0.571 40.086 1.723 ;
     RECT  41.472 1.675 45.27 1.723 ;
     RECT  46.008 1.675 55.782 1.723 ;
     RECT  56.772 1.147 56.898 1.723 ;
     RECT  2.304 1.723 3.114 1.771 ;
     RECT  4.572 1.723 18.954 1.771 ;
     RECT  1.404 1.771 3.114 1.819 ;
     RECT  19.908 1.723 45.27 1.819 ;
     RECT  46.008 1.723 57.006 1.819 ;
     RECT  1.404 1.819 3.15 1.915 ;
     RECT  4.248 1.771 19.17 1.915 ;
     RECT  19.908 1.819 57.006 1.915 ;
     RECT  61.416 1.003 61.434 1.921 ;
     RECT  62.964 1.195 63.846 1.963 ;
     RECT  57.744 1.147 60.606 1.993 ;
     RECT  61.416 1.921 61.794 1.993 ;
     RECT  57.744 1.993 61.794 2.029 ;
     RECT  62.82 1.963 63.846 2.029 ;
     RECT  1.404 1.915 57.006 2.101 ;
     RECT  57.744 2.029 63.846 2.101 ;
     RECT  1.404 2.101 63.846 2.255 ;
     RECT  64.656 1.483 64.71 2.633 ;
     RECT  1.512 2.255 63.846 3.065 ;
     RECT  64.692 2.633 64.71 3.403 ;
     RECT  64.656 3.403 64.71 3.691 ;
     RECT  64.62 3.691 64.71 3.766 ;
     RECT  0.54 3.955 0.558 4.261 ;
     RECT  1.728 3.065 63.846 4.415 ;
     RECT  1.944 4.415 63.846 4.685 ;
     RECT  2.304 4.685 63.846 4.801 ;
     RECT  0.468 4.261 0.558 4.877 ;
     RECT  2.304 4.801 63.882 4.877 ;
     RECT  2.304 4.877 63.846 5.027 ;
     RECT  0.468 4.877 0.522 5.071 ;
     RECT  64.62 3.766 64.782 5.515 ;
     RECT  0.108 5.071 0.522 5.611 ;
     RECT  64.584 5.515 64.782 5.803 ;
     RECT  2.304 5.027 63.81 5.899 ;
     RECT  64.548 5.803 64.782 5.899 ;
     RECT  0.108 5.611 0.558 6.115 ;
     RECT  2.304 5.899 64.782 6.143 ;
     RECT  0.108 6.115 0.63 6.377 ;
     RECT  0.108 6.377 0.558 6.893 ;
     RECT  2.304 6.143 62.442 7.147 ;
     RECT  63.18 6.143 64.782 7.147 ;
     RECT  2.304 7.147 64.782 7.259 ;
     RECT  2.34 7.259 64.782 7.277 ;
     RECT  2.376 7.277 64.782 7.349 ;
     RECT  0.108 6.893 0.126 7.565 ;
     RECT  0.324 7.771 0.558 7.949 ;
     RECT  0.54 7.949 0.558 8.141 ;
     RECT  2.412 7.349 64.782 8.251 ;
     RECT  2.304 8.251 64.782 8.635 ;
     RECT  0.324 8.683 0.342 8.813 ;
     RECT  0.216 8.827 0.234 8.851 ;
     RECT  0.144 8.851 0.234 8.879 ;
     RECT  2.232 8.635 64.782 9.275 ;
     RECT  0.144 8.879 0.198 9.451 ;
     RECT  0.108 9.451 0.198 9.739 ;
     RECT  0.108 9.739 0.342 9.869 ;
     RECT  2.268 9.275 64.782 9.959 ;
     RECT  0.108 9.869 0.162 10.157 ;
     RECT  2.268 9.959 64.71 10.391 ;
     RECT  2.268 10.391 62.982 10.603 ;
     RECT  1.296 10.651 1.314 10.829 ;
     RECT  63.792 10.391 64.71 10.831 ;
     RECT  0.108 10.157 0.126 11.021 ;
     RECT  2.232 10.603 62.982 11.129 ;
     RECT  12.06 11.129 62.982 11.467 ;
     RECT  63.792 10.831 64.746 11.467 ;
     RECT  2.232 11.129 11.214 11.471 ;
     RECT  12.06 11.467 64.746 11.789 ;
     RECT  0.324 11.275 0.342 12.289 ;
     RECT  0.216 12.289 0.342 12.427 ;
     RECT  63.756 11.789 64.746 12.515 ;
     RECT  0.108 12.427 0.342 12.631 ;
     RECT  0.108 12.631 0.558 12.716 ;
     RECT  63.756 12.515 63.846 12.811 ;
     RECT  0.144 12.716 0.558 13.085 ;
     RECT  2.268 11.471 11.214 13.091 ;
     RECT  12.06 11.789 62.982 13.099 ;
     RECT  63.72 12.811 63.846 13.099 ;
     RECT  0.216 13.085 0.558 13.133 ;
     RECT  0.324 13.133 0.558 13.325 ;
     RECT  0.324 13.325 0.342 13.613 ;
     RECT  12.06 13.099 63.846 13.667 ;
     RECT  2.304 13.091 11.214 13.945 ;
     RECT  12.06 13.667 63.81 13.945 ;
     RECT  64.656 12.515 64.746 14.441 ;
     RECT  2.304 13.945 63.81 14.539 ;
     RECT  64.728 14.441 64.746 15.593 ;
     RECT  2.304 14.539 63.846 15.691 ;
     RECT  2.268 15.691 63.846 15.728 ;
     RECT  64.692 15.883 64.71 15.979 ;
     RECT  64.656 15.979 64.71 16.025 ;
     RECT  0.144 13.915 0.162 16.069 ;
     RECT  2.304 15.728 63.846 16.109 ;
     RECT  0.144 16.069 0.522 16.681 ;
     RECT  0.144 16.681 0.558 16.747 ;
     RECT  64.692 16.025 64.71 16.747 ;
     RECT  0.108 16.747 0.558 16.871 ;
     RECT  2.304 16.109 62.262 16.915 ;
     RECT  2.304 16.915 62.37 16.939 ;
     RECT  63.18 16.109 63.846 16.939 ;
     RECT  64.656 16.747 64.71 16.979 ;
     RECT  0.144 16.871 0.558 17.069 ;
     RECT  2.304 16.939 63.846 17.323 ;
     RECT  0.324 17.069 0.558 17.645 ;
     RECT  0.54 17.645 0.558 17.803 ;
     RECT  1.692 17.323 63.846 17.803 ;
     RECT  0.54 17.803 63.846 18.077 ;
     RECT  0.54 18.077 0.558 18.317 ;
     RECT  64.692 16.979 64.71 18.391 ;
     RECT  64.62 18.391 64.71 18.461 ;
     RECT  0.216 18.523 0.342 18.571 ;
     RECT  0.144 18.571 0.342 18.797 ;
     RECT  64.656 18.461 64.71 19.067 ;
     RECT  1.692 18.077 63.846 19.337 ;
     RECT  1.692 19.337 63.81 19.877 ;
     RECT  63.288 19.877 63.81 19.913 ;
     RECT  0.144 18.797 0.162 20.011 ;
     RECT  1.692 19.877 62.334 20.039 ;
     RECT  0.144 20.011 0.342 20.107 ;
     RECT  0.108 20.107 0.342 20.147 ;
     RECT  1.692 20.039 62.262 20.155 ;
     RECT  64.656 19.067 64.674 20.183 ;
     RECT  63.792 19.913 63.81 20.381 ;
     RECT  1.152 20.155 62.262 20.615 ;
     RECT  0.216 20.147 0.342 20.909 ;
     RECT  0.216 20.909 0.234 21.101 ;
     RECT  1.152 20.615 62.097 21.533 ;
     RECT  0.144 21.979 0.162 22.157 ;
     RECT  1.152 21.533 60.858 22.171 ;
     RECT  0.216 22.171 60.858 22.253 ;
     RECT  0.216 22.253 0.342 22.541 ;
     RECT  0.216 22.541 0.234 22.733 ;
     RECT  1.152 22.253 60.858 23.189 ;
     RECT  0.108 23.179 0.126 23.309 ;
     RECT  1.224 23.189 60.858 24.737 ;
     RECT  2.196 24.737 60.858 24.971 ;
     RECT  1.224 24.737 1.242 25.349 ;
     RECT  2.232 24.971 60.858 25.619 ;
     RECT  2.268 25.619 60.858 26.401 ;
     RECT  2.268 26.401 61.002 26.671 ;
     RECT  2.268 26.671 61.038 26.789 ;
     RECT  2.268 26.789 61.002 27.059 ;
     RECT  2.415 27.059 61.002 27.751 ;
     RECT  61.815 21.533 62.097 27.751 ;
     RECT  2.415 27.751 62.097 27.905 ;
     RECT  2.415 27.905 61.038 29.291 ;
     RECT  2.415 29.291 61.002 30.379 ;
     RECT  61.815 27.905 62.097 30.379 ;
     RECT  2.415 30.379 62.097 32.261 ;
     RECT  2.415 32.261 60.966 32.957 ;
     RECT  2.415 32.957 24.966 33.349 ;
     RECT  2.016 33.349 24.966 33.691 ;
     RECT  25.704 32.957 60.966 33.691 ;
     RECT  2.016 33.691 61.038 33.781 ;
     RECT  1.8 33.781 61.038 33.845 ;
     RECT  1.8 33.845 60.966 34.591 ;
     RECT  1.728 34.591 60.966 34.691 ;
     RECT  1.728 34.691 24.966 34.781 ;
     RECT  25.704 34.691 60.966 35.203 ;
     RECT  61.815 32.261 62.097 35.203 ;
     RECT  0.756 34.861 0.774 35.357 ;
     RECT  2.016 34.781 24.966 35.671 ;
     RECT  25.704 35.203 62.097 35.671 ;
     RECT  2.016 35.671 62.097 35.779 ;
     RECT  1.98 35.779 62.097 36.481 ;
     RECT  1.692 36.481 62.097 37.003 ;
     RECT  1.332 37.003 62.097 37.049 ;
     RECT  1.044 37.471 1.062 38.189 ;
     RECT  1.98 37.049 10.818 39.289 ;
     RECT  11.772 37.049 62.097 39.289 ;
     RECT  1.98 39.289 62.097 39.389 ;
     RECT  21.492 39.389 62.097 39.479 ;
     RECT  1.98 39.389 11.106 39.829 ;
     RECT  1.404 39.829 11.106 39.917 ;
     RECT  22.032 39.479 62.097 40.019 ;
     RECT  12.24 39.389 20.754 40.091 ;
     RECT  22.068 40.019 62.097 40.091 ;
     RECT  12.24 40.091 20.682 40.163 ;
     RECT  1.98 39.917 11.106 40.703 ;
     RECT  23.976 40.091 62.097 40.739 ;
     RECT  45.612 40.739 62.097 40.787 ;
     RECT  1.98 40.703 10.962 40.829 ;
     RECT  23.976 40.739 44.874 40.829 ;
     RECT  7.488 40.829 10.962 40.865 ;
     RECT  1.98 40.829 6.75 40.901 ;
     RECT  1.98 40.901 6.462 40.937 ;
     RECT  45.612 40.787 61.905 40.937 ;
     RECT  12.708 40.163 20.682 40.939 ;
     RECT  22.068 40.091 23.166 40.945 ;
     RECT  2.16 40.937 6.462 40.973 ;
     RECT  23.976 40.829 44.838 40.973 ;
     RECT  2.16 40.973 6.39 41.009 ;
     RECT  7.524 40.865 10.962 41.009 ;
     RECT  12.708 40.939 20.754 41.009 ;
     RECT  23.976 40.973 25.65 41.009 ;
     RECT  7.524 41.009 10.818 41.021 ;
     RECT  21.996 40.945 23.166 41.021 ;
     RECT  23.976 41.009 25.614 41.021 ;
     RECT  26.856 40.973 44.838 41.021 ;
     RECT  45.615 40.937 61.905 41.021 ;
     RECT  26.856 41.021 29.505 41.057 ;
     RECT  45.615 41.021 49.662 41.057 ;
     RECT  61.815 41.021 61.905 41.057 ;
     RECT  12.708 41.009 20.682 41.069 ;
     RECT  22.068 41.021 22.194 41.069 ;
     RECT  26.856 41.057 29.394 41.069 ;
     RECT  22.104 41.069 22.194 41.117 ;
     RECT  27.252 41.069 29.394 41.117 ;
     RECT  50.544 41.021 53.19 41.165 ;
     RECT  23.976 41.021 25.434 41.213 ;
     RECT  29.232 41.117 29.394 41.213 ;
     RECT  30.744 41.021 35.19 41.213 ;
     RECT  40.068 41.021 41.022 41.213 ;
     RECT  56.376 41.021 60.894 41.213 ;
     RECT  2.34 41.009 6.39 41.261 ;
     RECT  24.444 41.213 25.434 41.261 ;
     RECT  56.592 41.213 56.61 41.261 ;
     RECT  2.556 41.261 6.39 41.597 ;
     RECT  12.708 41.069 19.782 41.597 ;
     RECT  45.828 41.057 49.662 41.597 ;
     RECT  2.556 41.597 4.23 41.645 ;
     RECT  22.104 41.117 22.122 41.645 ;
     RECT  29.232 41.213 29.358 41.645 ;
     RECT  36.36 41.021 37.602 41.645 ;
     RECT  44.064 41.021 44.838 41.645 ;
     RECT  45.828 41.597 46.206 41.645 ;
     RECT  50.544 41.165 50.886 41.645 ;
     RECT  51.696 41.165 53.19 41.645 ;
     RECT  29.232 41.645 29.322 41.693 ;
     RECT  50.544 41.645 50.562 41.693 ;
     RECT  29.268 41.693 29.322 41.741 ;
     RECT  42.3 41.021 42.858 41.885 ;
     RECT  12.708 41.597 16.47 42.125 ;
     RECT  42.84 41.885 42.858 42.125 ;
     RECT  3.06 41.645 4.23 42.173 ;
     RECT  5.256 41.597 6.39 42.173 ;
     RECT  7.524 41.021 9.486 42.173 ;
     RECT  12.708 42.125 16.362 42.173 ;
     RECT  17.532 41.597 19.782 42.173 ;
     RECT  24.984 41.261 25.434 42.173 ;
     RECT  44.064 41.645 44.082 42.173 ;
     RECT  45.828 41.645 46.062 42.173 ;
     RECT  47.016 41.597 49.662 42.173 ;
     RECT  52.344 41.645 53.19 42.173 ;
     RECT  53.928 41.021 54.81 42.173 ;
     RECT  57.348 41.213 60.894 42.173 ;
     RECT  12.708 42.173 15.318 42.221 ;
     RECT  17.532 42.173 17.838 42.221 ;
     RECT  20.664 41.069 20.682 42.221 ;
     RECT  24.984 42.173 25.398 42.221 ;
     RECT  30.744 41.213 31.842 42.221 ;
     RECT  32.652 41.213 35.19 42.221 ;
     RECT  36.54 41.645 37.602 42.221 ;
     RECT  48.996 42.173 49.554 42.221 ;
     RECT  19.764 42.173 19.782 42.269 ;
     RECT  36.54 42.221 36.99 42.269 ;
     RECT  36.54 42.269 36.954 42.797 ;
     RECT  12.708 42.221 12.726 42.811 ;
     RECT  27.252 41.117 28.314 42.811 ;
     RECT  27.036 42.811 28.314 42.859 ;
     RECT  29.268 41.741 29.286 42.859 ;
     RECT  23.148 41.021 23.166 42.955 ;
     RECT  7.524 42.173 7.758 42.989 ;
     RECT  13.608 42.221 15.066 42.989 ;
     RECT  19.836 42.859 19.854 42.989 ;
     RECT  27.036 42.859 29.286 42.989 ;
     RECT  22.824 42.955 23.166 43.003 ;
     RECT  30.96 42.221 31.77 43.003 ;
     RECT  32.652 42.221 34.758 43.003 ;
     RECT  13.716 42.989 15.066 43.037 ;
     RECT  30.96 43.003 34.758 43.037 ;
     RECT  3.564 42.173 3.798 43.085 ;
     RECT  5.616 42.173 6.102 43.085 ;
     RECT  7.56 42.989 7.758 43.085 ;
     RECT  8.892 42.173 9.486 43.085 ;
     RECT  11.592 42.955 11.61 43.085 ;
     RECT  12.348 42.811 12.726 43.085 ;
     RECT  13.932 43.037 15.066 43.085 ;
     RECT  17.532 42.221 17.55 43.085 ;
     RECT  22.824 43.003 23.886 43.085 ;
     RECT  25.38 42.221 25.398 43.085 ;
     RECT  27.252 42.989 29.286 43.085 ;
     RECT  30.96 43.037 34.65 43.085 ;
     RECT  41.004 41.213 41.022 43.085 ;
     RECT  44.82 41.645 44.838 43.085 ;
     RECT  46.044 42.173 46.062 43.085 ;
     RECT  48.996 42.221 49.014 43.085 ;
     RECT  54.36 42.173 54.378 43.085 ;
     RECT  57.348 42.173 57.366 43.085 ;
     RECT  23.796 43.085 23.886 43.133 ;
     RECT  27.252 43.085 27.342 43.133 ;
     RECT  32.04 43.085 32.238 43.133 ;
     RECT  36.54 42.797 36.81 43.133 ;
     RECT  23.796 43.133 23.814 43.181 ;
     RECT  27.324 43.133 27.342 43.181 ;
     RECT  32.22 43.133 32.238 43.181 ;
     RECT  36.792 43.133 36.81 43.181 ;
    LAYER M4 ;
     RECT  0.06 4.848 0.097 23.208 ;
     RECT  0.097 4.848 0.569 23.304 ;
     RECT  0.701 35.328 0.785 35.352 ;
     RECT  0.709 3.408 0.805 3.432 ;
     RECT  0.805 38.784 0.989 38.808 ;
     RECT  0.989 38.16 1.073 38.808 ;
     RECT  0.997 1.728 1.093 1.752 ;
     RECT  0.805 2.88 1.093 3.432 ;
     RECT  1.073 38.784 1.093 38.808 ;
     RECT  1.093 1.728 1.189 3.432 ;
     RECT  1.093 38.784 1.349 39.336 ;
     RECT  0.901 40.416 1.349 40.44 ;
     RECT  1.277 37.008 1.361 37.032 ;
     RECT  1.669 34.752 1.745 34.776 ;
     RECT  1.189 1.728 1.861 3.624 ;
     RECT  0.569 4.944 1.861 23.304 ;
     RECT  1.477 36.528 1.861 36.552 ;
     RECT  1.349 38.784 2.149 40.44 ;
     RECT  2.149 38.736 2.329 40.44 ;
     RECT  1.189 42.144 2.329 42.168 ;
     RECT  1.285 0.576 2.333 0.6 ;
     RECT  1.861 1.728 2.408 23.304 ;
     RECT  2.329 24.672 2.408 24.696 ;
     RECT  1.745 34.704 2.408 34.776 ;
     RECT  1.861 35.808 2.408 36.552 ;
     RECT  1.573 37.632 2.408 37.656 ;
     RECT  2.329 38.736 2.408 42.168 ;
     RECT  2.408 1.728 2.629 42.168 ;
     RECT  2.629 1.728 2.704 43.032 ;
     RECT  2.704 35.808 2.873 35.832 ;
     RECT  2.704 38.112 2.989 43.032 ;
     RECT  2.989 38.112 3.017 38.232 ;
     RECT  2.704 33.648 3.059 34.824 ;
     RECT  2.989 39.264 3.089 43.032 ;
     RECT  2.725 0.096 3.125 0.12 ;
     RECT  2.704 26.592 3.269 26.76 ;
     RECT  3.059 33.648 3.341 34.2 ;
     RECT  3.341 34.176 3.413 34.2 ;
     RECT  3.017 38.208 3.413 38.232 ;
     RECT  3.089 39.312 3.493 43.032 ;
     RECT  3.269 26.592 3.701 26.616 ;
     RECT  2.704 25.056 3.809 25.08 ;
     RECT  3.493 39.312 3.853 43.08 ;
     RECT  2.704 36.864 3.877 36.888 ;
     RECT  3.877 36.384 4.169 36.888 ;
     RECT  4.169 36.432 4.273 36.888 ;
     RECT  4.069 37.92 4.273 38.136 ;
     RECT  4.273 36.432 4.313 38.136 ;
     RECT  4.313 36.576 4.489 38.136 ;
     RECT  3.853 39.312 4.489 42.168 ;
     RECT  2.704 1.728 4.493 23.688 ;
     RECT  4.493 1.728 4.565 20.136 ;
     RECT  4.493 21.12 4.637 23.688 ;
     RECT  4.489 36.576 4.643 42.168 ;
     RECT  4.643 37.632 4.781 42.168 ;
     RECT  4.643 36.576 5.069 36.6 ;
     RECT  4.781 37.632 5.171 41.016 ;
     RECT  4.781 42.096 5.317 42.168 ;
     RECT  5.317 42.096 5.357 43.08 ;
     RECT  5.171 38.208 5.429 41.016 ;
     RECT  4.565 1.728 5.645 19.608 ;
     RECT  4.637 21.216 5.677 23.688 ;
     RECT  5.645 1.728 5.713 2.904 ;
     RECT  5.429 38.64 5.717 41.016 ;
     RECT  5.713 1.104 5.843 2.904 ;
     RECT  5.357 43.008 6.113 43.08 ;
     RECT  5.645 3.888 6.329 19.608 ;
     RECT  6.361 42.144 6.445 42.168 ;
     RECT  5.717 38.64 6.653 40.824 ;
     RECT  6.716 36.48 6.803 36.504 ;
     RECT  7.429 43.056 7.513 43.08 ;
     RECT  6.653 39.36 7.621 40.824 ;
     RECT  7.477 0.192 7.669 0.216 ;
     RECT  7.621 39.36 7.669 41.016 ;
     RECT  7.669 38.736 7.693 41.016 ;
     RECT  5.843 1.728 7.808 2.904 ;
     RECT  6.329 3.936 7.808 19.608 ;
     RECT  5.677 20.976 7.808 23.688 ;
     RECT  3.949 26.352 7.808 26.376 ;
     RECT  7.693 38.736 7.808 41.208 ;
     RECT  7.808 1.728 7.859 41.208 ;
     RECT  7.669 0.144 7.945 0.216 ;
     RECT  7.859 1.728 7.945 41.16 ;
     RECT  7.513 42.96 8.005 43.08 ;
     RECT  7.945 0.144 8.104 41.16 ;
     RECT  8.104 0.144 8.147 19.608 ;
     RECT  8.147 0.144 8.291 0.552 ;
     RECT  8.104 39.36 8.381 41.16 ;
     RECT  8.005 42.144 9.281 43.08 ;
     RECT  9.253 38.16 9.349 38.184 ;
     RECT  9.281 43.056 9.497 43.08 ;
     RECT  9.349 38.16 9.713 38.232 ;
     RECT  8.381 39.36 9.721 41.016 ;
     RECT  8.291 0.528 9.779 0.552 ;
     RECT  9.721 39.36 9.865 39.912 ;
     RECT  9.865 39.888 10.073 39.912 ;
     RECT  8.147 1.728 10.105 19.608 ;
     RECT  8.104 20.976 10.309 23.688 ;
     RECT  10.105 1.632 10.364 19.608 ;
     RECT  10.364 0.576 10.549 19.608 ;
     RECT  10.285 38.832 10.577 38.856 ;
     RECT  10.501 32.496 10.587 32.52 ;
     RECT  9.721 40.896 10.829 41.016 ;
     RECT  10.781 31.344 10.873 31.368 ;
     RECT  10.587 32.496 10.885 32.568 ;
     RECT  10.829 40.896 10.973 40.92 ;
     RECT  10.885 31.872 11.117 32.568 ;
     RECT  10.981 30.24 11.269 30.264 ;
     RECT  10.549 1.104 11.329 19.608 ;
     RECT  10.309 20.64 11.329 23.688 ;
     RECT  11.537 43.056 11.564 43.08 ;
     RECT  11.117 31.92 11.581 32.568 ;
     RECT  11.581 31.92 11.653 33.048 ;
     RECT  11.653 31.92 11.665 33.576 ;
     RECT  11.749 35.856 11.845 35.88 ;
     RECT  11.269 30.24 11.987 30.744 ;
     RECT  11.329 1.104 12.083 23.688 ;
     RECT  8.104 26.352 12.193 26.376 ;
     RECT  11.987 30.432 12.229 30.744 ;
     RECT  11.665 31.92 12.229 32.472 ;
     RECT  11.564 42.96 12.325 43.08 ;
     RECT  12.325 42.912 12.337 43.08 ;
     RECT  12.337 42.816 12.517 43.08 ;
     RECT  12.083 1.68 12.563 23.688 ;
     RECT  12.193 0.576 12.668 0.6 ;
     RECT  12.517 42.336 12.781 43.08 ;
     RECT  12.229 30.432 12.805 32.472 ;
     RECT  12.133 29.088 13.045 29.112 ;
     RECT  12.805 30.432 13.045 32.568 ;
     RECT  12.668 0.528 13.093 0.6 ;
     RECT  12.913 25.056 13.093 25.08 ;
     RECT  13.093 25.008 13.129 25.08 ;
     RECT  12.563 1.728 13.208 23.688 ;
     RECT  13.129 24.912 13.208 25.08 ;
     RECT  12.193 26.352 13.208 26.712 ;
     RECT  13.045 29.088 13.208 32.568 ;
     RECT  11.665 33.552 13.208 33.576 ;
     RECT  12.86 34.8 13.208 34.824 ;
     RECT  11.845 35.808 13.208 35.88 ;
     RECT  12.661 39.888 13.208 39.912 ;
     RECT  13.093 41.184 13.208 41.208 ;
     RECT  12.781 42.336 13.34 43.032 ;
     RECT  13.093 0.528 13.427 0.696 ;
     RECT  13.208 1.728 13.504 41.208 ;
     RECT  13.504 33.456 13.619 33.576 ;
     RECT  13.504 40.176 13.633 41.208 ;
     RECT  13.34 42.192 13.633 43.032 ;
     RECT  13.477 0.144 13.667 0.168 ;
     RECT  13.619 33.456 13.667 33.48 ;
     RECT  13.504 38.784 13.673 38.808 ;
     RECT  13.633 40.176 13.861 43.032 ;
     RECT  13.504 29.76 14.177 29.784 ;
     RECT  13.861 40.176 14.669 43.08 ;
     RECT  14.669 39.888 14.753 43.08 ;
     RECT  14.569 25.056 14.825 25.08 ;
     RECT  14.821 0.576 14.905 0.6 ;
     RECT  14.876 34.8 14.917 34.824 ;
     RECT  13.504 37.056 15.001 37.08 ;
     RECT  14.917 34.8 15.077 34.92 ;
     RECT  14.753 40.032 15.077 43.08 ;
     RECT  15.077 34.8 15.221 34.824 ;
     RECT  15.253 38.784 15.337 38.808 ;
     RECT  15.077 40.032 15.347 42.216 ;
     RECT  15.001 36.576 15.473 37.08 ;
     RECT  13.504 26.352 15.577 26.376 ;
     RECT  15.473 36.72 15.587 37.08 ;
     RECT  15.541 38.832 15.731 38.904 ;
     RECT  15.587 36.816 15.865 37.08 ;
     RECT  13.504 1.728 15.901 23.688 ;
     RECT  15.577 24.912 15.901 24.936 ;
     RECT  15.865 30.768 15.901 30.792 ;
     RECT  15.577 26.256 15.925 26.376 ;
     RECT  15.037 0.528 15.965 0.552 ;
     RECT  15.965 0.528 16.045 0.6 ;
     RECT  16.045 0.096 16.049 0.6 ;
     RECT  15.901 1.728 16.067 24.936 ;
     RECT  16.067 1.728 16.117 24.216 ;
     RECT  15.347 40.032 16.117 42.168 ;
     RECT  15.925 26.256 16.225 26.76 ;
     RECT  16.225 25.248 16.261 26.76 ;
     RECT  16.117 39.888 16.261 42.168 ;
     RECT  15.865 36.816 16.265 37.512 ;
     RECT  16.261 39.312 16.373 42.168 ;
     RECT  16.373 39.312 16.481 42.12 ;
     RECT  15.901 30.576 16.549 30.792 ;
     RECT  15.433 32.496 16.549 32.52 ;
     RECT  16.549 30 16.595 32.52 ;
     RECT  16.595 31.536 16.636 31.56 ;
     RECT  16.261 25.248 16.721 26.856 ;
     RECT  16.117 1.68 16.787 24.216 ;
     RECT  16.549 37.632 17.027 37.704 ;
     RECT  17.027 37.68 17.029 37.704 ;
     RECT  16.441 28.464 17.077 28.488 ;
     RECT  16.595 30 17.077 30.264 ;
     RECT  16.729 34.8 17.093 34.824 ;
     RECT  17.077 28.464 17.123 30.264 ;
     RECT  16.721 25.248 17.125 26.952 ;
     RECT  17.123 29.088 17.165 30.264 ;
     RECT  16.481 39.312 17.173 41.592 ;
     RECT  17.125 25.248 17.309 28.008 ;
     RECT  17.029 37.68 17.309 38.184 ;
     RECT  17.173 39.312 17.317 41.064 ;
     RECT  17.309 25.248 17.341 27.912 ;
     RECT  17.309 38.112 17.345 38.184 ;
     RECT  16.787 1.728 17.449 24.216 ;
     RECT  17.341 25.2 17.449 27.912 ;
     RECT  17.317 39.264 17.525 41.064 ;
     RECT  17.413 43.056 17.561 43.08 ;
     RECT  17.449 1.728 17.597 27.912 ;
     RECT  17.701 42.192 17.849 42.216 ;
     RECT  16.049 0.096 18.209 0.12 ;
     RECT  17.525 39.792 18.277 41.064 ;
     RECT  17.345 38.112 18.469 38.136 ;
     RECT  17.165 29.472 18.565 30.264 ;
     RECT  17.597 1.728 18.608 27.768 ;
     RECT  18.565 29.472 18.608 30.696 ;
     RECT  18.469 38.112 18.608 38.616 ;
     RECT  18.277 39.792 18.608 42.168 ;
     RECT  18.608 1.728 18.904 42.168 ;
     RECT  18.904 1.728 18.965 26.712 ;
     RECT  18.965 24.912 19.187 26.712 ;
     RECT  18.904 38.784 19.381 42.168 ;
     RECT  19.381 38.784 19.505 42.984 ;
     RECT  19.505 39.36 19.721 42.984 ;
     RECT  19.187 24.912 19.865 26.52 ;
     RECT  19.721 40.896 19.9 42.984 ;
     RECT  18.904 28.272 20.005 29.64 ;
     RECT  19.9 40.896 20.051 42.264 ;
     RECT  18.965 1.728 20.077 23.88 ;
     RECT  19.865 24.912 20.077 25.224 ;
     RECT  20.005 0.576 20.101 0.6 ;
     RECT  19.865 26.352 20.185 26.52 ;
     RECT  20.005 28.032 20.185 29.64 ;
     RECT  18.904 30.672 20.221 31.368 ;
     RECT  20.041 34.224 20.257 34.248 ;
     RECT  20.221 30.672 20.305 31.416 ;
     RECT  20.051 40.896 20.332 41.064 ;
     RECT  20.185 26.352 20.369 29.64 ;
     RECT  20.257 34.224 20.435 34.776 ;
     RECT  20.369 26.352 20.579 28.104 ;
     RECT  20.293 36.48 20.653 36.504 ;
     RECT  20.579 27.408 20.657 28.056 ;
     RECT  20.051 42.192 20.693 42.264 ;
     RECT  20.653 36.432 20.737 36.504 ;
     RECT  20.332 40.944 20.765 41.064 ;
     RECT  19.721 39.36 20.819 39.912 ;
     RECT  20.369 29.088 20.869 29.64 ;
     RECT  20.305 30.672 20.869 31.272 ;
     RECT  20.435 34.224 20.869 34.248 ;
     RECT  20.077 1.728 20.905 25.224 ;
     RECT  20.579 26.352 20.905 26.376 ;
     RECT  20.819 39.888 20.915 39.912 ;
     RECT  20.869 29.088 20.945 31.272 ;
     RECT  20.101 0.096 20.981 0.6 ;
     RECT  20.765 41.04 21.011 41.064 ;
     RECT  20.905 1.728 21.089 26.376 ;
     RECT  20.693 42.24 21.107 42.264 ;
     RECT  20.869 33.936 21.193 34.248 ;
     RECT  21.193 33.024 21.277 34.248 ;
     RECT  20.737 36.48 21.299 36.504 ;
     RECT  21.277 33.936 21.445 34.248 ;
     RECT  20.821 38.496 21.589 38.808 ;
     RECT  21.589 37.632 21.683 38.808 ;
     RECT  21.445 33.936 21.685 34.776 ;
     RECT  21.685 33.936 21.773 35.496 ;
     RECT  20.981 0.528 21.875 0.6 ;
     RECT  21.683 38.496 21.877 38.808 ;
     RECT  21.349 40.032 21.98 40.056 ;
     RECT  21.98 40.032 22.057 41.016 ;
     RECT  20.657 27.84 22.069 28.056 ;
     RECT  22.057 40.032 22.093 41.064 ;
     RECT  21.773 33.936 22.205 35.304 ;
     RECT  21.089 1.728 22.309 19.608 ;
     RECT  21.089 20.64 22.309 26.376 ;
     RECT  22.205 35.28 22.349 35.304 ;
     RECT  22.093 40.032 22.355 41.64 ;
     RECT  22.069 27.84 22.417 28.248 ;
     RECT  20.945 29.472 22.417 31.272 ;
     RECT  22.355 40.032 22.451 41.064 ;
     RECT  22.309 1.728 22.501 26.376 ;
     RECT  22.501 1.152 22.597 26.376 ;
     RECT  21.205 43.008 22.693 43.032 ;
     RECT  22.597 1.152 22.7 26.616 ;
     RECT  22.417 27.84 22.7 31.272 ;
     RECT  22.7 1.152 22.709 31.272 ;
     RECT  22.693 43.008 22.741 43.08 ;
     RECT  22.451 40.032 22.817 41.016 ;
     RECT  22.709 1.2 22.853 31.272 ;
     RECT  22.741 42.96 22.885 43.08 ;
     RECT  21.877 38.496 22.921 39.048 ;
     RECT  22.817 40.032 22.921 40.056 ;
     RECT  22.205 33.936 23.533 33.96 ;
     RECT  22.021 0.096 23.717 0.12 ;
     RECT  22.885 42.432 23.785 43.08 ;
     RECT  22.453 32.832 23.797 32.856 ;
     RECT  23.533 33.936 23.797 34.056 ;
     RECT  22.853 1.728 23.932 31.272 ;
     RECT  23.932 1.68 24.008 31.272 ;
     RECT  23.797 32.832 24.008 34.2 ;
     RECT  22.921 38.496 24.008 40.056 ;
     RECT  23.965 41.184 24.008 41.208 ;
     RECT  24.008 1.68 24.037 41.208 ;
     RECT  23.785 42.432 24.037 43.176 ;
     RECT  24.037 0.144 24.133 0.168 ;
     RECT  24.133 0.144 24.229 0.6 ;
     RECT  24.037 1.68 24.304 43.176 ;
     RECT  24.229 0.144 24.325 0.696 ;
     RECT  24.304 1.68 24.325 25.128 ;
     RECT  24.325 0.144 24.419 25.128 ;
     RECT  24.304 37.008 24.481 43.176 ;
     RECT  24.419 0.576 24.563 25.128 ;
     RECT  24.304 26.352 24.581 34.776 ;
     RECT  24.481 37.632 24.659 43.176 ;
     RECT  24.581 31.968 24.689 34.776 ;
     RECT  24.581 26.352 24.725 30.696 ;
     RECT  24.689 33.936 24.869 34.776 ;
     RECT  24.725 26.352 25.193 29.592 ;
     RECT  24.869 33.936 25.337 34.2 ;
     RECT  24.659 38.496 25.445 43.176 ;
     RECT  24.563 0.576 25.477 0.648 ;
     RECT  24.563 1.728 25.585 25.128 ;
     RECT  25.193 26.352 25.585 29.496 ;
     RECT  24.725 30.672 25.585 30.696 ;
     RECT  24.689 31.968 25.585 32.952 ;
     RECT  25.477 0.096 25.669 0.648 ;
     RECT  25.585 1.728 25.669 29.496 ;
     RECT  25.585 30.672 25.669 32.952 ;
     RECT  25.669 0.096 26.237 29.496 ;
     RECT  25.445 38.496 26.237 41.88 ;
     RECT  26.237 0.096 26.345 24.552 ;
     RECT  25.669 32.16 26.485 32.952 ;
     RECT  25.337 33.936 26.485 33.96 ;
     RECT  26.237 25.536 26.521 29.496 ;
     RECT  25.669 30.672 26.521 30.744 ;
     RECT  26.345 0.096 26.771 24.456 ;
     RECT  26.485 32.16 26.821 33.96 ;
     RECT  25.445 43.104 26.981 43.176 ;
     RECT  26.771 0.096 26.993 0.216 ;
     RECT  26.237 41.04 27.02 41.88 ;
     RECT  26.981 42.96 27.02 43.176 ;
     RECT  26.521 25.536 27.025 30.744 ;
     RECT  26.821 31.728 27.025 33.96 ;
     RECT  26.993 0.096 27.029 0.12 ;
     RECT  27.025 25.536 27.299 33.96 ;
     RECT  27.02 41.04 27.353 43.176 ;
     RECT  27.353 41.04 27.731 43.08 ;
     RECT  27.299 25.536 27.889 29.496 ;
     RECT  27.731 41.856 27.923 43.08 ;
     RECT  26.771 1.68 27.925 24.456 ;
     RECT  27.889 25.44 27.925 29.496 ;
     RECT  27.923 41.856 28.073 41.88 ;
     RECT  28.261 0.576 28.349 0.6 ;
     RECT  27.299 30.72 28.429 33.96 ;
     RECT  28.429 30.48 28.537 33.96 ;
     RECT  28.349 0.576 28.549 0.696 ;
     RECT  27.925 1.68 28.549 29.496 ;
     RECT  28.549 0.576 28.645 29.496 ;
     RECT  28.645 0.096 28.757 29.496 ;
     RECT  26.237 38.496 28.861 40.056 ;
     RECT  28.825 41.088 28.861 41.112 ;
     RECT  28.757 0.144 28.973 29.496 ;
     RECT  28.973 1.728 29.077 29.496 ;
     RECT  28.537 30.48 29.077 34.728 ;
     RECT  28.861 38.496 29.221 41.112 ;
     RECT  28.973 0.144 29.267 0.552 ;
     RECT  29.221 38.496 29.293 41.688 ;
     RECT  29.029 36.288 29.329 36.312 ;
     RECT  27.923 42.864 29.363 43.08 ;
     RECT  29.077 1.728 29.408 34.728 ;
     RECT  29.329 36.288 29.408 36.552 ;
     RECT  29.293 38.496 29.408 41.736 ;
     RECT  29.267 0.144 29.651 0.168 ;
     RECT  29.363 42.864 29.701 43.032 ;
     RECT  29.408 1.728 29.704 41.736 ;
     RECT  29.701 42.816 29.843 43.032 ;
     RECT  29.704 36.528 30.131 41.736 ;
     RECT  30.131 36.528 30.227 41.016 ;
     RECT  30.227 36.528 30.419 36.552 ;
     RECT  30.227 37.632 30.611 41.016 ;
     RECT  30.611 37.632 30.707 40.488 ;
     RECT  30.716 42.192 30.803 42.216 ;
     RECT  30.757 0.192 30.853 0.216 ;
     RECT  30.853 0.096 30.947 0.216 ;
     RECT  29.704 1.728 30.949 32.856 ;
     RECT  29.704 33.936 30.949 35.352 ;
     RECT  30.947 0.096 31.133 0.12 ;
     RECT  30.707 37.632 31.283 40.056 ;
     RECT  30.949 1.728 31.379 35.352 ;
     RECT  31.379 1.728 31.429 34.68 ;
     RECT  31.429 1.152 31.565 34.68 ;
     RECT  31.565 1.728 31.593 34.68 ;
     RECT  30.853 42.768 31.813 43.08 ;
     RECT  31.593 28.608 31.853 34.68 ;
     RECT  31.283 38.208 31.925 40.056 ;
     RECT  31.593 1.728 31.997 27.624 ;
     RECT  31.813 42.192 32.029 43.08 ;
     RECT  32.029 42.192 32.209 43.128 ;
     RECT  31.909 0.576 32.213 0.648 ;
     RECT  31.925 38.496 32.293 40.056 ;
     RECT  32.209 41.184 32.293 41.208 ;
     RECT  31.853 31.248 32.389 34.68 ;
     RECT  32.389 31.248 32.533 34.728 ;
     RECT  31.997 25.92 32.78 27.624 ;
     RECT  31.853 28.608 32.78 29.496 ;
     RECT  32.533 31.248 32.897 34.776 ;
     RECT  32.293 38.496 32.897 41.208 ;
     RECT  32.78 25.92 33.077 29.496 ;
     RECT  32.897 31.344 33.109 34.776 ;
     RECT  32.209 42.192 33.491 43.176 ;
     RECT  33.077 26.064 33.505 29.496 ;
     RECT  33.505 26.064 33.793 29.784 ;
     RECT  33.109 31.344 33.901 35.352 ;
     RECT  31.997 1.728 33.973 24.264 ;
     RECT  33.901 31.344 33.973 35.496 ;
     RECT  33.491 42.624 34.067 43.176 ;
     RECT  33.793 26.064 34.165 29.832 ;
     RECT  33.973 31.344 34.165 35.88 ;
     RECT  33.973 1.728 34.189 24.456 ;
     RECT  32.677 0.096 34.213 0.168 ;
     RECT  34.213 0.096 34.517 0.6 ;
     RECT  34.165 26.064 34.585 35.88 ;
     RECT  32.897 41.04 34.585 41.208 ;
     RECT  34.189 1.728 34.808 24.936 ;
     RECT  34.585 26.064 34.808 36.024 ;
     RECT  32.897 38.496 34.808 40.056 ;
     RECT  34.585 41.04 34.808 41.64 ;
     RECT  34.808 1.728 35.104 41.64 ;
     RECT  35.104 38.496 35.123 41.64 ;
     RECT  34.067 42.72 35.161 43.176 ;
     RECT  35.104 36 35.219 36.936 ;
     RECT  34.517 0.096 35.267 0.456 ;
     RECT  35.219 36 35.267 36.024 ;
     RECT  35.267 0.096 35.363 0.216 ;
     RECT  35.161 42.192 35.411 43.176 ;
     RECT  35.104 1.728 35.459 31.224 ;
     RECT  35.363 0.096 35.713 0.12 ;
     RECT  35.104 32.496 36.137 34.776 ;
     RECT  36.137 33.936 36.281 34.776 ;
     RECT  35.123 38.496 36.349 41.016 ;
     RECT  35.459 31.2 36.457 31.224 ;
     RECT  35.459 1.728 36.515 29.448 ;
     RECT  36.349 38.496 36.673 41.64 ;
     RECT  35.411 42.768 36.673 43.176 ;
     RECT  36.613 0.576 36.709 0.6 ;
     RECT  36.457 31.2 36.781 31.416 ;
     RECT  36.137 32.496 36.781 32.856 ;
     RECT  36.781 31.2 36.805 32.856 ;
     RECT  36.673 38.496 36.821 43.176 ;
     RECT  36.709 0.576 36.857 0.648 ;
     RECT  36.821 38.496 36.965 42.792 ;
     RECT  36.805 30.528 37.249 32.856 ;
     RECT  36.281 33.936 37.249 33.96 ;
     RECT  36.515 1.728 37.283 28.824 ;
     RECT  37.249 30.528 37.397 33.96 ;
     RECT  36.965 38.496 37.427 42.264 ;
     RECT  36.857 0.576 37.745 0.6 ;
     RECT  37.283 27.456 37.757 28.824 ;
     RECT  37.427 38.496 37.811 42.216 ;
     RECT  37.745 0.096 37.829 0.6 ;
     RECT  37.397 30.528 37.957 31.128 ;
     RECT  37.829 0.576 38.012 0.6 ;
     RECT  37.283 1.728 38.012 26.424 ;
     RECT  38.012 0.576 38.045 26.424 ;
     RECT  38.045 1.104 38.099 26.424 ;
     RECT  37.811 38.496 38.099 41.832 ;
     RECT  37.397 32.304 38.437 33.96 ;
     RECT  38.365 37.008 38.448 37.032 ;
     RECT  38.448 36.96 38.449 37.032 ;
     RECT  37.757 27.648 38.509 28.824 ;
     RECT  38.509 27.648 38.513 28.968 ;
     RECT  38.449 36.96 38.557 36.984 ;
     RECT  38.099 38.496 38.581 41.016 ;
     RECT  38.581 38.16 38.665 41.016 ;
     RECT  38.513 27.84 38.765 28.968 ;
     RECT  38.099 1.728 38.797 26.424 ;
     RECT  37.957 30.24 38.797 31.128 ;
     RECT  38.437 32.256 38.797 33.96 ;
     RECT  38.797 30.24 38.833 33.96 ;
     RECT  38.833 30.096 39.155 33.96 ;
     RECT  39.155 30.096 39.197 31.272 ;
     RECT  39.373 0.096 39.457 0.12 ;
     RECT  38.797 1.728 39.733 26.664 ;
     RECT  38.765 27.84 39.733 28.824 ;
     RECT  38.665 38.496 40.057 41.016 ;
     RECT  39.869 0.576 40.141 0.6 ;
     RECT  39.733 1.728 40.208 28.824 ;
     RECT  39.197 30.096 40.208 30.792 ;
     RECT  39.155 32.256 40.208 33.96 ;
     RECT  40.057 38.496 40.208 41.208 ;
     RECT  40.208 1.728 40.504 41.208 ;
     RECT  40.504 1.728 40.529 25.272 ;
     RECT  40.529 1.728 40.565 25.224 ;
     RECT  40.565 24.912 40.601 25.224 ;
     RECT  40.504 28.8 40.643 30.6 ;
     RECT  40.504 38.496 40.781 41.208 ;
     RECT  40.165 43.056 41.033 43.08 ;
     RECT  40.504 26.352 41.141 27.192 ;
     RECT  40.565 1.728 41.461 23.688 ;
     RECT  41.605 0.576 41.689 0.6 ;
     RECT  41.461 1.632 41.747 23.688 ;
     RECT  40.601 25.056 41.821 25.224 ;
     RECT  42.073 0.528 42.181 0.552 ;
     RECT  41.747 1.68 42.217 23.688 ;
     RECT  41.821 25.008 42.217 25.224 ;
     RECT  41.141 26.352 42.217 26.376 ;
     RECT  42.217 1.68 42.289 25.224 ;
     RECT  40.781 38.496 42.289 41.016 ;
     RECT  42.289 1.68 42.325 25.32 ;
     RECT  42.217 26.352 42.325 27.336 ;
     RECT  40.643 30.576 42.469 30.6 ;
     RECT  42.325 1.68 42.509 27.336 ;
     RECT  42.469 30.576 42.617 30.792 ;
     RECT  42.181 0.096 42.757 0.552 ;
     RECT  42.289 38.496 42.829 41.88 ;
     RECT  42.509 26.352 43.297 27.336 ;
     RECT  40.643 28.8 43.297 29.544 ;
     RECT  42.757 0.096 43.417 0.6 ;
     RECT  43.417 0.096 43.475 0.552 ;
     RECT  42.509 1.68 43.697 25.32 ;
     RECT  43.697 25.056 43.801 25.32 ;
     RECT  43.297 26.352 43.801 29.544 ;
     RECT  43.801 25.056 43.811 29.544 ;
     RECT  43.811 28.128 43.852 29.544 ;
     RECT  43.475 0.096 44.051 0.456 ;
     RECT  42.829 38.496 44.053 42.12 ;
     RECT  40.504 32.832 44.149 33.96 ;
     RECT  42.617 30.576 44.195 30.6 ;
     RECT  44.053 38.496 44.627 42.168 ;
     RECT  44.627 42.096 44.723 42.168 ;
     RECT  43.811 25.056 44.737 27.048 ;
     RECT  44.723 42.144 44.765 42.168 ;
     RECT  43.697 1.68 44.845 23.784 ;
     RECT  44.765 42.144 44.849 43.08 ;
     RECT  44.449 0.528 44.917 0.696 ;
     RECT  44.845 1.68 44.917 23.832 ;
     RECT  44.737 24.96 44.917 27.048 ;
     RECT  44.917 0.528 44.989 23.832 ;
     RECT  44.917 24.96 44.989 27.672 ;
     RECT  44.989 0.528 45.233 27.672 ;
     RECT  43.852 28.8 45.233 29.544 ;
     RECT  45.233 0.528 45.587 29.544 ;
     RECT  45.587 1.008 45.608 29.544 ;
     RECT  44.629 30.72 45.608 30.744 ;
     RECT  44.149 31.92 45.608 33.96 ;
     RECT  44.627 38.496 45.608 41.016 ;
     RECT  45.608 1.008 45.733 41.052 ;
     RECT  44.849 42.144 45.733 42.168 ;
     RECT  45.733 1.008 45.829 42.168 ;
     RECT  45.829 1.008 45.857 43.032 ;
     RECT  45.857 1.008 45.904 41.64 ;
     RECT  45.857 43.008 45.925 43.032 ;
     RECT  45.904 36 46.019 36.024 ;
     RECT  45.925 43.008 46.073 43.08 ;
     RECT  46.073 43.008 46.115 43.032 ;
     RECT  45.904 33.936 46.397 34.824 ;
     RECT  45.904 1.008 46.469 29.352 ;
     RECT  46.469 1.008 46.573 25.272 ;
     RECT  45.904 38.208 46.961 41.64 ;
     RECT  46.469 26.256 47.005 29.352 ;
     RECT  45.904 30.384 47.005 32.856 ;
     RECT  46.961 38.208 47.153 42.168 ;
     RECT  46.573 0.48 47.225 25.272 ;
     RECT  47.225 20.736 47.509 25.272 ;
     RECT  47.005 26.256 47.509 32.856 ;
     RECT  47.153 42.096 47.693 42.168 ;
     RECT  47.509 20.736 47.987 32.856 ;
     RECT  47.153 38.208 47.989 41.016 ;
     RECT  47.989 37.92 48.076 41.016 ;
     RECT  47.987 20.736 48.193 27.672 ;
     RECT  47.225 0.48 48.293 19.608 ;
     RECT  48.293 0.096 48.377 19.608 ;
     RECT  48.377 0.192 48.445 19.608 ;
     RECT  48.193 20.688 48.445 27.672 ;
     RECT  47.693 42.144 48.956 42.168 ;
     RECT  48.076 38.208 48.985 41.016 ;
     RECT  48.956 42.144 49.089 43.08 ;
     RECT  47.987 28.8 49.129 32.856 ;
     RECT  48.985 38.208 49.277 41.064 ;
     RECT  48.697 37.056 49.285 37.08 ;
     RECT  49.277 38.208 49.285 41.016 ;
     RECT  49.285 37.056 49.388 41.016 ;
     RECT  49.129 28.704 49.475 32.856 ;
     RECT  49.388 36.912 49.477 41.016 ;
     RECT  49.089 42.144 49.715 42.216 ;
     RECT  49.475 31.344 49.907 32.856 ;
     RECT  49.477 36.528 49.964 41.016 ;
     RECT  46.397 33.936 49.993 33.96 ;
     RECT  49.475 28.704 50.492 30.168 ;
     RECT  49.964 36.432 50.533 41.016 ;
     RECT  49.993 33.936 50.749 34.728 ;
     RECT  50.749 33.888 50.785 34.728 ;
     RECT  50.785 33.888 50.821 34.776 ;
     RECT  50.533 36.432 50.821 41.688 ;
     RECT  48.445 0.192 50.869 27.672 ;
     RECT  50.869 0.144 51.008 27.672 ;
     RECT  50.492 28.704 51.008 30.264 ;
     RECT  49.907 31.632 51.008 32.856 ;
     RECT  50.821 33.888 51.008 41.688 ;
     RECT  50.869 43.008 51.059 43.032 ;
     RECT  51.008 0.144 51.155 41.688 ;
     RECT  51.155 0.192 51.304 41.688 ;
     RECT  51.304 0.192 51.443 25.512 ;
     RECT  51.304 26.64 51.545 30.168 ;
     RECT  51.545 26.64 51.581 30.072 ;
     RECT  51.581 26.64 51.587 29.64 ;
     RECT  51.443 0.384 51.869 25.512 ;
     RECT  51.587 27.168 52.229 29.64 ;
     RECT  51.304 31.728 52.261 41.688 ;
     RECT  52.261 31.728 52.301 42.168 ;
     RECT  52.301 31.728 52.333 35.592 ;
     RECT  51.869 0.384 52.499 25.128 ;
     RECT  52.499 0.432 52.883 25.128 ;
     RECT  52.229 27.168 52.985 29.4 ;
     RECT  52.883 1.728 53.057 25.128 ;
     RECT  52.985 27.168 53.089 27.672 ;
     RECT  52.333 31.152 53.201 35.592 ;
     RECT  52.985 28.704 53.267 29.4 ;
     RECT  53.201 31.152 53.269 32.856 ;
     RECT  53.201 33.936 53.269 35.592 ;
     RECT  52.301 36.624 53.269 42.168 ;
     RECT  53.269 31.056 53.413 32.856 ;
     RECT  53.089 26.496 53.525 27.672 ;
     RECT  53.057 21.072 53.561 25.128 ;
     RECT  53.413 30.864 53.561 32.856 ;
     RECT  52.883 0.432 53.593 0.552 ;
     RECT  53.267 28.8 53.593 29.4 ;
     RECT  53.561 21.216 53.633 25.128 ;
     RECT  53.269 33.936 53.669 42.168 ;
     RECT  53.633 21.216 53.741 24.744 ;
     RECT  53.741 21.216 53.777 24.648 ;
     RECT  53.561 31.056 53.957 32.856 ;
     RECT  53.777 21.216 54.029 24.552 ;
     RECT  53.669 36.384 54.029 42.168 ;
     RECT  53.593 28.8 54.061 29.592 ;
     RECT  53.957 31.056 54.173 31.704 ;
     RECT  54.029 42.144 54.181 42.168 ;
     RECT  53.525 27.408 54.236 27.672 ;
     RECT  54.061 28.8 54.236 29.688 ;
     RECT  54.029 21.216 54.317 24.12 ;
     RECT  53.593 0.096 54.323 0.552 ;
     RECT  54.229 26.208 54.349 26.232 ;
     RECT  54.181 42.144 54.389 43.08 ;
     RECT  54.236 27.408 54.529 29.688 ;
     RECT  54.317 23.616 54.605 24.12 ;
     RECT  54.349 26.016 54.637 26.232 ;
     RECT  54.605 23.616 54.641 23.976 ;
     RECT  53.957 32.832 54.745 32.856 ;
     RECT  53.669 33.936 54.745 34.968 ;
     RECT  54.317 21.216 54.749 22.248 ;
     RECT  54.029 36.384 54.781 41.016 ;
     RECT  54.389 42.144 54.821 43.032 ;
     RECT  54.637 25.872 54.853 26.232 ;
     RECT  54.529 27.216 54.853 29.688 ;
     RECT  54.853 25.872 54.889 29.688 ;
     RECT  53.057 1.728 55.037 20.04 ;
     RECT  54.323 0.096 55.109 0.12 ;
     RECT  54.173 31.152 55.145 31.704 ;
     RECT  54.889 25.728 55.213 29.688 ;
     RECT  54.745 32.832 55.285 34.968 ;
     RECT  54.781 36.288 55.285 41.016 ;
     RECT  55.145 31.344 55.573 31.704 ;
     RECT  55.285 32.832 55.573 41.016 ;
     RECT  54.821 43.008 55.619 43.032 ;
     RECT  55.753 0.528 55.859 0.552 ;
     RECT  55.213 25.728 56.329 30.168 ;
     RECT  55.573 31.344 56.329 41.016 ;
     RECT  56.329 25.728 56.365 41.016 ;
     RECT  55.037 1.728 56.408 19.608 ;
     RECT  54.749 21.216 56.408 22.104 ;
     RECT  54.641 23.616 56.408 23.688 ;
     RECT  56.365 25.728 56.408 41.208 ;
     RECT  56.408 1.728 56.448 41.208 ;
     RECT  56.448 1.728 56.677 41.256 ;
     RECT  56.677 1.152 56.704 41.256 ;
     RECT  56.704 32.256 56.869 41.256 ;
     RECT  56.704 1.152 56.909 19.608 ;
     RECT  56.869 32.256 56.909 42.168 ;
     RECT  56.909 42.096 57.337 42.168 ;
     RECT  57.337 42.096 57.421 43.08 ;
     RECT  56.909 32.256 57.665 41.016 ;
     RECT  57.665 40.752 57.985 41.016 ;
     RECT  57.421 42.096 57.985 42.168 ;
     RECT  57.665 32.256 58.021 39.576 ;
     RECT  56.704 23.616 58.133 23.64 ;
     RECT  58.021 32.064 58.277 39.576 ;
     RECT  56.581 0.096 58.345 0.12 ;
     RECT  58.277 39.072 58.421 39.576 ;
     RECT  56.704 21.216 58.493 21.816 ;
     RECT  56.704 25.728 58.529 30.84 ;
     RECT  58.345 0.096 58.547 0.168 ;
     RECT  58.277 32.064 58.556 37.752 ;
     RECT  58.556 31.872 58.601 37.752 ;
     RECT  58.601 31.872 58.643 36.456 ;
     RECT  58.547 0.144 58.693 0.168 ;
     RECT  56.909 1.728 58.741 19.608 ;
     RECT  58.421 39.408 58.745 39.576 ;
     RECT  58.745 39.552 58.781 39.576 ;
     RECT  58.693 0.144 58.835 0.6 ;
     RECT  58.643 32.064 58.883 36.456 ;
     RECT  58.529 25.728 58.925 26.472 ;
     RECT  58.529 27.6 58.961 30.84 ;
     RECT  58.883 32.064 59.105 35.976 ;
     RECT  58.601 37.44 59.105 37.752 ;
     RECT  59.105 37.44 59.141 37.464 ;
     RECT  57.985 40.752 59.213 42.168 ;
     RECT  58.835 0.528 59.389 0.6 ;
     RECT  58.741 1.68 59.389 19.608 ;
     RECT  59.105 32.064 59.393 35.544 ;
     RECT  59.213 40.752 59.42 41.016 ;
     RECT  59.389 0.528 59.429 19.608 ;
     RECT  59.429 0.528 59.573 18.264 ;
     RECT  58.961 30.624 59.605 30.84 ;
     RECT  59.393 32.064 59.605 35.352 ;
     RECT  59.429 19.584 59.645 19.608 ;
     RECT  58.961 27.6 59.645 29.064 ;
     RECT  59.605 30.624 59.645 35.352 ;
     RECT  59.645 27.6 59.677 28.824 ;
     RECT  59.42 40.416 59.681 41.016 ;
     RECT  59.573 0.528 59.753 18.024 ;
     RECT  59.645 30.816 59.789 35.352 ;
     RECT  59.753 0.528 59.795 16.776 ;
     RECT  59.677 26.64 59.825 28.824 ;
     RECT  59.795 0.528 59.891 0.552 ;
     RECT  59.789 30.816 59.897 33.96 ;
     RECT  59.897 32.064 59.969 33.96 ;
     RECT  59.825 26.688 60.113 28.824 ;
     RECT  59.969 32.208 60.113 33.96 ;
     RECT  60.113 26.688 60.149 26.712 ;
     RECT  60.113 32.208 60.185 33.24 ;
     RECT  59.789 35.328 60.257 35.352 ;
     RECT  59.897 30.816 60.329 30.84 ;
     RECT  59.795 1.632 60.365 16.776 ;
     RECT  58.493 21.216 60.365 21.24 ;
     RECT  60.365 1.632 60.371 15.528 ;
     RECT  59.213 42.096 60.401 42.168 ;
     RECT  60.371 1.728 60.473 15.528 ;
     RECT  60.113 27.744 60.545 28.824 ;
     RECT  60.185 32.208 60.545 32.232 ;
     RECT  59.929 0.096 60.617 0.12 ;
     RECT  60.545 28.512 60.617 28.824 ;
     RECT  59.681 40.464 60.617 41.016 ;
     RECT  60.617 28.8 60.653 28.824 ;
     RECT  60.473 1.728 60.659 15.336 ;
     RECT  60.659 2.256 60.755 15.336 ;
     RECT  60.755 2.784 60.761 15.336 ;
     RECT  60.365 16.704 60.865 16.776 ;
     RECT  60.401 42.144 60.949 42.168 ;
     RECT  60.761 6.24 61.513 15.336 ;
     RECT  60.865 16.704 61.513 17.64 ;
     RECT  61.513 6.24 61.657 17.64 ;
     RECT  60.761 2.784 61.808 5.256 ;
     RECT  61.657 6.24 61.808 18.552 ;
     RECT  60.185 33.216 61.808 33.24 ;
     RECT  60.805 39.312 61.808 39.336 ;
     RECT  60.617 40.848 61.808 41.016 ;
     RECT  61.808 2.148 61.912 41.052 ;
     RECT  61.912 2.148 62.104 40.782 ;
     RECT  61.405 1.008 62.809 1.032 ;
     RECT  62.104 2.148 62.809 3.624 ;
     RECT  62.809 1.008 63.025 3.624 ;
     RECT  62.104 5.232 63.133 5.256 ;
     RECT  63.133 5.136 63.169 5.256 ;
     RECT  63.025 0.72 63.241 3.624 ;
     RECT  63.169 4.944 63.241 5.448 ;
     RECT  62.104 6.576 63.241 18.792 ;
     RECT  63.241 0.72 63.781 18.792 ;
     RECT  63.781 0.72 64.764 19.08 ;
    LAYER M5 ;
     RECT  0.72 0.016 60.744 1.763 ;
     RECT  0.72 1.763 19.08 1.811 ;
     RECT  20.208 1.763 45.96 1.811 ;
     RECT  20.208 1.811 45.912 1.859 ;
     RECT  20.208 1.859 38.184 1.907 ;
     RECT  17.232 1.811 19.08 1.955 ;
     RECT  37.104 1.907 37.128 1.955 ;
     RECT  39.216 1.859 45.912 1.955 ;
     RECT  20.208 1.907 36.072 2.099 ;
     RECT  61.8 2.137 61.92 2.151 ;
     RECT  22.224 2.099 36.072 2.195 ;
     RECT  23.088 2.195 28.2 2.243 ;
     RECT  38.16 1.907 38.184 2.291 ;
     RECT  39.792 1.955 45.912 2.291 ;
     RECT  47.184 1.763 60.744 2.291 ;
     RECT  23.088 2.243 26.52 2.339 ;
     RECT  27.504 2.243 28.2 2.339 ;
     RECT  47.184 2.291 60.552 2.339 ;
     RECT  0.72 1.811 15.912 2.915 ;
     RECT  20.208 2.099 21.192 2.963 ;
     RECT  29.28 2.195 36.072 2.963 ;
     RECT  29.28 2.963 33.336 3.059 ;
     RECT  6.864 2.915 15.912 3.109 ;
     RECT  17.232 1.955 18.912 3.109 ;
     RECT  20.208 2.963 20.52 3.109 ;
     RECT  6.864 3.109 20.52 3.203 ;
     RECT  28.08 2.339 28.2 3.301 ;
     RECT  29.28 3.059 30.456 3.301 ;
     RECT  34.56 2.963 36.072 3.301 ;
     RECT  48 2.339 60.552 3.397 ;
     RECT  0.72 2.915 5.448 3.443 ;
     RECT  47.664 3.397 60.552 3.443 ;
     RECT  23.28 2.339 26.52 3.445 ;
     RECT  23.28 3.445 27.048 3.491 ;
     RECT  28.08 3.301 30.456 3.539 ;
     RECT  61.8 2.151 62.112 3.541 ;
     RECT  1.2 3.443 2.712 3.635 ;
     RECT  3.888 3.443 5.448 3.877 ;
     RECT  6.864 3.203 16.536 3.877 ;
     RECT  47.664 3.443 52.2 3.877 ;
     RECT  42.576 2.291 45.912 3.925 ;
     RECT  46.896 3.877 52.2 3.925 ;
     RECT  1.872 3.635 2.712 4.019 ;
     RECT  3.888 3.877 16.536 4.019 ;
     RECT  53.232 3.443 59.688 4.019 ;
     RECT  1.968 4.019 2.712 4.067 ;
     RECT  17.76 3.203 20.52 4.067 ;
     RECT  39.792 2.291 41.064 4.067 ;
     RECT  28.944 3.539 30.456 4.213 ;
     RECT  31.728 3.059 33.336 4.213 ;
     RECT  28.944 4.213 33.336 4.261 ;
     RECT  34.56 3.301 36.504 4.261 ;
     RECT  24 3.491 27.048 4.405 ;
     RECT  3.888 4.019 9.288 4.595 ;
     RECT  10.8 4.019 16.536 4.595 ;
     RECT  28.944 4.261 36.504 4.595 ;
     RECT  40.2 4.067 41.064 4.595 ;
     RECT  42.576 3.925 52.2 4.595 ;
     RECT  43.008 4.595 52.2 4.691 ;
     RECT  53.28 4.019 59.688 4.837 ;
     RECT  44.352 4.691 52.2 5.123 ;
     RECT  5.04 4.595 9.288 5.125 ;
     RECT  24 4.405 27.864 5.125 ;
     RECT  28.944 4.595 30.888 5.125 ;
     RECT  37.968 3.637 37.992 5.125 ;
     RECT  3.888 4.595 3.912 5.171 ;
     RECT  11.376 4.595 14.136 5.171 ;
     RECT  5.04 5.125 9.336 5.219 ;
     RECT  37.968 5.125 38.04 5.315 ;
     RECT  40.2 4.595 40.872 5.315 ;
     RECT  22.608 4.405 22.632 5.461 ;
     RECT  24 5.125 30.888 5.461 ;
     RECT  0.144 5.221 0.168 5.507 ;
     RECT  5.904 5.219 9.336 5.555 ;
     RECT  15.696 4.595 16.536 5.653 ;
     RECT  15.264 5.653 16.536 5.747 ;
     RECT  5.904 5.555 9.288 5.795 ;
     RECT  12.768 5.171 13.608 5.795 ;
     RECT  2.4 4.067 2.712 6.037 ;
     RECT  12.768 5.795 13.512 6.133 ;
     RECT  44.64 5.123 52.2 6.133 ;
     RECT  53.28 4.837 59.784 6.133 ;
     RECT  2.4 6.037 3 6.179 ;
     RECT  5.904 5.795 9.144 6.227 ;
     RECT  22.608 5.461 30.888 6.229 ;
     RECT  31.968 4.595 36.504 6.229 ;
     RECT  5.904 6.227 9 6.277 ;
     RECT  11.376 5.171 11.4 6.323 ;
     RECT  43.008 4.691 43.368 6.323 ;
     RECT  20.88 5.989 20.904 6.661 ;
     RECT  22.608 6.229 36.504 6.709 ;
     RECT  37.968 5.315 37.992 6.709 ;
     RECT  22.608 6.709 37.992 6.805 ;
     RECT  21.888 6.805 37.992 6.851 ;
     RECT  64.608 6.565 64.632 6.851 ;
     RECT  17.76 4.067 19.752 6.899 ;
     RECT  21.888 6.851 30.888 7.043 ;
     RECT  15.264 5.747 15.288 7.285 ;
     RECT  15.264 7.285 15.816 7.429 ;
     RECT  17.76 6.899 19.656 7.475 ;
     RECT  44.64 6.133 59.784 7.475 ;
     RECT  14.688 7.429 15.816 7.765 ;
     RECT  17.76 7.475 19.56 7.861 ;
     RECT  17.712 7.861 19.56 7.957 ;
     RECT  43.008 6.323 43.032 8.003 ;
     RECT  21.888 7.043 30.744 8.099 ;
     RECT  40.2 5.315 40.512 8.389 ;
     RECT  39.264 8.389 40.512 8.531 ;
     RECT  29.088 8.099 30.744 8.771 ;
     RECT  0.144 7.669 0.168 8.819 ;
     RECT  5.136 6.277 9 9.013 ;
     RECT  5.136 9.013 9.192 9.109 ;
     RECT  44.736 7.475 59.784 9.157 ;
     RECT  41.856 6.229 41.88 9.253 ;
     RECT  12.624 6.133 13.512 9.395 ;
     RECT  44.736 9.157 59.832 9.491 ;
     RECT  40.2 8.531 40.512 9.493 ;
     RECT  41.856 9.253 41.976 9.635 ;
     RECT  4.992 9.109 9.192 9.685 ;
     RECT  39.888 9.493 40.512 9.685 ;
     RECT  41.856 9.635 41.88 9.685 ;
     RECT  31.968 6.851 37.992 9.731 ;
     RECT  4.992 9.685 9.24 9.733 ;
     RECT  0.144 9.829 0.168 10.019 ;
     RECT  29.232 8.771 30.744 10.069 ;
     RECT  29.088 10.069 30.744 10.211 ;
     RECT  4.32 9.733 9.24 10.213 ;
     RECT  29.232 10.211 30.744 10.261 ;
     RECT  39.888 9.685 41.88 10.307 ;
     RECT  44.736 9.491 59.784 10.307 ;
     RECT  11.04 9.349 11.064 10.597 ;
     RECT  4.32 10.213 9.384 10.691 ;
     RECT  41.856 10.307 41.88 10.883 ;
     RECT  11.04 10.597 11.688 10.931 ;
     RECT  2.4 6.179 2.712 11.029 ;
     RECT  5.136 10.691 9.384 11.125 ;
     RECT  2.4 11.029 3.576 11.219 ;
     RECT  5.136 11.125 10.296 11.267 ;
     RECT  29.232 10.261 30.84 11.411 ;
     RECT  29.232 11.411 30.744 11.413 ;
     RECT  31.968 9.731 33.528 11.555 ;
     RECT  28.944 11.413 30.744 11.747 ;
     RECT  14.688 7.765 16.104 12.275 ;
     RECT  20.832 6.661 20.904 12.517 ;
     RECT  21.888 8.099 27.864 12.517 ;
     RECT  29.28 11.747 30.744 12.517 ;
     RECT  31.968 11.555 33.384 12.517 ;
     RECT  5.136 11.267 9.816 12.757 ;
     RECT  11.664 10.931 11.688 12.901 ;
     RECT  11.424 12.901 11.688 12.997 ;
     RECT  11.424 12.997 11.736 13.043 ;
     RECT  5.04 12.757 9.816 13.091 ;
     RECT  29.28 12.517 33.384 13.141 ;
     RECT  29.184 13.141 33.384 13.285 ;
     RECT  14.688 12.275 15.72 13.333 ;
     RECT  44.736 10.307 58.2 13.525 ;
     RECT  59.28 10.307 59.784 13.525 ;
     RECT  0.144 11.221 0.168 13.619 ;
     RECT  44.736 13.525 59.784 13.667 ;
     RECT  29.136 13.285 33.384 13.715 ;
     RECT  59.28 13.667 59.784 13.715 ;
     RECT  44.736 13.667 58.2 13.861 ;
     RECT  29.184 13.715 33.384 14.003 ;
     RECT  42.864 11.365 42.888 14.099 ;
     RECT  31.968 14.003 33.384 14.197 ;
     RECT  34.56 9.731 37.992 14.197 ;
     RECT  39.888 10.307 40.512 14.389 ;
     RECT  39.888 14.389 40.728 14.531 ;
     RECT  17.472 7.957 19.56 14.629 ;
     RECT  14.688 13.333 16.152 14.821 ;
     RECT  17.232 14.629 19.56 14.821 ;
     RECT  29.184 14.003 30.504 14.821 ;
     RECT  14.688 14.821 19.56 14.917 ;
     RECT  44.688 13.861 58.2 15.109 ;
     RECT  59.424 13.715 59.784 15.251 ;
     RECT  28.992 14.821 30.504 15.395 ;
     RECT  11.712 13.043 11.736 16.019 ;
     RECT  39.888 14.531 40.632 16.019 ;
     RECT  13.056 9.395 13.512 16.213 ;
     RECT  14.688 14.917 19.608 16.213 ;
     RECT  29.184 15.395 30.504 16.693 ;
     RECT  13.056 16.213 19.608 16.789 ;
     RECT  42.048 16.501 42.072 16.981 ;
     RECT  5.136 13.091 9.816 17.029 ;
     RECT  12.24 16.789 19.608 17.077 ;
     RECT  20.832 12.517 27.864 17.077 ;
     RECT  39.888 16.019 40.512 17.077 ;
     RECT  42.048 16.981 42.552 17.077 ;
     RECT  28.896 16.693 30.504 17.123 ;
     RECT  31.968 14.197 37.992 17.267 ;
     RECT  39.888 17.077 42.552 17.315 ;
     RECT  44.592 15.109 58.2 17.315 ;
     RECT  31.968 17.267 33.384 17.411 ;
     RECT  29.4 17.123 30.504 17.507 ;
     RECT  12.24 17.077 27.864 17.605 ;
     RECT  0.144 17.461 0.168 17.651 ;
     RECT  12.24 17.605 28.152 18.179 ;
     RECT  41.664 17.315 42.072 18.179 ;
     RECT  31.968 17.411 33.336 18.227 ;
     RECT  59.424 15.251 59.592 18.275 ;
     RECT  12.384 18.179 28.152 18.371 ;
     RECT  20.832 18.371 28.152 18.805 ;
     RECT  29.4 17.507 29.712 18.805 ;
     RECT  12.384 18.371 19.608 18.899 ;
     RECT  20.832 18.805 29.712 18.947 ;
     RECT  44.592 17.315 45.912 18.947 ;
     RECT  30.72 17.653 30.744 19.235 ;
     RECT  44.736 18.947 45.912 19.379 ;
     RECT  14.688 18.899 19.608 19.381 ;
     RECT  20.832 18.947 28.152 19.381 ;
     RECT  41.664 18.179 41.688 19.475 ;
     RECT  14.688 19.381 28.152 19.859 ;
     RECT  12.384 18.899 13.512 19.909 ;
     RECT  14.688 19.859 19.608 19.909 ;
     RECT  39.888 17.315 40.512 19.909 ;
     RECT  45.168 19.379 45.912 20.341 ;
     RECT  46.896 17.315 58.2 20.341 ;
     RECT  12.384 19.909 19.608 20.387 ;
     RECT  2.4 11.219 2.712 20.389 ;
     RECT  39.36 19.909 40.512 20.579 ;
     RECT  4.704 17.029 9.816 20.629 ;
     RECT  20.832 19.859 28.152 20.819 ;
     RECT  2.4 20.389 2.808 20.821 ;
     RECT  0.144 20.293 0.168 21.059 ;
     RECT  29.4 18.947 29.712 21.109 ;
     RECT  12.384 20.387 16.296 21.157 ;
     RECT  40.2 20.579 40.512 21.205 ;
     RECT  28.896 21.109 29.712 21.251 ;
     RECT  40.2 21.205 41.064 21.347 ;
     RECT  12.048 21.157 16.296 21.395 ;
     RECT  2.4 20.821 3.576 21.493 ;
     RECT  4.704 20.629 10.344 21.493 ;
     RECT  2.4 21.493 10.344 21.731 ;
     RECT  20.832 20.819 27.864 21.973 ;
     RECT  34.56 17.267 37.992 22.069 ;
     RECT  20.64 21.973 27.864 22.117 ;
     RECT  12.048 21.395 13.512 22.307 ;
     RECT  12.24 22.307 13.512 22.453 ;
     RECT  0.144 22.357 0.168 22.547 ;
     RECT  2.4 21.731 3.576 22.741 ;
     RECT  4.704 21.731 10.344 22.741 ;
     RECT  12.24 22.453 13.656 22.787 ;
     RECT  17.472 20.387 19.608 22.789 ;
     RECT  20.592 22.117 27.864 22.789 ;
     RECT  2.4 22.741 10.344 22.883 ;
     RECT  2.4 22.883 3.576 22.931 ;
     RECT  12.48 22.787 13.656 22.931 ;
     RECT  31.968 18.227 33.144 22.933 ;
     RECT  31.296 22.933 33.144 23.123 ;
     RECT  39.024 22.405 39.048 23.171 ;
     RECT  42.384 23.317 42.408 23.413 ;
     RECT  43.824 22.597 43.848 23.461 ;
     RECT  45.168 20.341 58.2 23.461 ;
     RECT  43.824 23.461 58.2 23.557 ;
     RECT  42.336 23.413 42.408 23.605 ;
     RECT  43.392 23.557 58.2 23.605 ;
     RECT  42.336 23.605 58.2 23.795 ;
     RECT  31.344 23.123 33.144 23.891 ;
     RECT  45.12 23.795 58.2 23.939 ;
     RECT  34.128 22.069 37.992 23.987 ;
     RECT  45.168 23.939 58.2 23.987 ;
     RECT  17.472 22.789 27.864 24.659 ;
     RECT  42.336 23.795 43.848 24.851 ;
     RECT  20.832 24.659 27.864 24.901 ;
     RECT  29.4 21.251 29.712 24.901 ;
     RECT  45.168 23.987 45.912 24.949 ;
     RECT  46.896 23.987 58.2 24.949 ;
     RECT  20.832 24.901 30.168 25.043 ;
     RECT  29.4 25.043 30.168 25.091 ;
     RECT  45.168 24.949 58.2 25.093 ;
     RECT  14.688 21.395 16.296 25.237 ;
     RECT  17.472 24.659 19.608 25.237 ;
     RECT  20.832 25.043 28.2 25.571 ;
     RECT  45.024 25.093 58.2 25.619 ;
     RECT  42.432 24.851 43.848 25.715 ;
     RECT  27.84 25.571 28.2 26.101 ;
     RECT  34.56 23.987 37.992 26.101 ;
     RECT  40.2 21.347 40.512 26.101 ;
     RECT  43.392 25.715 43.848 26.149 ;
     RECT  45.024 25.619 45.912 26.149 ;
     RECT  31.968 23.891 33.144 26.197 ;
     RECT  34.368 26.101 37.992 26.197 ;
     RECT  27.84 26.101 28.392 26.245 ;
     RECT  29.4 25.091 29.712 26.245 ;
     RECT  31.968 26.197 37.992 26.579 ;
     RECT  39.6 26.101 40.512 26.629 ;
     RECT  46.896 25.619 58.2 26.771 ;
     RECT  43.392 26.149 45.912 27.155 ;
     RECT  14.688 25.237 19.608 27.205 ;
     RECT  20.832 25.571 26.52 27.205 ;
     RECT  59.472 18.275 59.592 27.205 ;
     RECT  14.688 27.205 26.52 27.349 ;
     RECT  27.84 26.245 29.712 27.349 ;
     RECT  45.168 27.155 45.912 27.349 ;
     RECT  46.896 26.771 48.216 27.349 ;
     RECT  59.472 27.205 59.976 27.779 ;
     RECT  39.312 26.629 40.512 27.875 ;
     RECT  14.688 27.349 29.712 28.115 ;
     RECT  43.392 27.155 44.184 28.117 ;
     RECT  31.968 26.579 36.84 28.501 ;
     RECT  59.472 27.779 59.592 28.931 ;
     RECT  20.832 28.115 29.712 28.933 ;
     RECT  31.536 28.501 36.84 29.027 ;
     RECT  45.168 27.349 48.216 29.075 ;
     RECT  12.48 22.931 13.512 29.077 ;
     RECT  40.2 27.875 40.512 29.077 ;
     RECT  20.832 28.933 30.024 29.171 ;
     RECT  31.536 29.027 35.448 29.171 ;
     RECT  36.48 29.027 36.84 29.459 ;
     RECT  43.344 28.117 44.184 29.555 ;
     RECT  20.832 29.171 26.52 30.181 ;
     RECT  28.08 29.171 30.024 30.181 ;
     RECT  31.968 29.171 35.448 30.181 ;
     RECT  4.704 22.883 10.344 30.229 ;
     RECT  12.144 29.077 13.512 30.229 ;
     RECT  31.296 30.181 35.448 30.275 ;
     RECT  37.92 26.579 37.992 30.275 ;
     RECT  40.2 29.077 40.632 30.467 ;
     RECT  36.816 29.459 36.84 30.563 ;
     RECT  46.896 29.075 48.216 30.563 ;
     RECT  14.688 28.115 19.608 30.709 ;
     RECT  14.688 30.709 19.752 30.757 ;
     RECT  31.296 30.275 35.304 30.803 ;
     RECT  49.44 26.771 58.2 30.803 ;
     RECT  49.872 30.803 58.2 31.379 ;
     RECT  14.688 30.757 19.848 31.381 ;
     RECT  20.832 30.181 30.024 31.381 ;
     RECT  46.896 30.563 47.976 31.619 ;
     RECT  50.592 31.379 58.2 31.811 ;
     RECT  51 31.811 58.2 31.861 ;
     RECT  59.568 28.931 59.592 31.861 ;
     RECT  14.688 31.381 30.024 31.955 ;
     RECT  39.12 30.949 39.144 31.955 ;
     RECT  43.392 29.555 44.184 31.955 ;
     RECT  51 31.861 59.592 32.243 ;
     RECT  14.688 31.955 29.712 32.531 ;
     RECT  47.952 31.619 47.976 32.771 ;
     RECT  31.968 30.803 35.304 32.917 ;
     RECT  31.584 32.917 35.304 33.013 ;
     RECT  61.008 3.541 62.112 33.251 ;
     RECT  51 32.243 58.632 33.253 ;
     RECT  51 33.253 59.352 33.299 ;
     RECT  31.056 33.013 35.304 33.395 ;
     RECT  4.704 30.229 13.512 33.445 ;
     RECT  2.4 22.931 2.712 33.637 ;
     RECT  51 33.299 58.2 34.067 ;
     RECT  2.4 33.637 3 34.165 ;
     RECT  51 34.067 51.312 34.165 ;
     RECT  59.328 33.299 59.352 34.355 ;
     RECT  2.4 34.165 3.384 34.693 ;
     RECT  1.776 34.693 3.384 34.741 ;
     RECT  31.056 33.395 35.208 34.741 ;
     RECT  52.896 34.067 58.2 35.077 ;
     RECT  52.896 35.077 58.872 35.123 ;
     RECT  1.68 34.741 3.384 35.317 ;
     RECT  52.896 35.123 57.624 35.363 ;
     RECT  50.88 34.165 51.312 35.701 ;
     RECT  30.912 34.741 35.208 35.989 ;
     RECT  45.168 29.075 45.912 35.989 ;
     RECT  46.896 31.619 46.92 35.989 ;
     RECT  54.048 35.363 57.624 36.083 ;
     RECT  0.72 35.317 3.384 36.373 ;
     RECT  4.704 33.445 13.656 36.373 ;
     RECT  50.832 35.701 51.312 36.421 ;
     RECT  58.848 35.123 58.872 36.467 ;
     RECT  52.896 35.363 52.92 36.469 ;
     RECT  54.048 36.083 56.712 36.469 ;
     RECT  17.472 32.531 29.712 36.517 ;
     RECT  30.912 35.989 35.256 36.517 ;
     RECT  50.016 36.421 51.312 36.517 ;
     RECT  49.488 36.517 51.912 36.901 ;
     RECT  37.92 30.275 37.944 36.949 ;
     RECT  52.896 36.469 56.712 37.043 ;
     RECT  52.896 37.043 54.648 37.379 ;
     RECT  55.92 37.043 56.712 37.427 ;
     RECT  56.256 37.427 56.712 37.475 ;
     RECT  14.688 32.531 16.296 37.621 ;
     RECT  17.472 36.517 35.256 37.621 ;
     RECT  49.44 36.901 51.912 37.621 ;
     RECT  49.296 37.621 51.912 37.667 ;
     RECT  52.896 37.379 54.216 37.667 ;
     RECT  37.92 36.949 38.52 38.149 ;
     RECT  48 37.909 48.024 38.197 ;
     RECT  49.296 37.667 49.512 38.197 ;
     RECT  56.4 37.475 56.712 38.197 ;
     RECT  50.784 37.667 51.912 38.243 ;
     RECT  56.4 38.197 57.192 38.245 ;
     RECT  52.896 37.667 54.072 38.387 ;
     RECT  45.168 35.989 46.92 38.483 ;
     RECT  56.4 38.245 57.576 38.533 ;
     RECT  48 38.197 49.512 38.725 ;
     RECT  47.568 38.725 49.512 38.771 ;
     RECT  0.72 36.373 13.656 38.819 ;
     RECT  14.688 37.621 35.256 38.915 ;
     RECT  55.584 38.533 57.576 39.205 ;
     RECT  61.8 33.251 62.112 39.301 ;
     RECT  5.904 38.819 13.656 39.395 ;
     RECT  43.392 31.955 43.848 39.397 ;
     RECT  45.168 38.483 46.248 39.397 ;
     RECT  37.92 38.149 38.616 39.493 ;
     RECT  40.2 30.467 40.512 39.829 ;
     RECT  42 39.781 42.024 39.829 ;
     RECT  47.568 38.771 47.592 39.877 ;
     RECT  48.912 38.771 49.512 39.877 ;
     RECT  43.392 39.397 46.248 40.019 ;
     RECT  40.2 39.829 42.024 40.261 ;
     RECT  43.392 40.019 44.52 40.261 ;
     RECT  45.6 40.019 46.248 40.309 ;
     RECT  47.568 39.877 49.512 40.309 ;
     RECT  0.72 38.819 4.872 40.405 ;
     RECT  5.904 39.395 6.216 40.405 ;
     RECT  50.784 38.243 51.312 40.405 ;
     RECT  7.248 39.395 13.656 40.453 ;
     RECT  14.688 38.915 15.096 40.453 ;
     RECT  16.128 38.915 35.256 40.453 ;
     RECT  37.92 39.493 38.76 40.453 ;
     RECT  45.6 40.309 49.512 40.453 ;
     RECT  50.784 40.405 52.104 40.453 ;
     RECT  53.808 38.387 54.072 40.453 ;
     RECT  55.584 39.205 57.96 40.453 ;
     RECT  59.568 40.405 59.592 40.453 ;
     RECT  60.816 39.301 62.112 40.453 ;
     RECT  7.248 40.453 36.072 40.501 ;
     RECT  40.2 40.261 44.52 40.549 ;
     RECT  7.248 40.501 36.168 40.597 ;
     RECT  37.488 40.453 38.76 40.597 ;
     RECT  40.08 40.549 44.52 40.597 ;
     RECT  7.248 40.597 38.76 40.645 ;
     RECT  39.984 40.597 44.52 40.645 ;
     RECT  45.6 40.453 57.96 40.741 ;
     RECT  59.472 40.453 62.112 40.741 ;
     RECT  0.72 40.405 6.216 40.789 ;
     RECT  7.248 40.645 44.52 40.789 ;
     RECT  45.6 40.741 62.112 41.049 ;
     RECT  45.6 41.049 61.92 41.063 ;
     RECT  0.72 40.789 44.52 41.605 ;
     RECT  0.72 41.605 44.616 42.085 ;
     RECT  0.72 42.085 44.712 42.133 ;
     RECT  45.744 41.063 60.84 42.133 ;
     RECT  0.72 42.133 60.936 43.152 ;
     RECT  19.08 1.763 20.208 1.955 ;
     RECT  45.96 1.763 47.184 1.811 ;
     RECT  15.912 1.811 17.232 3.109 ;
     RECT  45.912 1.811 47.184 2.339 ;
     RECT  38.184 1.859 39.216 1.955 ;
     RECT  36.072 1.907 37.104 1.955 ;
     RECT  37.128 1.907 38.16 1.955 ;
     RECT  18.912 1.955 20.208 3.109 ;
     RECT  36.072 1.955 36.504 3.301 ;
     RECT  21.192 2.099 22.224 2.195 ;
     RECT  60.744 2.137 61.8 2.291 ;
     RECT  28.2 2.195 29.28 3.301 ;
     RECT  26.52 2.243 27.504 2.339 ;
     RECT  41.064 2.291 42.576 4.595 ;
     RECT  60.552 2.291 61.8 3.443 ;
     RECT  26.52 2.339 28.08 3.445 ;
     RECT  47.664 2.339 48 3.397 ;
     RECT  5.448 2.915 6.864 3.877 ;
     RECT  33.336 2.963 34.56 4.261 ;
     RECT  30.456 3.059 31.728 4.213 ;
     RECT  16.536 3.203 17.76 5.747 ;
     RECT  2.712 3.443 3.888 5.171 ;
     RECT  52.2 3.443 53.232 4.019 ;
     RECT  59.688 3.443 61.8 3.541 ;
     RECT  27.048 3.445 28.08 3.539 ;
     RECT  23.28 3.491 24 4.405 ;
     RECT  27.048 3.539 28.944 4.405 ;
     RECT  59.688 3.541 61.008 4.837 ;
     RECT  36.504 3.637 37.968 6.709 ;
     RECT  45.912 3.877 46.896 3.925 ;
     RECT  9.288 4.019 10.8 4.595 ;
     RECT  52.2 4.019 53.28 6.133 ;
     RECT  22.632 4.405 24 5.461 ;
     RECT  27.864 4.405 28.944 5.125 ;
     RECT  3.912 4.595 5.04 5.171 ;
     RECT  9.288 4.595 9.336 5.125 ;
     RECT  14.136 4.595 15.696 5.171 ;
     RECT  30.888 4.595 31.968 6.229 ;
     RECT  43.368 4.691 44.352 5.123 ;
     RECT  59.784 4.837 61.008 9.157 ;
     RECT  43.368 5.123 44.64 6.323 ;
     RECT  2.712 5.171 3 6.037 ;
     RECT  11.4 5.171 12.768 6.133 ;
     RECT  15.264 5.171 15.696 5.653 ;
     RECT  5.136 5.219 5.904 6.277 ;
     RECT  40.512 5.315 40.872 6.229 ;
     RECT  19.752 5.989 20.88 6.661 ;
     RECT  11.4 6.133 12.624 6.323 ;
     RECT  40.512 6.229 41.856 9.685 ;
     RECT  41.88 6.229 43.008 8.003 ;
     RECT  19.752 6.661 20.832 6.899 ;
     RECT  20.904 6.805 21.888 12.517 ;
     RECT  30.888 6.851 31.968 7.043 ;
     RECT  19.656 6.899 20.832 7.475 ;
     RECT  30.744 7.043 31.968 10.261 ;
     RECT  13.512 7.429 14.688 16.213 ;
     RECT  19.56 7.475 20.832 14.917 ;
     RECT  16.104 7.957 17.472 12.275 ;
     RECT  41.88 8.003 41.976 9.253 ;
     RECT  27.864 8.099 29.088 8.771 ;
     RECT  37.992 8.389 39.264 8.531 ;
     RECT  39.888 8.531 40.2 9.493 ;
     RECT  27.864 8.771 29.232 10.069 ;
     RECT  0.144 8.819 0.168 9.829 ;
     RECT  59.832 9.157 61.008 9.491 ;
     RECT  12.624 9.395 13.056 10.597 ;
     RECT  59.784 9.491 61.008 15.251 ;
     RECT  33.528 9.731 34.56 11.555 ;
     RECT  0.144 10.019 0.168 11.221 ;
     RECT  27.864 10.069 29.088 10.211 ;
     RECT  27.864 10.211 29.232 11.413 ;
     RECT  30.84 10.261 31.968 11.411 ;
     RECT  40.512 10.307 41.856 10.883 ;
     RECT  58.2 10.307 59.28 13.525 ;
     RECT  11.688 10.597 13.056 12.997 ;
     RECT  11.04 10.931 11.664 11.125 ;
     RECT  10.296 11.125 11.664 11.267 ;
     RECT  30.744 11.411 31.968 12.517 ;
     RECT  27.864 11.413 28.944 11.747 ;
     RECT  33.384 11.555 34.56 14.197 ;
     RECT  27.864 11.747 29.28 13.141 ;
     RECT  15.72 12.275 17.472 13.333 ;
     RECT  11.736 12.997 13.056 16.019 ;
     RECT  27.864 13.141 29.184 13.285 ;
     RECT  27.864 13.285 29.136 13.715 ;
     RECT  16.152 13.333 17.472 14.629 ;
     RECT  58.2 13.667 59.28 13.715 ;
     RECT  27.864 13.715 29.184 14.821 ;
     RECT  58.2 13.715 59.424 18.275 ;
     RECT  30.504 14.003 31.968 17.507 ;
     RECT  16.152 14.629 17.232 14.821 ;
     RECT  27.864 14.821 28.992 15.395 ;
     RECT  19.608 14.917 20.832 17.077 ;
     RECT  59.592 15.251 61.008 27.205 ;
     RECT  27.864 15.395 29.184 16.693 ;
     RECT  12.24 16.019 13.056 16.789 ;
     RECT  40.512 16.019 40.632 16.501 ;
     RECT  40.512 16.501 42.048 17.077 ;
     RECT  27.864 16.693 28.896 17.123 ;
     RECT  27.864 17.123 29.4 17.605 ;
     RECT  33.384 17.267 34.56 17.411 ;
     RECT  40.512 17.315 41.664 19.475 ;
     RECT  45.912 17.315 46.896 20.341 ;
     RECT  33.336 17.411 34.56 18.227 ;
     RECT  29.712 17.507 31.968 17.653 ;
     RECT  28.152 17.605 29.4 18.805 ;
     RECT  29.712 17.653 30.72 19.235 ;
     RECT  30.744 17.653 31.968 19.235 ;
     RECT  33.144 18.227 34.56 22.069 ;
     RECT  58.2 18.275 59.472 28.931 ;
     RECT  19.608 18.371 20.832 19.381 ;
     RECT  13.512 18.899 14.688 19.909 ;
     RECT  28.152 18.947 29.4 20.819 ;
     RECT  19.608 19.859 20.832 21.973 ;
     RECT  37.992 19.909 39.36 20.579 ;
     RECT  16.296 20.387 17.472 25.237 ;
     RECT  27.864 20.819 29.4 21.109 ;
     RECT  3.576 20.821 4.704 21.493 ;
     RECT  0.144 21.059 0.168 22.357 ;
     RECT  27.864 21.109 28.896 21.251 ;
     RECT  13.512 21.395 14.688 22.453 ;
     RECT  3.576 21.731 4.704 22.741 ;
     RECT  19.608 21.973 20.64 22.117 ;
     RECT  33.144 22.069 34.128 23.987 ;
     RECT  19.608 22.117 20.592 22.789 ;
     RECT  37.992 22.405 39.024 23.171 ;
     RECT  39.048 22.405 40.2 23.171 ;
     RECT  13.656 22.453 14.688 22.931 ;
     RECT  43.848 22.597 45.168 23.461 ;
     RECT  3.576 22.883 4.704 22.931 ;
     RECT  13.512 22.931 14.688 33.445 ;
     RECT  42.408 23.317 43.824 23.557 ;
     RECT  42.408 23.557 43.392 23.605 ;
     RECT  43.848 23.795 45.12 23.939 ;
     RECT  43.848 23.939 45.168 25.093 ;
     RECT  33.144 23.987 34.56 26.101 ;
     RECT  45.912 23.987 46.896 24.949 ;
     RECT  19.608 24.659 20.832 27.205 ;
     RECT  28.2 25.043 29.4 26.101 ;
     RECT  43.848 25.093 45.024 26.149 ;
     RECT  26.52 25.571 27.84 27.349 ;
     RECT  45.912 25.619 46.896 27.349 ;
     RECT  28.392 26.101 29.4 26.245 ;
     RECT  33.144 26.101 34.368 26.197 ;
     RECT  36.84 26.579 37.92 30.563 ;
     RECT  37.992 26.629 39.312 27.875 ;
     RECT  48.216 26.771 49.44 30.563 ;
     RECT  44.184 27.155 45.168 31.955 ;
     RECT  59.976 27.205 61.008 27.779 ;
     RECT  59.592 27.779 61.008 32.243 ;
     RECT  19.608 28.115 20.832 30.709 ;
     RECT  58.2 28.931 59.568 31.861 ;
     RECT  30.024 28.933 31.536 29.171 ;
     RECT  35.448 29.027 36.48 29.459 ;
     RECT  45.912 29.075 46.896 35.989 ;
     RECT  26.52 29.171 28.08 30.181 ;
     RECT  30.024 29.171 31.968 30.181 ;
     RECT  35.448 29.459 36.816 30.275 ;
     RECT  30.024 30.181 31.296 30.803 ;
     RECT  35.304 30.275 36.816 30.563 ;
     RECT  37.944 30.275 37.992 30.949 ;
     RECT  47.976 30.563 49.44 30.803 ;
     RECT  19.752 30.709 20.832 30.757 ;
     RECT  19.848 30.757 20.832 31.381 ;
     RECT  37.944 30.949 39.12 31.955 ;
     RECT  39.144 30.949 40.2 31.955 ;
     RECT  46.92 31.619 47.952 32.771 ;
     RECT  29.712 31.955 30.024 33.013 ;
     RECT  43.848 31.955 45.168 39.397 ;
     RECT  58.632 32.243 59.352 33.253 ;
     RECT  16.296 32.531 17.472 37.621 ;
     RECT  29.712 33.013 31.056 34.741 ;
     RECT  58.2 33.299 59.328 34.355 ;
     RECT  13.656 33.445 14.688 40.453 ;
     RECT  3.384 34.165 4.704 36.373 ;
     RECT  58.2 34.355 58.872 35.077 ;
     RECT  29.712 34.741 30.912 36.517 ;
     RECT  57.624 35.123 58.848 36.083 ;
     RECT  52.92 35.363 54.048 36.469 ;
     RECT  51.912 36.517 52.896 38.243 ;
     RECT  54.648 37.043 55.92 37.379 ;
     RECT  54.216 37.379 55.92 37.427 ;
     RECT  54.216 37.427 56.256 37.475 ;
     RECT  54.216 37.475 56.4 37.667 ;
     RECT  49.512 37.667 50.784 40.453 ;
     RECT  54.072 37.667 56.4 38.533 ;
     RECT  46.92 37.909 48 38.483 ;
     RECT  48.024 37.909 49.296 38.197 ;
     RECT  46.248 38.483 48 38.725 ;
     RECT  54.072 38.533 55.584 40.453 ;
     RECT  46.248 38.725 47.568 40.309 ;
     RECT  47.592 38.771 48.912 39.877 ;
     RECT  4.872 38.819 5.904 40.405 ;
     RECT  15.096 38.915 16.128 40.453 ;
     RECT  6.216 39.395 7.248 40.789 ;
     RECT  38.76 39.493 40.2 40.549 ;
     RECT  40.512 39.781 42 39.829 ;
     RECT  42.024 39.781 43.392 40.261 ;
     RECT  44.52 40.019 45.6 41.063 ;
     RECT  59.592 40.405 60.816 40.453 ;
     RECT  36.072 40.453 37.488 40.501 ;
     RECT  57.96 40.453 59.472 40.741 ;
     RECT  36.168 40.501 37.488 40.597 ;
     RECT  38.76 40.549 40.08 40.597 ;
     RECT  38.76 40.597 39.984 40.645 ;
     RECT  44.52 41.063 45.744 41.605 ;
     RECT  60.84 41.063 60.936 42.133 ;
     RECT  44.616 41.605 45.744 42.085 ;
     RECT  44.712 42.085 45.744 42.133 ;
  END
END ot_hgi_b2_dma_kface
END LIBRARY
